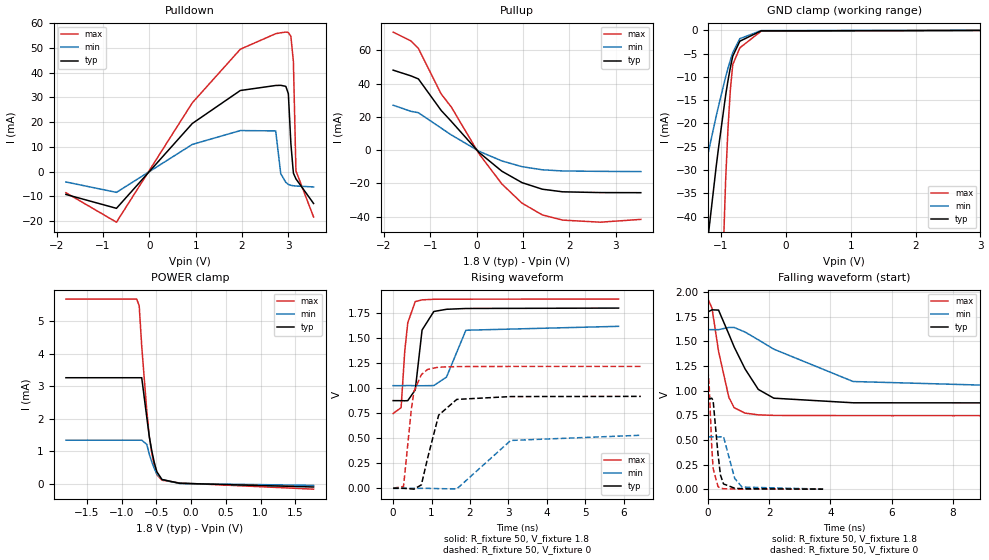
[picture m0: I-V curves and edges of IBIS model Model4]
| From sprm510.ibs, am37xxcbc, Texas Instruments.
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| Model based on original model for BQ18OMAPJTAGFBPBNOPM_SSBHV
|   Sub model AGFBPBNOPM_VJTAG_PU1_1P8
[model]   Model4
|[Input Load]   PU
|[Output Drive]
|Voltage   1.8V
|Mode   I/O
Model_type   I/O
Polarity   Non-Inverting
Enable   Active-Low
Vinl =  0.63
Vinh =  1.17
Cref =  15pF
Rref =  100.0000M
Vref =  0V
Vmeas =  0.9
C_comp   2.132351p   1.924211p   2.13513p
[Model Spec]
Vinl   0.63   0.567   0.6615
Vinh   1.17   1.053   1.2285
[Temperature Range]   25   125   -40
[Voltage Range]   1.8   1.62   1.89
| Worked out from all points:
|   slope of the pulldown table from 0 to 0.27 V, typ, clamps not added: 43.9 ohm
|   slope of the pullup table from 0 to 0.27 V, typ, clamps not added: 39.4 ohm
|   GND clamp passes 1 mA (typ) near -0.60 V on its own axis
|   POWER clamp passes 1 mA (typ) near -0.56 V on its own axis
|   rising waveform, R_fixture 50, V_fixture 1.8: 20-80 % time 173ps typ, 302ps min, 137ps max; typ from 0.877 V to 1.8 V
|   rising waveform, R_fixture 50, V_fixture 0: 20-80 % time 356ps typ, 726ps min, 202ps max; typ from 0.002 V to 0.919 V
|   falling waveform, R_fixture 50, V_fixture 1.8: 20-80 % time 894ps typ, 2.32ns min, 434ps max; typ from 1.8 V to 0.877 V
|   falling waveform, R_fixture 50, V_fixture 0: 20-80 % time 162ps typ, 255ps min, 107ps max; typ from 0.919 V to 0.002 V
[POWER_clamp]
-1.8V     3.257mA    1.34mA     5.672mA
-781.8mV  3.257mA    1.34mA     5.672mA
-745.5mV  3.257mA    1.34mA     5.469mA
-709.1mV  3.257mA    1.34mA     4.227mA
-636.4mV  2.042mA    1.213mA    2.249mA
-600mV    1.445mA    904.9uA    1.448mA
-563.6mV  1.004mA    669uA      930.8uA
-527.3mV  646uA      469.2uA    541.5uA
-490.9mV  370.3uA    305.7uA    280uA
-418.2mV  134uA      130.2uA    111.3uA
-163.6mV  16.99uA    9.907uA    26.3uA
1.764V    -96.73uA   -46.49uA   -163.5uA
[Pulldown]
-1.8V     -9.247mA   -4.208mA   -8.543mA
-709.1mV  -14.86mA   -8.413mA   -20.46mA
927.3mV   19.42mA    10.96mA    27.78mA
1.964V    32.76mA    16.57mA    49.44mA
2.727V    34.78mA    16.43mA    55.71mA
2.836V    34.85mA    -845.8uA   56.09mA
2.945V    34.44mA    -4.342mA   56.36mA
3V        31.5mA     -5.193mA   56.19mA
3.055V    11.25mA    -5.559mA   54.62mA
3.109V    -628.6uA   -5.735mA   44.43mA
3.164V    -2.953mA   -5.847mA   273.1uA
3.545V    -12.91mA   -6.213mA   -18.39mA
[Pullup]
-1.8V     48.03mA    26.96mA    70.92mA
-1.418V   44.61mA    23.28mA    65.63mA
-1.255V   42.76mA    22.44mA    61.09mA
-763.6mV  23.81mA    13.18mA    33.71mA
-545.5mV  17.24mA    9.103mA    25.87mA
54.55mV   -1.471mA   -757.8uA   -2.314mA
545.5mV   -12.73mA   -6.543mA   -20.39mA
981.8mV   -19.62mA   -10.01mA   -31.96mA
1.418V    -23.55mA   -11.89mA   -39.01mA
1.855V    -25.13mA   -12.59mA   -42.14mA
2.673V    -25.59mA   -12.83mA   -43.4mA
3.545V    -25.66mA   -12.97mA   -41.71mA
[GND_clamp]
-1.8V     -118.7mA   -65.68mA   -455.2mA
-1.509V   -82.26mA   -46.44mA   -309.2mA
-1.473V   -77.72mA   -44.04mA   -290.9mA
-1.073V   -29.19mA   -18.4mA    -94.45mA
-1.036V   -25.09mA   -16.2mA    -77.63mA
-927.3mV  -13.89mA   -9.97mA    -31.99mA
-890.9mV  -10.74mA   -8.111mA   -20.87mA
-854.5mV  -7.952mA   -6.381mA   -12.65mA
-818.2mV  -5.535mA   -4.78mA    -7.354mA
-709.1mV  -2.342mA   -1.793mA   -3.761mA
-381.8mV  -111.3uA   -60.58uA   -193uA
3.6V      0A         0A         0A
[Ramp]
dV/dt_f  0.5746399/0.9125157n  0.3697848/2.387573n   0.7100328/0.4338732n
dV/dt_r  0.5563546/0.3576548n  0.3227059/0.7351233n  0.7364765/0.2020738n
R_load = 50
[Rising Waveform]
R_fixture = 50
V_fixture = 1.8
V_fixture_min = 1.62
V_fixture_max = 1.89
0s        876.5mV    1.026V     747.7mV
207ps     876.2mV    1.026V     806.7mV
303ps     875.2mV    1.026V     1.372V
381ps     876.4mV    1.027V     1.654V
576ps     984.4mV    1.026V     1.865V
753ps     1.581V     1.025V     1.882V
1.059ns   1.766V     1.027V     1.888V
1.389ns   1.788V     1.112V     1.889V
1.893ns   1.796V     1.579V     1.889V
5.868ns   1.8V       1.618V     1.89V
[Rising Waveform]
R_fixture = 50
V_fixture = 0
V_fixture_min = 0
V_fixture_max = 0
0s        1.815mV    1.469mV    3.195mV
270ps     2.212mV    910.5uV    19.59mV
474ps     -4.257mV   1.476mV    791.6mV
543ps     -6.854mV   1.475mV    971.2mV
735ps     35.97mV    1.456mV    1.136V
897ps     302.6mV    1.234mV    1.188V
1.185ns   731.9mV    -1.57mV    1.211V
1.656ns   888.8mV    -4.47mV    1.216V
3.06ns    917.1mV    479.2mV    1.218V
6.447ns   918.9mV    531.1mV    1.218V
[Falling Waveform]
R_fixture = 50
V_fixture = 1.8
V_fixture_min = 1.62
V_fixture_max = 1.89
0s        1.8V       1.62V      1.93V
132ps     1.821V     1.62V      1.837V
345ps     1.818V     1.62V      1.401V
681ps     1.575V     1.642V     933.9mV
855ps     1.445V     1.642V     828.5mV
1.209ns   1.223V     1.596V     773.8mV
1.644ns   1.014V     1.517V     756mV
2.151ns   924.9mV    1.422V     750.5mV
4.743ns   878.3mV    1.094V     748mV
12.36ns   876.9mV    1.028V     748mV
[Falling Waveform]
R_fixture = 50
V_fixture = 0
V_fixture_min = 0
V_fixture_max = 0
0s        919.5mV    532.6mV    1.21V
39ps      918.8mV    532.6mV    1.056V
123ps     924.2mV    533.1mV    434.9mV
168ps     901.7mV    533.1mV    211.8mV
327ps     358.5mV    532.2mV    28.76mV
408ps     145.7mV    532.8mV    12.27mV
507ps     55.59mV    534.8mV    6.985mV
873ps     12.03mV    111.5mV    4.056mV
1.113ns   7.194mV    23.57mV    3.58mV
3.762ns   2.486mV    2.997mV    3.099mV
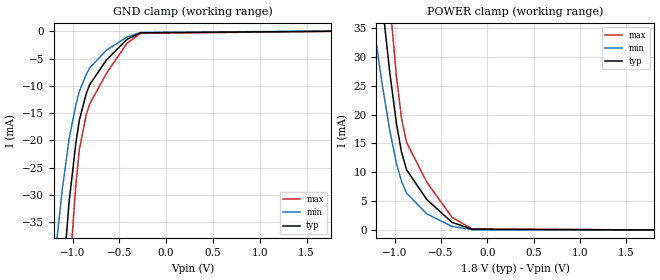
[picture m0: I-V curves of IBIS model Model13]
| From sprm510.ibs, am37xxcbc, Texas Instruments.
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| Model based on original model for CAMERARX_ADDON
|   Sub model CAMERARX_ADDON_PU_ON
[model]   Model13
|[Input Load]   PU
|[Output Drive]
|Voltage   1.8V
|Mode   INPUT
Model_type   Input
Polarity   Non-Inverting
Vinl =  0.63
Vinh =  1.17
C_comp   4.13955p   3.54298p   4.784869p
[Model Spec]
Vinl   0.63   0.567   0.6615
Vinh   1.17   1.053   1.2285
[Temperature Range]   25   125   -40
[Voltage Range]   1.8   1.62   1.92
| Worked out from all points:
|   GND clamp passes 1 mA (typ) near -0.38 V on its own axis
|   POWER clamp passes 1 mA (typ) near -0.35 V on its own axis
[POWER_clamp]
-1.8V     156.8mA    109.4mA    217.7mA
-1.255V   58.61mA    38.51mA    83.66mA
-1.145V   40.75mA    26.16mA    58.76mA
-1.127V   37.98mA    24.3mA     54.84mA
-1.055V   27.39mA    17.29mA    39.72mA
-981.8mV  18.38mA    11.52mA    26.53mA
-927.3mV  13.5mA     8.445mA    19.35mA
-872.7mV  10.44mA    6.378mA    15.17mA
-654.5mV  5.285mA    2.795mA    8.314mA
-381.8mV  1.322mA    633.7uA    2.193mA
-163.6mV  122.8uA    43.53uA    168.5uA
1.8V      2.655uA    1.447uA    5.48uA
[GND_clamp]
-1.8V     -252.1mA   -161mA     -379.9mA
-1.218V   -75mA      -46.17mA   -113.7mA
-1.109V   -46.69mA   -28.88mA   -69.61mA
-1.036V   -31.09mA   -19.64mA   -44.94mA
-963.6mV  -20.36mA   -13.4mA    -27.99mA
-927.3mV  -16.27mA   -11.01mA   -21.66mA
-854.5mV  -11.47mA   -7.931mA   -15.36mA
-818.2mV  -9.795mA   -6.755mA   -13.38mA
-636.4mV  -5.234mA   -3.435mA   -7.67mA
-418.2mV  -1.474mA   -1.064mA   -2.21mA
-272.7mV  -280.2uA   -224.3uA   -378.2uA
1.764V    -2.246uA   34.26uA    -17.44uA
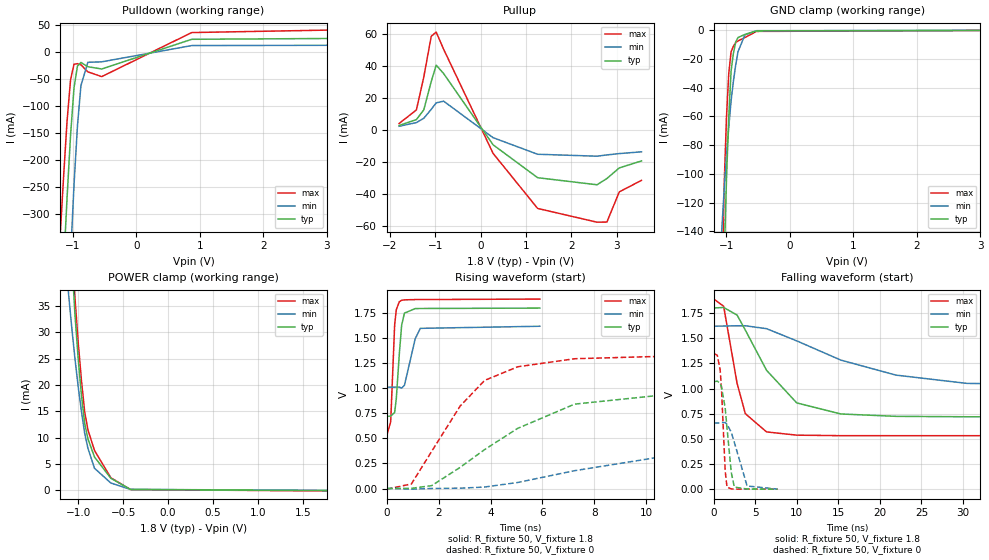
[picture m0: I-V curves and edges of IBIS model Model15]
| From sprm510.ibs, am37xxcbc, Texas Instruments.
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| Model based on original model for BQ18OMAPSMART1HYFBPBNOPM_SSBHH
|   Sub model NOPM_HS00L00_PU1_1P8
[model]   Model15
|[Input Load]   PU
|[Output Drive] SC00LB00
|Voltage   1.8V
|Mode   I/O
Model_type   I/O
Polarity   Non-Inverting
Enable   Active-Low
Vinl =  0.63
Vinh =  1.17
Cref =  15pF
Rref =  100.0000M
Vref =  0V
Vmeas =  0.9
C_comp   1.410688p   1.256095p   1.577871p
[Model Spec]
Vinl   0.63   0.567   0.6615
Vinh   1.17   1.053   1.2285
[Temperature Range]   25   125   -40
[Voltage Range]   1.8   1.62   1.89
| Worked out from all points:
|   slope of the pulldown table from 0 to 0.27 V, typ, clamps not added: 24.3 ohm
|   slope of the pullup table from 0 to 0.27 V, typ, clamps not added: 29.7 ohm
|   GND clamp passes 1 mA (typ) near -0.60 V on its own axis
|   POWER clamp passes 1 mA (typ) near -0.56 V on its own axis
|   rising waveform, R_fixture 50, V_fixture 1.8: 20-80 % time 176ps typ, 306ps min, 123ps max; typ from 0.72 V to 1.8 V
|   rising waveform, R_fixture 50, V_fixture 0: 20-80 % time 4.61ns typ, 10.6ns min, 2.28ns max; typ from 0.002 V to 1.07 V
|   falling waveform, R_fixture 50, V_fixture 1.8: 20-80 % time 4.91ns typ, 12.6ns min, 1.99ns max; typ from 1.8 V to 0.72 V
|   falling waveform, R_fixture 50, V_fixture 0: 20-80 % time 734ps typ, 1.23ns min, 446ps max; typ from 1.07 V to 0.002 V
[POWER_clamp]
-1.8V     362.5mA    191.4mA    412.8mA
-1.109V   56.76mA    37.74mA    60.51mA
-1.073V   44.67mA    31.25mA    47.93mA
-1.036V   33.52mA    25.07mA    36.72mA
-1V       25.06mA    19.75mA    28.2mA
-963.6mV  18.11mA    14.99mA    20.91mA
-927.3mV  12.67mA    10.8mA     14.87mA
-890.9mV  9.734mA    7.935mA    11.44mA
-818.2mV  6.293mA    4.153mA    7.536mA
-636.4mV  2.249mA    1.342mA    2.34mA
-418.2mV  128.7uA    129.3uA    104.4uA
1.764V    -96.73uA   -46.48uA   -163.5uA
[Pulldown]
-1.8V     -1.718A    -2.61A     -1.406A
-1.2V     -527.4mA   -844.5mA   -339.9mA
-1.145V   -396mA     -683.1mA   -229.1mA
-1.091V   -269mA     -526.7mA   -127.5mA
-1.036V   -153.6mA   -378.9mA   -51.17mA
-981.8mV  -66.33mA   -245.6mA   -22.67mA
-927.3mV  -26mA      -136.2mA   -21.54mA
-872.7mV  -19.34mA   -61.98mA   -23.69mA
-763.6mV  -27.2mA    -19.05mA   -36.72mA
-545.5mV  -31.39mA   -18.17mA   -45.46mA
872.7mV   23.46mA    11.88mA    35.92mA
3.545V    25.34mA    12.51mA    41.58mA
[Pullup]
-1.8V     2.903mA    2.423mA    4.112mA
-1.418V   6.595mA    4.711mA    12.64mA
-1.255V   12.69mA    7.42mA     33.24mA
-1.091V   30.4mA     13mA       58.69mA
-981.8mV  40.63mA    17.02mA    61.3mA
-818.2mV  35.38mA    18.12mA    50.59mA
272.7mV   -9.179mA   -4.728mA   -14.55mA
1.255V    -29.75mA   -15.09mA   -48.97mA
2.564V    -34.17mA   -16.31mA   -57.57mA
2.782V    -30.25mA   -15.5mA    -57.48mA
3.055V    -23.63mA   -14.68mA   -38.61mA
3.545V    -19.25mA   -13.56mA   -31.41mA
[GND_clamp]
-1.8V     -2.82A     -1.192A    -3.165A
-1.073V   -235.8mA   -138.4mA   -192.1mA
-1.036V   -159.6mA   -110.8mA   -107.6mA
-1V       -103.8mA   -87.86mA   -60.73mA
-963.6mV  -60.04mA   -67.29mA   -29.86mA
-927.3mV  -28.26mA   -49.09mA   -14.98mA
-890.9mV  -15.95mA   -35.49mA   -11.09mA
-854.5mV  -8.198mA   -24.09mA   -8.559mA
-818.2mV  -4.99mA    -14.87mA   -7.387mA
-709.1mV  -2.858mA   -3.093mA   -5.012mA
-527.3mV  -395.6uA   -260.4uA   -751.2uA
3.6V      0A         0A         0A
[Ramp]
dV/dt_f  0.6515024/4.918272n   0.3684169/12.66708n   0.8176591/1.98921n
dV/dt_r  0.6487164/4.619935n   0.3995157/10.69377n   0.8193791/2.289463n
R_load = 50
[Rising Waveform]
R_fixture = 50
V_fixture = 1.8
V_fixture_min = 1.62
V_fixture_max = 1.89
0s        720mV      1.011V     534.4mV
144ps     722.2mV    1.011V     666.2mV
297ps     758.3mV    1.011V     1.631V
360ps     894.2mV    1.012V     1.783V
477ps     1.342V     1.011V     1.863V
567ps     1.628V     1.001V     1.877V
675ps     1.749V     1.029V     1.881V
1.089ns   1.794V     1.492V     1.884V
1.287ns   1.795V     1.597V     1.884V
5.904ns   1.799V     1.618V     1.889V
[Rising Waveform]
R_fixture = 50
V_fixture = 0
V_fixture_min = 0
V_fixture_max = 0
0s        1.996mV    1.034mV    -5.726mV
945ps     2.248mV    -6.159mV   46.23mV
1.728ns   29mV       503.3uV    371.7mV
2.826ns   211.4mV    3.572mV    822.5mV
3.771ns   388.7mV    15.21mV    1.078V
5.049ns   600.2mV    60.39mV    1.214V
7.245ns   841.7mV    178.1mV    1.294V
14.15ns   1.026V     463.3mV    1.344V
23.34ns   1.062V     596.7mV    1.35V
67.5ns    1.069V     657.1mV    1.35V
[Falling Waveform]
R_fixture = 50
V_fixture = 1.8
V_fixture_min = 1.62
V_fixture_max = 1.89
0s        1.8V       1.62V      1.889V
1.188ns   1.806V     1.621V     1.818V
2.808ns   1.73V      1.624V     1.052V
3.798ns   1.581V     1.624V     751.3mV
6.354ns   1.182V     1.595V     570.2mV
9.99ns    858.2mV    1.474V     537.9mV
15.3ns    748.3mV    1.283V     532.9mV
21.94ns   724.8mV    1.134V     532.6mV
30.47ns   720.5mV    1.052V     532.6mV
62.9ns    720mV      1.012V     532.6mV
[Falling Waveform]
R_fixture = 50
V_fixture = 0
V_fixture_min = 0
V_fixture_max = 0
0s        1.069V     658.7mV    1.35V
432ps     1.074V     658.5mV    1.33V
765ps     1.052V     660.3mV    1.188V
927ps     1.019V     663.9mV    1.002V
1.377ns   805.3mV    662.4mV    180mV
1.593ns   611.4mV    647.3mV    22.62mV
2.106ns   168.8mV    566.8mV    4.547mV
2.475ns   22.28mV    466.6mV    3.177mV
4.014ns   3.278mV    33.24mV    2.159mV
7.677ns   1.791mV    2.593mV    1.84mV
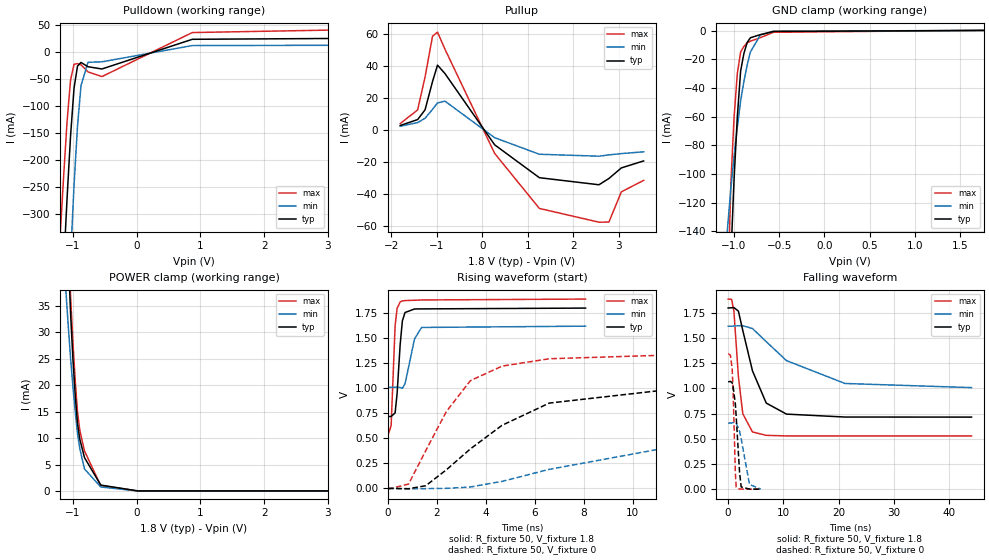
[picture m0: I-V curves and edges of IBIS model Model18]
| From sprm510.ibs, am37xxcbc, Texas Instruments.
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| Model based on original model for BQ18OMAPSMART1HYFBPBNOPM_SSBHH
|   Sub model NOPM_HS00L01_PD1_1P8
[model]   Model18
|[Input Load]   PD
|[Output Drive] SC00LB01
|Voltage   1.8V
|Mode   I/O
Model_type   I/O
Polarity   Non-Inverting
Enable   Active-Low
Vinl =  0.63
Vinh =  1.17
Cref =  15pF
Rref =  100.0000M
Vref =  0V
Vmeas =  0.9
C_comp   1.410688p   1.256095p   1.577871p
[Model Spec]
Vinl   0.63   0.567   0.6615
Vinh   1.17   1.053   1.2285
[Temperature Range]   25   125   -40
[Voltage Range]   1.8   1.62   1.89
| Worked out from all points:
|   slope of the pulldown table from 0 to 0.27 V, typ, clamps not added: 24.3 ohm
|   slope of the pullup table from 0 to 0.27 V, typ, clamps not added: 29.7 ohm
|   GND clamp passes 1 mA (typ) near -0.60 V on its own axis
|   POWER clamp passes 1 mA (typ) near -0.55 V on its own axis
|   rising waveform, R_fixture 50, V_fixture 1.8: 20-80 % time 177ps typ, 312ps min, 124ps max; typ from 0.715 V to 1.8 V
|   rising waveform, R_fixture 50, V_fixture 0: 20-80 % time 4.11ns typ, 9.41ns min, 2.06ns max; typ from 0.001 V to 1.06 V
|   falling waveform, R_fixture 50, V_fixture 1.8: 20-80 % time 3.36ns typ, 8.79ns min, 1.24ns max; typ from 1.8 V to 0.715 V
|   falling waveform, R_fixture 50, V_fixture 0: 20-80 % time 712ps typ, 1.2ns min, 410ps max; typ from 1.06 V to 0 V
[POWER_clamp]
-1.8V     362.5mA    191.4mA    412.8mA
-1.109V   56.75mA    37.73mA    60.5mA
-1.073V   44.66mA    31.25mA    47.93mA
-1.036V   33.51mA    25.07mA    36.73mA
-1V       25.06mA    19.75mA    28.2mA
-963.6mV  18.11mA    14.99mA    20.92mA
-927.3mV  12.68mA    10.81mA    14.88mA
-890.9mV  9.743mA    7.94mA     11.46mA
-818.2mV  6.308mA    4.161mA    7.567mA
-563.6mV  1.112mA    743.5uA    1.008mA
18.18mV   0A         0A         0A
3.6V      0A         0A         0A
[Pulldown]
-1.8V     -1.718A    -2.61A     -1.406A
-1.2V     -527.4mA   -844.5mA   -339.9mA
-1.145V   -396mA     -683.1mA   -229.1mA
-1.091V   -269mA     -526.7mA   -127.5mA
-1.036V   -153.6mA   -378.9mA   -51.17mA
-981.8mV  -66.33mA   -245.6mA   -22.67mA
-927.3mV  -26mA      -136.2mA   -21.54mA
-872.7mV  -19.34mA   -61.98mA   -23.69mA
-763.6mV  -27.2mA    -19.05mA   -36.72mA
-545.5mV  -31.39mA   -18.17mA   -45.46mA
872.7mV   23.46mA    11.88mA    35.92mA
3.545V    25.34mA    12.51mA    41.58mA
[Pullup]
-1.8V     2.903mA    2.423mA    4.112mA
-1.418V   6.595mA    4.711mA    12.64mA
-1.255V   12.69mA    7.42mA     33.24mA
-1.091V   30.4mA     13mA       58.69mA
-981.8mV  40.63mA    17.02mA    61.3mA
-818.2mV  35.38mA    18.12mA    50.59mA
272.7mV   -9.18mA    -4.728mA   -14.55mA
1.255V    -29.75mA   -15.09mA   -48.97mA
2.564V    -34.17mA   -16.31mA   -57.57mA
2.782V    -30.25mA   -15.5mA    -57.48mA
3.055V    -23.63mA   -14.68mA   -38.61mA
3.545V    -19.25mA   -13.56mA   -31.41mA
[GND_clamp]
-1.8V     -2.82A     -1.192A    -3.165A
-1.073V   -235.8mA   -138.4mA   -192.1mA
-1.036V   -159.6mA   -110.8mA   -107.6mA
-1V       -103.8mA   -87.86mA   -60.72mA
-963.6mV  -60.04mA   -67.29mA   -29.85mA
-927.3mV  -28.26mA   -49.1mA    -14.96mA
-890.9mV  -15.95mA   -35.5mA    -11.07mA
-854.5mV  -8.196mA   -24.09mA   -8.539mA
-818.2mV  -4.988mA   -14.87mA   -7.364mA
-709.1mV  -2.851mA   -3.095mA   -4.982mA
-563.6mV  -633.9uA   -437.8uA   -1.185mA
1.764V    107.4uA    58.81uA    171.2uA
[Ramp]
dV/dt_f  0.6526315/3.369885n   0.3693826/8.859099n   0.818574/1.242437n
dV/dt_r  0.6489843/4.119939n   0.3992363/9.491637n   0.8210471/2.063407n
R_load = 50
[Rising Waveform]
R_fixture = 50
V_fixture = 1.8
V_fixture_min = 1.62
V_fixture_max = 1.89
0s        715.4mV    1.007V     530.1mV
126ps     717.3mV    1.007V     627.3mV
288ps     752mV      1.007V     1.621V
369ps     944mV      1.009V     1.794V
495ps     1.436V     1.005V     1.859V
585ps     1.669V     997.8mV    1.869V
693ps     1.753V     1.041V     1.872V
1.08ns    1.788V     1.488V     1.875V
1.368ns   1.789V     1.604V     1.878V
8.073ns   1.797V     1.617V     1.887V
[Rising Waveform]
R_fixture = 50
V_fixture = 0
V_fixture_min = 0
V_fixture_max = 0
0s        604.6uV    68.6uV     -7.974mV
837ps     -3.335mV   -6.133mV   42.79mV
1.539ns   26.15mV    -2.748mV   375.6mV
2.385ns   185.5mV    376.8uV    767.3mV
3.366ns   393.8mV    13.56mV    1.074V
4.653ns   627.9mV    69.6mV     1.218V
6.588ns   850.1mV    189.4mV    1.292V
12.94ns   1.025V     474.1mV    1.34V
20.72ns   1.058V     594.1mV    1.346V
60.28ns   1.065V     654.3mV    1.346V
[Falling Waveform]
R_fixture = 50
V_fixture = 1.8
V_fixture_min = 1.62
V_fixture_max = 1.89
0s        1.798V     1.618V     1.887V
621ps     1.801V     1.618V     1.884V
1.035ns   1.803V     1.619V     1.77V
1.854ns   1.767V     1.622V     1.116V
2.646ns   1.575V     1.622V     749mV
4.392ns   1.175V     1.595V     568mV
6.885ns   854.4mV    1.464V     534.2mV
10.54ns   745mV      1.276V     528.6mV
21.12ns   716mV      1.049V     528.1mV
43.99ns   715.4mV    1.008V     528.1mV
[Falling Waveform]
R_fixture = 50
V_fixture = 0
V_fixture_min = 0
V_fixture_max = 0
0s        1.065V     655.9mV    1.346V
405ps     1.07V      655.7mV    1.331V
720ps     1.056V     656.9mV    1.195V
873ps     1.029V     659.8mV    1.015V
1.305ns   842.6mV    663.1mV    155.5mV
1.458ns   715.1mV    656.4mV    18.12mV
2.061ns   167.9mV    574.7mV    908.4uV
2.358ns   21.85mV    497.5mV    446.4uV
3.861ns   527.2uV    45.89mV    102.7uV
5.868ns   183.1uV    1.642mV    30.4uV
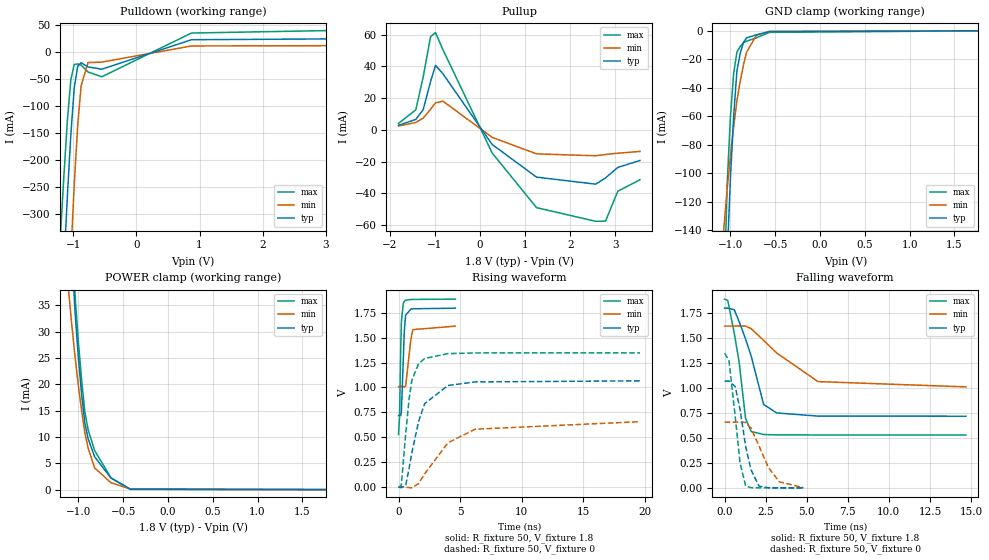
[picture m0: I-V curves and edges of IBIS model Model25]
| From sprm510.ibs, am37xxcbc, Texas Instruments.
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| Model based on original model for BQ18OMAPSMART1HYFBPBNOPM_SSBHH
|   Sub model PM_HS01L11_PUPD0_1P8
[model]   Model25
|[Input Load]   PI
|[Output Drive] SC01LB11
|Voltage   1.8V
|Mode   I/O
Model_type   I/O
Polarity   Non-Inverting
Enable   Active-Low
Vinl =  0.63
Vinh =  1.17
Cref =  15pF
Rref =  100.0000M
Vref =  0V
Vmeas =  0.9
C_comp   1.410688p   1.256095p   1.577871p
[Model Spec]
Vinl   0.63   0.567   0.6615
Vinh   1.17   1.053   1.2285
[Temperature Range]   25   125   -40
[Voltage Range]   1.8   1.62   1.89
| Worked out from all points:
|   slope of the pulldown table from 0 to 0.27 V, typ, clamps not added: 24.3 ohm
|   slope of the pullup table from 0 to 0.27 V, typ, clamps not added: 29.7 ohm
|   GND clamp passes 1 mA (typ) near -0.60 V on its own axis
|   POWER clamp passes 1 mA (typ) near -0.56 V on its own axis
|   rising waveform, R_fixture 50, V_fixture 1.8: 20-80 % time 174ps typ, 299ps min, 124ps max; typ from 0.718 V to 1.8 V
|   rising waveform, R_fixture 50, V_fixture 0: 20-80 % time 1.3ns typ, 2.86ns min, 687ps max; typ from 0 V to 1.07 V
|   falling waveform, R_fixture 50, V_fixture 1.8: 20-80 % time 1.1ns typ, 2.18ns min, 681ps max; typ from 1.8 V to 0.718 V
|   falling waveform, R_fixture 50, V_fixture 0: 20-80 % time 681ps typ, 1.11ns min, 499ps max; typ from 1.07 V to 0 V
[POWER_clamp]
-1.8V     362.5mA    191.4mA    412.8mA
-1.109V   56.69mA    37.71mA    60.38mA
-1.073V   44.6mA     31.22mA    47.8mA
-1.036V   33.44mA    25.04mA    36.59mA
-1V       24.98mA    19.72mA    28.06mA
-963.6mV  18.03mA    14.96mA    20.78mA
-927.3mV  12.59mA    10.77mA    14.74mA
-890.9mV  9.653mA    7.899mA    11.31mA
-818.2mV  6.214mA    4.114mA    7.414mA
-636.4mV  2.183mA    1.307mA    2.238mA
-418.2mV  83.85uA    105.2uA    35.14uA
1.764V    -1.228nA   -79.12nA   -1.453nA
[Pulldown]
-1.8V     -1.718A    -2.61A     -1.406A
-1.2V     -527.4mA   -844.5mA   -339.9mA
-1.145V   -396mA     -683.1mA   -229.1mA
-1.091V   -269mA     -526.7mA   -127.5mA
-1.036V   -153.6mA   -378.9mA   -51.17mA
-981.8mV  -66.34mA   -245.6mA   -22.67mA
-927.3mV  -26mA      -136.2mA   -21.54mA
-872.7mV  -19.34mA   -61.98mA   -23.69mA
-763.6mV  -27.2mA    -19.05mA   -36.72mA
-545.5mV  -31.39mA   -18.17mA   -45.46mA
872.7mV   23.46mA    11.88mA    35.92mA
3.545V    25.34mA    12.51mA    41.58mA
[Pullup]
-1.8V     2.903mA    2.423mA    4.112mA
-1.418V   6.595mA    4.711mA    12.64mA
-1.255V   12.69mA    7.42mA     33.23mA
-1.091V   30.4mA     13mA       58.69mA
-981.8mV  40.63mA    17.02mA    61.3mA
-818.2mV  35.38mA    18.12mA    50.59mA
272.7mV   -9.18mA    -4.728mA   -14.55mA
1.255V    -29.75mA   -15.09mA   -48.97mA
2.564V    -34.17mA   -16.31mA   -57.57mA
2.782V    -30.25mA   -15.5mA    -57.48mA
3.055V    -23.63mA   -14.68mA   -38.61mA
3.545V    -19.25mA   -13.56mA   -31.41mA
[GND_clamp]
-1.8V     -2.82A     -1.192A    -3.165A
-1.073V   -235.7mA   -138.4mA   -192.1mA
-1.036V   -159.5mA   -110.8mA   -107.5mA
-1V       -103.8mA   -87.85mA   -60.67mA
-963.6mV  -60mA      -67.28mA   -29.8mA
-927.3mV  -28.21mA   -49.08mA   -14.9mA
-890.9mV  -15.9mA    -35.48mA   -10.99mA
-854.5mV  -8.138mA   -24.07mA   -8.449mA
-818.2mV  -4.924mA   -14.85mA   -7.266mA
-709.1mV  -2.784mA   -3.064mA   -4.883mA
-563.6mV  -570.2uA   -404.5uA   -1.092mA
1.764V    -11.02pA   583.5nA    3.035nA
[Ramp]
dV/dt_f  0.6513344/1.098002n   0.3677355/2.193128n   0.8183624/0.6832765n
dV/dt_r  0.6509415/1.304449n   0.40075/2.881457n   0.8225269/0.6889139n
R_load = 50
[Rising Waveform]
R_fixture = 50
V_fixture = 1.8
V_fixture_min = 1.62
V_fixture_max = 1.89
0s        717.6mV    1.009V     526.6mV
81ps      719.3mV    1.009V     706.6mV
180ps     716.5mV    1.009V     1.412V
234ps     765.4mV    1.01V      1.664V
387ps     1.285V     1.01V      1.848V
468ps     1.57V      1.004V     1.867V
576ps     1.729V     1.014V     1.879V
1.008ns   1.79V      1.49V      1.886V
1.161ns   1.793V     1.583V     1.887V
4.617ns   1.799V     1.618V     1.89V
[Rising Waveform]
R_fixture = 50
V_fixture = 0
V_fixture_min = 0
V_fixture_max = 0
0s        181uV      76.19uV    -10.74mV
225ps     -9.775mV   -56.88uV   18.69mV
585ps     17.22mV    -3.882mV   536.5mV
855ps     185.7mV    -8.386mV   882.2mV
1.08ns    341mV      -10.18mV   1.073V
1.629ns   658.4mV    32.86mV    1.24V
2.124ns   837.2mV    129.8mV    1.292V
4.005ns   1.02V      442mV      1.341V
6.201ns   1.056V     579.8mV    1.348V
19.61ns   1.067V     655.8mV    1.349V
[Falling Waveform]
R_fixture = 50
V_fixture = 1.8
V_fixture_min = 1.62
V_fixture_max = 1.89
0s        1.8V       1.62V      1.89V
198ps     1.8V       1.62V      1.876V
594ps     1.783V     1.62V      1.545V
882ps     1.667V     1.621V     1.266V
1.278ns   1.49V      1.621V     695.5mV
1.62ns    1.32V      1.594V     564.1mV
2.376ns   835.5mV    1.477V     534.5mV
3.168ns   750.3mV    1.351V     530.5mV
5.688ns   718.8mV    1.064V     529.8mV
14.69ns   717.6mV    1.011V     529.8mV
[Falling Waveform]
R_fixture = 50
V_fixture = 0
V_fixture_min = 0
V_fixture_max = 0
0s        1.067V     657.3mV    1.349V
270ps     1.07V      657.4mV    1.274V
648ps     1.014V     657.7mV    714.4mV
945ps     783.4mV    661mV      246.6mV
1.287ns   411.9mV    654.3mV    16.83mV
1.611ns   179.5mV    598.2mV    1.783mV
2.097ns   17.35mV    418.7mV    219.2uV
2.664ns   1.506mV    205.7mV    23.15uV
3.33ns    333.1uV    60.45mV    2.904uV
4.806ns   48.53uV    1.651mV    443.5nV
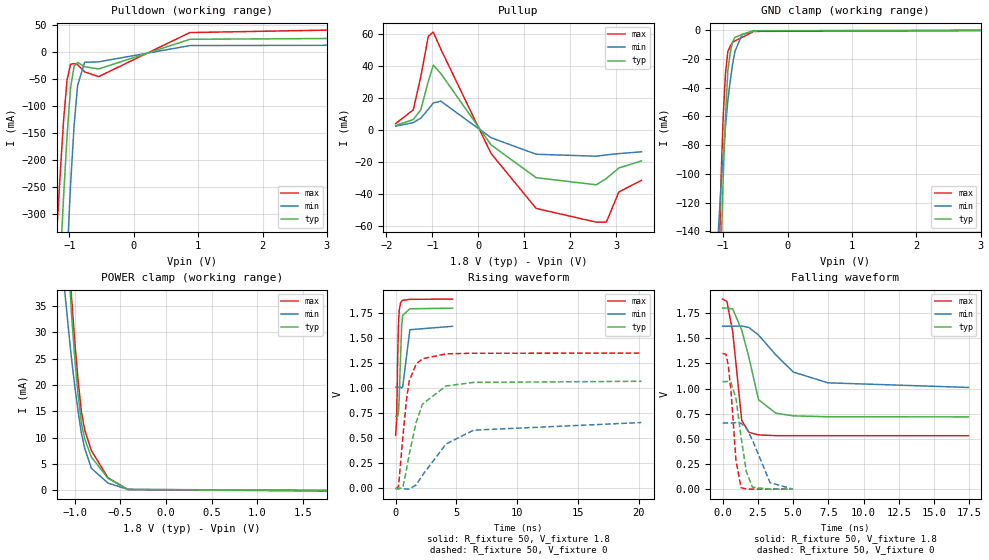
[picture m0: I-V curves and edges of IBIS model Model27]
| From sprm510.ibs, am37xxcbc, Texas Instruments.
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| Model based on original model for BQ18OMAPSMART1HYFBPBNOPM_SSBHH
|   Sub model NOPM_HS10L10_PU1_1P8
[model]   Model27
|[Input Load]   PU
|[Output Drive] SC10LB10
|Voltage   1.8V
|Mode   I/O
Model_type   I/O
Polarity   Non-Inverting
Enable   Active-Low
Vinl =  0.63
Vinh =  1.17
Cref =  15pF
Rref =  100.0000M
Vref =  0V
Vmeas =  0.9
C_comp   1.410688p   1.256095p   1.577871p
[Model Spec]
Vinl   0.63   0.567   0.6615
Vinh   1.17   1.053   1.2285
[Temperature Range]   25   125   -40
[Voltage Range]   1.8   1.62   1.89
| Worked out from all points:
|   slope of the pulldown table from 0 to 0.27 V, typ, clamps not added: 24.3 ohm
|   slope of the pullup table from 0 to 0.27 V, typ, clamps not added: 29.7 ohm
|   GND clamp passes 1 mA (typ) near -0.60 V on its own axis
|   POWER clamp passes 1 mA (typ) near -0.56 V on its own axis
|   rising waveform, R_fixture 50, V_fixture 1.8: 20-80 % time 176ps typ, 303ps min, 124ps max; typ from 0.72 V to 1.8 V
|   rising waveform, R_fixture 50, V_fixture 0: 20-80 % time 1.34ns typ, 2.95ns min, 707ps max; typ from 0.002 V to 1.07 V
|   falling waveform, R_fixture 50, V_fixture 1.8: 20-80 % time 1.05ns typ, 2.68ns min, 600ps max; typ from 1.8 V to 0.72 V
|   falling waveform, R_fixture 50, V_fixture 0: 20-80 % time 611ps typ, 1.04ns min, 434ps max; typ from 1.07 V to 0.001 V
[POWER_clamp]
-1.8V     362.5mA    191.4mA    412.8mA
-1.109V   56.76mA    37.74mA    60.51mA
-1.073V   44.67mA    31.25mA    47.93mA
-1.036V   33.52mA    25.07mA    36.72mA
-1V       25.06mA    19.75mA    28.2mA
-963.6mV  18.11mA    14.99mA    20.91mA
-927.3mV  12.67mA    10.8mA     14.87mA
-890.9mV  9.734mA    7.935mA    11.44mA
-818.2mV  6.293mA    4.153mA    7.536mA
-636.4mV  2.249mA    1.342mA    2.34mA
-418.2mV  128.7uA    129.3uA    104.4uA
1.764V    -96.73uA   -46.48uA   -163.5uA
[Pulldown]
-1.8V     -1.718A    -2.61A     -1.406A
-1.2V     -527.4mA   -844.5mA   -339.9mA
-1.145V   -396mA     -683.1mA   -229.1mA
-1.091V   -269mA     -526.7mA   -127.5mA
-1.036V   -153.6mA   -378.9mA   -51.17mA
-981.8mV  -66.33mA   -245.6mA   -22.67mA
-927.3mV  -26mA      -136.2mA   -21.54mA
-872.7mV  -19.34mA   -61.98mA   -23.69mA
-763.6mV  -27.2mA    -19.05mA   -36.72mA
-545.5mV  -31.39mA   -18.17mA   -45.46mA
872.7mV   23.46mA    11.88mA    35.92mA
3.545V    25.34mA    12.51mA    41.58mA
[Pullup]
-1.8V     2.903mA    2.423mA    4.112mA
-1.418V   6.595mA    4.711mA    12.64mA
-1.255V   12.69mA    7.42mA     33.24mA
-1.091V   30.4mA     13mA       58.69mA
-981.8mV  40.63mA    17.02mA    61.3mA
-818.2mV  35.38mA    18.12mA    50.59mA
272.7mV   -9.179mA   -4.728mA   -14.55mA
1.255V    -29.75mA   -15.09mA   -48.97mA
2.564V    -34.17mA   -16.31mA   -57.57mA
2.782V    -30.25mA   -15.5mA    -57.49mA
3.055V    -23.63mA   -14.68mA   -38.61mA
3.545V    -19.25mA   -13.56mA   -31.41mA
[GND_clamp]
-1.8V     -2.82A     -1.192A    -3.165A
-1.073V   -235.8mA   -138.4mA   -192.1mA
-1.036V   -159.6mA   -110.8mA   -107.6mA
-1V       -103.8mA   -87.86mA   -60.73mA
-963.6mV  -60.04mA   -67.29mA   -29.86mA
-927.3mV  -28.26mA   -49.09mA   -14.98mA
-890.9mV  -15.95mA   -35.49mA   -11.09mA
-854.5mV  -8.198mA   -24.09mA   -8.559mA
-818.2mV  -4.99mA    -14.87mA   -7.387mA
-709.1mV  -2.858mA   -3.093mA   -5.012mA
-527.3mV  -395.6uA   -260.4uA   -751.2uA
3.6V      0A         0A         0A
[Ramp]
dV/dt_f  0.6500597/1.055823n   0.3672318/2.702213n   0.8167084/0.6017297n
dV/dt_r  0.6498501/1.344021n   0.4003976/2.97874n   0.8204678/0.7078036n
R_load = 50
[Rising Waveform]
R_fixture = 50
V_fixture = 1.8
V_fixture_min = 1.62
V_fixture_max = 1.89
0s        720mV      1.011V     529.8mV
81ps      722mV      1.011V     703.1mV
180ps     718.4mV    1.011V     1.398V
225ps     754.8mV    1.011V     1.629V
288ps     892mV      1.012V     1.775V
396ps     1.309V     1.011V     1.851V
495ps     1.626V     1.002V     1.87V
576ps     1.727V     1.015V     1.878V
1.17ns    1.793V     1.584V     1.887V
4.68ns    1.799V     1.618V     1.89V
[Rising Waveform]
R_fixture = 50
V_fixture = 0
V_fixture_min = 0
V_fixture_max = 0
0s        1.548mV    1.043mV    -8.236mV
234ps     -7.992mV   914.9uV    20.48mV
603ps     19.13mV    -3.227mV   529.2mV
882ps     183.1mV    -7.074mV   878.3mV
1.116ns   339.3mV    -7.601mV   1.073V
1.683ns   658mV      33.99mV    1.241V
2.205ns   840.8mV    131.6mV    1.294V
4.14ns    1.022V     442.3mV    1.343V
6.408ns   1.058V     580.9mV    1.349V
20.23ns   1.069V     657.1mV    1.35V
[Falling Waveform]
R_fixture = 50
V_fixture = 1.8
V_fixture_min = 1.62
V_fixture_max = 1.89
0s        1.8V       1.62V      1.89V
306ps     1.801V     1.62V      1.867V
720ps     1.792V     1.62V      1.564V
1.359ns   1.581V     1.623V     683.9mV
1.872ns   1.308V     1.607V     566.2mV
2.547ns   890.3mV    1.533V     540.3mV
3.78ns    755.7mV    1.335V     533.2mV
5.013ns   729.9mV    1.165V     532.7mV
7.461ns   720.7mV    1.058V     532.6mV
17.42ns   720mV      1.012V     532.6mV
[Falling Waveform]
R_fixture = 50
V_fixture = 0
V_fixture_min = 0
V_fixture_max = 0
0s        1.069V     658.6mV    1.35V
243ps     1.07V      658.7mV    1.342V
396ps     1.072V     658.6mV    1.24V
594ps     1.06V      658.9mV    982mV
954ps     902.2mV    662.2mV    282.8mV
1.314ns   517mV      655.5mV    16.44mV
1.683ns   176.8mV    612.3mV    3.354mV
2.115ns   20.86mV    489.1mV    2.059mV
3.366ns   1.814mV    66.92mV    1.781mV
4.977ns   1.453mV    2.599mV    1.773mV
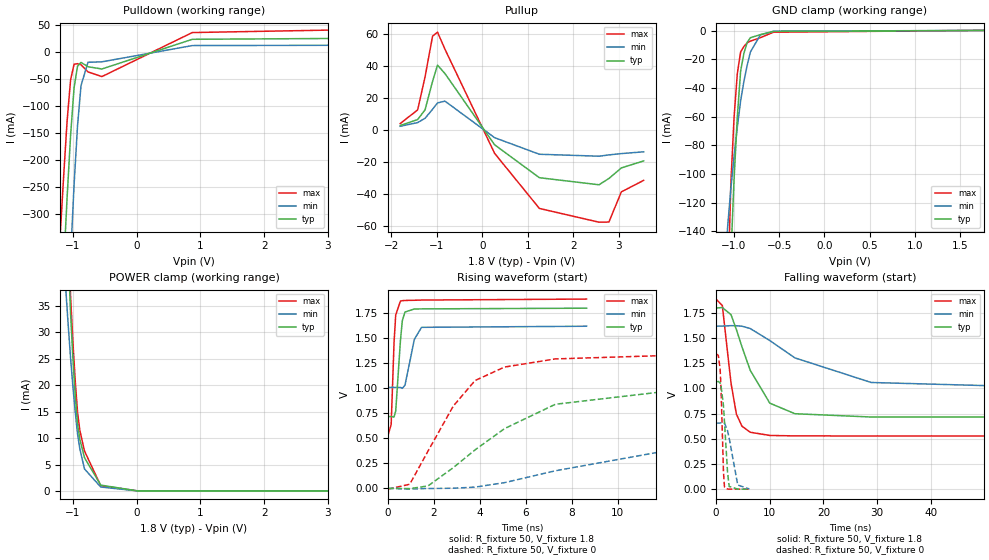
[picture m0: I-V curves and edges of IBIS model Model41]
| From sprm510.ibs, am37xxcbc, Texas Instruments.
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| Model based on original model for BQ18OMAPSMART1HYFBPB_SSBHH
|   Sub model FBPB_HS00L00_PD1_1P8
[model]   Model41
|[Input Load]   PD
|[Output Drive] SC00LB00
|Voltage   1.8V
|Mode   I/O
Model_type   I/O
Polarity   Non-Inverting
Enable   Active-Low
Vinl =  0.63
Vinh =  1.17
Cref =  15pF
Rref =  100.0000M
Vref =  0V
Vmeas =  0.9
C_comp   1.429432p   1.270657p   1.602015p
[Model Spec]
Vinl   0.63   0.567   0.6615
Vinh   1.17   1.053   1.2285
[Temperature Range]   25   125   -40
[Voltage Range]   1.8   1.62   1.89
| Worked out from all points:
|   slope of the pulldown table from 0 to 0.27 V, typ, clamps not added: 24.3 ohm
|   slope of the pullup table from 0 to 0.27 V, typ, clamps not added: 29.7 ohm
|   GND clamp passes 1 mA (typ) near -0.60 V on its own axis
|   POWER clamp passes 1 mA (typ) near -0.55 V on its own axis
|   rising waveform, R_fixture 50, V_fixture 1.8: 20-80 % time 178ps typ, 319ps min, 125ps max; typ from 0.716 V to 1.8 V
|   rising waveform, R_fixture 50, V_fixture 0: 20-80 % time 4.62ns typ, 10.6ns min, 2.3ns max; typ from 0 V to 1.06 V
|   falling waveform, R_fixture 50, V_fixture 1.8: 20-80 % time 4.89ns typ, 12.6ns min, 1.98ns max; typ from 1.8 V to 0.716 V
|   falling waveform, R_fixture 50, V_fixture 0: 20-80 % time 731ps typ, 1.23ns min, 444ps max; typ from 1.06 V to 0 V
[POWER_clamp]
-1.8V     362.5mA    191.4mA    412.8mA
-1.109V   56.74mA    37.73mA    60.49mA
-1.073V   44.66mA    31.25mA    47.92mA
-1.036V   33.51mA    25.07mA    36.71mA
-1V       25.05mA    19.75mA    28.19mA
-963.6mV  18.1mA     14.99mA    20.91mA
-927.3mV  12.67mA    10.8mA     14.87mA
-890.9mV  9.735mA    7.937mA    11.45mA
-818.2mV  6.3mA      4.158mA    7.553mA
-563.6mV  1.102mA    739.7uA    992.8uA
18.18mV   0A         0A         0A
3.6V      0A         0A         0A
[Pulldown]
-1.8V     -1.718A    -2.61A     -1.406A
-1.2V     -527.4mA   -844.5mA   -339.9mA
-1.145V   -396mA     -683.1mA   -229.1mA
-1.091V   -269mA     -526.7mA   -127.5mA
-1.036V   -153.6mA   -378.9mA   -51.17mA
-981.8mV  -66.33mA   -245.6mA   -22.67mA
-927.3mV  -26mA      -136.2mA   -21.54mA
-872.7mV  -19.34mA   -61.98mA   -23.69mA
-763.6mV  -27.2mA    -19.05mA   -36.72mA
-545.5mV  -31.39mA   -18.17mA   -45.46mA
872.7mV   23.46mA    11.88mA    35.92mA
3.545V    25.34mA    12.51mA    41.58mA
[Pullup]
-1.8V     2.903mA    2.423mA    4.112mA
-1.418V   6.595mA    4.711mA    12.64mA
-1.255V   12.69mA    7.42mA     33.24mA
-1.091V   30.4mA     13mA       58.69mA
-981.8mV  40.63mA    17.02mA    61.3mA
-818.2mV  35.38mA    18.12mA    50.59mA
272.7mV   -9.18mA    -4.728mA   -14.55mA
1.255V    -29.75mA   -15.09mA   -48.97mA
2.564V    -34.17mA   -16.31mA   -57.57mA
2.782V    -30.25mA   -15.5mA    -57.48mA
3.055V    -23.63mA   -14.68mA   -38.61mA
3.545V    -19.25mA   -13.56mA   -31.41mA
[GND_clamp]
-1.8V     -2.82A     -1.192A    -3.165A
-1.073V   -235.8mA   -138.4mA   -192.1mA
-1.036V   -159.6mA   -110.8mA   -107.6mA
-1V       -103.8mA   -87.86mA   -60.71mA
-963.6mV  -60.04mA   -67.29mA   -29.85mA
-927.3mV  -28.26mA   -49.1mA    -14.96mA
-890.9mV  -15.95mA   -35.5mA    -11.07mA
-854.5mV  -8.194mA   -24.09mA   -8.535mA
-818.2mV  -4.986mA   -14.87mA   -7.361mA
-709.1mV  -2.849mA   -3.094mA   -4.979mA
-563.6mV  -632.2uA   -437.1uA   -1.183mA
1.764V    97.78uA    55.01uA    156.3uA
[Ramp]
dV/dt_f  0.6528999/4.902843n   0.3694138/12.67613n   0.8189601/1.978507n
dV/dt_r  0.6487318/4.634534n   0.3990627/10.71348n   0.8206016/2.303636n
R_load = 50
[Rising Waveform]
R_fixture = 50
V_fixture = 1.8
V_fixture_min = 1.62
V_fixture_max = 1.89
0s        715.6mV    1.007V     530.1mV
135ps     716.4mV    1.007V     637.5mV
261ps     711.4mV    1.007V     1.455V
333ps     771.2mV    1.007V     1.73V
540ps     1.477V     1.007V     1.868V
621ps     1.673V     997.6mV    1.872V
738ps     1.759V     1.029V     1.874V
1.143ns   1.789V     1.485V     1.876V
1.458ns   1.79V      1.606V     1.878V
8.649ns   1.797V     1.617V     1.888V
[Rising Waveform]
R_fixture = 50
V_fixture = 0
V_fixture_min = 0
V_fixture_max = 0
0s        222.3uV    103.3uV    -8.318mV
945ps     -2.665mV   -6.876mV   40.85mV
1.737ns   23.64mV    -1.921mV   370.4mV
2.844ns   206.9mV    1.091mV    821.6mV
3.789ns   383.7mV    12.24mV    1.075V
5.076ns   596.1mV    56.92mV    1.21V
7.29ns    838.7mV    175.3mV    1.291V
14.22ns   1.023V     460.9mV    1.34V
23.42ns   1.058V     594.1mV    1.346V
67.49ns   1.065V     654.4mV    1.346V
[Falling Waveform]
R_fixture = 50
V_fixture = 1.8
V_fixture_min = 1.62
V_fixture_max = 1.89
0s        1.798V     1.618V     1.887V
1.179ns   1.803V     1.619V     1.823V
2.799ns   1.732V     1.623V     1.052V
3.798ns   1.584V     1.622V     745.3mV
4.824ns   1.414V     1.618V     625.7mV
6.363ns   1.181V     1.595V     565.1mV
10.01ns   853.8mV    1.475V     533.4mV
14.69ns   748.9mV    1.303V     528.7mV
28.88ns   716.3mV    1.059V     528.2mV
63.09ns   715.5mV    1.009V     528.2mV
[Falling Waveform]
R_fixture = 50
V_fixture = 0
V_fixture_min = 0
V_fixture_max = 0
0s        1.065V     656mV      1.346V
441ps     1.069V     656mV      1.327V
774ps     1.055V     656.3mV    1.189V
936ps     1.027V     658.7mV    1.006V
1.395ns   827.9mV    663.6mV    168.1mV
1.584ns   665.9mV    655.2mV    19.32mV
2.151ns   168.9mV    580.4mV    1.152mV
2.457ns   27.27mV    506.2mV    560.3uV
4.05ns    689.8uV    41.17mV    161.8uV
6.228ns   243.5uV    1.64mV     62.44uV
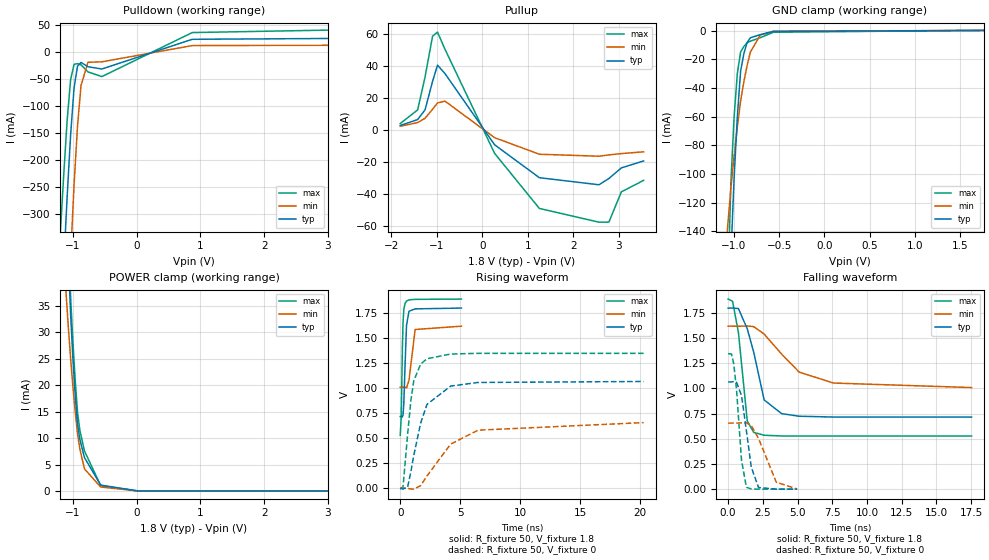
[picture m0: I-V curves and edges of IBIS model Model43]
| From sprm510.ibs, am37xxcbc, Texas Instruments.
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| Model based on original model for BQ18OMAPSMART1HYFBPB_SSBHH
|   Sub model FBPB_HS10L10_PD1_1P8
[model]   Model43
|[Input Load]   PD
|[Output Drive] SC10LB10
|Voltage   1.8V
|Mode   I/O
Model_type   I/O
Polarity   Non-Inverting
Enable   Active-Low
Vinl =  0.63
Vinh =  1.17
Cref =  15pF
Rref =  100.0000M
Vref =  0V
Vmeas =  0.9
C_comp   1.429432p   1.270657p   1.602015p
[Model Spec]
Vinl   0.63   0.567   0.6615
Vinh   1.17   1.053   1.2285
[Temperature Range]   25   125   -40
[Voltage Range]   1.8   1.62   1.89
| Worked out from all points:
|   slope of the pulldown table from 0 to 0.27 V, typ, clamps not added: 24.3 ohm
|   slope of the pullup table from 0 to 0.27 V, typ, clamps not added: 29.7 ohm
|   GND clamp passes 1 mA (typ) near -0.60 V on its own axis
|   POWER clamp passes 1 mA (typ) near -0.55 V on its own axis
|   rising waveform, R_fixture 50, V_fixture 1.8: 20-80 % time 178ps typ, 309ps min, 126ps max; typ from 0.715 V to 1.8 V
|   rising waveform, R_fixture 50, V_fixture 0: 20-80 % time 1.34ns typ, 2.95ns min, 710ps max; typ from 0 V to 1.06 V
|   falling waveform, R_fixture 50, V_fixture 1.8: 20-80 % time 1.05ns typ, 2.67ns min, 600ps max; typ from 1.8 V to 0.716 V
|   falling waveform, R_fixture 50, V_fixture 0: 20-80 % time 610ps typ, 1.04ns min, 434ps max; typ from 1.06 V to 0 V
[POWER_clamp]
-1.8V     362.5mA    191.4mA    412.8mA
-1.109V   56.74mA    37.73mA    60.49mA
-1.073V   44.66mA    31.25mA    47.92mA
-1.036V   33.51mA    25.07mA    36.71mA
-1V       25.05mA    19.75mA    28.19mA
-963.6mV  18.1mA     14.99mA    20.91mA
-927.3mV  12.67mA    10.8mA     14.87mA
-890.9mV  9.735mA    7.937mA    11.45mA
-818.2mV  6.3mA      4.158mA    7.553mA
-563.6mV  1.102mA    739.7uA    992.8uA
18.18mV   0A         0A         0A
3.6V      0A         0A         0A
[Pulldown]
-1.8V     -1.718A    -2.61A     -1.406A
-1.2V     -527.4mA   -844.5mA   -339.9mA
-1.145V   -396mA     -683.1mA   -229.1mA
-1.091V   -269mA     -526.7mA   -127.5mA
-1.036V   -153.6mA   -378.9mA   -51.17mA
-981.8mV  -66.33mA   -245.6mA   -22.67mA
-927.3mV  -26mA      -136.2mA   -21.54mA
-872.7mV  -19.34mA   -61.98mA   -23.69mA
-763.6mV  -27.2mA    -19.05mA   -36.72mA
-545.5mV  -31.39mA   -18.17mA   -45.46mA
872.7mV   23.46mA    11.88mA    35.92mA
3.545V    25.34mA    12.51mA    41.58mA
[Pullup]
-1.8V     2.903mA    2.423mA    4.112mA
-1.418V   6.595mA    4.711mA    12.64mA
-1.255V   12.69mA    7.42mA     33.24mA
-1.091V   30.4mA     13mA       58.69mA
-981.8mV  40.63mA    17.02mA    61.3mA
-818.2mV  35.38mA    18.12mA    50.59mA
272.7mV   -9.18mA    -4.728mA   -14.55mA
1.255V    -29.75mA   -15.09mA   -48.97mA
2.564V    -34.17mA   -16.31mA   -57.57mA
2.782V    -30.25mA   -15.5mA    -57.49mA
3.055V    -23.63mA   -14.68mA   -38.61mA
3.545V    -19.25mA   -13.56mA   -31.41mA
[GND_clamp]
-1.8V     -2.82A     -1.192A    -3.165A
-1.073V   -235.8mA   -138.4mA   -192.1mA
-1.036V   -159.6mA   -110.8mA   -107.6mA
-1V       -103.8mA   -87.86mA   -60.71mA
-963.6mV  -60.04mA   -67.29mA   -29.85mA
-927.3mV  -28.26mA   -49.1mA    -14.96mA
-890.9mV  -15.95mA   -35.5mA    -11.07mA
-854.5mV  -8.194mA   -24.09mA   -8.535mA
-818.2mV  -4.986mA   -14.87mA   -7.361mA
-709.1mV  -2.849mA   -3.094mA   -4.979mA
-563.6mV  -632.2uA   -437.1uA   -1.183mA
1.764V    97.78uA    55.01uA    156.3uA
[Ramp]
dV/dt_f  0.6516543/1.052908n   0.3684908/2.697969n   0.8181137/0.6017919n
dV/dt_r  0.6497788/1.347136n   0.3999467/2.981013n   0.8215389/0.7117452n
R_load = 50
[Rising Waveform]
R_fixture = 50
V_fixture = 1.8
V_fixture_min = 1.62
V_fixture_max = 1.89
0s        715.2mV    1.007V     526.9mV
81ps      716.8mV    1.007V     709.3mV
180ps     709.8mV    1.007V     1.404V
234ps     733.8mV    1.007V     1.655V
297ps     843.3mV    1.007V     1.781V
396ps     1.205V     1.009V     1.843V
522ps     1.624V     1V         1.868V
729ps     1.766V     1.077V     1.88V
1.242ns   1.79V      1.584V     1.885V
5.094ns   1.798V     1.617V     1.888V
[Rising Waveform]
R_fixture = 50
V_fixture = 0
V_fixture_min = 0
V_fixture_max = 0
0s        -197uV     102.1uV    -10.29mV
234ps     -8.542mV   -227.2uV   13.5mV
612ps     8.724mV    -2.778mV   532.7mV
891ps     167mV      -8.012mV   878.7mV
1.125ns   323.6mV    -10.52mV   1.071V
1.701ns   649.2mV    25.47mV    1.239V
2.232ns   836.4mV    121.8mV    1.292V
4.203ns   1.019V     439.6mV    1.339V
6.48ns    1.055V     578.4mV    1.346V
20.29ns   1.065V     654.4mV    1.346V
[Falling Waveform]
R_fixture = 50
V_fixture = 1.8
V_fixture_min = 1.62
V_fixture_max = 1.89
0s        1.798V     1.619V     1.888V
315ps     1.799V     1.619V     1.867V
738ps     1.794V     1.618V     1.558V
1.377ns   1.592V     1.621V     675.6mV
1.845ns   1.358V     1.614V     563.8mV
2.592ns   886.2mV    1.54V      535.3mV
3.852ns   749.9mV    1.341V     528.7mV
5.112ns   724.4mV    1.163V     528.2mV
7.578ns   716.2mV    1.054V     528.2mV
17.53ns   715.5mV    1.009V     528.2mV
[Falling Waveform]
R_fixture = 50
V_fixture = 0
V_fixture_min = 0
V_fixture_max = 0
0s        1.065V     656mV      1.346V
243ps     1.065V     656.2mV    1.342V
405ps     1.069V     656mV      1.242V
603ps     1.062V     656mV      986.9mV
963ps     929.1mV    658.4mV    286.4mV
1.314ns   579.6mV    657.9mV    18.68mV
1.665ns   218.6mV    632mV      1.694mV
2.187ns   16.38mV    503.9mV    208.7uV
3.465ns   351uV      68.92mV    5.84uV
4.968ns   58.74uV    1.649mV    709.4nV
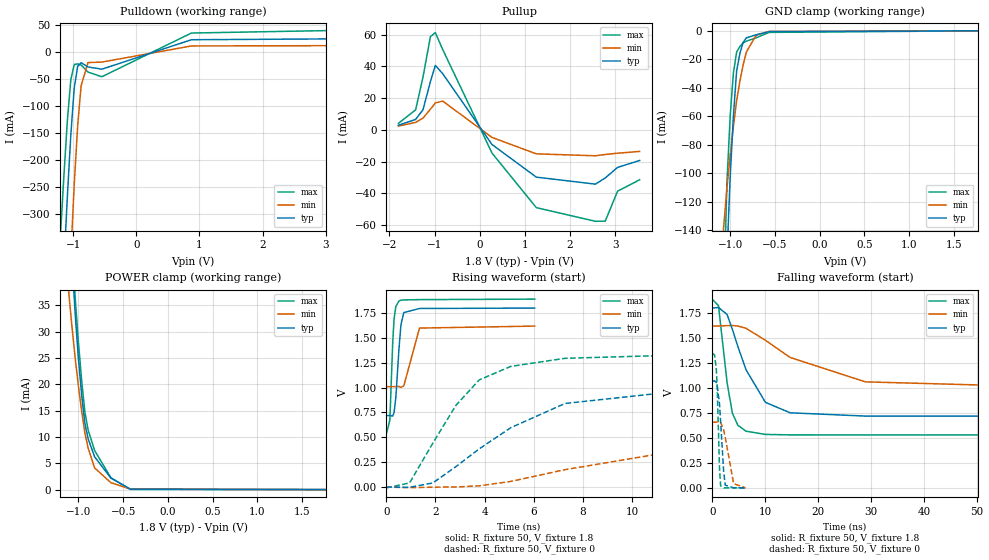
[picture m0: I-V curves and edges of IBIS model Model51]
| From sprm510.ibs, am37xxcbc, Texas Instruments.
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| Model based on original model for BQ18OMAPSMART1HYFBPB_SSBHH
|   Sub model PB_HS00L00_PUPD0_1P8
[model]   Model51
|[Input Load]   PI
|[Output Drive] SC00LB00
|Voltage   1.8V
|Mode   I/O
Model_type   I/O
Polarity   Non-Inverting
Enable   Active-Low
Vinl =  0.63
Vinh =  1.17
Cref =  15pF
Rref =  100.0000M
Vref =  0V
Vmeas =  0.9
C_comp   1.429432p   1.270657p   1.602015p
[Model Spec]
Vinl   0.63   0.567   0.6615
Vinh   1.17   1.053   1.2285
[Temperature Range]   25   125   -40
[Voltage Range]   1.8   1.62   1.89
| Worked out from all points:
|   slope of the pulldown table from 0 to 0.27 V, typ, clamps not added: 24.3 ohm
|   slope of the pullup table from 0 to 0.27 V, typ, clamps not added: 29.7 ohm
|   GND clamp passes 1 mA (typ) near -0.60 V on its own axis
|   POWER clamp passes 1 mA (typ) near -0.56 V on its own axis
|   rising waveform, R_fixture 50, V_fixture 1.8: 20-80 % time 177ps typ, 310ps min, 124ps max; typ from 0.718 V to 1.8 V
|   rising waveform, R_fixture 50, V_fixture 0: 20-80 % time 4.61ns typ, 10.6ns min, 2.29ns max; typ from 0 V to 1.07 V
|   falling waveform, R_fixture 50, V_fixture 1.8: 20-80 % time 4.9ns typ, 12.6ns min, 1.98ns max; typ from 1.8 V to 0.718 V
|   falling waveform, R_fixture 50, V_fixture 0: 20-80 % time 732ps typ, 1.23ns min, 445ps max; typ from 1.07 V to 0 V
[POWER_clamp]
-1.8V     362.5mA    191.4mA    412.8mA
-1.109V   56.69mA    37.71mA    60.38mA
-1.073V   44.6mA     31.22mA    47.8mA
-1.036V   33.44mA    25.04mA    36.59mA
-1V       24.98mA    19.72mA    28.06mA
-963.6mV  18.03mA    14.96mA    20.78mA
-927.3mV  12.59mA    10.77mA    14.74mA
-890.9mV  9.653mA    7.899mA    11.31mA
-818.2mV  6.214mA    4.114mA    7.414mA
-636.4mV  2.183mA    1.307mA    2.238mA
-418.2mV  83.85uA    105.2uA    35.14uA
1.764V    -1.228nA   -79.12nA   -1.453nA
[Pulldown]
-1.8V     -1.718A    -2.61A     -1.406A
-1.2V     -527.4mA   -844.5mA   -339.9mA
-1.145V   -396mA     -683.1mA   -229.1mA
-1.091V   -269mA     -526.7mA   -127.5mA
-1.036V   -153.6mA   -378.9mA   -51.17mA
-981.8mV  -66.34mA   -245.6mA   -22.67mA
-927.3mV  -26mA      -136.2mA   -21.54mA
-872.7mV  -19.34mA   -61.98mA   -23.69mA
-763.6mV  -27.2mA    -19.05mA   -36.72mA
-545.5mV  -31.39mA   -18.17mA   -45.46mA
872.7mV   23.46mA    11.88mA    35.92mA
3.545V    25.34mA    12.51mA    41.58mA
[Pullup]
-1.8V     2.903mA    2.423mA    4.112mA
-1.418V   6.595mA    4.711mA    12.64mA
-1.255V   12.69mA    7.42mA     33.23mA
-1.091V   30.4mA     13mA       58.69mA
-981.8mV  40.63mA    17.02mA    61.3mA
-818.2mV  35.38mA    18.12mA    50.59mA
272.7mV   -9.18mA    -4.728mA   -14.55mA
1.255V    -29.75mA   -15.09mA   -48.97mA
2.564V    -34.17mA   -16.31mA   -57.57mA
2.782V    -30.25mA   -15.5mA    -57.48mA
3.055V    -23.63mA   -14.68mA   -38.61mA
3.545V    -19.25mA   -13.56mA   -31.41mA
[GND_clamp]
-1.8V     -2.82A     -1.192A    -3.165A
-1.073V   -235.7mA   -138.4mA   -192.1mA
-1.036V   -159.5mA   -110.8mA   -107.5mA
-1V       -103.8mA   -87.85mA   -60.67mA
-963.6mV  -60mA      -67.28mA   -29.8mA
-927.3mV  -28.21mA   -49.08mA   -14.9mA
-890.9mV  -15.9mA    -35.48mA   -10.99mA
-854.5mV  -8.138mA   -24.07mA   -8.449mA
-818.2mV  -4.924mA   -14.85mA   -7.266mA
-709.1mV  -2.784mA   -3.064mA   -4.883mA
-563.6mV  -570.2uA   -404.5uA   -1.092mA
1.764V    -11.02pA   583.5nA    3.035nA
[Ramp]
dV/dt_f  0.6529183/4.912201n   0.3691729/12.67963n   0.8193364/1.981994n
dV/dt_r  0.6500586/4.62266n   0.3998976/10.70304n   0.8221078/2.29469n
R_load = 50
[Rising Waveform]
R_fixture = 50
V_fixture = 1.8
V_fixture_min = 1.62
V_fixture_max = 1.89
0s        717.7mV    1.009V     531.7mV
144ps     718.9mV    1.009V     672.7mV
261ps     713.5mV    1.009V     1.459V
315ps     748.5mV    1.009V     1.691V
387ps     900.5mV    1.01V      1.814V
513ps     1.383V     1.011V     1.87V
594ps     1.63V      1.002V     1.878V
711ps     1.754V     1.017V     1.881V
1.35ns    1.795V     1.598V     1.884V
6.039ns   1.799V     1.618V     1.889V
[Rising Waveform]
R_fixture = 50
V_fixture = 0
V_fixture_min = 0
V_fixture_max = 0
0s        222.2uV    103.3uV    -8.322mV
945ps     -2.705mV   -6.88mV    40.82mV
1.89ns    40.62mV    -1.494mV   440mV
2.835ns   205.9mV    1.038mV    822.2mV
3.78ns    383.6mV    12.08mV    1.077V
5.067ns   597.1mV    56.61mV    1.213V
7.272ns   840mV      174.7mV    1.294V
14.21ns   1.025V     461.9mV    1.343V
23.41ns   1.06V      595.3mV    1.348V
67.51ns   1.067V     655.8mV    1.349V
[Falling Waveform]
R_fixture = 50
V_fixture = 1.8
V_fixture_min = 1.62
V_fixture_max = 1.89
0s        1.8V       1.62V      1.889V
1.188ns   1.805V     1.62V      1.824V
2.808ns   1.736V     1.624V     1.054V
3.807ns   1.587V     1.625V     747.9mV
4.833ns   1.417V     1.62V      627.8mV
6.381ns   1.183V     1.597V     566.7mV
10.04ns   855.9mV    1.477V     534.9mV
14.72ns   751.4mV    1.305V     530.3mV
28.92ns   718.4mV    1.061V     529.8mV
63.17ns   717.6mV    1.011V     529.8mV
[Falling Waveform]
R_fixture = 50
V_fixture = 0
V_fixture_min = 0
V_fixture_max = 0
0s        1.068V     657.4mV    1.349V
441ps     1.071V     657.4mV    1.33V
774ps     1.058V     657.7mV    1.192V
936ps     1.029V     660.1mV    1.011V
1.395ns   831.4mV    665mV      172.9mV
1.593ns   661.3mV    656mV      19.67mV
2.16ns    165.5mV    580.2mV    1.166mV
2.466ns   27.15mV    505.3mV    560.7uV
4.05ns    703.8uV    41.6mV     162.4uV
6.264ns   241.6uV    1.636mV    61.43uV
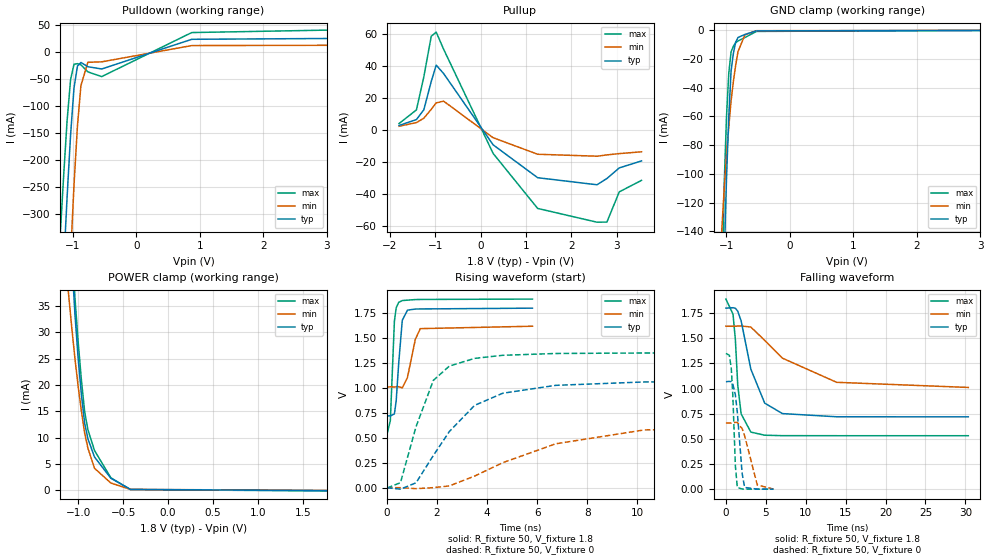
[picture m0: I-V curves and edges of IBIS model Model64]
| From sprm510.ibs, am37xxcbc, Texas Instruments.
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| Model based on original model for BQ18OMAPSMART1HYFBPB_SSBHH
|   Sub model FBPB_HS00L11_PU1_1P8
[model]   Model64
|[Input Load]   PU
|[Output Drive] SC00LB11
|Voltage   1.8V
|Mode   I/O
Model_type   I/O
Polarity   Non-Inverting
Enable   Active-Low
Vinl =  0.63
Vinh =  1.17
Cref =  15pF
Rref =  100.0000M
Vref =  0V
Vmeas =  0.9
C_comp   1.429432p   1.270657p   1.602015p
[Model Spec]
Vinl   0.63   0.567   0.6615
Vinh   1.17   1.053   1.2285
[Temperature Range]   25   125   -40
[Voltage Range]   1.8   1.62   1.89
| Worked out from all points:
|   slope of the pulldown table from 0 to 0.27 V, typ, clamps not added: 24.3 ohm
|   slope of the pullup table from 0 to 0.27 V, typ, clamps not added: 29.7 ohm
|   GND clamp passes 1 mA (typ) near -0.60 V on its own axis
|   POWER clamp passes 1 mA (typ) near -0.56 V on its own axis
|   rising waveform, R_fixture 50, V_fixture 1.8: 20-80 % time 176ps typ, 308ps min, 123ps max; typ from 0.72 V to 1.8 V
|   rising waveform, R_fixture 50, V_fixture 0: 20-80 % time 2.11ns typ, 4.76ns min, 1.07ns max; typ from 0.001 V to 1.07 V
|   falling waveform, R_fixture 50, V_fixture 1.8: 20-80 % time 2.1ns typ, 5.91ns min, 730ps max; typ from 1.8 V to 0.72 V
|   falling waveform, R_fixture 50, V_fixture 0: 20-80 % time 645ps typ, 1.17ns min, 385ps max; typ from 1.07 V to 0.002 V
[POWER_clamp]
-1.8V     362.5mA    191.4mA    412.8mA
-1.109V   56.76mA    37.74mA    60.51mA
-1.073V   44.67mA    31.25mA    47.93mA
-1.036V   33.52mA    25.07mA    36.72mA
-1V       25.06mA    19.75mA    28.2mA
-963.6mV  18.11mA    14.99mA    20.91mA
-927.3mV  12.67mA    10.8mA     14.87mA
-890.9mV  9.734mA    7.935mA    11.44mA
-818.2mV  6.293mA    4.153mA    7.536mA
-636.4mV  2.249mA    1.342mA    2.34mA
-418.2mV  128.7uA    129.3uA    104.4uA
1.764V    -96.73uA   -46.48uA   -163.5uA
[Pulldown]
-1.8V     -1.718A    -2.61A     -1.406A
-1.2V     -527.4mA   -844.5mA   -339.9mA
-1.145V   -396mA     -683.1mA   -229.1mA
-1.091V   -269mA     -526.7mA   -127.5mA
-1.036V   -153.6mA   -378.9mA   -51.17mA
-981.8mV  -66.33mA   -245.6mA   -22.67mA
-927.3mV  -26mA      -136.2mA   -21.54mA
-872.7mV  -19.34mA   -61.98mA   -23.69mA
-763.6mV  -27.2mA    -19.05mA   -36.72mA
-545.5mV  -31.39mA   -18.17mA   -45.46mA
872.7mV   23.46mA    11.88mA    35.92mA
3.545V    25.34mA    12.51mA    41.58mA
[Pullup]
-1.8V     2.903mA    2.423mA    4.112mA
-1.418V   6.595mA    4.711mA    12.64mA
-1.255V   12.69mA    7.42mA     33.24mA
-1.091V   30.4mA     13mA       58.69mA
-981.8mV  40.63mA    17.02mA    61.3mA
-818.2mV  35.38mA    18.12mA    50.59mA
272.7mV   -9.179mA   -4.728mA   -14.55mA
1.255V    -29.75mA   -15.09mA   -48.97mA
2.564V    -34.17mA   -16.31mA   -57.57mA
2.782V    -30.25mA   -15.5mA    -57.49mA
3.055V    -23.63mA   -14.68mA   -38.61mA
3.545V    -19.25mA   -13.56mA   -31.41mA
[GND_clamp]
-1.8V     -2.82A     -1.192A    -3.165A
-1.073V   -235.8mA   -138.4mA   -192.1mA
-1.036V   -159.6mA   -110.8mA   -107.6mA
-1V       -103.8mA   -87.86mA   -60.73mA
-963.6mV  -60.04mA   -67.29mA   -29.86mA
-927.3mV  -28.26mA   -49.09mA   -14.98mA
-890.9mV  -15.95mA   -35.49mA   -11.09mA
-854.5mV  -8.198mA   -24.09mA   -8.559mA
-818.2mV  -4.99mA    -14.87mA   -7.387mA
-709.1mV  -2.858mA   -3.093mA   -5.012mA
-527.3mV  -395.6uA   -260.4uA   -751.2uA
3.6V      0A         0A         0A
[Ramp]
dV/dt_f  0.6507154/2.09623n   0.3679131/5.952401n   0.816919/0.7311718n
dV/dt_r  0.6503742/2.113792n   0.4003852/4.808193n   0.8216227/1.076295n
R_load = 50
[Rising Waveform]
R_fixture = 50
V_fixture = 1.8
V_fixture_min = 1.62
V_fixture_max = 1.89
0s        720.1mV    1.01V      534.5mV
135ps     721.1mV    1.011V     673.1mV
297ps     739.2mV    1.01V      1.668V
369ps     872.2mV    1.011V     1.803V
468ps     1.243V     1.013V     1.857V
612ps     1.677V     1.001V     1.875V
819ps     1.779V     1.105V     1.879V
1.134ns   1.79V      1.487V     1.885V
1.332ns   1.791V     1.594V     1.886V
5.814ns   1.799V     1.618V     1.89V
[Rising Waveform]
R_fixture = 50
V_fixture = 0
V_fixture_min = 0
V_fixture_max = 0
0s        1.145mV    1.037mV    -2.752mV
540ps     -13.58mV   1.456mV    51.24mV
1.161ns   50.16mV    -8.565mV   611.2mV
1.854ns   323.9mV    1.56mV     1.076V
2.493ns   563.7mV    18.99mV    1.219V
3.501ns   825.2mV    117.5mV    1.296V
4.626ns   947mV      251.4mV    1.327V
6.741ns   1.026V     440.7mV    1.345V
10.29ns   1.06V      579.9mV    1.35V
31.24ns   1.069V     657.1mV    1.35V
[Falling Waveform]
R_fixture = 50
V_fixture = 1.8
V_fixture_min = 1.62
V_fixture_max = 1.89
0s        1.8V       1.62V      1.89V
891ps     1.804V     1.62V      1.74V
1.188ns   1.799V     1.62V      1.486V
1.485ns   1.769V     1.622V     1.033V
1.908ns   1.674V     1.623V     749.6mV
3.123ns   1.194V     1.612V     568.6mV
4.86ns    856.3mV    1.48V      537.5mV
7.083ns   752.3mV    1.303V     533mV
13.87ns   720.7mV    1.063V     532.6mV
30.37ns   720mV      1.012V     532.6mV
[Falling Waveform]
R_fixture = 50
V_fixture = 0
V_fixture_min = 0
V_fixture_max = 0
0s        1.069V     658.8mV    1.35V
432ps     1.072V     658.7mV    1.332V
675ps     1.069V     658.6mV    1.201V
864ps     1.045V     659.9mV    942mV
1.188ns   938.3mV    665.4mV    231.6mV
1.431ns   765.3mV    664mV      18.67mV
2.034ns   159.1mV    603.1mV    2.798mV
2.349ns   18.57mV    531.7mV    2.246mV
3.933ns   1.942mV    42.7mV     1.828mV
5.949ns   1.544mV    2.604mV    1.781mV
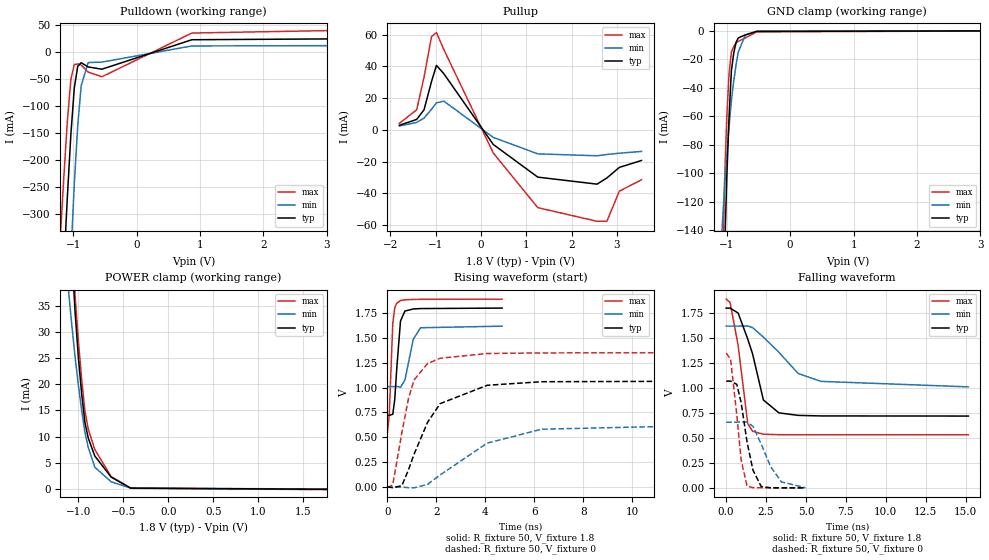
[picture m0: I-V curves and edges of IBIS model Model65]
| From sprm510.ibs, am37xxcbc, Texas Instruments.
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| Model based on original model for BQ18OMAPSMART1HYFBPB_SSBHH
|   Sub model FBPB_HS01L01_PU1_1P8
[model]   Model65
|[Input Load]   PU
|[Output Drive] SC01LB01
|Voltage   1.8V
|Mode   I/O
Model_type   I/O
Polarity   Non-Inverting
Enable   Active-Low
Vinl =  0.63
Vinh =  1.17
Cref =  15pF
Rref =  100.0000M
Vref =  0V
Vmeas =  0.9
C_comp   1.429432p   1.270657p   1.602015p
[Model Spec]
Vinl   0.63   0.567   0.6615
Vinh   1.17   1.053   1.2285
[Temperature Range]   25   125   -40
[Voltage Range]   1.8   1.62   1.89
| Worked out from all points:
|   slope of the pulldown table from 0 to 0.27 V, typ, clamps not added: 24.3 ohm
|   slope of the pullup table from 0 to 0.27 V, typ, clamps not added: 29.7 ohm
|   GND clamp passes 1 mA (typ) near -0.60 V on its own axis
|   POWER clamp passes 1 mA (typ) near -0.56 V on its own axis
|   rising waveform, R_fixture 50, V_fixture 1.8: 20-80 % time 175ps typ, 303ps min, 124ps max; typ from 0.72 V to 1.8 V
|   rising waveform, R_fixture 50, V_fixture 0: 20-80 % time 1.31ns typ, 2.87ns min, 690ps max; typ from 0.001 V to 1.07 V
|   falling waveform, R_fixture 50, V_fixture 1.8: 20-80 % time 1.09ns typ, 2.23ns min, 675ps max; typ from 1.8 V to 0.72 V
|   falling waveform, R_fixture 50, V_fixture 0: 20-80 % time 676ps typ, 1.11ns min, 494ps max; typ from 1.07 V to 0.001 V
[POWER_clamp]
-1.8V     362.5mA    191.4mA    412.8mA
-1.109V   56.76mA    37.74mA    60.51mA
-1.073V   44.67mA    31.25mA    47.93mA
-1.036V   33.52mA    25.07mA    36.72mA
-1V       25.06mA    19.75mA    28.2mA
-963.6mV  18.11mA    14.99mA    20.91mA
-927.3mV  12.67mA    10.8mA     14.87mA
-890.9mV  9.734mA    7.935mA    11.44mA
-818.2mV  6.293mA    4.153mA    7.536mA
-636.4mV  2.249mA    1.342mA    2.34mA
-418.2mV  128.7uA    129.3uA    104.4uA
1.764V    -96.73uA   -46.48uA   -163.5uA
[Pulldown]
-1.8V     -1.718A    -2.61A     -1.406A
-1.2V     -527.4mA   -844.5mA   -339.9mA
-1.145V   -396mA     -683.1mA   -229.1mA
-1.091V   -269mA     -526.7mA   -127.5mA
-1.036V   -153.6mA   -378.9mA   -51.17mA
-981.8mV  -66.33mA   -245.6mA   -22.67mA
-927.3mV  -26mA      -136.2mA   -21.54mA
-872.7mV  -19.34mA   -61.98mA   -23.69mA
-763.6mV  -27.2mA    -19.05mA   -36.72mA
-545.5mV  -31.39mA   -18.17mA   -45.46mA
872.7mV   23.46mA    11.88mA    35.92mA
3.545V    25.34mA    12.51mA    41.58mA
[Pullup]
-1.8V     2.903mA    2.423mA    4.112mA
-1.418V   6.595mA    4.711mA    12.64mA
-1.255V   12.69mA    7.42mA     33.24mA
-1.091V   30.4mA     13mA       58.69mA
-981.8mV  40.63mA    17.02mA    61.3mA
-818.2mV  35.38mA    18.12mA    50.59mA
272.7mV   -9.179mA   -4.728mA   -14.55mA
1.255V    -29.75mA   -15.09mA   -48.97mA
2.564V    -34.17mA   -16.31mA   -57.57mA
2.782V    -30.25mA   -15.5mA    -57.49mA
3.055V    -23.63mA   -14.68mA   -38.61mA
3.545V    -19.25mA   -13.56mA   -31.41mA
[GND_clamp]
-1.8V     -2.82A     -1.192A    -3.165A
-1.073V   -235.8mA   -138.4mA   -192.1mA
-1.036V   -159.6mA   -110.8mA   -107.6mA
-1V       -103.8mA   -87.86mA   -60.73mA
-963.6mV  -60.04mA   -67.29mA   -29.86mA
-927.3mV  -28.26mA   -49.09mA   -14.98mA
-890.9mV  -15.95mA   -35.49mA   -11.09mA
-854.5mV  -8.198mA   -24.09mA   -8.559mA
-818.2mV  -4.99mA    -14.87mA   -7.387mA
-709.1mV  -2.858mA   -3.093mA   -5.012mA
-527.3mV  -395.6uA   -260.4uA   -751.2uA
3.6V      0A         0A         0A
[Ramp]
dV/dt_f  0.6498362/1.093165n   0.3669184/2.244187n   0.8166101/0.67736n
dV/dt_r  0.6499045/1.308357n   0.4005015/2.89536n   0.8205538/0.6915828n
R_load = 50
[Rising Waveform]
R_fixture = 50
V_fixture = 1.8
V_fixture_min = 1.62
V_fixture_max = 1.89
0s        719.7mV    1.011V     531.3mV
81ps      721.2mV    1.011V     724.8mV
225ps     731.5mV    1.01V      1.645V
306ps     880.8mV    1.011V     1.803V
387ps     1.189V     1.012V     1.848V
540ps     1.669V     1.003V     1.876V
720ps     1.77V      1.075V     1.883V
1.062ns   1.791V     1.487V     1.887V
1.359ns   1.795V     1.602V     1.888V
4.689ns   1.8V       1.618V     1.89V
[Rising Waveform]
R_fixture = 50
V_fixture = 0
V_fixture_min = 0
V_fixture_max = 0
0s        1.204mV    1.067mV    -8.853mV
225ps     -6.984mV   747.6uV    21.42mV
594ps     12.53mV    -1.281mV   544.6mV
864ps     171.1mV    -6.88mV    887.3mV
1.089ns   326.6mV    -8.753mV   1.075V
1.647ns   651.8mV    26.11mV    1.243V
2.16ns    838.7mV    121.5mV    1.295V
4.077ns   1.023V     441.1mV    1.343V
6.3ns     1.059V     581.1mV    1.349V
19.77ns   1.069V     657.1mV    1.35V
[Falling Waveform]
R_fixture = 50
V_fixture = 1.8
V_fixture_min = 1.62
V_fixture_max = 1.89
0s        1.8V       1.62V      1.89V
243ps     1.8V       1.62V      1.857V
747ps     1.751V     1.62V      1.429V
1.35ns    1.491V     1.622V     645.5mV
1.656ns   1.341V     1.605V     566.9mV
2.331ns   881mV      1.51V      538.7mV
3.303ns   751.9mV    1.358V     533.2mV
4.509ns   726.8mV    1.146V     532.6mV
5.94ns    721.2mV    1.067V     532.6mV
15.17ns   720mV      1.012V     532.6mV
[Falling Waveform]
R_fixture = 50
V_fixture = 0
V_fixture_min = 0
V_fixture_max = 0
0s        1.069V     658.7mV    1.35V
279ps     1.07V      658.9mV    1.288V
666ps     1.037V     658.8mV    728.9mV
936ps     855.9mV    661.1mV    281.8mV
1.305ns   463.2mV    661mV      18.98mV
1.674ns   180.5mV    617.7mV    3.306mV
2.196ns   13.76mV    439.5mV    1.943mV
2.781ns   2.776mV    213.2mV    1.792mV
3.465ns   1.69mV     60.88mV    1.775mV
4.968ns   1.434mV    2.606mV    1.773mV
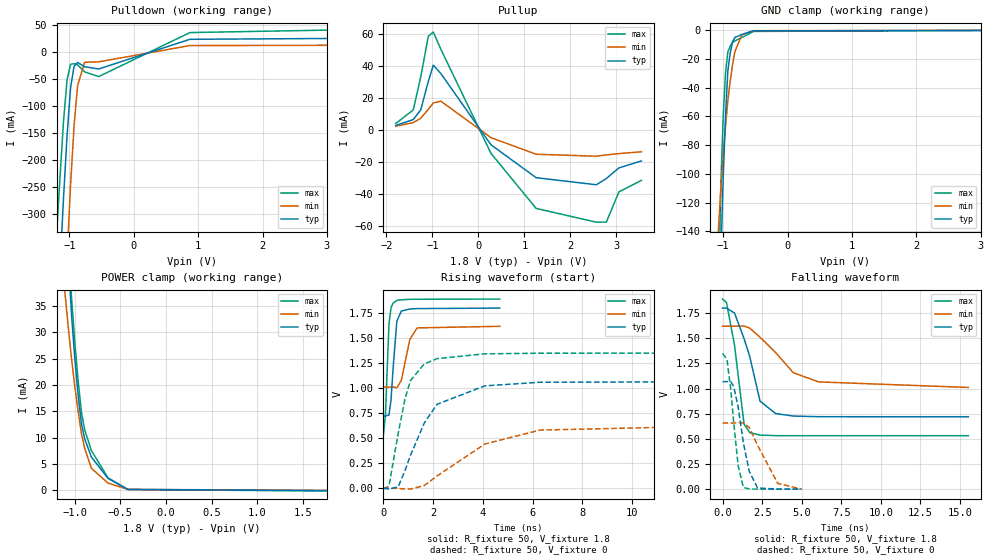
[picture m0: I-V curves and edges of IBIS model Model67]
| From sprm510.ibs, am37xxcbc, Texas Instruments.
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| Model based on original model for BQ18OMAPSMART1HYFBPB_SSBHH
|   Sub model FBPB_HS01L00_PU1_1P8
[model]   Model67
|[Input Load]   PU
|[Output Drive] SC01LB00
|Voltage   1.8V
|Mode   I/O
Model_type   I/O
Polarity   Non-Inverting
Enable   Active-Low
Vinl =  0.63
Vinh =  1.17
Cref =  15pF
Rref =  100.0000M
Vref =  0V
Vmeas =  0.9
C_comp   1.429432p   1.270657p   1.602015p
[Model Spec]
Vinl   0.63   0.567   0.6615
Vinh   1.17   1.053   1.2285
[Temperature Range]   25   125   -40
[Voltage Range]   1.8   1.62   1.89
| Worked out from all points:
|   slope of the pulldown table from 0 to 0.27 V, typ, clamps not added: 24.3 ohm
|   slope of the pullup table from 0 to 0.27 V, typ, clamps not added: 29.7 ohm
|   GND clamp passes 1 mA (typ) near -0.60 V on its own axis
|   POWER clamp passes 1 mA (typ) near -0.56 V on its own axis
|   rising waveform, R_fixture 50, V_fixture 1.8: 20-80 % time 176ps typ, 303ps min, 124ps max; typ from 0.72 V to 1.8 V
|   rising waveform, R_fixture 50, V_fixture 0: 20-80 % time 1.31ns typ, 2.87ns min, 691ps max; typ from 0.001 V to 1.07 V
|   falling waveform, R_fixture 50, V_fixture 1.8: 20-80 % time 1.09ns typ, 2.28ns min, 675ps max; typ from 1.8 V to 0.72 V
|   falling waveform, R_fixture 50, V_fixture 0: 20-80 % time 678ps typ, 1.11ns min, 496ps max; typ from 1.07 V to 0.001 V
[POWER_clamp]
-1.8V     362.5mA    191.4mA    412.8mA
-1.109V   56.76mA    37.74mA    60.51mA
-1.073V   44.67mA    31.25mA    47.93mA
-1.036V   33.52mA    25.07mA    36.72mA
-1V       25.06mA    19.75mA    28.2mA
-963.6mV  18.11mA    14.99mA    20.91mA
-927.3mV  12.67mA    10.8mA     14.87mA
-890.9mV  9.734mA    7.935mA    11.44mA
-818.2mV  6.293mA    4.153mA    7.536mA
-636.4mV  2.249mA    1.342mA    2.34mA
-418.2mV  128.7uA    129.3uA    104.4uA
1.764V    -96.73uA   -46.48uA   -163.5uA
[Pulldown]
-1.8V     -1.718A    -2.61A     -1.406A
-1.2V     -527.4mA   -844.5mA   -339.9mA
-1.145V   -396mA     -683.1mA   -229.1mA
-1.091V   -269mA     -526.7mA   -127.5mA
-1.036V   -153.6mA   -378.9mA   -51.17mA
-981.8mV  -66.33mA   -245.6mA   -22.67mA
-927.3mV  -26mA      -136.2mA   -21.54mA
-872.7mV  -19.34mA   -61.98mA   -23.69mA
-763.6mV  -27.2mA    -19.05mA   -36.72mA
-545.5mV  -31.39mA   -18.17mA   -45.46mA
872.7mV   23.46mA    11.88mA    35.92mA
3.545V    25.34mA    12.51mA    41.58mA
[Pullup]
-1.8V     2.903mA    2.423mA    4.112mA
-1.418V   6.595mA    4.711mA    12.64mA
-1.255V   12.69mA    7.42mA     33.24mA
-1.091V   30.4mA     13mA       58.69mA
-981.8mV  40.63mA    17.02mA    61.3mA
-818.2mV  35.38mA    18.12mA    50.59mA
272.7mV   -9.179mA   -4.728mA   -14.55mA
1.255V    -29.75mA   -15.09mA   -48.97mA
2.564V    -34.17mA   -16.31mA   -57.57mA
2.782V    -30.25mA   -15.5mA    -57.49mA
3.055V    -23.63mA   -14.68mA   -38.61mA
3.545V    -19.25mA   -13.56mA   -31.41mA
[GND_clamp]
-1.8V     -2.82A     -1.192A    -3.165A
-1.073V   -235.8mA   -138.4mA   -192.1mA
-1.036V   -159.6mA   -110.8mA   -107.6mA
-1V       -103.8mA   -87.86mA   -60.73mA
-963.6mV  -60.04mA   -67.29mA   -29.86mA
-927.3mV  -28.26mA   -49.09mA   -14.98mA
-890.9mV  -15.95mA   -35.49mA   -11.09mA
-854.5mV  -8.198mA   -24.09mA   -8.559mA
-818.2mV  -4.99mA    -14.87mA   -7.387mA
-709.1mV  -2.858mA   -3.093mA   -5.012mA
-527.3mV  -395.6uA   -260.4uA   -751.2uA
3.6V      0A         0A         0A
[Ramp]
dV/dt_f  0.6498678/1.093828n   0.3669481/2.296111n   0.8166345/0.6773665n
dV/dt_r  0.6497195/1.30997n   0.4004018/2.899255n   0.8202898/0.6922768n
R_load = 50
[Rising Waveform]
R_fixture = 50
V_fixture = 1.8
V_fixture_min = 1.62
V_fixture_max = 1.89
0s        719.7mV    1.011V     531.2mV
81ps      721.2mV    1.011V     726.3mV
225ps     732mV      1.01V      1.644V
306ps     883.4mV    1.011V     1.803V
387ps     1.19V      1.012V     1.848V
540ps     1.669V     1.003V     1.876V
720ps     1.77V      1.077V     1.883V
1.062ns   1.791V     1.487V     1.887V
1.359ns   1.795V     1.602V     1.888V
4.68ns    1.8V       1.618V     1.89V
[Rising Waveform]
R_fixture = 50
V_fixture = 0
V_fixture_min = 0
V_fixture_max = 0
0s        1.201mV    1.068mV    -8.866mV
225ps     -7.148mV   746.2uV    23.53mV
594ps     14.14mV    -1.459mV   547.1mV
864ps     174.1mV    -6.795mV   889mV
1.089ns   329mV      -8.591mV   1.076V
1.647ns   653.2mV    27.53mV    1.243V
2.16ns    839.3mV    123.5mV    1.295V
4.077ns   1.023V     441.9mV    1.343V
6.3ns     1.059V     581.2mV    1.349V
19.79ns   1.069V     657.1mV    1.35V
[Falling Waveform]
R_fixture = 50
V_fixture = 1.8
V_fixture_min = 1.62
V_fixture_max = 1.89
0s        1.8V       1.62V      1.89V
252ps     1.8V       1.62V      1.854V
756ps     1.751V     1.62V      1.431V
1.359ns   1.497V     1.622V     646.4mV
1.719ns   1.318V     1.601V     563.1mV
2.367ns   875.8mV    1.511V     538.6mV
3.357ns   752.1mV    1.358V     533.2mV
4.473ns   727.9mV    1.158V     532.6mV
6.075ns   721.2mV    1.067V     532.6mV
15.53ns   720mV      1.012V     532.6mV
[Falling Waveform]
R_fixture = 50
V_fixture = 0
V_fixture_min = 0
V_fixture_max = 0
0s        1.069V     658.7mV    1.35V
279ps     1.07V      658.9mV    1.291V
513ps     1.071V     658.7mV    999mV
711ps     1.017V     658.9mV    651.6mV
981ps     822mV      661.7mV    239.2mV
1.314ns   462.7mV    660.2mV    18.5mV
1.683ns   180.1mV    615mV      3.302mV
2.205ns   13.78mV    438.8mV    1.945mV
3.483ns   1.691mV    59.76mV    1.775mV
4.986ns   1.435mV    2.605mV    1.773mV
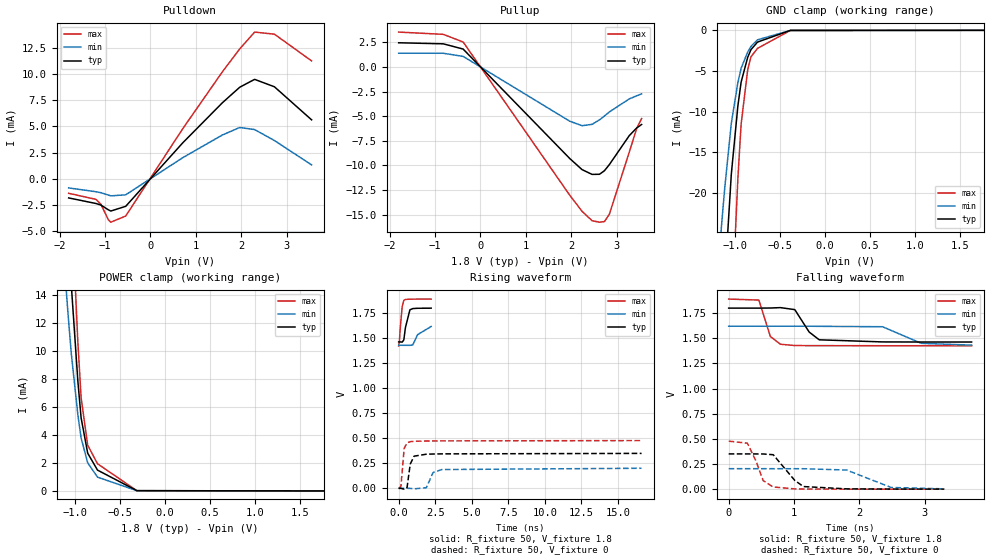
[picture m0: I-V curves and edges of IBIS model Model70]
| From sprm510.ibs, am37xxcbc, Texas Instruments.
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| Model based on original model for BQUSIM1833DVHYPBFZLP18NOPM_SSCHH
|   Sub model NOPM_SSCHH_PUPD0_1P8
[model]   Model70
|[Input Load]   PI
|[Output Drive]
|Voltage   1.8V
|Mode   I/O
Model_type   I/O
Polarity   Non-Inverting
Enable   Active-Low
Vinl =  0.54
Vinh =  1.26
Cref =  15pF
Rref =  100.0000M
Vref =  0V
Vmeas =  0.9
C_comp   1.861602p   1.830694p   1.903969p
[Model Spec]
Vinl   0.54   0.486   0.567
Vinh   1.26   1.134   1.323
[Temperature Range]   25   125   -40
[Voltage Range]   1.8   1.62   1.89
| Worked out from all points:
|   slope of the pulldown table from 0 to 0.27 V, typ, clamps not added: 203 ohm
|   slope of the pullup table from 0 to 0.27 V, typ, clamps not added: 200 ohm
|   GND clamp passes 1 mA (typ) near -0.69 V on its own axis
|   POWER clamp passes 1 mA (typ) near -0.65 V on its own axis
|   rising waveform, R_fixture 50, V_fixture 1.8: 20-80 % time 262ps typ, 623ps min, 160ps max; typ from 1.46 V to 1.8 V
|   rising waveform, R_fixture 50, V_fixture 0: 20-80 % time 209ps typ, 407ps min, 154ps max; typ from 0 V to 0.349 V
|   falling waveform, R_fixture 50, V_fixture 1.8: 20-80 % time 196ps typ, 345ps min, 120ps max; typ from 1.8 V to 1.46 V
|   falling waveform, R_fixture 50, V_fixture 0: 20-80 % time 257ps typ, 409ps min, 175ps max; typ from 0.351 V to 0.001 V
[POWER_clamp]
-1.8V     131.5mA    94.48mA    182.1mA
-1.182V   33.73mA    22.7mA     48.2mA
-1.145V   28.58mA    19.11mA    40.95mA
-1.109V   23.73mA    15.81mA    34.02mA
-1.073V   19.11mA    12.71mA    27.35mA
-1.036V   14.71mA    9.807mA    20.94mA
-963.6mV  7.867mA    5.453mA    10.65mA
-927.3mV  5.226mA    3.784mA    6.661mA
-854.5mV  2.701mA    2.013mA    3.272mA
-745.5mV  1.489mA    987uA      1.943mA
-309.1mV  18.4uA     16.66uA    18.71uA
1.764V    -10.88nA   -77.05nA   -94.43nA
[Pulldown]
-1.8V     -1.828mA   -873.3uA   -1.385mA
-1.2V     -2.358mA   -1.237mA   -1.965mA
-1.091V   -2.51mA    -1.332mA   -2.432mA
-927.3mV  -2.959mA   -1.552mA   -3.908mA
-872.7mV  -3.077mA   -1.631mA   -4.142mA
-545.5mV  -2.629mA   -1.532mA   -3.555mA
709.1mV   3.423mA    2.009mA    4.77mA
1.582V    7.249mA    4.174mA    10.2mA
1.964V    8.732mA    4.891mA    12.39mA
2.291V    9.481mA    4.693mA    13.99mA
2.727V    8.774mA    3.647mA    13.79mA
3.545V    5.619mA    1.322mA    11.24mA
[Pullup]
-1.8V     2.468mA    1.407mA    3.554mA
-818.2mV  2.361mA    1.402mA    3.325mA
-381.8mV  1.828mA    1.082mA    2.546mA
1.964V    -9.297mA   -5.505mA   -13.03mA
2.236V    -10.43mA   -5.962mA   -14.67mA
2.455V    -10.91mA   -5.824mA   -15.62mA
2.618V    -10.9mA    -5.37mA    -15.77mA
2.727V    -10.54mA   -4.977mA   -15.71mA
2.836V    -9.913mA   -4.562mA   -14.96mA
3.273V    -6.975mA   -3.239mA   -8.659mA
3.436V    -6.195mA   -2.926mA   -6.256mA
3.545V    -5.839mA   -2.725mA   -5.231mA
[GND_clamp]
-1.8V     -212.9mA   -139.2mA   -381.7mA
-1.218V   -55.61mA   -34.83mA   -107mA
-1.145V   -38.49mA   -24.06mA   -75.74mA
-1.109V   -30.9mA    -19.42mA   -61.46mA
-1.036V   -17.71mA   -11.44mA   -36mA
-963.6mV  -9.341mA   -6.449mA   -18.33mA
-927.3mV  -6.371mA   -4.665mA   -11.56mA
-854.5mV  -3.332mA   -2.673mA   -4.882mA
-818.2mV  -2.378mA   -1.984mA   -3.255mA
-745.5mV  -1.446mA   -1.168mA   -2.22mA
-381.8mV  -10.14uA   -13.69uA   -19.28uA
1.764V    463.6nA    561.2nA    793.4nA
[Ramp]
dV/dt_f  0.2059925/0.1866258n  0.1164408/0.3565705n  0.2829349/0.1207218n
dV/dt_r  0.2156987/0.2096117n  0.1252494/0.3886503n   0.293699/0.1555207n
R_load = 50
[Rising Waveform]
R_fixture = 50
V_fixture = 1.8
V_fixture_min = 1.62
V_fixture_max = 1.89
0s        1.462V     1.428V     1.422V
44ps      1.462V     1.428V     1.461V
110ps     1.462V     1.429V     1.602V
242ps     1.46V      1.428V     1.818V
352ps     1.482V     1.428V     1.876V
462ps     1.605V     1.428V     1.886V
770ps     1.783V     1.428V     1.889V
968ps     1.795V     1.432V     1.889V
1.298ns   1.798V     1.535V     1.89V
2.222ns   1.799V     1.616V     1.89V
[Rising Waveform]
R_fixture = 50
V_fixture = 0
V_fixture_min = 0
V_fixture_max = 0
0s        -16.16uV   -107.7uV   -3.942mV
154ps     645.3uV    58.02uV    19.14mV
374ps     -8.239mV   -17.9uV    398.3mV
572ps     7.426mV    282.2uV    453.7mV
792ps     242.1mV    -627.2uV   466.3mV
1.056ns   321.4mV    -4.963mV   470mV
1.892ns   340.8mV    5.976mV    472.7mV
2.354ns   342.7mV    157.5mV    473.3mV
2.948ns   344.2mV    187.7mV    473.9mV
16.63ns   348.9mV    200.5mV    476.8mV
[Falling Waveform]
R_fixture = 50
V_fixture = 1.8
V_fixture_min = 1.62
V_fixture_max = 1.89
0s        1.8V       1.62V      1.89V
462ps     1.8V       1.62V      1.88V
638ps     1.801V     1.62V      1.518V
792ps     1.805V     1.62V      1.441V
1.012ns   1.785V     1.62V      1.428V
1.232ns   1.562V     1.62V      1.427V
1.386ns   1.485V     1.619V     1.427V
2.354ns   1.464V     1.615V     1.426V
2.948ns   1.463V     1.45V      1.426V
3.718ns   1.463V     1.432V     1.426V
[Falling Waveform]
R_fixture = 50
V_fixture = 0
V_fixture_min = 0
V_fixture_max = 0
0s        350.8mV    203.7mV    477.5mV
286ps     350.6mV    203.8mV    457.4mV
418ps     350.5mV    203.7mV    279.9mV
528ps     350.1mV    203.7mV    85.17mV
682ps     342.7mV    203.7mV    21.81mV
1.012ns   86.92mV    203.5mV    2.825mV
1.144ns   26.26mV    203.6mV    1.536mV
1.804ns   3.268mV    190.6mV    499.8uV
2.486ns   1.468mV    17.1mV     362.4uV
3.3ns     913.8uV    3.393mV    280.4uV
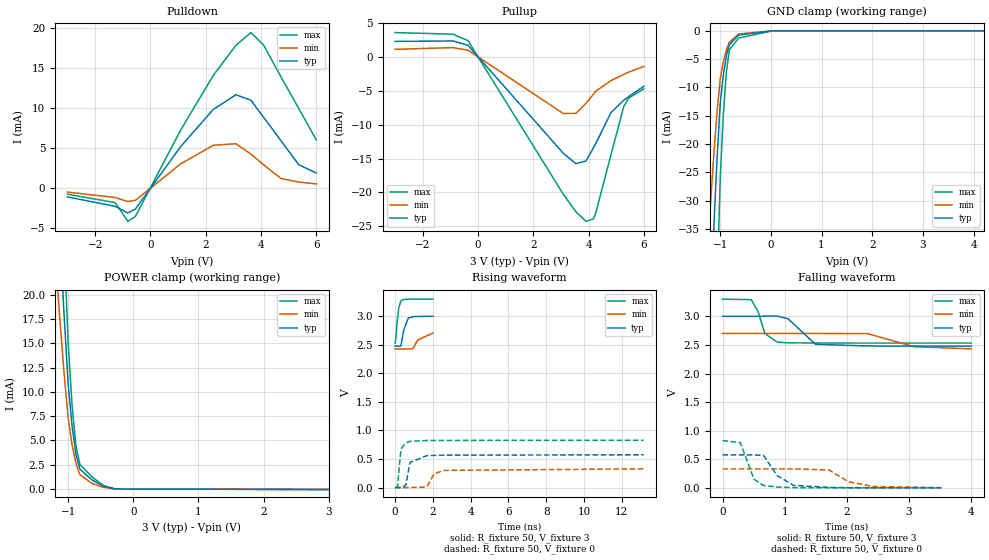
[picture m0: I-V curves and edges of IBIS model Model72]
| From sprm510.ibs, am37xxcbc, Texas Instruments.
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| Model based on original model for BQUSIM1833DVHYPBFZLP18NOPM_SSCHH
|   Sub model LP18NOPM_SSCHH_PU1_3
[model]   Model72
|[Input Load]   PU
|[Output Drive]
|Voltage   3V
|Mode   I/O
Model_type   I/O
Polarity   Non-Inverting
Enable   Active-Low
Vinl =  0.9
Vinh =  2.1
Cref =  15pF
Rref =  100.0000M
Vref =  0V
Vmeas =  1.5
C_comp   1.710183p   1.606508p   1.731375p
[Model Spec]
Vinl   0.9   0.81   0.99
Vinh   2.1   1.89   2.31
[Temperature Range]   25   125   -40
[Voltage Range]   3   2.7   3.3
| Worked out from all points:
|   slope of the pulldown table from 0 to 0.45 V, typ, clamps not added: 205 ohm
|   slope of the pullup table from 0 to 0.45 V, typ, clamps not added: 200 ohm
|   GND clamp passes 1 mA (typ) near -0.67 V on its own axis
|   POWER clamp passes 1 mA (typ) near -0.65 V on its own axis
|   rising waveform, R_fixture 50, V_fixture 3: 20-80 % time 226ps typ, 542ps min, 139ps max; typ from 2.48 V to 3 V
|   rising waveform, R_fixture 50, V_fixture 0: 20-80 % time 195ps typ, 351ps min, 138ps max; typ from 0.002 V to 0.575 V
|   falling waveform, R_fixture 50, V_fixture 3: 20-80 % time 237ps typ, 454ps min, 142ps max; typ from 3 V to 2.48 V
|   falling waveform, R_fixture 50, V_fixture 0: 20-80 % time 240ps typ, 350ps min, 165ps max; typ from 0.577 V to 0.003 V
[POWER_clamp]
-3V       333.5mA    280.6mA    454.2mA
-1.182V   33.66mA    22.65mA    48.11mA
-1.121V   25.41mA    16.98mA    36.38mA
-1.061V   17.81mA    11.87mA    25.4mA
-1V       10.86mA    7.342mA    15.18mA
-939.4mV  6.484mA    4.563mA    8.601mA
-878.8mV  3.543mA    2.608mA    4.384mA
-818.2mV  2.04mA     1.478mA    2.529mA
-636.4mV  956.9uA    588.7uA    1.272mA
-454.5mV  274.9uA    170.2uA    352.5uA
-272.7mV  9.09uA     8.599uA    10uA
3V        -42.37uA   -28.79uA   -57.22uA
[Pulldown]
-3V       -1.107mA   -507.6uA   -770.6uA
-1.273V   -2.288mA   -1.185mA   -1.831mA
-818.2mV  -3.117mA   -1.689mA   -4.154mA
-545.5mV  -2.629mA   -1.532mA   -3.555mA
1.091V    5.159mA    3.011mA    7.214mA
2.273V    9.809mA    5.337mA    14.05mA
3.091V    11.64mA    5.526mA    17.81mA
3.636V    10.95mA    4.227mA    19.4mA
4.091V    8.845mA    2.905mA    17.85mA
4.727V    5.879mA    1.177mA    13.84mA
5.364V    2.909mA    743.5uA    9.93mA
6V        1.868mA    517.6uA    6.001mA
[Pullup]
-3V       2.34mA     1.168mA    3.647mA
-909.1mV  2.41mA     1.426mA    3.408mA
-363.6mV  1.769mA    1.046mA    2.465mA
3.091V    -14.22mA   -8.331mA   -20.28mA
3.545V    -15.74mA   -8.296mA   -22.85mA
3.909V    -15.34mA   -6.8mA     -24.26mA
4.182V    -13.37mA   -5.445mA   -23.9mA
4.273V    -12.67mA   -4.985mA   -22.85mA
4.818V    -8.149mA   -3.439mA   -14.34mA
5.273V    -6.367mA   -2.536mA   -7.301mA
5.455V    -5.802mA   -2.193mA   -6.042mA
6V        -4.302mA   -1.361mA   -4.674mA
[GND_clamp]
-3V       -555.8mA   -408.9mA   -966.1mA
-1.242V   -61.73mA   -38.75mA   -117.9mA
-1.182V   -46.84mA   -29.26mA   -91.09mA
-1.121V   -33.71mA   -21.16mA   -66.63mA
-1.061V   -22.39mA   -14.26mA   -44.98mA
-1V       -12.88mA   -8.55mA    -26.13mA
-939.4mV  -7.889mA   -5.546mA   -14.88mA
-878.8mV  -4.411mA   -3.366mA   -7.29mA
-818.2mV  -2.441mA   -2.01mA    -3.352mA
-636.4mV  -764.3uA   -557.2uA   -1.282mA
30.3mV    0A         0A         0A
6V        0A         0A         0A
[Ramp]
dV/dt_f  0.3166681/0.2317744n  0.1655669/0.4648542n  0.4657413/0.1419311n
dV/dt_r  0.3510892/0.1927462n  0.2027826/0.351806n   0.5043594/0.1385243n
R_load = 50
[Rising Waveform]
R_fixture = 50
V_fixture = 3
V_fixture_min = 2.7
V_fixture_max = 3.3
0s        2.478V     2.427V     2.528V
44ps      2.478V     2.427V     2.609V
110ps     2.478V     2.427V     2.905V
198ps     2.479V     2.427V     3.146V
308ps     2.477V     2.427V     3.268V
462ps     2.76V      2.427V     3.294V
704ps     2.968V     2.427V     3.299V
946ps     2.993V     2.431V     3.3V
1.21ns    2.997V     2.588V     3.3V
2.002ns   2.999V     2.703V     3.3V
[Rising Waveform]
R_fixture = 50
V_fixture = 0
V_fixture_min = 0
V_fixture_max = 0
0s        1.678mV    886.9uV    -1.521mV
132ps     2.099mV    1.064mV    23.65mV
286ps     -531.9uV   982.1uV    581.1mV
352ps     -4.474mV   975.6uV    694.3mV
572ps     43.45mV    1.277mV    782.8mV
792ps     440.3mV    383.3uV    811.2mV
1.672ns   558.5mV    9.366mV    824.7mV
2.068ns   564mV      241.3mV    825.5mV
2.596ns   567.4mV    301.6mV    826.1mV
13.16ns   574.6mV    328.4mV    829mV
[Falling Waveform]
R_fixture = 50
V_fixture = 3
V_fixture_min = 2.7
V_fixture_max = 3.3
0s        3V         2.7V       3.3V
462ps     3V         2.7V       3.291V
572ps     2.999V     2.7V       3.083V
682ps     3.003V     2.7V       2.697V
880ps     3.005V     2.7V       2.55V
1.056ns   2.956V     2.7V       2.536V
1.496ns   2.511V     2.7V       2.533V
2.332ns   2.481V     2.698V     2.532V
3.08ns    2.479V     2.47V      2.532V
4.004ns   2.479V     2.43V      2.532V
[Falling Waveform]
R_fixture = 50
V_fixture = 0
V_fixture_min = 0
V_fixture_max = 0
0s        577.1mV    333.8mV    829.6mV
286ps     577mV      333.9mV    792.8mV
506ps     576.9mV    333.8mV    155mV
660ps     570.3mV    333.8mV    44.15mV
880ps     217.1mV    333.7mV    16.16mV
1.144ns   44.41mV    333.7mV    6.232mV
1.716ns   10.58mV    315.5mV    2.692mV
2.024ns   6.307mV    109.8mV    2.491mV
2.42ns    4.066mV    26.43mV    2.419mV
3.52ns    2.606mV    6.523mV    2.38mV
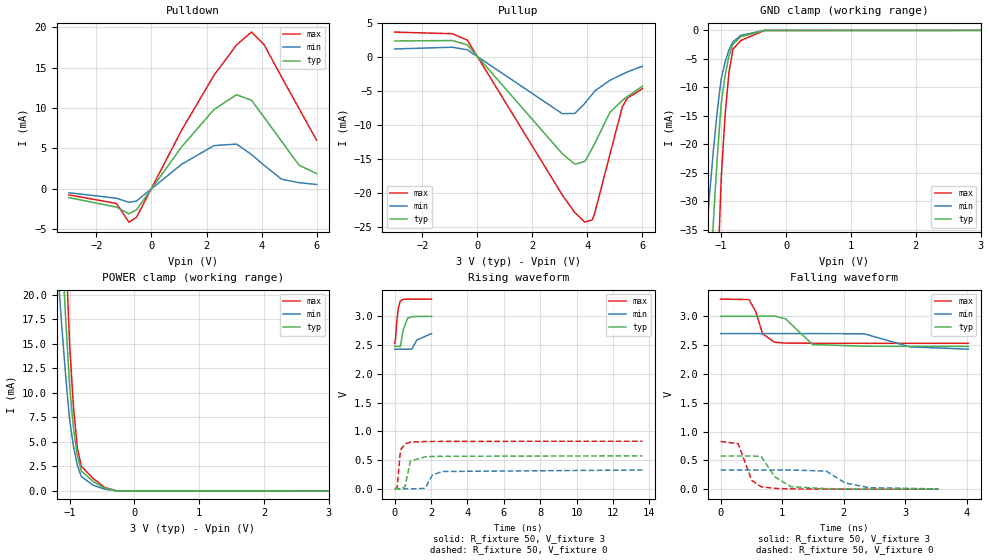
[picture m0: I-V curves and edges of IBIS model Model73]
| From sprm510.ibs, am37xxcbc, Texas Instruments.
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| Model based on original model for BQUSIM1833DVHYPBFZLP18NOPM_SSCHH
|   Sub model 18NOPM_SSCHH_PUPD0_3
[model]   Model73
|[Input Load]   PI
|[Output Drive]
|Voltage   3V
|Mode   I/O
Model_type   I/O
Polarity   Non-Inverting
Enable   Active-Low
Vinl =  0.9
Vinh =  2.1
Cref =  15pF
Rref =  100.0000M
Vref =  0V
Vmeas =  1.5
C_comp   1.710183p   1.606508p   1.731375p
[Model Spec]
Vinl   0.9   0.81   0.99
Vinh   2.1   1.89   2.31
[Temperature Range]   25   125   -40
[Voltage Range]   3   2.7   3.3
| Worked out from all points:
|   slope of the pulldown table from 0 to 0.45 V, typ, clamps not added: 205 ohm
|   slope of the pullup table from 0 to 0.45 V, typ, clamps not added: 200 ohm
|   GND clamp passes 1 mA (typ) near -0.68 V on its own axis
|   POWER clamp passes 1 mA (typ) near -0.65 V on its own axis
|   rising waveform, R_fixture 50, V_fixture 3: 20-80 % time 226ps typ, 527ps min, 139ps max; typ from 2.48 V to 3 V
|   rising waveform, R_fixture 50, V_fixture 0: 20-80 % time 195ps typ, 354ps min, 139ps max; typ from 0 V to 0.573 V
|   falling waveform, R_fixture 50, V_fixture 3: 20-80 % time 237ps typ, 454ps min, 142ps max; typ from 3 V to 2.48 V
|   falling waveform, R_fixture 50, V_fixture 0: 20-80 % time 240ps typ, 350ps min, 165ps max; typ from 0.576 V to 0.001 V
[POWER_clamp]
-3V       333.5mA    280.6mA    454.2mA
-1.182V   33.66mA    22.64mA    48.1mA
-1.121V   25.4mA     16.97mA    36.37mA
-1.061V   17.8mA     11.87mA    25.39mA
-1V       10.86mA    7.339mA    15.17mA
-939.4mV  6.479mA    4.56mA     8.594mA
-878.8mV  3.538mA    2.605mA    4.378mA
-818.2mV  2.035mA    1.475mA    2.523mA
-636.4mV  952.2uA    586uA      1.265mA
-454.5mV  270.6uA    167.7uA    346.4uA
-272.7mV  5.574uA    6.589uA    5.153uA
3V        -13.91nA   -3.424uA   -123.4nA
[Pulldown]
-3V       -1.107mA   -507.6uA   -770.6uA
-1.273V   -2.288mA   -1.185mA   -1.831mA
-818.2mV  -3.117mA   -1.689mA   -4.154mA
-545.5mV  -2.629mA   -1.532mA   -3.555mA
1.091V    5.159mA    3.011mA    7.214mA
2.273V    9.809mA    5.337mA    14.05mA
3.091V    11.64mA    5.526mA    17.81mA
3.636V    10.95mA    4.227mA    19.4mA
4.091V    8.845mA    2.905mA    17.85mA
4.727V    5.879mA    1.177mA    13.84mA
5.364V    2.909mA    743.5uA    9.93mA
6V        1.868mA    517.6uA    6.001mA
[Pullup]
-3V       2.34mA     1.168mA    3.647mA
-909.1mV  2.41mA     1.426mA    3.408mA
-363.6mV  1.769mA    1.046mA    2.465mA
3.091V    -14.22mA   -8.331mA   -20.28mA
3.545V    -15.74mA   -8.296mA   -22.85mA
3.909V    -15.34mA   -6.8mA     -24.26mA
4.182V    -13.37mA   -5.445mA   -23.9mA
4.273V    -12.67mA   -4.985mA   -22.85mA
4.818V    -8.149mA   -3.439mA   -14.34mA
5.273V    -6.367mA   -2.536mA   -7.301mA
5.455V    -5.802mA   -2.193mA   -6.042mA
6V        -4.302mA   -1.361mA   -4.674mA
[GND_clamp]
-3V       -555.8mA   -408.9mA   -966.1mA
-1.242V   -61.72mA   -38.75mA   -117.9mA
-1.182V   -46.84mA   -29.26mA   -91.08mA
-1.121V   -33.7mA    -21.16mA   -66.62mA
-1.061V   -22.38mA   -14.25mA   -44.97mA
-1V       -12.87mA   -8.546mA   -26.12mA
-939.4mV  -7.879mA   -5.541mA   -14.87mA
-878.8mV  -4.395mA   -3.36mA    -7.26mA
-818.2mV  -2.417mA   -2.002mA   -3.302mA
-697mV    -1.115mA   -862.6uA   -1.777mA
-333.3mV  -5.793uA   -9.728uA   -9.705uA
3V        923.7nA    12.16uA    1.546uA
[Ramp]
dV/dt_f  0.3168568/0.2319915n  0.1656323/0.4651454n  0.4660864/0.1421001n
dV/dt_r  0.3513228/0.1932295n  0.2028737/0.3525264n  0.5047793/0.1388511n
R_load = 50
[Rising Waveform]
R_fixture = 50
V_fixture = 3
V_fixture_min = 2.7
V_fixture_max = 3.3
0s        2.478V     2.427V     2.528V
44ps      2.478V     2.427V     2.609V
110ps     2.478V     2.427V     2.904V
198ps     2.478V     2.427V     3.146V
308ps     2.477V     2.427V     3.268V
462ps     2.759V     2.427V     3.293V
704ps     2.968V     2.427V     3.299V
946ps     2.993V     2.43V      3.299V
1.21ns    2.997V     2.587V     3.299V
2.024ns   2.999V     2.7V       3.3V
[Rising Waveform]
R_fixture = 50
V_fixture = 0
V_fixture_min = 0
V_fixture_max = 0
0s        -16.52uV   -107.9uV   -3.86mV
132ps     404.3uV    69.52uV    20.88mV
286ps     -2.226mV   -12.74uV   578.2mV
352ps     -6.189mV   -19.2uV    691.7mV
572ps     41.42mV    282.5uV    780.2mV
858ps     481.4mV    -1.069mV   812.6mV
1.672ns   556.7mV    8.246mV    822.3mV
2.068ns   562.2mV    240.2mV    823.1mV
2.618ns   565.7mV    301.3mV    823.9mV
13.62ns   573.1mV    327.5mV    827.3mV
[Falling Waveform]
R_fixture = 50
V_fixture = 3
V_fixture_min = 2.7
V_fixture_max = 3.3
0s        3V         2.7V       3.3V
462ps     3V         2.7V       3.291V
572ps     2.999V     2.7V       3.083V
682ps     3.003V     2.7V       2.697V
880ps     3.005V     2.7V       2.55V
1.056ns   2.956V     2.7V       2.536V
1.496ns   2.511V     2.7V       2.533V
2.332ns   2.481V     2.698V     2.532V
3.08ns    2.479V     2.47V      2.532V
4.026ns   2.479V     2.43V      2.532V
[Falling Waveform]
R_fixture = 50
V_fixture = 0
V_fixture_min = 0
V_fixture_max = 0
0s        575.7mV    332.9mV    827.9mV
286ps     575.6mV    333mV      790.9mV
506ps     575.5mV    332.9mV    153mV
660ps     568.9mV    332.9mV    42.44mV
880ps     215.5mV    332.8mV    14.47mV
1.144ns   42.99mV    332.8mV    4.537mV
1.716ns   9.244mV    314.6mV    943.5uV
2.024ns   4.97mV     108.8mV    692.6uV
2.42ns    2.735mV    25.51mV    558.1uV
3.542ns   1.255mV    5.519mV    390.8uV
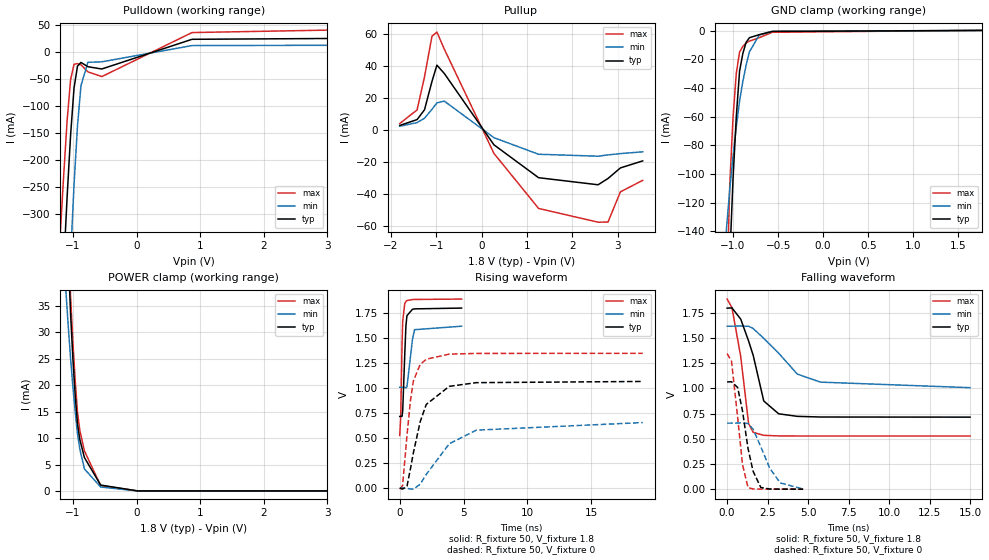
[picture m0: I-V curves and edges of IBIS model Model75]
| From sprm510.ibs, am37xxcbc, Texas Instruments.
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| Model based on original model for BQ18OMAPSMART1HYFBPBNOPM_SSBHV
|   Sub model NOPM_VS01L10_PD1_1P8
[model]   Model75
|[Input Load]   PD
|[Output Drive] SC01LB10
|Voltage   1.8V
|Mode   I/O
Model_type   I/O
Polarity   Non-Inverting
Enable   Active-Low
Vinl =  0.63
Vinh =  1.17
Cref =  15pF
Rref =  100.0000M
Vref =  0V
Vmeas =  0.9
C_comp   1.410688p   1.256095p   1.577871p
[Model Spec]
Vinl   0.63   0.567   0.6615
Vinh   1.17   1.053   1.2285
[Temperature Range]   25   125   -40
[Voltage Range]   1.8   1.62   1.89
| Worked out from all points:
|   slope of the pulldown table from 0 to 0.27 V, typ, clamps not added: 24.3 ohm
|   slope of the pullup table from 0 to 0.27 V, typ, clamps not added: 29.7 ohm
|   GND clamp passes 1 mA (typ) near -0.60 V on its own axis
|   POWER clamp passes 1 mA (typ) near -0.55 V on its own axis
|   rising waveform, R_fixture 50, V_fixture 1.8: 20-80 % time 176ps typ, 303ps min, 124ps max; typ from 0.715 V to 1.8 V
|   rising waveform, R_fixture 50, V_fixture 0: 20-80 % time 1.28ns typ, 2.77ns min, 686ps max; typ from 0 V to 1.06 V
|   falling waveform, R_fixture 50, V_fixture 1.8: 20-80 % time 1.08ns typ, 2.19ns min, 679ps max; typ from 1.8 V to 0.715 V
|   falling waveform, R_fixture 50, V_fixture 0: 20-80 % time 672ps typ, 1.09ns min, 499ps max; typ from 1.06 V to 0 V
[POWER_clamp]
-1.8V     362.5mA    191.4mA    412.8mA
-1.109V   56.75mA    37.73mA    60.5mA
-1.073V   44.66mA    31.25mA    47.93mA
-1.036V   33.51mA    25.07mA    36.73mA
-1V       25.06mA    19.75mA    28.2mA
-963.6mV  18.11mA    14.99mA    20.92mA
-927.3mV  12.68mA    10.81mA    14.88mA
-890.9mV  9.743mA    7.94mA     11.46mA
-818.2mV  6.308mA    4.161mA    7.567mA
-563.6mV  1.112mA    743.5uA    1.008mA
18.18mV   0A         0A         0A
3.6V      0A         0A         0A
[Pulldown]
-1.8V     -1.718A    -2.61A     -1.406A
-1.2V     -527.4mA   -844.5mA   -339.9mA
-1.145V   -396mA     -683.1mA   -229.1mA
-1.091V   -269mA     -526.7mA   -127.5mA
-1.036V   -153.6mA   -378.9mA   -51.17mA
-981.8mV  -66.33mA   -245.6mA   -22.67mA
-927.3mV  -26mA      -136.2mA   -21.54mA
-872.7mV  -19.34mA   -61.98mA   -23.69mA
-763.6mV  -27.2mA    -19.05mA   -36.72mA
-545.5mV  -31.39mA   -18.17mA   -45.46mA
872.7mV   23.46mA    11.88mA    35.92mA
3.545V    25.34mA    12.51mA    41.58mA
[Pullup]
-1.8V     2.903mA    2.423mA    4.112mA
-1.418V   6.595mA    4.711mA    12.64mA
-1.255V   12.69mA    7.42mA     33.24mA
-1.091V   30.4mA     13mA       58.69mA
-981.8mV  40.63mA    17.02mA    61.3mA
-818.2mV  35.38mA    18.12mA    50.59mA
272.7mV   -9.18mA    -4.728mA   -14.55mA
1.255V    -29.75mA   -15.09mA   -48.97mA
2.564V    -34.17mA   -16.31mA   -57.57mA
2.782V    -30.25mA   -15.5mA    -57.49mA
3.055V    -23.63mA   -14.68mA   -38.61mA
3.545V    -19.25mA   -13.56mA   -31.41mA
[GND_clamp]
-1.8V     -2.82A     -1.192A    -3.165A
-1.073V   -235.8mA   -138.4mA   -192.1mA
-1.036V   -159.6mA   -110.8mA   -107.6mA
-1V       -103.8mA   -87.86mA   -60.72mA
-963.6mV  -60.04mA   -67.3mA    -29.85mA
-927.3mV  -28.26mA   -49.1mA    -14.96mA
-890.9mV  -15.95mA   -35.5mA    -11.07mA
-854.5mV  -8.196mA   -24.09mA   -8.539mA
-818.2mV  -4.988mA   -14.87mA   -7.364mA
-709.1mV  -2.851mA   -3.095mA   -4.982mA
-563.6mV  -633.9uA   -437.8uA   -1.185mA
1.764V    107.4uA    58.81uA    171.2uA
[Ramp]
dV/dt_f  0.6515192/1.08175n   0.3683137/2.204112n   0.8179949/0.6809862n
dV/dt_r  0.6492091/1.28404n   0.3997208/2.790167n   0.820632/0.6869826n
R_load = 50
[Rising Waveform]
R_fixture = 50
V_fixture = 1.8
V_fixture_min = 1.62
V_fixture_max = 1.89
0s        715.1mV    1.007V     525.7mV
81ps      717.2mV    1.007V     718.6mV
180ps     716.3mV    1.007V     1.424V
234ps     771.5mV    1.007V     1.666V
396ps     1.337V     1.007V     1.844V
486ps     1.62V      999.5mV    1.864V
567ps     1.722V     1.011V     1.874V
999ps     1.786V     1.484V     1.883V
1.161ns   1.79V      1.582V     1.884V
4.851ns   1.798V     1.617V     1.888V
[Rising Waveform]
R_fixture = 50
V_fixture = 0
V_fixture_min = 0
V_fixture_max = 0
0s        162.9uV    101.8uV    -10.97mV
225ps     -10.1mV    -201.2uV   24.39mV
576ps     21.29mV    -4.057mV   533.5mV
846ps     196.4mV    -8.276mV   879.8mV
1.071ns   352.9mV    -9.853mV   1.07V
1.602ns   661.5mV    38mV       1.234V
2.079ns   835.2mV    136.4mV    1.287V
3.879ns   1.016V     442.1mV    1.338V
6.003ns   1.053V     578.7mV    1.345V
19.04ns   1.065V     654.3mV    1.346V
[Falling Waveform]
R_fixture = 50
V_fixture = 1.8
V_fixture_min = 1.62
V_fixture_max = 1.89
0s        1.798V     1.618V     1.888V
297ps     1.8V       1.619V     1.803V
837ps     1.689V     1.62V      1.32V
1.323ns   1.472V     1.618V     652mV
1.611ns   1.327V     1.595V     563.7mV
2.259ns   875.8mV    1.498V     534.6mV
3.177ns   748.7mV    1.351V     528.9mV
4.329ns   723.2mV    1.143V     528.2mV
5.76ns    716.6mV    1.063V     528.1mV
14.99ns   715.4mV    1.008V     528.1mV
[Falling Waveform]
R_fixture = 50
V_fixture = 0
V_fixture_min = 0
V_fixture_max = 0
0s        1.065V     655.7mV    1.347V
270ps     1.067V     656.1mV    1.271V
648ps     1.01V      656.3mV    714.8mV
945ps     780mV      659.7mV    247.2mV
1.287ns   405.9mV    651.5mV    16.51mV
1.602ns   177.6mV    596.1mV    1.806mV
2.079ns   16.66mV    420.6mV    230.6uV
2.628ns   1.526mV    208.7mV    26.66uV
3.276ns   340uV      61.68mV    3.564uV
4.689ns   51.58uV    1.635mV    532nV
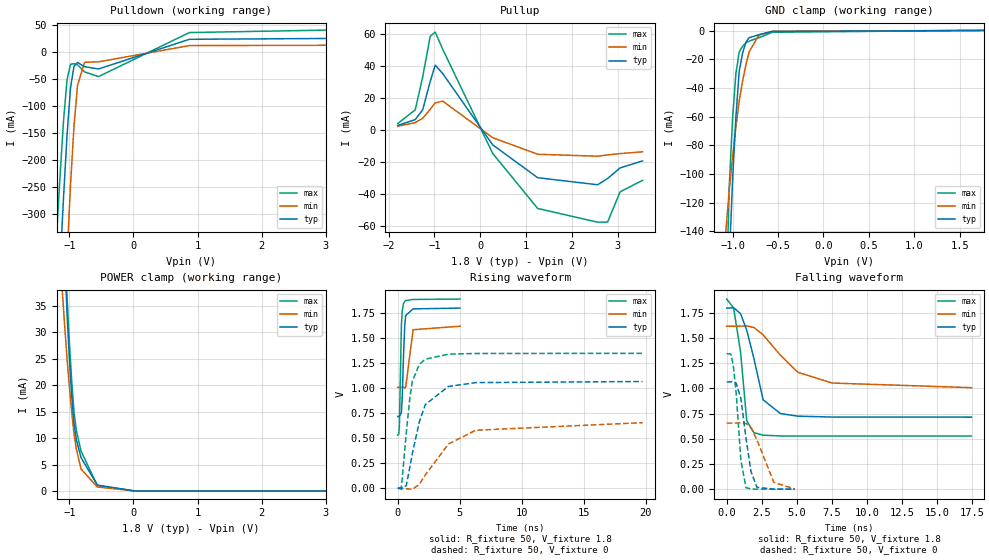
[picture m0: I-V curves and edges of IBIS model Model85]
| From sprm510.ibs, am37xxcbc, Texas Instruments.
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| Model based on original model for BQ18OMAPSMART1HYFBPBNOPM_SSBHV
|   Sub model NOPM_VS10L10_PD1_1P8
[model]   Model85
|[Input Load]   PD
|[Output Drive] SC10LB10
|Voltage   1.8V
|Mode   I/O
Model_type   I/O
Polarity   Non-Inverting
Enable   Active-Low
Vinl =  0.63
Vinh =  1.17
Cref =  15pF
Rref =  100.0000M
Vref =  0V
Vmeas =  0.9
C_comp   1.410688p   1.256095p   1.577871p
[Model Spec]
Vinl   0.63   0.567   0.6615
Vinh   1.17   1.053   1.2285
[Temperature Range]   25   125   -40
[Voltage Range]   1.8   1.62   1.89
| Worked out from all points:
|   slope of the pulldown table from 0 to 0.27 V, typ, clamps not added: 24.3 ohm
|   slope of the pullup table from 0 to 0.27 V, typ, clamps not added: 29.7 ohm
|   GND clamp passes 1 mA (typ) near -0.60 V on its own axis
|   POWER clamp passes 1 mA (typ) near -0.55 V on its own axis
|   rising waveform, R_fixture 50, V_fixture 1.8: 20-80 % time 177ps typ, 307ps min, 125ps max; typ from 0.715 V to 1.8 V
|   rising waveform, R_fixture 50, V_fixture 0: 20-80 % time 1.32ns typ, 2.86ns min, 704ps max; typ from 0 V to 1.06 V
|   falling waveform, R_fixture 50, V_fixture 1.8: 20-80 % time 1.04ns typ, 2.67ns min, 596ps max; typ from 1.8 V to 0.715 V
|   falling waveform, R_fixture 50, V_fixture 0: 20-80 % time 600ps typ, 1.02ns min, 432ps max; typ from 1.06 V to 0 V
[POWER_clamp]
-1.8V     362.5mA    191.4mA    412.8mA
-1.109V   56.75mA    37.73mA    60.5mA
-1.073V   44.66mA    31.25mA    47.93mA
-1.036V   33.51mA    25.07mA    36.73mA
-1V       25.06mA    19.75mA    28.2mA
-963.6mV  18.11mA    14.99mA    20.92mA
-927.3mV  12.68mA    10.81mA    14.88mA
-890.9mV  9.743mA    7.94mA     11.46mA
-818.2mV  6.308mA    4.161mA    7.567mA
-563.6mV  1.112mA    743.5uA    1.008mA
18.18mV   0A         0A         0A
3.6V      0A         0A         0A
[Pulldown]
-1.8V     -1.718A    -2.61A     -1.406A
-1.2V     -527.4mA   -844.5mA   -339.9mA
-1.145V   -396mA     -683.1mA   -229.1mA
-1.091V   -269mA     -526.7mA   -127.5mA
-1.036V   -153.6mA   -378.9mA   -51.17mA
-981.8mV  -66.33mA   -245.6mA   -22.67mA
-927.3mV  -26mA      -136.2mA   -21.54mA
-872.7mV  -19.34mA   -61.98mA   -23.69mA
-763.6mV  -27.2mA    -19.05mA   -36.72mA
-545.5mV  -31.39mA   -18.17mA   -45.46mA
872.7mV   23.46mA    11.88mA    35.92mA
3.545V    25.34mA    12.51mA    41.58mA
[Pullup]
-1.8V     2.903mA    2.423mA    4.112mA
-1.418V   6.595mA    4.711mA    12.64mA
-1.255V   12.69mA    7.42mA     33.24mA
-1.091V   30.4mA     13mA       58.69mA
-981.8mV  40.63mA    17.02mA    61.3mA
-818.2mV  35.38mA    18.12mA    50.59mA
272.7mV   -9.18mA    -4.728mA   -14.55mA
1.255V    -29.75mA   -15.09mA   -48.97mA
2.564V    -34.17mA   -16.31mA   -57.57mA
2.782V    -30.25mA   -15.5mA    -57.49mA
3.055V    -23.63mA   -14.68mA   -38.61mA
3.545V    -19.25mA   -13.56mA   -31.41mA
[GND_clamp]
-1.8V     -2.82A     -1.192A    -3.165A
-1.073V   -235.8mA   -138.4mA   -192.1mA
-1.036V   -159.6mA   -110.8mA   -107.6mA
-1V       -103.8mA   -87.86mA   -60.72mA
-963.6mV  -60.04mA   -67.29mA   -29.85mA
-927.3mV  -28.26mA   -49.1mA    -14.96mA
-890.9mV  -15.95mA   -35.5mA    -11.07mA
-854.5mV  -8.196mA   -24.09mA   -8.539mA
-818.2mV  -4.988mA   -14.87mA   -7.364mA
-709.1mV  -2.851mA   -3.095mA   -4.982mA
-563.6mV  -633.9uA   -437.8uA   -1.185mA
1.764V    107.4uA    58.81uA    171.2uA
[Ramp]
dV/dt_f  0.6516355/1.042495n   0.3685504/2.692088n   0.8180048/0.5981833n
dV/dt_r  0.6495824/1.324385n   0.3998471/2.884889n   0.8212965/0.7071013n
R_load = 50
[Rising Waveform]
R_fixture = 50
V_fixture = 1.8
V_fixture_min = 1.62
V_fixture_max = 1.89
0s        715.4mV    1.007V     530mV
90ps      715.5mV    1.007V     539.7mV
135ps     717.2mV    1.007V     633.3mV
297ps     755.9mV    1.007V     1.629V
360ps     900.3mV    1.008V     1.77V
468ps     1.321V     1.008V     1.843V
567ps     1.629V     998mV      1.864V
648ps     1.725V     1.013V     1.873V
1.242ns   1.79V      1.582V     1.884V
5.022ns   1.798V     1.617V     1.888V
[Rising Waveform]
R_fixture = 50
V_fixture = 0
V_fixture_min = 0
V_fixture_max = 0
0s        -263.4uV   100uV      -1.17mV
297ps     -9.542mV   -211.1uV   9.239mV
693ps     28.18mV    -4.914mV   554.6mV
990ps     217.6mV    -8.889mV   915.8mV
1.188ns   350.5mV    -9.412mV   1.071V
1.737ns   660.3mV    36.56mV    1.235V
2.232ns   835.4mV    134.3mV    1.288V
4.095ns   1.016V     441.2mV    1.338V
6.3ns     1.054V     578.8mV    1.345V
19.76ns   1.065V     654.3mV    1.346V
[Falling Waveform]
R_fixture = 50
V_fixture = 1.8
V_fixture_min = 1.62
V_fixture_max = 1.89
0s        1.798V     1.618V     1.888V
495ps     1.801V     1.618V     1.799V
990ps     1.744V     1.619V     1.362V
1.431ns   1.579V     1.621V     680mV
1.944ns   1.298V     1.606V     561.3mV
2.601ns   887.8mV    1.533V     536mV
3.834ns   751.2mV    1.331V     528.8mV
5.067ns   725.3mV    1.162V     528.2mV
7.524ns   716.1mV    1.054V     528.1mV
17.48ns   715.4mV    1.008V     528.1mV
[Falling Waveform]
R_fixture = 50
V_fixture = 0
V_fixture_min = 0
V_fixture_max = 0
0s        1.065V     655.9mV    1.346V
297ps     1.066V     656.1mV    1.342V
468ps     1.069V     655.9mV    1.234V
675ps     1.054V     656.1mV    956.7mV
1.017ns   899.5mV    659.4mV    284.3mV
1.377ns   508.9mV    652.8mV    14.65mV
1.737ns   173.6mV    610.5mV    1.535mV
2.16ns    18.54mV    489.4mV    273.4uV
3.366ns   403.6uV    68.18mV    8.034uV
4.86ns    65.76uV    1.629mV    849.5nV
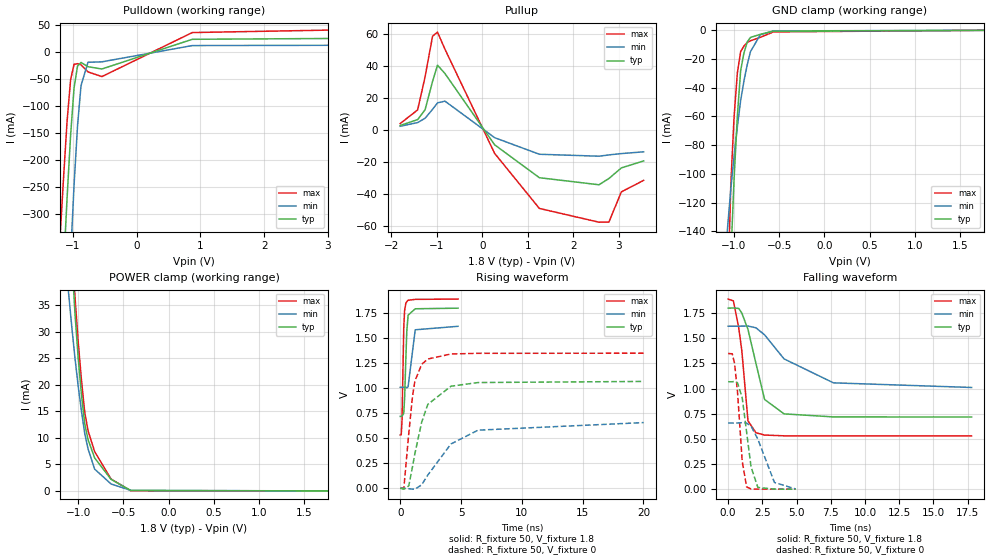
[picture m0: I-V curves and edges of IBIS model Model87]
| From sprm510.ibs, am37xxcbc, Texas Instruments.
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| Model based on original model for BQ18OMAPSMART1HYFBPBNOPM_SSBHV
|   Sub model PM_VS10L01_PUPD0_1P8
[model]   Model87
|[Input Load]   PI
|[Output Drive] SC10LB01
|Voltage   1.8V
|Mode   I/O
Model_type   I/O
Polarity   Non-Inverting
Enable   Active-Low
Vinl =  0.63
Vinh =  1.17
Cref =  15pF
Rref =  100.0000M
Vref =  0V
Vmeas =  0.9
C_comp   1.410688p   1.256095p   1.577871p
[Model Spec]
Vinl   0.63   0.567   0.6615
Vinh   1.17   1.053   1.2285
[Temperature Range]   25   125   -40
[Voltage Range]   1.8   1.62   1.89
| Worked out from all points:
|   slope of the pulldown table from 0 to 0.27 V, typ, clamps not added: 24.3 ohm
|   slope of the pullup table from 0 to 0.27 V, typ, clamps not added: 29.7 ohm
|   GND clamp passes 1 mA (typ) near -0.60 V on its own axis
|   POWER clamp passes 1 mA (typ) near -0.56 V on its own axis
|   rising waveform, R_fixture 50, V_fixture 1.8: 20-80 % time 176ps typ, 305ps min, 124ps max; typ from 0.718 V to 1.8 V
|   rising waveform, R_fixture 50, V_fixture 0: 20-80 % time 1.33ns typ, 2.9ns min, 710ps max; typ from 0 V to 1.07 V
|   falling waveform, R_fixture 50, V_fixture 1.8: 20-80 % time 1.06ns typ, 2.76ns min, 585ps max; typ from 1.8 V to 0.718 V
|   falling waveform, R_fixture 50, V_fixture 0: 20-80 % time 590ps typ, 999ps min, 421ps max; typ from 1.07 V to 0 V
[POWER_clamp]
-1.8V     362.5mA    191.4mA    412.8mA
-1.109V   56.69mA    37.71mA    60.38mA
-1.073V   44.6mA     31.22mA    47.8mA
-1.036V   33.44mA    25.04mA    36.59mA
-1V       24.98mA    19.72mA    28.06mA
-963.6mV  18.03mA    14.96mA    20.78mA
-927.3mV  12.59mA    10.77mA    14.74mA
-890.9mV  9.653mA    7.899mA    11.31mA
-818.2mV  6.214mA    4.114mA    7.414mA
-636.4mV  2.183mA    1.307mA    2.238mA
-418.2mV  83.85uA    105.2uA    35.14uA
1.764V    -1.228nA   -79.11nA   -1.453nA
[Pulldown]
-1.8V     -1.718A    -2.61A     -1.406A
-1.2V     -527.4mA   -844.5mA   -339.9mA
-1.145V   -396mA     -683.1mA   -229.1mA
-1.091V   -269mA     -526.7mA   -127.5mA
-1.036V   -153.6mA   -378.9mA   -51.17mA
-981.8mV  -66.34mA   -245.6mA   -22.67mA
-927.3mV  -26mA      -136.2mA   -21.54mA
-872.7mV  -19.34mA   -61.98mA   -23.69mA
-763.6mV  -27.2mA    -19.05mA   -36.72mA
-545.5mV  -31.39mA   -18.17mA   -45.46mA
872.7mV   23.46mA    11.88mA    35.92mA
3.545V    25.34mA    12.51mA    41.58mA
[Pullup]
-1.8V     2.903mA    2.423mA    4.112mA
-1.418V   6.595mA    4.711mA    12.64mA
-1.255V   12.69mA    7.42mA     33.23mA
-1.091V   30.4mA     13mA       58.69mA
-981.8mV  40.63mA    17.02mA    61.3mA
-818.2mV  35.38mA    18.12mA    50.59mA
272.7mV   -9.18mA    -4.728mA   -14.55mA
1.255V    -29.75mA   -15.09mA   -48.97mA
2.564V    -34.17mA   -16.31mA   -57.57mA
2.782V    -30.25mA   -15.5mA    -57.48mA
3.055V    -23.63mA   -14.68mA   -38.61mA
3.545V    -19.25mA   -13.56mA   -31.41mA
[GND_clamp]
-1.8V     -2.82A     -1.192A    -3.165A
-1.073V   -235.7mA   -138.4mA   -192.1mA
-1.036V   -159.5mA   -110.8mA   -107.5mA
-1V       -103.8mA   -87.85mA   -60.67mA
-963.6mV  -60mA      -67.28mA   -29.8mA
-927.3mV  -28.21mA   -49.08mA   -14.9mA
-890.9mV  -15.9mA    -35.48mA   -10.99mA
-854.5mV  -8.138mA   -24.07mA   -8.449mA
-818.2mV  -4.924mA   -14.85mA   -7.266mA
-709.1mV  -2.784mA   -3.064mA   -4.883mA
-563.6mV  -570.2uA   -404.5uA   -1.092mA
1.764V    -11.02pA   583.5nA    3.035nA
[Ramp]
dV/dt_f  0.6513926/1.06141n   0.36795/2.783185n   0.8182605/0.5867676n
dV/dt_r   0.651353/1.337206n   0.4008795/2.919914n   0.8234777/0.7131612n
R_load = 50
[Rising Waveform]
R_fixture = 50
V_fixture = 1.8
V_fixture_min = 1.62
V_fixture_max = 1.89
0s        717.6mV    1.009V     531.7mV
81ps      717.5mV    1.009V     533.6mV
144ps     719.7mV    1.009V     668.6mV
288ps     746.8mV    1.009V     1.599V
360ps     902.3mV    1.01V      1.776V
459ps     1.287V     1.011V     1.847V
540ps     1.57V      1.002V     1.865V
648ps     1.729V     1.015V     1.878V
1.233ns   1.793V     1.583V     1.887V
4.752ns   1.799V     1.618V     1.89V
[Rising Waveform]
R_fixture = 50
V_fixture = 0
V_fixture_min = 0
V_fixture_max = 0
0s        -262.7uV   100uV      -814.1uV
297ps     -9.27mV    -212.5uV   1.762mV
702ps     23.77mV    -4.766mV   547.1mV
1.008ns   214.4mV    -9.307mV   917.8mV
1.206ns   346.5mV    -9.38mV    1.072V
1.764ns   660.1mV    34.02mV    1.238V
2.268ns   837.5mV    131.6mV    1.291V
4.167ns   1.019V     442mV      1.341V
6.399ns   1.056V     580.1mV    1.348V
20.02ns   1.067V     655.8mV    1.349V
[Falling Waveform]
R_fixture = 50
V_fixture = 1.8
V_fixture_min = 1.62
V_fixture_max = 1.89
0s        1.8V       1.62V      1.89V
387ps     1.801V     1.62V      1.871V
774ps     1.797V     1.62V      1.603V
999ps     1.751V     1.621V     1.376V
1.449ns   1.588V     1.622V     679.3mV
2.034ns   1.249V     1.604V     560.5mV
2.664ns   891.8mV    1.534V     538mV
4.086ns   748.5mV    1.295V     530.3mV
7.695ns   718.4mV    1.057V     529.8mV
17.79ns   717.6mV    1.011V     529.8mV
[Falling Waveform]
R_fixture = 50
V_fixture = 0
V_fixture_min = 0
V_fixture_max = 0
0s        1.068V     657.3mV    1.349V
297ps     1.068V     657.5mV    1.346V
468ps     1.071V     657.3mV    1.25V
684ps     1.058V     657.6mV    967.6mV
1.026ns   909.4mV    661mV      278.6mV
1.35ns    566.2mV    657.1mV    21.92mV
1.674ns   220.3mV    627.6mV    2.055mV
2.169ns   17.2mV     497.5mV    274.6uV
3.384ns   407.6uV    66.38mV    9.089uV
4.941ns   67.12uV    1.634mV    845.6nV
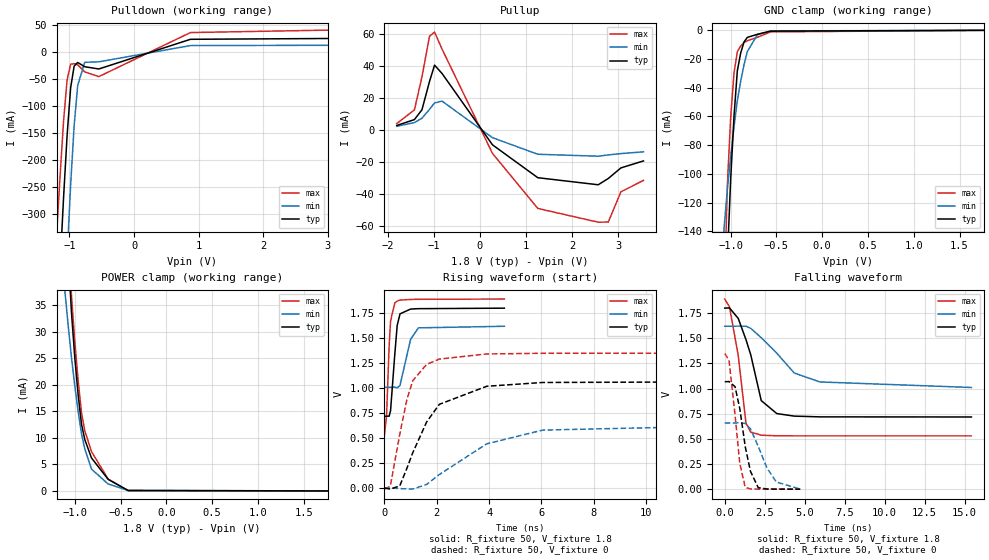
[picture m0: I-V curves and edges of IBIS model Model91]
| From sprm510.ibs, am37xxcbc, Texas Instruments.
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| Model based on original model for BQ18OMAPSMART1HYFBPBNOPM_SSBHV
|   Sub model PM_VS01L00_PUPD0_1P8
[model]   Model91
|[Input Load]   PI
|[Output Drive] SC01LB00
|Voltage   1.8V
|Mode   I/O
Model_type   I/O
Polarity   Non-Inverting
Enable   Active-Low
Vinl =  0.63
Vinh =  1.17
Cref =  15pF
Rref =  100.0000M
Vref =  0V
Vmeas =  0.9
C_comp   1.410688p   1.256095p   1.577871p
[Model Spec]
Vinl   0.63   0.567   0.6615
Vinh   1.17   1.053   1.2285
[Temperature Range]   25   125   -40
[Voltage Range]   1.8   1.62   1.89
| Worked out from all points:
|   slope of the pulldown table from 0 to 0.27 V, typ, clamps not added: 24.3 ohm
|   slope of the pullup table from 0 to 0.27 V, typ, clamps not added: 29.7 ohm
|   GND clamp passes 1 mA (typ) near -0.60 V on its own axis
|   POWER clamp passes 1 mA (typ) near -0.56 V on its own axis
|   rising waveform, R_fixture 50, V_fixture 1.8: 20-80 % time 176ps typ, 302ps min, 124ps max; typ from 0.717 V to 1.8 V
|   rising waveform, R_fixture 50, V_fixture 0: 20-80 % time 1.29ns typ, 2.78ns min, 688ps max; typ from 0 V to 1.07 V
|   falling waveform, R_fixture 50, V_fixture 1.8: 20-80 % time 1.07ns typ, 2.26ns min, 671ps max; typ from 1.8 V to 0.718 V
|   falling waveform, R_fixture 50, V_fixture 0: 20-80 % time 665ps typ, 1.08ns min, 493ps max; typ from 1.07 V to 0 V
[POWER_clamp]
-1.8V     362.5mA    191.4mA    412.8mA
-1.109V   56.69mA    37.71mA    60.38mA
-1.073V   44.6mA     31.22mA    47.8mA
-1.036V   33.44mA    25.04mA    36.59mA
-1V       24.98mA    19.72mA    28.06mA
-963.6mV  18.03mA    14.96mA    20.78mA
-927.3mV  12.59mA    10.77mA    14.74mA
-890.9mV  9.653mA    7.899mA    11.31mA
-818.2mV  6.214mA    4.114mA    7.414mA
-636.4mV  2.183mA    1.307mA    2.238mA
-418.2mV  83.85uA    105.2uA    35.14uA
1.764V    -1.228nA   -79.11nA   -1.453nA
[Pulldown]
-1.8V     -1.718A    -2.61A     -1.406A
-1.2V     -527.4mA   -844.5mA   -339.9mA
-1.145V   -396mA     -683.1mA   -229.1mA
-1.091V   -269mA     -526.7mA   -127.5mA
-1.036V   -153.6mA   -378.9mA   -51.17mA
-981.8mV  -66.34mA   -245.6mA   -22.67mA
-927.3mV  -26mA      -136.2mA   -21.54mA
-872.7mV  -19.34mA   -61.98mA   -23.69mA
-763.6mV  -27.2mA    -19.05mA   -36.72mA
-545.5mV  -31.39mA   -18.17mA   -45.46mA
872.7mV   23.46mA    11.88mA    35.92mA
3.545V    25.34mA    12.51mA    41.58mA
[Pullup]
-1.8V     2.903mA    2.423mA    4.112mA
-1.418V   6.595mA    4.711mA    12.64mA
-1.255V   12.69mA    7.42mA     33.23mA
-1.091V   30.4mA     13mA       58.69mA
-981.8mV  40.63mA    17.02mA    61.3mA
-818.2mV  35.38mA    18.12mA    50.59mA
272.7mV   -9.18mA    -4.728mA   -14.55mA
1.255V    -29.75mA   -15.09mA   -48.97mA
2.564V    -34.17mA   -16.31mA   -57.57mA
2.782V    -30.25mA   -15.5mA    -57.48mA
3.055V    -23.63mA   -14.68mA   -38.61mA
3.545V    -19.25mA   -13.56mA   -31.41mA
[GND_clamp]
-1.8V     -2.82A     -1.192A    -3.165A
-1.073V   -235.7mA   -138.4mA   -192.1mA
-1.036V   -159.5mA   -110.8mA   -107.5mA
-1V       -103.8mA   -87.85mA   -60.67mA
-963.6mV  -60mA      -67.28mA   -29.8mA
-927.3mV  -28.21mA   -49.08mA   -14.9mA
-890.9mV  -15.9mA    -35.48mA   -10.99mA
-854.5mV  -8.138mA   -24.07mA   -8.449mA
-818.2mV  -4.924mA   -14.85mA   -7.266mA
-709.1mV  -2.784mA   -3.064mA   -4.883mA
-563.6mV  -570.2uA   -404.5uA   -1.092mA
1.764V    -11.02pA   583.5nA    3.035nA
[Ramp]
dV/dt_f  0.6512929/1.075391n   0.3677269/2.275286n   0.818268/0.6732298n
dV/dt_r  0.6507664/1.290114n   0.4006417/2.807648n   0.8224704/0.6892732n
R_load = 50
[Rising Waveform]
R_fixture = 50
V_fixture = 1.8
V_fixture_min = 1.62
V_fixture_max = 1.89
0s        717.3mV    1.009V     527.7mV
81ps      719.5mV    1.009V     721.5mV
180ps     718.8mV    1.009V     1.426V
234ps     775.4mV    1.009V     1.671V
396ps     1.34V      1.01V      1.851V
486ps     1.624V     1.002V     1.87V
594ps     1.742V     1.027V     1.88V
999ps     1.79V      1.487V     1.886V
1.296ns   1.794V     1.602V     1.888V
4.581ns   1.799V     1.618V     1.89V
[Rising Waveform]
R_fixture = 50
V_fixture = 0
V_fixture_min = 0
V_fixture_max = 0
0s        160.1uV    102.2uV    -10.86mV
225ps     -9.984mV   -203.9uV   20mV
585ps     22.03mV    -4.264mV   537.6mV
855ps     196mV      -8.37mV    883mV
1.08ns    352mV      -9.832mV   1.073V
1.611ns   660.6mV    36.58mV    1.237V
2.097ns   837.5mV    135.8mV    1.29V
3.906ns   1.018V     442.3mV    1.341V
6.048ns   1.056V     579.9mV    1.348V
19.19ns   1.067V     655.8mV    1.349V
[Falling Waveform]
R_fixture = 50
V_fixture = 1.8
V_fixture_min = 1.62
V_fixture_max = 1.89
0s        1.8V       1.62V      1.89V
297ps     1.802V     1.62V      1.814V
846ps     1.698V     1.621V     1.33V
1.332ns   1.486V     1.62V      655mV
1.629ns   1.336V     1.599V     567.5mV
2.286ns   880.3mV    1.506V     536.8mV
3.258ns   751.5mV    1.352V     530.5mV
4.347ns   726.3mV    1.155V     529.9mV
5.949ns   718.8mV    1.066V     529.8mV
15.43ns   717.6mV    1.011V     529.8mV
[Falling Waveform]
R_fixture = 50
V_fixture = 0
V_fixture_min = 0
V_fixture_max = 0
0s        1.068V     657.2mV    1.349V
270ps     1.07V      657.5mV    1.282V
648ps     1.019V     657.8mV    736.7mV
945ps     799.2mV    661.2mV    253.4mV
1.287ns   420.9mV    653.6mV    17.45mV
1.611ns   178mV      600.3mV    1.827mV
2.097ns   15.02mV    425.3mV    225.4uV
2.646ns   1.544mV    209.5mV    27.43uV
3.231ns   395uV      70.77mV    4.739uV
4.725ns   53.18uV    1.643mV    566.8nV
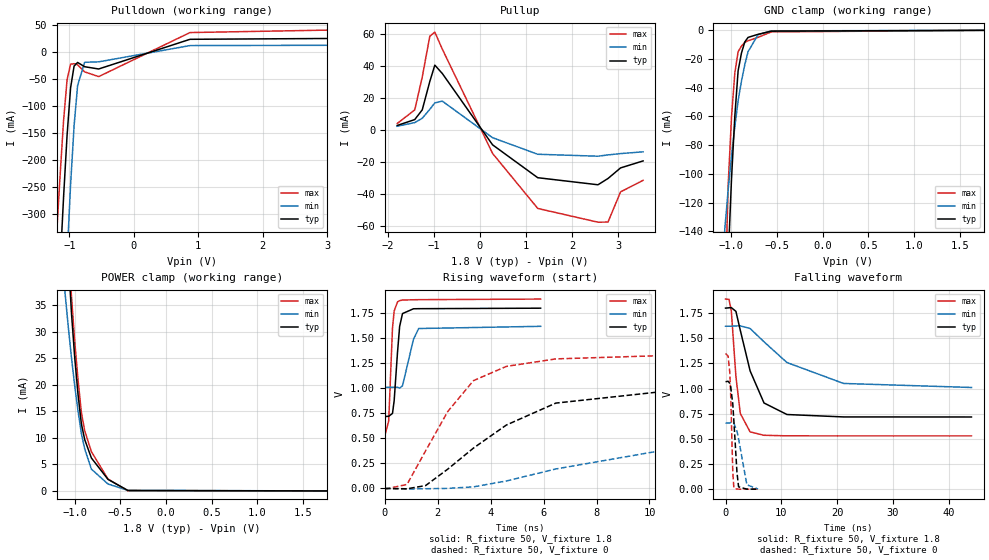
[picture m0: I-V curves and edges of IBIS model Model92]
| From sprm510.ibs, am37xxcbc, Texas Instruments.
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| Model based on original model for BQ18OMAPSMART1HYFBPBNOPM_SSBHV
|   Sub model PM_VS00L01_PUPD0_1P8
[model]   Model92
|[Input Load]   PI
|[Output Drive] SC00LB01
|Voltage   1.8V
|Mode   I/O
Model_type   I/O
Polarity   Non-Inverting
Enable   Active-Low
Vinl =  0.63
Vinh =  1.17
Cref =  15pF
Rref =  100.0000M
Vref =  0V
Vmeas =  0.9
C_comp   1.410688p   1.256095p   1.577871p
[Model Spec]
Vinl   0.63   0.567   0.6615
Vinh   1.17   1.053   1.2285
[Temperature Range]   25   125   -40
[Voltage Range]   1.8   1.62   1.89
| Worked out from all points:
|   slope of the pulldown table from 0 to 0.27 V, typ, clamps not added: 24.3 ohm
|   slope of the pullup table from 0 to 0.27 V, typ, clamps not added: 29.7 ohm
|   GND clamp passes 1 mA (typ) near -0.60 V on its own axis
|   POWER clamp passes 1 mA (typ) near -0.56 V on its own axis
|   rising waveform, R_fixture 50, V_fixture 1.8: 20-80 % time 176ps typ, 307ps min, 123ps max; typ from 0.718 V to 1.8 V
|   rising waveform, R_fixture 50, V_fixture 0: 20-80 % time 4.02ns typ, 9.13ns min, 2.04ns max; typ from 0 V to 1.07 V
|   falling waveform, R_fixture 50, V_fixture 1.8: 20-80 % time 3.37ns typ, 8.79ns min, 1.25ns max; typ from 1.8 V to 0.718 V
|   falling waveform, R_fixture 50, V_fixture 0: 20-80 % time 702ps typ, 1.17ns min, 409ps max; typ from 1.07 V to 0 V
[POWER_clamp]
-1.8V     362.5mA    191.4mA    412.8mA
-1.109V   56.69mA    37.71mA    60.38mA
-1.073V   44.6mA     31.22mA    47.8mA
-1.036V   33.44mA    25.04mA    36.59mA
-1V       24.98mA    19.72mA    28.06mA
-963.6mV  18.03mA    14.96mA    20.78mA
-927.3mV  12.59mA    10.77mA    14.74mA
-890.9mV  9.653mA    7.899mA    11.31mA
-818.2mV  6.214mA    4.114mA    7.414mA
-636.4mV  2.183mA    1.307mA    2.238mA
-418.2mV  83.85uA    105.2uA    35.14uA
1.764V    -1.228nA   -79.11nA   -1.453nA
[Pulldown]
-1.8V     -1.718A    -2.61A     -1.406A
-1.2V     -527.4mA   -844.5mA   -339.9mA
-1.145V   -396mA     -683.1mA   -229.1mA
-1.091V   -269mA     -526.7mA   -127.5mA
-1.036V   -153.6mA   -378.9mA   -51.17mA
-981.8mV  -66.34mA   -245.6mA   -22.67mA
-927.3mV  -26mA      -136.2mA   -21.54mA
-872.7mV  -19.34mA   -61.98mA   -23.69mA
-763.6mV  -27.2mA    -19.05mA   -36.72mA
-545.5mV  -31.39mA   -18.17mA   -45.46mA
872.7mV   23.46mA    11.88mA    35.92mA
3.545V    25.34mA    12.51mA    41.58mA
[Pullup]
-1.8V     2.903mA    2.423mA    4.112mA
-1.418V   6.595mA    4.711mA    12.64mA
-1.255V   12.69mA    7.42mA     33.23mA
-1.091V   30.4mA     13mA       58.69mA
-981.8mV  40.63mA    17.02mA    61.3mA
-818.2mV  35.38mA    18.12mA    50.59mA
272.7mV   -9.18mA    -4.728mA   -14.55mA
1.255V    -29.75mA   -15.09mA   -48.97mA
2.564V    -34.17mA   -16.31mA   -57.57mA
2.782V    -30.25mA   -15.5mA    -57.48mA
3.055V    -23.63mA   -14.68mA   -38.61mA
3.545V    -19.25mA   -13.56mA   -31.41mA
[GND_clamp]
-1.8V     -2.82A     -1.192A    -3.165A
-1.073V   -235.7mA   -138.4mA   -192.1mA
-1.036V   -159.5mA   -110.8mA   -107.5mA
-1V       -103.8mA   -87.85mA   -60.67mA
-963.6mV  -60mA      -67.28mA   -29.8mA
-927.3mV  -28.21mA   -49.08mA   -14.9mA
-890.9mV  -15.9mA    -35.48mA   -10.99mA
-854.5mV  -8.138mA   -24.07mA   -8.449mA
-818.2mV  -4.924mA   -14.85mA   -7.266mA
-709.1mV  -2.784mA   -3.064mA   -4.883mA
-563.6mV  -570.2uA   -404.5uA   -1.092mA
1.764V    -11.02pA   583.5nA    3.035nA
[Ramp]
dV/dt_f  0.6526039/3.377546n   0.3689988/8.864336n   0.8189478/1.249478n
dV/dt_r  0.6505049/4.035694n   0.4001877/9.212351n   0.8227572/2.043551n
R_load = 50
[Rising Waveform]
R_fixture = 50
V_fixture = 1.8
V_fixture_min = 1.62
V_fixture_max = 1.89
0s        717.6mV    1.009V     531.8mV
144ps     719.9mV    1.009V     670.5mV
288ps     749mV      1.009V     1.602V
351ps     876.1mV    1.01V      1.771V
477ps     1.357V     1.01V      1.862V
558ps     1.617V     1.001V     1.874V
666ps     1.745V     1.024V     1.88V
1.08ns    1.793V     1.488V     1.883V
1.278ns   1.794V     1.596V     1.884V
5.886ns   1.799V     1.618V     1.89V
[Rising Waveform]
R_fixture = 50
V_fixture = 0
V_fixture_min = 0
V_fixture_max = 0
0s        343uV      95.66uV    -7.15mV
837ps     -3.492mV   -6.031mV   40.16mV
1.539ns   28.75mV    -2.871mV   375.4mV
2.376ns   192.5mV    590.5uV    767.5mV
3.348ns   402.9mV    15.83mV    1.076V
4.59ns    632.7mV    74.44mV    1.218V
6.462ns   851.9mV    194.5mV    1.293V
12.58ns   1.026V     475.8mV    1.343V
20.14ns   1.06V      595.6mV    1.348V
58.74ns   1.067V     655.8mV    1.349V
[Falling Waveform]
R_fixture = 50
V_fixture = 1.8
V_fixture_min = 1.62
V_fixture_max = 1.89
0s        1.8V       1.62V      1.89V
621ps     1.803V     1.62V      1.887V
1.035ns   1.805V     1.62V      1.776V
1.863ns   1.768V     1.623V     1.119V
2.655ns   1.578V     1.624V     752.2mV
4.41ns    1.176V     1.597V     569.6mV
6.903ns   856.8mV    1.465V     535.9mV
11.02ns   742.2mV    1.259V     530.1mV
21.17ns   718.2mV    1.051V     529.8mV
44.11ns   717.6mV    1.011V     529.8mV
[Falling Waveform]
R_fixture = 50
V_fixture = 0
V_fixture_min = 0
V_fixture_max = 0
0s        1.068V     657.3mV    1.349V
459ps     1.073V     657.2mV    1.324V
774ps     1.051V     659.1mV    1.156V
927ps     1.019V     662.5mV    935.5mV
1.305ns   844.9mV    665mV      166.9mV
1.494ns   680.2mV    655.9mV    11.63mV
2.052ns   167mV      576.7mV    969uV
2.34ns    23.28mV    500.4mV    469.2uV
3.825ns   542.6uV    43.49mV    106.5uV
5.832ns   187.1uV    1.635mV    31.46uV
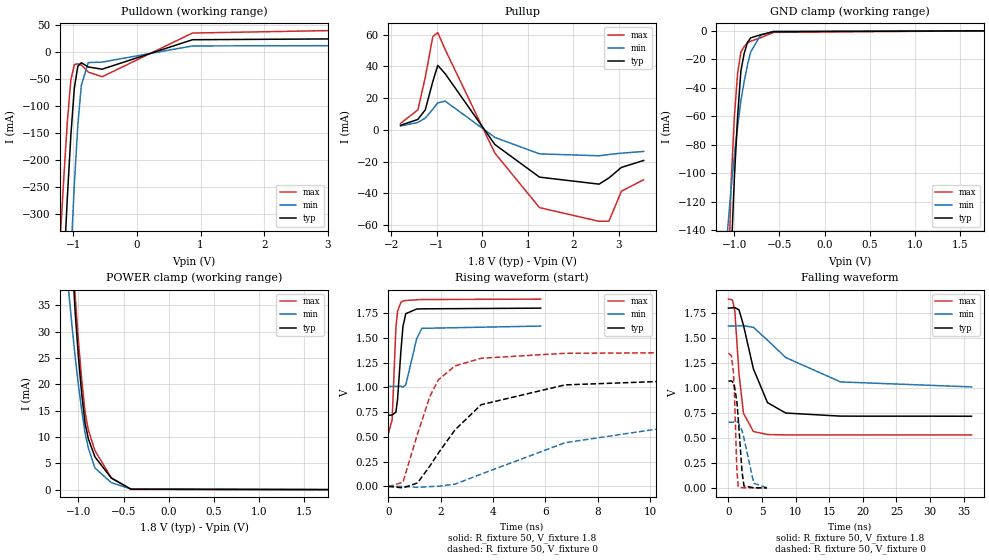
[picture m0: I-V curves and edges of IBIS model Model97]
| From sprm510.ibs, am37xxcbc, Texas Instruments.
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| Model based on original model for BQ18OMAPSMART1HYFBPBNOPM_SSBHV
|   Sub model PM_VS00L10_PUPD0_1P8
[model]   Model97
|[Input Load]   PI
|[Output Drive] SC00LB10
|Voltage   1.8V
|Mode   I/O
Model_type   I/O
Polarity   Non-Inverting
Enable   Active-Low
Vinl =  0.63
Vinh =  1.17
Cref =  15pF
Rref =  100.0000M
Vref =  0V
Vmeas =  0.9
C_comp   1.410688p   1.256095p   1.577871p
[Model Spec]
Vinl   0.63   0.567   0.6615
Vinh   1.17   1.053   1.2285
[Temperature Range]   25   125   -40
[Voltage Range]   1.8   1.62   1.89
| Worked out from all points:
|   slope of the pulldown table from 0 to 0.27 V, typ, clamps not added: 24.3 ohm
|   slope of the pullup table from 0 to 0.27 V, typ, clamps not added: 29.7 ohm
|   GND clamp passes 1 mA (typ) near -0.60 V on its own axis
|   POWER clamp passes 1 mA (typ) near -0.56 V on its own axis
|   rising waveform, R_fixture 50, V_fixture 1.8: 20-80 % time 176ps typ, 308ps min, 124ps max; typ from 0.718 V to 1.8 V
|   rising waveform, R_fixture 50, V_fixture 0: 20-80 % time 2.13ns typ, 4.77ns min, 1.09ns max; typ from 0 V to 1.07 V
|   falling waveform, R_fixture 50, V_fixture 1.8: 20-80 % time 2.71ns typ, 7.22ns min, 937ps max; typ from 1.8 V to 0.718 V
|   falling waveform, R_fixture 50, V_fixture 0: 20-80 % time 692ps typ, 1.19ns min, 394ps max; typ from 1.07 V to 0 V
[POWER_clamp]
-1.8V     362.5mA    191.4mA    412.8mA
-1.109V   56.69mA    37.71mA    60.38mA
-1.073V   44.6mA     31.22mA    47.8mA
-1.036V   33.44mA    25.04mA    36.59mA
-1V       24.98mA    19.72mA    28.06mA
-963.6mV  18.03mA    14.96mA    20.78mA
-927.3mV  12.59mA    10.77mA    14.74mA
-890.9mV  9.653mA    7.899mA    11.31mA
-818.2mV  6.214mA    4.114mA    7.414mA
-636.4mV  2.183mA    1.307mA    2.238mA
-418.2mV  83.85uA    105.2uA    35.14uA
1.764V    -1.228nA   -79.11nA   -1.453nA
[Pulldown]
-1.8V     -1.718A    -2.61A     -1.406A
-1.2V     -527.4mA   -844.5mA   -339.9mA
-1.145V   -396mA     -683.1mA   -229.1mA
-1.091V   -269mA     -526.7mA   -127.5mA
-1.036V   -153.6mA   -378.9mA   -51.17mA
-981.8mV  -66.34mA   -245.6mA   -22.67mA
-927.3mV  -26mA      -136.2mA   -21.54mA
-872.7mV  -19.34mA   -61.98mA   -23.69mA
-763.6mV  -27.2mA    -19.05mA   -36.72mA
-545.5mV  -31.39mA   -18.17mA   -45.46mA
872.7mV   23.46mA    11.88mA    35.92mA
3.545V    25.34mA    12.51mA    41.58mA
[Pullup]
-1.8V     2.903mA    2.423mA    4.112mA
-1.418V   6.595mA    4.711mA    12.64mA
-1.255V   12.69mA    7.42mA     33.23mA
-1.091V   30.4mA     13mA       58.69mA
-981.8mV  40.63mA    17.02mA    61.3mA
-818.2mV  35.38mA    18.12mA    50.59mA
272.7mV   -9.18mA    -4.728mA   -14.55mA
1.255V    -29.75mA   -15.09mA   -48.97mA
2.564V    -34.17mA   -16.31mA   -57.57mA
2.782V    -30.25mA   -15.5mA    -57.48mA
3.055V    -23.63mA   -14.68mA   -38.61mA
3.545V    -19.25mA   -13.56mA   -31.41mA
[GND_clamp]
-1.8V     -2.82A     -1.192A    -3.165A
-1.073V   -235.7mA   -138.4mA   -192.1mA
-1.036V   -159.5mA   -110.8mA   -107.5mA
-1V       -103.8mA   -87.85mA   -60.67mA
-963.6mV  -60mA      -67.28mA   -29.8mA
-927.3mV  -28.21mA   -49.08mA   -14.9mA
-890.9mV  -15.9mA    -35.48mA   -10.99mA
-854.5mV  -8.138mA   -24.07mA   -8.449mA
-818.2mV  -4.924mA   -14.85mA   -7.266mA
-709.1mV  -2.784mA   -3.064mA   -4.883mA
-563.6mV  -570.2uA   -404.5uA   -1.092mA
1.764V    -11.02pA   583.5nA    3.035nA
[Ramp]
dV/dt_f   0.652402/2.709702n   0.3688845/7.282994n   0.8188993/0.9337118n
dV/dt_r  0.6516893/2.1422n   0.4007569/4.815677n   0.8242985/1.098714n
R_load = 50
[Rising Waveform]
R_fixture = 50
V_fixture = 1.8
V_fixture_min = 1.62
V_fixture_max = 1.89
0s        717.6mV    1.009V     531.9mV
144ps     719.9mV    1.009V     670.1mV
288ps     749mV      1.009V     1.6V
351ps     876.2mV    1.01V      1.767V
477ps     1.357V     1.01V      1.857V
558ps     1.615V     1.001V     1.87V
666ps     1.743V     1.025V     1.876V
1.08ns    1.79V      1.488V     1.884V
1.278ns   1.792V     1.595V     1.886V
5.823ns   1.799V     1.618V     1.89V
[Rising Waveform]
R_fixture = 50
V_fixture = 0
V_fixture_min = 0
V_fixture_max = 0
0s        -329.9uV   112.9uV    -3.663mV
558ps     -15.42mV   -1.107mV   41.15mV
1.116ns   34.5mV     -10.53mV   531mV
1.593ns   207.6mV    -2.554mV   911mV
1.908ns   334.9mV    525.9uV    1.074V
2.547ns   569.5mV    22.38mV    1.216V
3.546ns   824.1mV    123.5mV    1.293V
6.75ns    1.024V     440.3mV    1.343V
10.28ns   1.058V     578.7mV    1.348V
31.18ns   1.068V     655.8mV    1.349V
[Falling Waveform]
R_fixture = 50
V_fixture = 1.8
V_fixture_min = 1.62
V_fixture_max = 1.89
0s        1.8V       1.62V      1.89V
603ps     1.803V     1.62V      1.882V
954ps     1.805V     1.62V      1.769V
1.566ns   1.783V     1.623V     1.146V
2.232ns   1.63V      1.624V     748mV
3.708ns   1.193V     1.608V     564.3mV
5.814ns   853.3mV    1.479V     534.2mV
8.523ns   749.3mV    1.305V     530.1mV
16.68ns   718.3mV    1.061V     529.8mV
36.18ns   717.6mV    1.011V     529.8mV
[Falling Waveform]
R_fixture = 50
V_fixture = 0
V_fixture_min = 0
V_fixture_max = 0
0s        1.068V     657.3mV    1.349V
441ps     1.072V     657.2mV    1.323V
738ps     1.052V     658.5mV    1.162V
891ps     1.02V      661.2mV    943.7mV
1.26ns    859.9mV    663.2mV    169.4mV
1.458ns   693.5mV    653.6mV    12.04mV
2.025ns   159.9mV    571.2mV    919.8uV
2.313ns   19.42mV    495.2mV    434.1uV
3.771ns   517.9uV    46.19mV    74.66uV
5.715ns   167.1uV    1.644mV    16.21uV
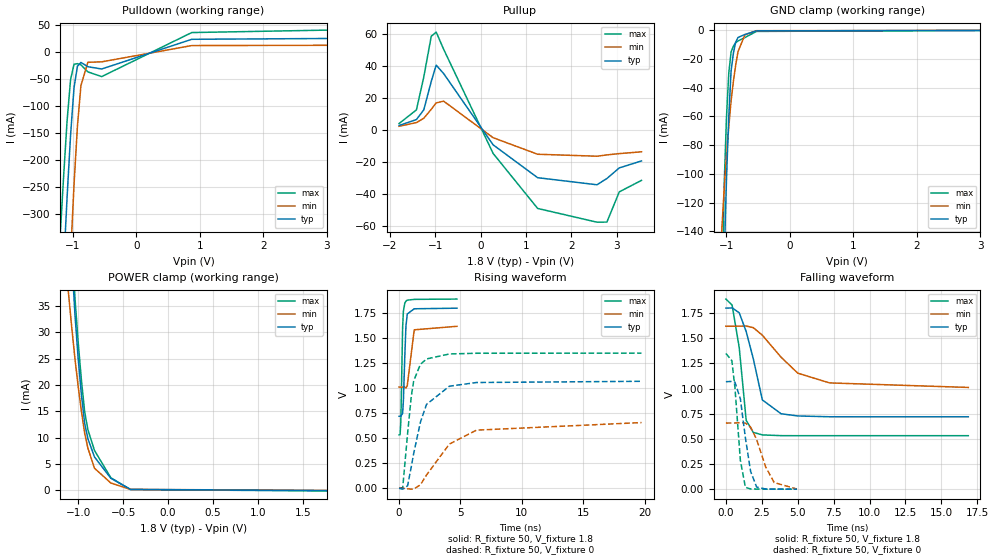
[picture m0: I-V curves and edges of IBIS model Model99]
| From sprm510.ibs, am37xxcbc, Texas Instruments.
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| Model based on original model for BQ18OMAPSMART1HYFBPBNOPM_SSBHV
|   Sub model NOPM_VS10L11_PU1_1P8
[model]   Model99
|[Input Load]   PU
|[Output Drive] SC10LB11
|Voltage   1.8V
|Mode   I/O
Model_type   I/O
Polarity   Non-Inverting
Enable   Active-Low
Vinl =  0.63
Vinh =  1.17
Cref =  15pF
Rref =  100.0000M
Vref =  0V
Vmeas =  0.9
C_comp   1.410688p   1.256095p   1.577871p
[Model Spec]
Vinl   0.63   0.567   0.6615
Vinh   1.17   1.053   1.2285
[Temperature Range]   25   125   -40
[Voltage Range]   1.8   1.62   1.89
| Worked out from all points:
|   slope of the pulldown table from 0 to 0.27 V, typ, clamps not added: 24.3 ohm
|   slope of the pullup table from 0 to 0.27 V, typ, clamps not added: 29.7 ohm
|   GND clamp passes 1 mA (typ) near -0.60 V on its own axis
|   POWER clamp passes 1 mA (typ) near -0.56 V on its own axis
|   rising waveform, R_fixture 50, V_fixture 1.8: 20-80 % time 175ps typ, 304ps min, 123ps max; typ from 0.72 V to 1.8 V
|   rising waveform, R_fixture 50, V_fixture 0: 20-80 % time 1.31ns typ, 2.85ns min, 699ps max; typ from 0.001 V to 1.07 V
|   falling waveform, R_fixture 50, V_fixture 1.8: 20-80 % time 1.03ns typ, 2.54ns min, 606ps max; typ from 1.8 V to 0.72 V
|   falling waveform, R_fixture 50, V_fixture 0: 20-80 % time 603ps typ, 1ns min, 438ps max; typ from 1.07 V to 0.001 V
[POWER_clamp]
-1.8V     362.5mA    191.4mA    412.8mA
-1.109V   56.76mA    37.74mA    60.51mA
-1.073V   44.67mA    31.25mA    47.93mA
-1.036V   33.52mA    25.07mA    36.72mA
-1V       25.06mA    19.75mA    28.2mA
-963.6mV  18.11mA    14.99mA    20.91mA
-927.3mV  12.67mA    10.8mA     14.87mA
-890.9mV  9.734mA    7.935mA    11.44mA
-818.2mV  6.293mA    4.153mA    7.536mA
-636.4mV  2.249mA    1.342mA    2.34mA
-418.2mV  128.7uA    129.3uA    104.4uA
1.764V    -96.73uA   -46.48uA   -163.5uA
[Pulldown]
-1.8V     -1.718A    -2.61A     -1.406A
-1.2V     -527.4mA   -844.5mA   -339.9mA
-1.145V   -396mA     -683.1mA   -229.1mA
-1.091V   -269mA     -526.7mA   -127.5mA
-1.036V   -153.6mA   -378.9mA   -51.17mA
-981.8mV  -66.33mA   -245.6mA   -22.67mA
-927.3mV  -26mA      -136.2mA   -21.54mA
-872.7mV  -19.34mA   -61.98mA   -23.69mA
-763.6mV  -27.2mA    -19.05mA   -36.72mA
-545.5mV  -31.39mA   -18.17mA   -45.46mA
872.7mV   23.46mA    11.88mA    35.92mA
3.545V    25.34mA    12.51mA    41.58mA
[Pullup]
-1.8V     2.903mA    2.423mA    4.112mA
-1.418V   6.595mA    4.711mA    12.64mA
-1.255V   12.69mA    7.42mA     33.24mA
-1.091V   30.4mA     13mA       58.69mA
-981.8mV  40.63mA    17.02mA    61.3mA
-818.2mV  35.38mA    18.12mA    50.59mA
272.7mV   -9.179mA   -4.728mA   -14.55mA
1.255V    -29.75mA   -15.09mA   -48.97mA
2.564V    -34.17mA   -16.31mA   -57.57mA
2.782V    -30.25mA   -15.5mA    -57.49mA
3.055V    -23.63mA   -14.68mA   -38.61mA
3.545V    -19.25mA   -13.56mA   -31.41mA
[GND_clamp]
-1.8V     -2.82A     -1.192A    -3.165A
-1.073V   -235.8mA   -138.4mA   -192.1mA
-1.036V   -159.6mA   -110.8mA   -107.6mA
-1V       -103.8mA   -87.86mA   -60.73mA
-963.6mV  -60.04mA   -67.29mA   -29.86mA
-927.3mV  -28.26mA   -49.09mA   -14.98mA
-890.9mV  -15.95mA   -35.49mA   -11.09mA
-854.5mV  -8.198mA   -24.09mA   -8.559mA
-818.2mV  -4.99mA    -14.87mA   -7.387mA
-709.1mV  -2.858mA   -3.093mA   -5.012mA
-527.3mV  -395.6uA   -260.4uA   -751.2uA
3.6V      0A         0A         0A
[Ramp]
dV/dt_f  0.6499578/1.032671n   0.3671363/2.561324n   0.8165912/0.608644n
dV/dt_r  0.6499828/1.316663n   0.4004765/2.874131n   0.8207613/0.7020089n
R_load = 50
[Rising Waveform]
R_fixture = 50
V_fixture = 1.8
V_fixture_min = 1.62
V_fixture_max = 1.89
0s        720mV      1.011V     534.4mV
81ps      719.8mV    1.011V     535.9mV
144ps     722mV      1.011V     672.2mV
288ps     748.5mV    1.011V     1.607V
351ps     876.4mV    1.011V     1.767V
468ps     1.328V     1.011V     1.851V
558ps     1.618V     1.002V     1.869V
666ps     1.741V     1.025V     1.879V
1.233ns   1.793V     1.583V     1.887V
4.707ns   1.799V     1.618V     1.89V
[Rising Waveform]
R_fixture = 50
V_fixture = 0
V_fixture_min = 0
V_fixture_max = 0
0s        1.173mV    1.058mV    1.994mV
297ps     -7.591mV   727.9uV    7.975mV
693ps     26.6mV     -3.449mV   548.7mV
990ps     213.7mV    -7.541mV   914.5mV
1.188ns   348mV      -7.732mV   1.073V
1.737ns   661.2mV    35.91mV    1.239V
2.232ns   838.4mV    133.2mV    1.292V
4.095ns   1.02V      442.9mV    1.342V
6.3ns     1.057V     581.4mV    1.349V
19.74ns   1.069V     657.1mV    1.35V
[Falling Waveform]
R_fixture = 50
V_fixture = 1.8
V_fixture_min = 1.62
V_fixture_max = 1.89
0s        1.8V       1.62V      1.89V
432ps     1.802V     1.62V      1.83V
927ps     1.754V     1.621V     1.411V
1.413ns   1.567V     1.622V     685mV
1.908ns   1.297V     1.606V     565.4mV
2.538ns   888.1mV    1.531V     540.5mV
3.843ns   750.5mV    1.312V     533.1mV
5.004ns   728.8mV    1.154V     532.6mV
7.218ns   720.7mV    1.057V     532.6mV
16.88ns   720mV      1.012V     532.6mV
[Falling Waveform]
R_fixture = 50
V_fixture = 0
V_fixture_min = 0
V_fixture_max = 0
0s        1.069V     658.7mV    1.35V
414ps     1.072V     658.7mV    1.278V
630ps     1.065V     658.8mV    1.01V
1.008ns   898.5mV    662mV      287.5mV
1.359ns   510.6mV    657.7mV    19.73mV
1.719ns   178.7mV    618.6mV    3.476mV
2.142ns   21.74mV    494.1mV    2.076mV
2.772ns   2.937mV    221.4mV    1.809mV
3.366ns   1.81mV     66.96mV    1.78mV
4.95ns    1.451mV    2.603mV    1.773mV
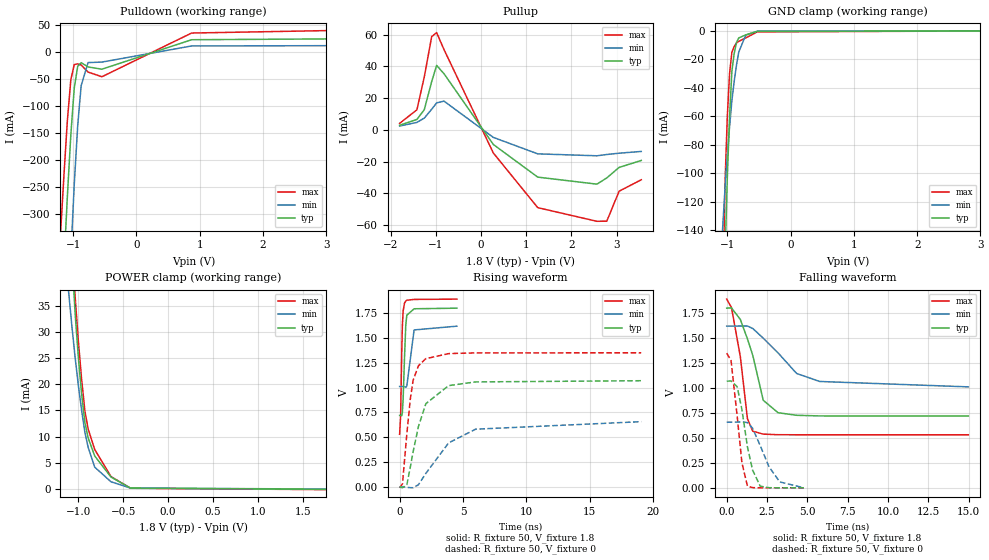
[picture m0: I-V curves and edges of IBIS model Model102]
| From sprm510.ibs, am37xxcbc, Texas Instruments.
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| Model based on original model for BQ18OMAPSMART1HYFBPBNOPM_SSBHV
|   Sub model NOPM_VS01L10_PU1_1P8
[model]   Model102
|[Input Load]   PU
|[Output Drive] SC01LB10
|Voltage   1.8V
|Mode   I/O
Model_type   I/O
Polarity   Non-Inverting
Enable   Active-Low
Vinl =  0.63
Vinh =  1.17
Cref =  15pF
Rref =  100.0000M
Vref =  0V
Vmeas =  0.9
C_comp   1.410688p   1.256095p   1.577871p
[Model Spec]
Vinl   0.63   0.567   0.6615
Vinh   1.17   1.053   1.2285
[Temperature Range]   25   125   -40
[Voltage Range]   1.8   1.62   1.89
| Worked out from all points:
|   slope of the pulldown table from 0 to 0.27 V, typ, clamps not added: 24.3 ohm
|   slope of the pullup table from 0 to 0.27 V, typ, clamps not added: 29.7 ohm
|   GND clamp passes 1 mA (typ) near -0.60 V on its own axis
|   POWER clamp passes 1 mA (typ) near -0.56 V on its own axis
|   rising waveform, R_fixture 50, V_fixture 1.8: 20-80 % time 174ps typ, 300ps min, 123ps max; typ from 0.72 V to 1.8 V
|   rising waveform, R_fixture 50, V_fixture 0: 20-80 % time 1.28ns typ, 2.76ns min, 683ps max; typ from 0.002 V to 1.07 V
|   falling waveform, R_fixture 50, V_fixture 1.8: 20-80 % time 1.08ns typ, 2.19ns min, 680ps max; typ from 1.8 V to 0.72 V
|   falling waveform, R_fixture 50, V_fixture 0: 20-80 % time 675ps typ, 1.09ns min, 501ps max; typ from 1.07 V to 0.001 V
[POWER_clamp]
-1.8V     362.5mA    191.4mA    412.8mA
-1.109V   56.76mA    37.74mA    60.51mA
-1.073V   44.67mA    31.25mA    47.93mA
-1.036V   33.52mA    25.07mA    36.72mA
-1V       25.06mA    19.75mA    28.2mA
-963.6mV  18.11mA    14.99mA    20.91mA
-927.3mV  12.67mA    10.8mA     14.87mA
-890.9mV  9.734mA    7.935mA    11.44mA
-818.2mV  6.293mA    4.153mA    7.536mA
-636.4mV  2.249mA    1.342mA    2.34mA
-418.2mV  128.7uA    129.3uA    104.4uA
1.764V    -96.73uA   -46.48uA   -163.5uA
[Pulldown]
-1.8V     -1.718A    -2.61A     -1.406A
-1.2V     -527.4mA   -844.5mA   -339.9mA
-1.145V   -396mA     -683.1mA   -229.1mA
-1.091V   -269mA     -526.7mA   -127.5mA
-1.036V   -153.6mA   -378.9mA   -51.17mA
-981.8mV  -66.33mA   -245.6mA   -22.67mA
-927.3mV  -26mA      -136.2mA   -21.54mA
-872.7mV  -19.34mA   -61.98mA   -23.69mA
-763.6mV  -27.2mA    -19.05mA   -36.72mA
-545.5mV  -31.39mA   -18.17mA   -45.46mA
872.7mV   23.46mA    11.88mA    35.92mA
3.545V    25.34mA    12.51mA    41.58mA
[Pullup]
-1.8V     2.903mA    2.423mA    4.112mA
-1.418V   6.595mA    4.711mA    12.64mA
-1.255V   12.69mA    7.42mA     33.24mA
-1.091V   30.4mA     13mA       58.69mA
-981.8mV  40.63mA    17.02mA    61.3mA
-818.2mV  35.38mA    18.12mA    50.59mA
272.7mV   -9.179mA   -4.728mA   -14.55mA
1.255V    -29.75mA   -15.09mA   -48.97mA
2.564V    -34.17mA   -16.31mA   -57.57mA
2.782V    -30.25mA   -15.5mA    -57.49mA
3.055V    -23.63mA   -14.68mA   -38.61mA
3.545V    -19.25mA   -13.56mA   -31.41mA
[GND_clamp]
-1.8V     -2.82A     -1.192A    -3.165A
-1.073V   -235.8mA   -138.4mA   -192.1mA
-1.036V   -159.6mA   -110.8mA   -107.6mA
-1V       -103.8mA   -87.86mA   -60.73mA
-963.6mV  -60.04mA   -67.29mA   -29.86mA
-927.3mV  -28.26mA   -49.09mA   -14.98mA
-890.9mV  -15.95mA   -35.49mA   -11.09mA
-854.5mV  -8.198mA   -24.09mA   -8.559mA
-818.2mV  -4.99mA    -14.87mA   -7.387mA
-709.1mV  -2.858mA   -3.093mA   -5.012mA
-527.3mV  -395.6uA   -260.4uA   -751.2uA
3.6V      0A         0A         0A
[Ramp]
dV/dt_f  0.6499137/1.084515n   0.3669915/2.208976n   0.8166389/0.6826828n
dV/dt_r  0.6494815/1.279051n   0.4002587/2.784744n   0.819982/0.6831329n
R_load = 50
[Rising Waveform]
R_fixture = 50
V_fixture = 1.8
V_fixture_min = 1.62
V_fixture_max = 1.89
0s        719.7mV    1.011V     530.2mV
81ps      721.8mV    1.011V     725.6mV
171ps     717.6mV    1.01V      1.374V
216ps     750.3mV    1.011V     1.616V
279ps     886.4mV    1.011V     1.772V
387ps     1.308V     1.011V     1.85V
486ps     1.627V     1.003V     1.871V
567ps     1.728V     1.015V     1.879V
1.143ns   1.793V     1.58V      1.887V
4.518ns   1.799V     1.618V     1.89V
[Rising Waveform]
R_fixture = 50
V_fixture = 0
V_fixture_min = 0
V_fixture_max = 0
0s        1.551mV    1.067mV    -9.042mV
225ps     -8.561mV   764.2uV    31.07mV
576ps     25.61mV    -3.07mV    541.5mV
837ps     194.4mV    -6.978mV   878.5mV
1.062ns   351.9mV    -7.996mV   1.072V
1.485ns   608.1mV    22.58mV    1.219V
2.07ns    838.2mV    136.8mV    1.291V
3.87ns    1.02V      444.1mV    1.342V
5.994ns   1.057V     581.3mV    1.349V
19.06ns   1.069V     657.1mV    1.35V
[Falling Waveform]
R_fixture = 50
V_fixture = 1.8
V_fixture_min = 1.62
V_fixture_max = 1.89
0s        1.8V       1.62V      1.89V
297ps     1.802V     1.62V      1.806V
846ps     1.687V     1.621V     1.315V
1.287ns   1.492V     1.621V     692.5mV
1.62ns    1.326V     1.596V     568.2mV
2.268ns   877.7mV    1.499V     539.1mV
3.186ns   753.4mV    1.352V     533.3mV
4.338ns   727.6mV    1.146V     532.6mV
5.769ns   721.2mV    1.066V     532.6mV
14.99ns   720mV      1.012V     532.6mV
[Falling Waveform]
R_fixture = 50
V_fixture = 0
V_fixture_min = 0
V_fixture_max = 0
0s        1.069V     658.5mV    1.35V
270ps     1.071V     658.8mV    1.275V
648ps     1.014V     659.1mV    721.7mV
945ps     785mV      662.4mV    251.8mV
1.287ns   411.2mV    654.3mV    19.02mV
1.602ns   181.1mV    599.1mV    3.689mV
2.079ns   18.61mV    424mV      2.021mV
2.628ns   3.007mV    211.3mV    1.802mV
3.294ns   1.74mV     60.52mV    1.776mV
4.779ns   1.44mV     2.595mV    1.773mV
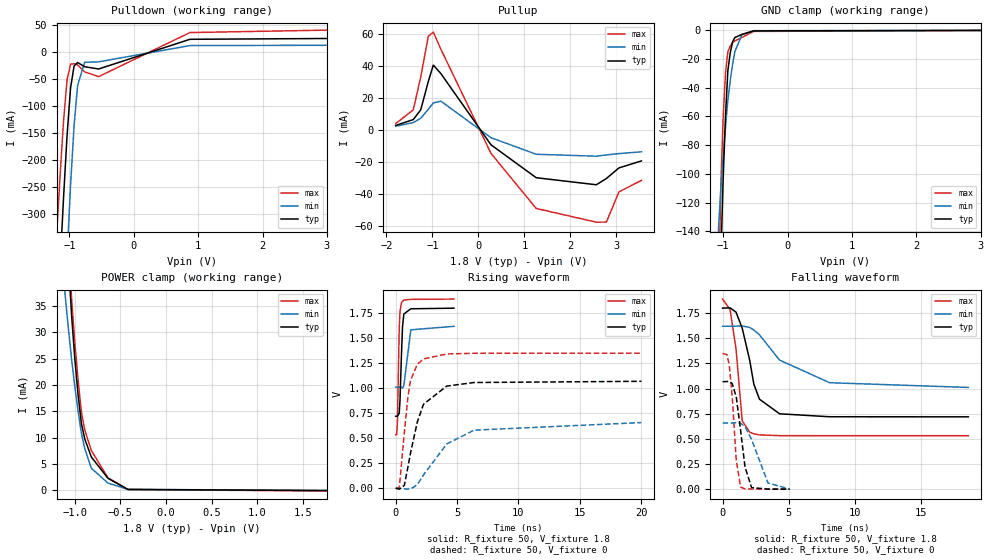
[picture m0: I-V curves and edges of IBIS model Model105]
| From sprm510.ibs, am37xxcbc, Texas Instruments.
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| Model based on original model for BQ18OMAPSMART1HYFBPBNOPM_SSBHV
|   Sub model NOPM_VS10L00_PU1_1P8
[model]   Model105
|[Input Load]   PU
|[Output Drive] SC10LB00
|Voltage   1.8V
|Mode   I/O
Model_type   I/O
Polarity   Non-Inverting
Enable   Active-Low
Vinl =  0.63
Vinh =  1.17
Cref =  15pF
Rref =  100.0000M
Vref =  0V
Vmeas =  0.9
C_comp   1.410688p   1.256095p   1.577871p
[Model Spec]
Vinl   0.63   0.567   0.6615
Vinh   1.17   1.053   1.2285
[Temperature Range]   25   125   -40
[Voltage Range]   1.8   1.62   1.89
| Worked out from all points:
|   slope of the pulldown table from 0 to 0.27 V, typ, clamps not added: 24.3 ohm
|   slope of the pullup table from 0 to 0.27 V, typ, clamps not added: 29.7 ohm
|   GND clamp passes 1 mA (typ) near -0.60 V on its own axis
|   POWER clamp passes 1 mA (typ) near -0.56 V on its own axis
|   rising waveform, R_fixture 50, V_fixture 1.8: 20-80 % time 177ps typ, 307ps min, 124ps max; typ from 0.72 V to 1.8 V
|   rising waveform, R_fixture 50, V_fixture 0: 20-80 % time 1.33ns typ, 2.9ns min, 710ps max; typ from 0.001 V to 1.07 V
|   falling waveform, R_fixture 50, V_fixture 1.8: 20-80 % time 1.11ns typ, 2.95ns min, 573ps max; typ from 1.8 V to 0.72 V
|   falling waveform, R_fixture 50, V_fixture 0: 20-80 % time 591ps typ, 1.02ns min, 414ps max; typ from 1.07 V to 0.001 V
[POWER_clamp]
-1.8V     362.5mA    191.4mA    412.8mA
-1.109V   56.76mA    37.74mA    60.51mA
-1.073V   44.67mA    31.25mA    47.93mA
-1.036V   33.52mA    25.07mA    36.72mA
-1V       25.06mA    19.75mA    28.2mA
-963.6mV  18.11mA    14.99mA    20.91mA
-927.3mV  12.67mA    10.8mA     14.87mA
-890.9mV  9.734mA    7.935mA    11.44mA
-818.2mV  6.293mA    4.153mA    7.536mA
-636.4mV  2.249mA    1.342mA    2.34mA
-418.2mV  128.7uA    129.3uA    104.4uA
1.764V    -96.73uA   -46.48uA   -163.5uA
[Pulldown]
-1.8V     -1.718A    -2.61A     -1.406A
-1.2V     -527.4mA   -844.5mA   -339.9mA
-1.145V   -396mA     -683.1mA   -229.1mA
-1.091V   -269mA     -526.7mA   -127.5mA
-1.036V   -153.6mA   -378.9mA   -51.17mA
-981.8mV  -66.33mA   -245.6mA   -22.67mA
-927.3mV  -26mA      -136.2mA   -21.54mA
-872.7mV  -19.34mA   -61.98mA   -23.69mA
-763.6mV  -27.2mA    -19.05mA   -36.72mA
-545.5mV  -31.39mA   -18.17mA   -45.46mA
872.7mV   23.46mA    11.88mA    35.92mA
3.545V    25.34mA    12.51mA    41.58mA
[Pullup]
-1.8V     2.903mA    2.423mA    4.112mA
-1.418V   6.595mA    4.711mA    12.64mA
-1.255V   12.69mA    7.42mA     33.24mA
-1.091V   30.4mA     13mA       58.69mA
-981.8mV  40.63mA    17.02mA    61.3mA
-818.2mV  35.38mA    18.12mA    50.59mA
272.7mV   -9.179mA   -4.728mA   -14.55mA
1.255V    -29.75mA   -15.09mA   -48.97mA
2.564V    -34.17mA   -16.31mA   -57.57mA
2.782V    -30.25mA   -15.5mA    -57.49mA
3.055V    -23.63mA   -14.68mA   -38.61mA
3.545V    -19.25mA   -13.56mA   -31.41mA
[GND_clamp]
-1.8V     -2.82A     -1.192A    -3.165A
-1.073V   -235.8mA   -138.4mA   -192.1mA
-1.036V   -159.6mA   -110.8mA   -107.6mA
-1V       -103.8mA   -87.86mA   -60.73mA
-963.6mV  -60.04mA   -67.29mA   -29.86mA
-927.3mV  -28.26mA   -49.09mA   -14.98mA
-890.9mV  -15.95mA   -35.49mA   -11.09mA
-854.5mV  -8.198mA   -24.09mA   -8.559mA
-818.2mV  -4.99mA    -14.87mA   -7.387mA
-709.1mV  -2.858mA   -3.093mA   -5.012mA
-527.3mV  -395.6uA   -260.4uA   -751.2uA
3.6V      0A         0A         0A
[Ramp]
dV/dt_f  0.6500764/1.107737n   0.3673119/2.973591n   0.8166489/0.5755958n
dV/dt_r  0.6499421/1.337711n   0.4004304/2.923171n   0.8207582/0.7127259n
R_load = 50
[Rising Waveform]
R_fixture = 50
V_fixture = 1.8
V_fixture_min = 1.62
V_fixture_max = 1.89
0s        720mV      1.011V     534.6mV
81ps      719.8mV    1.011V     536.7mV
144ps     722.1mV    1.011V     673.9mV
288ps     750.3mV    1.011V     1.603V
351ps     879.8mV    1.012V     1.766V
468ps     1.327V     1.011V     1.851V
558ps     1.616V     1.002V     1.868V
666ps     1.741V     1.027V     1.879V
1.233ns   1.793V     1.583V     1.887V
4.743ns   1.799V     1.618V     1.89V
[Rising Waveform]
R_fixture = 50
V_fixture = 0
V_fixture_min = 0
V_fixture_max = 0
0s        1.124mV    1.066mV    763uV
297ps     -7.793mV   751.1uV    10.13mV
702ps     29.94mV    -3.957mV   554.4mV
1.008ns   220.5mV    -7.675mV   923.3mV
1.206ns   351.9mV    -7.025mV   1.076V
1.764ns   664.1mV    37.54mV    1.24V
2.268ns   840.3mV    134.9mV    1.292V
4.158ns   1.021V     443.2mV    1.342V
6.39ns    1.057V     581.2mV    1.349V
20.03ns   1.069V     657.1mV    1.35V
[Falling Waveform]
R_fixture = 50
V_fixture = 1.8
V_fixture_min = 1.62
V_fixture_max = 1.89
0s        1.8V       1.62V      1.89V
567ps     1.803V     1.62V      1.786V
1.017ns   1.76V      1.621V     1.397V
1.485ns   1.602V     1.623V     680.4mV
2.052ns   1.282V     1.608V     567.8mV
2.367ns   1.044V     1.583V     550.8mV
2.79ns    895.3mV    1.535V     540.6mV
4.311ns   750.3mV    1.284V     533mV
8.1ns     720.7mV    1.059V     532.6mV
18.59ns   720mV      1.012V     532.6mV
[Falling Waveform]
R_fixture = 50
V_fixture = 0
V_fixture_min = 0
V_fixture_max = 0
0s        1.069V     658.7mV    1.35V
342ps     1.071V     658.8mV    1.338V
513ps     1.072V     658.7mV    1.224V
729ps     1.05V      659.2mV    926.9mV
1.035ns   918.7mV    662.5mV    288.6mV
1.368ns   581.5mV    656.4mV    21.28mV
1.701ns   219.9mV    622.4mV    3.82mV
2.196ns   17mV       494.9mV    2.078mV
3.438ns   1.833mV    62.08mV    1.785mV
5.076ns   1.463mV    2.591mV    1.773mV
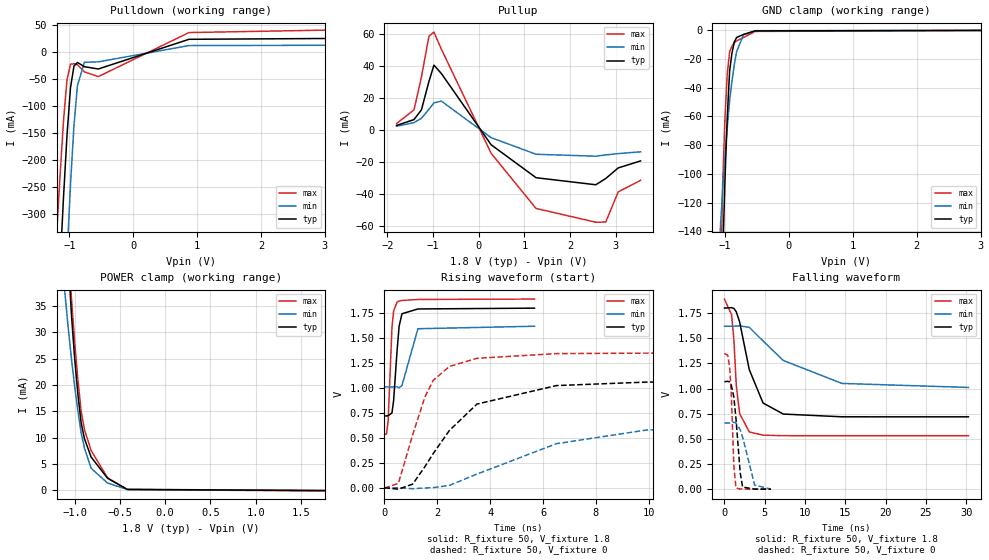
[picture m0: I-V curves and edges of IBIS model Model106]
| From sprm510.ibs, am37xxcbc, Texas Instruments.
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| Model based on original model for BQ18OMAPSMART1HYFBPBNOPM_SSBHV
|   Sub model NOPM_VS00L11_PU1_1P8
[model]   Model106
|[Input Load]   PU
|[Output Drive] SC00LB11
|Voltage   1.8V
|Mode   I/O
Model_type   I/O
Polarity   Non-Inverting
Enable   Active-Low
Vinl =  0.63
Vinh =  1.17
Cref =  15pF
Rref =  100.0000M
Vref =  0V
Vmeas =  0.9
C_comp   1.410688p   1.256095p   1.577871p
[Model Spec]
Vinl   0.63   0.567   0.6615
Vinh   1.17   1.053   1.2285
[Temperature Range]   25   125   -40
[Voltage Range]   1.8   1.62   1.89
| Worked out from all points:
|   slope of the pulldown table from 0 to 0.27 V, typ, clamps not added: 24.3 ohm
|   slope of the pullup table from 0 to 0.27 V, typ, clamps not added: 29.7 ohm
|   GND clamp passes 1 mA (typ) near -0.60 V on its own axis
|   POWER clamp passes 1 mA (typ) near -0.56 V on its own axis
|   rising waveform, R_fixture 50, V_fixture 1.8: 20-80 % time 175ps typ, 306ps min, 122ps max; typ from 0.72 V to 1.8 V
|   rising waveform, R_fixture 50, V_fixture 0: 20-80 % time 2.07ns typ, 4.62ns min, 1.07ns max; typ from 0.001 V to 1.07 V
|   falling waveform, R_fixture 50, V_fixture 1.8: 20-80 % time 2.11ns typ, 5.91ns min, 730ps max; typ from 1.8 V to 0.72 V
|   falling waveform, R_fixture 50, V_fixture 0: 20-80 % time 638ps typ, 1.14ns min, 382ps max; typ from 1.07 V to 0.002 V
[POWER_clamp]
-1.8V     362.5mA    191.4mA    412.8mA
-1.109V   56.76mA    37.74mA    60.51mA
-1.073V   44.67mA    31.25mA    47.93mA
-1.036V   33.52mA    25.07mA    36.72mA
-1V       25.06mA    19.75mA    28.2mA
-963.6mV  18.11mA    14.99mA    20.91mA
-927.3mV  12.67mA    10.8mA     14.87mA
-890.9mV  9.734mA    7.935mA    11.44mA
-818.2mV  6.293mA    4.153mA    7.536mA
-636.4mV  2.249mA    1.342mA    2.34mA
-418.2mV  128.7uA    129.3uA    104.4uA
1.764V    -96.73uA   -46.48uA   -163.5uA
[Pulldown]
-1.8V     -1.718A    -2.61A     -1.406A
-1.2V     -527.4mA   -844.5mA   -339.9mA
-1.145V   -396mA     -683.1mA   -229.1mA
-1.091V   -269mA     -526.7mA   -127.5mA
-1.036V   -153.6mA   -378.9mA   -51.17mA
-981.8mV  -66.33mA   -245.6mA   -22.67mA
-927.3mV  -26mA      -136.2mA   -21.54mA
-872.7mV  -19.34mA   -61.98mA   -23.69mA
-763.6mV  -27.2mA    -19.05mA   -36.72mA
-545.5mV  -31.39mA   -18.17mA   -45.46mA
872.7mV   23.46mA    11.88mA    35.92mA
3.545V    25.34mA    12.51mA    41.58mA
[Pullup]
-1.8V     2.903mA    2.423mA    4.112mA
-1.418V   6.595mA    4.711mA    12.64mA
-1.255V   12.69mA    7.42mA     33.24mA
-1.091V   30.4mA     13mA       58.69mA
-981.8mV  40.63mA    17.02mA    61.3mA
-818.2mV  35.38mA    18.12mA    50.59mA
272.7mV   -9.179mA   -4.728mA   -14.55mA
1.255V    -29.75mA   -15.09mA   -48.97mA
2.564V    -34.17mA   -16.31mA   -57.57mA
2.782V    -30.25mA   -15.5mA    -57.49mA
3.055V    -23.63mA   -14.68mA   -38.61mA
3.545V    -19.25mA   -13.56mA   -31.41mA
[GND_clamp]
-1.8V     -2.82A     -1.192A    -3.165A
-1.073V   -235.8mA   -138.4mA   -192.1mA
-1.036V   -159.6mA   -110.8mA   -107.6mA
-1V       -103.8mA   -87.86mA   -60.73mA
-963.6mV  -60.04mA   -67.29mA   -29.86mA
-927.3mV  -28.26mA   -49.09mA   -14.98mA
-890.9mV  -15.95mA   -35.49mA   -11.09mA
-854.5mV  -8.198mA   -24.09mA   -8.559mA
-818.2mV  -4.99mA    -14.87mA   -7.387mA
-709.1mV  -2.858mA   -3.093mA   -5.012mA
-527.3mV  -395.6uA   -260.4uA   -751.2uA
3.6V      0A         0A         0A
[Ramp]
dV/dt_f  0.6507628/2.102632n   0.367976/5.955891n   0.8169046/0.7310831n
dV/dt_r  0.6505096/2.079124n   0.4004835/4.663376n   0.8217319/1.07002n
R_load = 50
[Rising Waveform]
R_fixture = 50
V_fixture = 1.8
V_fixture_min = 1.62
V_fixture_max = 1.89
0s        720mV      1.011V     534.6mV
81ps      719.8mV    1.011V     539.2mV
144ps     722.2mV    1.011V     672.6mV
288ps     750.3mV    1.01V      1.606V
351ps     877mV      1.012V     1.771V
477ps     1.36V      1.011V     1.858V
558ps     1.618V     1.002V     1.871V
666ps     1.743V     1.025V     1.876V
1.269ns   1.791V     1.593V     1.886V
5.679ns   1.799V     1.618V     1.89V
[Rising Waveform]
R_fixture = 50
V_fixture = 0
V_fixture_min = 0
V_fixture_max = 0
0s        1.06mV     1.078mV    -1.763mV
531ps     -13.04mV   603.1uV    44.68mV
1.071ns   37.33mV    -8.493mV   532.1mV
1.539ns   214.6mV    -806.1uV   913.6mV
1.845ns   342.6mV    2.532mV    1.075V
2.457ns   573.7mV    24.64mV    1.215V
3.501ns   838.8mV    137.7mV    1.297V
6.507ns   1.024V     442.2mV    1.344V
9.927ns   1.059V     579.8mV    1.349V
30.34ns   1.069V     657.1mV    1.35V
[Falling Waveform]
R_fixture = 50
V_fixture = 1.8
V_fixture_min = 1.62
V_fixture_max = 1.89
0s        1.8V       1.62V      1.89V
891ps     1.805V     1.62V      1.735V
1.179ns   1.797V     1.621V     1.484V
1.476ns   1.763V     1.622V     1.031V
1.89ns    1.663V     1.624V     753.1mV
3.087ns   1.189V     1.609V     569.8mV
4.797ns   857.4mV    1.474V     537.8mV
7.308ns   747.7mV    1.28V      532.9mV
14.58ns   720.4mV    1.052V     532.6mV
30.28ns   720mV      1.012V     532.6mV
[Falling Waveform]
R_fixture = 50
V_fixture = 0
V_fixture_min = 0
V_fixture_max = 0
0s        1.069V     658.7mV    1.35V
432ps     1.073V     658.6mV    1.33V
666ps     1.065V     659mV      1.201V
855ps     1.036V     661.4mV    940.4mV
1.179ns   913.2mV    666.2mV    228mV
1.44ns    699.1mV    658.5mV    13.79mV
1.962ns   164mV      591.9mV    2.988mV
2.259ns   22.19mV    518.2mV    2.325mV
3.762ns   2mV        42.13mV    1.839mV
5.769ns   1.557mV    2.599mV    1.782mV
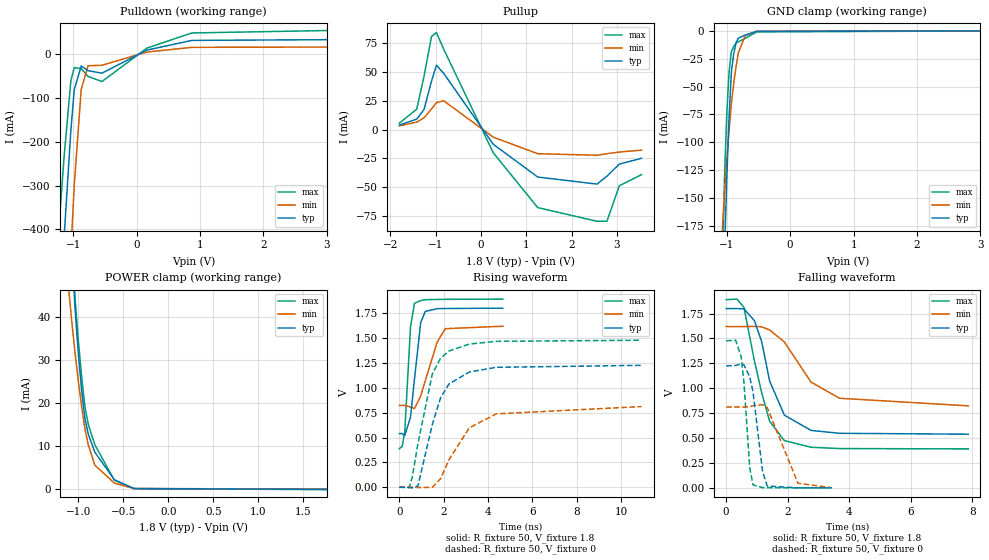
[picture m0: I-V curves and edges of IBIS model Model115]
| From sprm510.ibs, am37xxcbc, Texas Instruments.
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| Model based on original model for BQ18OMAPSMART2HYFBPB_SSBHH
|   Sub model T2HYFBPB_H_0_PU1_1P8
[model]   Model115
|[Input Load]   PU
|[Output Drive] LB0
|Voltage   1.8V
|Mode   I/O
Model_type   I/O
Polarity   Non-Inverting
Enable   Active-Low
Vinl =  0.63
Vinh =  1.17
Cref =  15pF
Rref =  100.0000M
Vref =  0V
Vmeas =  0.9
C_comp   1.528652p   1.368776p   1.69933p
[Model Spec]
Vinl   0.63   0.567   0.6615
Vinh   1.17   1.053   1.2285
[Temperature Range]   25   125   -40
[Voltage Range]   1.8   1.62   1.89
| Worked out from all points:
|   slope of the pulldown table from 0 to 0.27 V, typ, clamps not added: 17.8 ohm
|   slope of the pullup table from 0 to 0.27 V, typ, clamps not added: 21.5 ohm
|   GND clamp passes 1 mA (typ) near -0.57 V on its own axis
|   POWER clamp passes 1 mA (typ) near -0.53 V on its own axis
|   rising waveform, R_fixture 50, V_fixture 1.8: 20-80 % time 341ps typ, 657ps min, 210ps max; typ from 0.54 V to 1.8 V
|   rising waveform, R_fixture 50, V_fixture 0: 20-80 % time 942ps typ, 1.43ns min, 828ps max; typ from 0.001 V to 1.23 V
|   falling waveform, R_fixture 50, V_fixture 1.8: 20-80 % time 683ps typ, 1.19ns min, 665ps max; typ from 1.8 V to 0.54 V
|   falling waveform, R_fixture 50, V_fixture 0: 20-80 % time 282ps typ, 491ps min, 197ps max; typ from 1.23 V to 0.001 V
[POWER_clamp]
-1.8V     449.2mA    229.3mA    499.9mA
-1.109V   70.1mA     46.68mA    71.89mA
-1.073V   55.22mA    38.88mA    57.09mA
-1.036V   41.55mA    31.43mA    44.07mA
-1V       31.28mA    24.96mA    34.35mA
-963.6mV  22.88mA    19.13mA    26.04mA
-927.3mV  16.35mA    13.96mA    19.14mA
-890.9mV  12.8mA     10.36mA    15.1mA
-818.2mV  8.584mA    5.567mA    10.34mA
-600mV    2.149mA    1.354mA    2.023mA
-381.8mV  86.82uA    96.98uA    78.48uA
1.764V    -96.73uA   -46.5uA    -163.5uA
[Pulldown]
-1.8V     -1.866A    -2.926A    -1.473A
-1.255V   -690.3mA   -1.165A    -458.8mA
-1.2V     -556.9mA   -981.3mA   -347.5mA
-1.145V   -424mA     -799.3mA   -238.7mA
-1.036V   -174.1mA   -452.5mA   -60.3mA
-981.8mV  -80.13mA   -298.3mA   -30.04mA
-872.7mV  -26.27mA   -79.78mA   -32.44mA
-763.6mV  -37.27mA   -25.87mA   -50.47mA
-545.5mV  -42.85mA   -24.82mA   -62.02mA
163.6mV   9.905mA    5.464mA    14.49mA
872.7mV   32.06mA    16.22mA    49.12mA
3.545V    34.18mA    16.99mA    56.07mA
[Pullup]
-1.8V     4.02mA     3.353mA    5.71mA
-1.418V   9.153mA    6.524mA    17.71mA
-1.255V   17.65mA    10.28mA    46.46mA
-1.091V   42.13mA    17.99mA    80.98mA
-981.8mV  56.04mA    23.5mA     84.34mA
-818.2mV  48.72mA    25.01mA    69.63mA
272.7mV   -12.68mA   -6.535mA   -20.08mA
1.255V    -41.13mA   -20.87mA   -67.69mA
2.564V    -47.26mA   -22.22mA   -79.57mA
2.782V    -40.42mA   -20.82mA   -79.47mA
3.055V    -29.85mA   -19.43mA   -48.72mA
3.545V    -24.9mA    -17.8mA    -39.06mA
[GND_clamp]
-1.8V     -3.26A     -1.496A    -3.636A
-1.073V   -295.4mA   -181.3mA   -234.2mA
-1.036V   -202.2mA   -145.8mA   -132.6mA
-1V       -132.7mA   -116.1mA   -74.88mA
-963.6mV  -77.6mA    -89.37mA   -36.9mA
-927.3mV  -36.98mA   -65.53mA   -18.61mA
-890.9mV  -20.91mA   -47.52mA   -14.11mA
-854.5mV  -10.79mA   -32.36mA   -11.2mA
-818.2mV  -6.611mA   -20.04mA   -9.885mA
-709.1mV  -3.838mA   -4.175mA   -6.748mA
-527.3mV  -502uA     -336.2uA   -960.8uA
3.6V      0A         0A         0A
[Ramp]
dV/dt_f  0.7577028/0.6823599n  0.4789503/1.19867n   0.904232/0.6675415n
dV/dt_r  0.7385387/0.9427597n  0.4900183/1.439156n   0.8917326/0.8304024n
R_load = 50
[Rising Waveform]
R_fixture = 50
V_fixture = 1.8
V_fixture_min = 1.62
V_fixture_max = 1.89
0s        539.5mV    822.3mV    389.2mV
126ps     539.6mV    822.6mV    410.2mV
243ps     519.7mV    822.3mV    559.6mV
504ps     705.2mV    806.6mV    1.614V
684ps     1.091V     789.5mV    1.848V
963ps     1.655V     918.6mV    1.876V
1.17ns    1.767V     1.071V     1.884V
1.701ns   1.794V     1.455V     1.887V
2.07ns    1.796V     1.593V     1.888V
4.671ns   1.799V     1.618V     1.89V
[Rising Waveform]
R_fixture = 50
V_fixture = 0
V_fixture_min = 0
V_fixture_max = 0
0s        758.8uV    867.8uV    167.9uV
450ps     -4.673mV   2.149mV    445.7uV
585ps     -5.72mV    739.6uV    105.9mV
837ps     13.69mV    -2.4mV     438.5mV
1.485ns   629.2mV    -1.005mV   1.137V
1.863ns   901.8mV    86.69mV    1.297V
2.241ns   1.038V     278.2mV    1.369V
3.159ns   1.158V     597.6mV    1.439V
4.374ns   1.205V     737.4mV    1.466V
10.93ns   1.225V     810.9mV    1.477V
[Falling Waveform]
R_fixture = 50
V_fixture = 1.8
V_fixture_min = 1.62
V_fixture_max = 1.89
0s        1.8V       1.62V      1.89V
351ps     1.8V       1.62V      1.895V
576ps     1.798V     1.62V      1.813V
918ps     1.678V     1.621V     1.275V
1.152ns   1.469V     1.617V     956.8mV
1.413ns   1.072V     1.586V     668.5mV
1.89ns    731mV      1.465V     475.3mV
2.754ns   577.8mV    1.063V     408.7mV
3.681ns   548.6mV    900.4mV    395.6mV
7.866ns   539.7mV    824.1mV    392.2mV
[Falling Waveform]
R_fixture = 50
V_fixture = 0
V_fixture_min = 0
V_fixture_max = 0
0s        1.225V     812.6mV    1.477V
306ps     1.229V     812.9mV    1.483V
486ps     1.245V     812.7mV    1.319V
576ps     1.236V     812.4mV    1.064V
765ps     1.115V     816.1mV    202.1mV
873ps     961.8mV    825.2mV    31.2mV
1.179ns   172.4mV    835.9mV    3.71mV
1.332ns   19.93mV    807.9mV    2.827mV
2.331ns   1.63mV     47.81mV    1.645mV
3.429ns   1.233mV    2.458mV    1.435mV
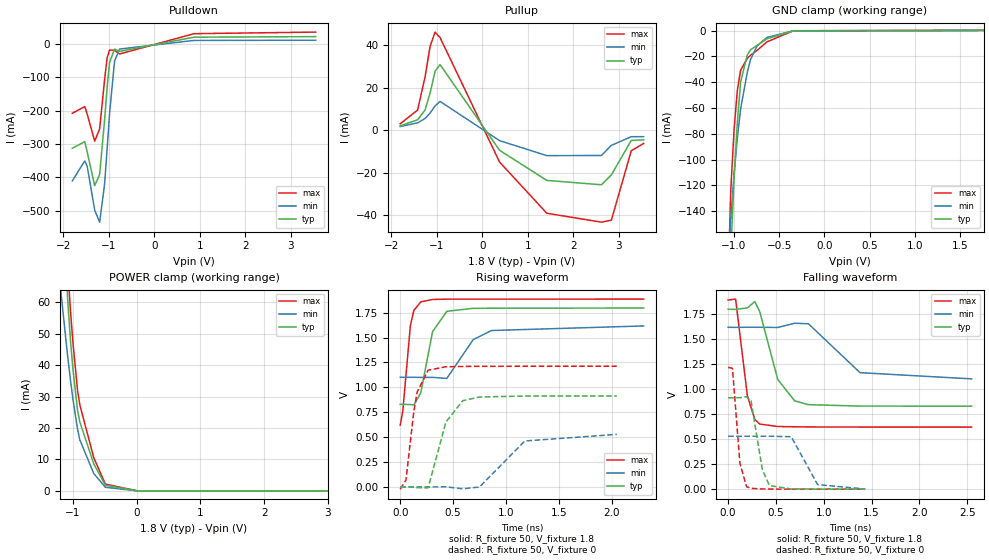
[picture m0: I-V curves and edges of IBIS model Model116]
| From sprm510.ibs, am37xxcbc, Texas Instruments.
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| Model based on original model for BQOMAPGFR50CHYFBPBNOPM_SSBHV
|   Sub model HYFBPBNOPM_V_PD1_1P8
[model]   Model116
|[Input Load]   PD
|[Output Drive]
|Voltage   1.8V
|Mode   I/O
Model_type   I/O
Polarity   Non-Inverting
Enable   Active-Low
Vinl =  0.63
Vinh =  1.17
Cref =  15pF
Rref =  100.0000M
Vref =  0V
Vmeas =  0.9
C_comp   1.661533p   1.48038p   1.850162p
[Model Spec]
Vinl   0.63   0.567   0.6615
Vinh   1.17   1.053   1.2285
[Temperature Range]   25   125   -40
[Voltage Range]   1.8   1.62   1.89
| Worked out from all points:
|   slope of the pulldown table from 0 to 0.27 V, typ, clamps not added: 28.9 ohm
|   slope of the pullup table from 0 to 0.27 V, typ, clamps not added: 39.5 ohm
|   GND clamp passes 1 mA (typ) near -0.46 V on its own axis
|   POWER clamp passes 1 mA (typ) near -0.44 V on its own axis
|   rising waveform, R_fixture 50, V_fixture 1.8: 20-80 % time 112ps typ, 183ps min, 65ps max; typ from 0.829 V to 1.8 V
|   rising waveform, R_fixture 50, V_fixture 0: 20-80 % time 146ps typ, 264ps min, 89.4ps max; typ from -0.001 V to 0.913 V
|   falling waveform, R_fixture 50, V_fixture 1.8: 20-80 % time 182ps typ, 323ps min, 101ps max; typ from 1.8 V to 0.83 V
|   falling waveform, R_fixture 50, V_fixture 0: 20-80 % time 94.3ps typ, 153ps min, 58.2ps max; typ from 0.914 V to 0 V
[POWER_clamp]
-1.8V     350.2mA    199.8mA    415mA
-1.182V   95.17mA    62.15mA    110.3mA
-1.109V   69.62mA    47.9mA     81.05mA
-1.073V   58.12mA    41.25mA    68.34mA
-1.036V   47.39mA    34.88mA    56.74mA
-1V       38.89mA    29.28mA    47.38mA
-927.3mV  25.69mA    19.62mA    32.01mA
-890.9mV  21.87mA    16.22mA    27.32mA
-672.7mV  8.644mA    5.528mA    10.58mA
-490.9mV  1.798mA    1.156mA    2.171mA
18.18mV   0A         0A         0A
3.6V      0A         0A         0A
[Pulldown]
-1.8V     -313.1mA   -410.8mA   -208.2mA
-1.527V   -293.3mA   -350.9mA   -188.2mA
-1.473V   -324.4mA   -367.2mA   -211mA
-1.309V   -425.1mA   -498.2mA   -291.7mA
-1.2V     -391.6mA   -534.5mA   -255.3mA
-1.091V   -227.7mA   -419.3mA   -107mA
-1.036V   -131.1mA   -316mA     -42.16mA
-981.8mV  -55.68mA   -208.4mA   -18.81mA
-872.7mV  -16.14mA   -52.01mA   -19.81mA
-763.6mV  -22.7mA    -15.88mA   -30.69mA
872.7mV   19.66mA    9.937mA    30.15mA
3.545V    21.28mA    10.46mA    34.9mA
[Pullup]
-1.8V     2.19mA     1.826mA    3.106mA
-1.418V   4.982mA    3.55mA     9.585mA
-1.255V   9.598mA    5.591mA    25.18mA
-1.145V   17.5mA     8.127mA    39.43mA
-1.036V   27.75mA    11.5mA     46.22mA
-927.3mV  30.99mA    13.66mA    43.72mA
381.8mV   -9.361mA   -4.816mA   -14.9mA
1.418V    -23.5mA    -11.86mA   -38.93mA
2.618V    -25.57mA   -11.79mA   -43.15mA
2.836V    -20.91mA   -7.019mA   -42.19mA
3.273V    -4.719mA   -2.957mA   -9.576mA
3.545V    -4.444mA   -2.948mA   -6.098mA
[GND_clamp]
-1.8V     -5.203A    -4.842A    -5.388A
-1.073V   -253.8mA   -199.1mA   -208.9mA
-1.036V   -171.9mA   -145.3mA   -123.3mA
-1V       -115.3mA   -111.4mA   -77.08mA
-963.6mV  -71.3mA    -83.17mA   -46.23mA
-927.3mV  -39.92mA   -60.69mA   -30.77mA
-854.5mV  -19.07mA   -32.7mA    -21.66mA
-818.2mV  -14.99mA   -22.63mA   -19.14mA
-745.5mV  -11.44mA   -11.99mA   -15.41mA
-636.4mV  -6.465mA   -5.363mA   -8.804mA
-345.5mV  -143.3uA   -225.8uA   -190.9uA
1.764V    107.4uA    59.01uA    171.2uA
[Ramp]
dV/dt_f  0.6280799/0.1879011n  0.3487892/0.3396302n   0.79769/0.1032107n
dV/dt_r  0.5715734/0.1490916n  0.3346714/0.2730796n  0.7471678/89.42038p
R_load = 50
[Rising Waveform]
R_fixture = 50
V_fixture = 1.8
V_fixture_min = 1.62
V_fixture_max = 1.89
0s        829.1mV    1.101V     620.4mV
24ps      828.9mV    1.101V     761.2mV
96ps      827.3mV    1.101V     1.62V
129ps     822mV      1.101V     1.773V
195ps     945.9mV    1.1V       1.859V
306ps     1.56V      1.1V       1.883V
441ps     1.764V     1.09V      1.886V
690ps     1.794V     1.479V     1.886V
864ps     1.795V     1.571V     1.886V
2.304ns   1.797V     1.617V     1.887V
[Rising Waveform]
R_fixture = 50
V_fixture = 0
V_fixture_min = 0
V_fixture_max = 0
0s        -528.8uV   8.297uV    -23.2mV
54ps      -582.5uV   109.8uV    67.21mV
126ps     -158.6uV   -38.71uV   736.1mV
159ps     -8.392mV   -215.4uV   949.6mV
264ps     -10.09mV   -749.6uV   1.172V
432ps     649.9mV    285.3uV    1.207V
591ps     865.6mV    -19.59mV   1.21V
750ps     903mV      -1.791mV   1.211V
1.179ns   912.4mV    461.1mV    1.212V
2.049ns   913.1mV    527.2mV    1.212V
[Falling Waveform]
R_fixture = 50
V_fixture = 1.8
V_fixture_min = 1.62
V_fixture_max = 1.89
0s        1.799V     1.619V     1.891V
78ps      1.798V     1.618V     1.901V
201ps     1.812V     1.619V     934.3mV
279ps     1.876V     1.619V     697.1mV
330ps     1.777V     1.619V     651.2mV
519ps     1.097V     1.617V     626.5mV
696ps     883mV      1.659V     623.9mV
840ps     844.9mV    1.654V     622.3mV
1.38ns    830.8mV    1.165V     621.1mV
2.547ns   830.1mV    1.103V     621mV
[Falling Waveform]
R_fixture = 50
V_fixture = 0
V_fixture_min = 0
V_fixture_max = 0
0s        914.2mV    529.5mV    1.218V
45ps      914mV      529mV      1.209V
123ps     914.4mV    529.1mV    258.7mV
192ps     925.3mV    529.3mV    24.79mV
240ps     881.5mV    529.2mV    8.227mV
357ps     196.2mV    529mV      2.187mV
432ps     35.97mV    529.5mV    1.065mV
660ps     1.855mV    524.4mV    119.7uV
936ps     634uV      45.58mV    35.35uV
1.434ns   325uV      1.641mV    10.81uV
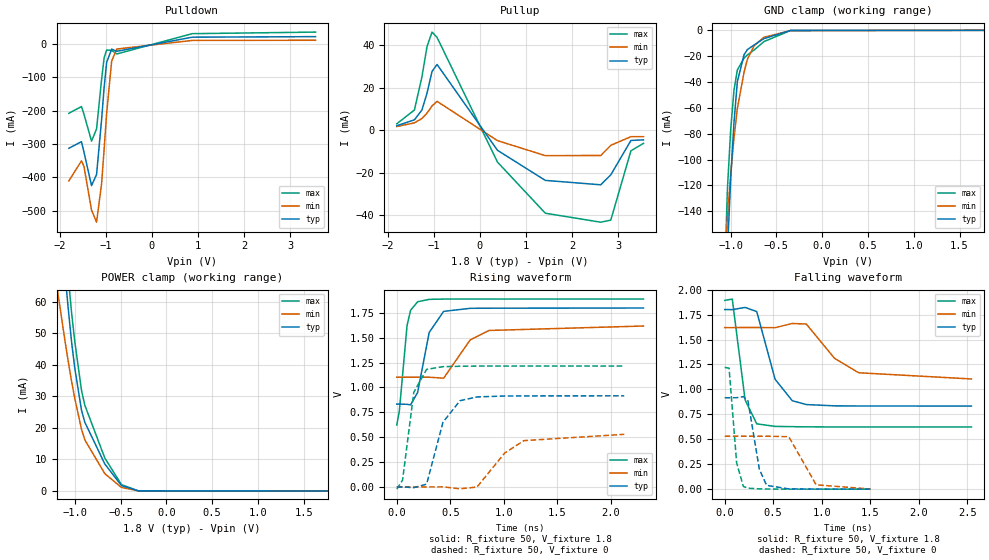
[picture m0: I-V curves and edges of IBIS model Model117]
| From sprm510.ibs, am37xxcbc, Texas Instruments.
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| Model based on original model for BQOMAPGFR50CHYFBPBNOPM_SSBHV
|   Sub model FBPBNOPM_V_PUPD0_1P8
[model]   Model117
|[Input Load]   PI
|[Output Drive]
|Voltage   1.8V
|Mode   I/O
Model_type   I/O
Polarity   Non-Inverting
Enable   Active-Low
Vinl =  0.63
Vinh =  1.17
Cref =  15pF
Rref =  100.0000M
Vref =  0V
Vmeas =  0.9
C_comp   1.661533p   1.48038p   1.850162p
[Model Spec]
Vinl   0.63   0.567   0.6615
Vinh   1.17   1.053   1.2285
[Temperature Range]   25   125   -40
[Voltage Range]   1.8   1.62   1.89
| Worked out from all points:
|   slope of the pulldown table from 0 to 0.27 V, typ, clamps not added: 28.9 ohm
|   slope of the pullup table from 0 to 0.27 V, typ, clamps not added: 39.5 ohm
|   GND clamp passes 1 mA (typ) near -0.46 V on its own axis
|   POWER clamp passes 1 mA (typ) near -0.45 V on its own axis
|   rising waveform, R_fixture 50, V_fixture 1.8: 20-80 % time 112ps typ, 182ps min, 65ps max; typ from 0.832 V to 1.8 V
|   rising waveform, R_fixture 50, V_fixture 0: 20-80 % time 147ps typ, 266ps min, 89.8ps max; typ from -0.001 V to 0.916 V
|   falling waveform, R_fixture 50, V_fixture 1.8: 20-80 % time 182ps typ, 323ps min, 101ps max; typ from 1.8 V to 0.833 V
|   falling waveform, R_fixture 50, V_fixture 0: 20-80 % time 95.3ps typ, 153ps min, 58.6ps max; typ from 0.917 V to 0 V
[POWER_clamp]
-1.8V     350.2mA    199.8mA    415mA
-1.182V   95.12mA    62.14mA    110.2mA
-1.109V   69.56mA    47.88mA    80.94mA
-1.073V   58.06mA    41.23mA    68.23mA
-1.036V   47.33mA    34.85mA    56.63mA
-1V       38.82mA    29.26mA    47.26mA
-927.3mV  25.61mA    19.59mA    31.89mA
-890.9mV  21.79mA    16.19mA    27.19mA
-672.7mV  8.552mA    5.48mA     10.43mA
-490.9mV  1.693mA    1.1mA      2.002mA
-309.1mV  35.51uA    37.34uA    34.61uA
1.764V    -22.63nA   -1.379uA   -121.2nA
[Pulldown]
-1.8V     -313.1mA   -410.8mA   -208.2mA
-1.527V   -293.3mA   -350.9mA   -188.2mA
-1.473V   -324.4mA   -367.2mA   -211mA
-1.309V   -425.1mA   -498.2mA   -291.7mA
-1.2V     -391.6mA   -534.5mA   -255.3mA
-1.091V   -227.7mA   -419.3mA   -107mA
-1.036V   -131.1mA   -316mA     -42.17mA
-981.8mV  -55.69mA   -208.4mA   -18.81mA
-872.7mV  -16.14mA   -52.01mA   -19.81mA
-763.6mV  -22.7mA    -15.88mA   -30.69mA
872.7mV   19.66mA    9.937mA    30.15mA
3.545V    21.28mA    10.46mA    34.9mA
[Pullup]
-1.8V     2.19mA     1.826mA    3.106mA
-1.418V   4.982mA    3.55mA     9.585mA
-1.255V   9.598mA    5.591mA    25.18mA
-1.145V   17.5mA     8.127mA    39.43mA
-1.036V   27.75mA    11.5mA     46.22mA
-927.3mV  30.99mA    13.66mA    43.72mA
381.8mV   -9.36mA    -4.816mA   -14.9mA
1.418V    -23.5mA    -11.86mA   -38.93mA
2.618V    -25.57mA   -11.79mA   -43.15mA
2.836V    -20.91mA   -7.019mA   -42.19mA
3.273V    -4.719mA   -2.957mA   -9.576mA
3.545V    -4.444mA   -2.948mA   -6.098mA
[GND_clamp]
-1.8V     -5.203A    -4.842A    -5.388A
-1.073V   -253.8mA   -199.1mA   -208.8mA
-1.036V   -171.9mA   -145.3mA   -123.3mA
-1V       -115.3mA   -111.4mA   -77.04mA
-963.6mV  -71.26mA   -83.16mA   -46.18mA
-927.3mV  -39.88mA   -60.67mA   -30.71mA
-854.5mV  -19.02mA   -32.68mA   -21.58mA
-818.2mV  -14.94mA   -22.61mA   -19.06mA
-745.5mV  -11.38mA   -11.97mA   -15.33mA
-636.4mV  -6.406mA   -5.334mA   -8.719mA
-345.5mV  -96.99uA   -200.2uA   -122.3uA
1.764V    3.451nA    791.9nA    10.3nA
[Ramp]
dV/dt_f  0.6280062/0.1882186n  0.3484872/0.3397288n  0.7980988/0.1035922n
dV/dt_r  0.5731739/0.1498466n  0.3354919/0.2742353n  0.7491463/89.82892p
R_load = 50
[Rising Waveform]
R_fixture = 50
V_fixture = 1.8
V_fixture_min = 1.62
V_fixture_max = 1.89
0s        832mV      1.103V     622.8mV
24ps      831.9mV    1.103V     764.3mV
96ps      830.3mV    1.103V     1.623V
129ps     824.9mV    1.103V     1.776V
195ps     949.3mV    1.103V     1.862V
303ps     1.553V     1.103V     1.886V
438ps     1.765V     1.093V     1.889V
687ps     1.796V     1.479V     1.889V
861ps     1.797V     1.573V     1.889V
2.307ns   1.799V     1.618V     1.889V
[Rising Waveform]
R_fixture = 50
V_fixture = 0
V_fixture_min = 0
V_fixture_max = 0
0s        -529.4uV   7.902uV    -23.2mV
54ps      -583.1uV   109.4uV    67.19mV
159ps     -8.393mV   -215.8uV   950mV
279ps     27.19mV    -739.5uV   1.182V
432ps     650.1mV    284.8uV    1.209V
591ps     866.6mV    -19.59mV   1.213V
750ps     904.6mV    -1.803mV   1.215V
1.008ns   913.8mV    339.1mV    1.215V
1.188ns   914.8mV    464.9mV    1.215V
2.127ns   915.8mV    528.6mV    1.215V
[Falling Waveform]
R_fixture = 50
V_fixture = 1.8
V_fixture_min = 1.62
V_fixture_max = 1.89
0s        1.801V     1.62V      1.893V
78ps      1.8V       1.62V      1.906V
210ps     1.822V     1.621V     895.4mV
330ps     1.781V     1.621V     655mV
519ps     1.102V     1.619V     629.4mV
696ps     886.8mV    1.661V     626.7mV
840ps     848.4mV    1.656V     624.9mV
1.131ns   835.4mV    1.312V     623.5mV
1.38ns    834mV      1.167V     623.4mV
2.541ns   833.1mV    1.105V     623.4mV
[Falling Waveform]
R_fixture = 50
V_fixture = 0
V_fixture_min = 0
V_fixture_max = 0
0s        916.9mV    530.9mV    1.221V
45ps      916.7mV    530.4mV    1.213V
123ps     917mV      530.5mV    263.3mV
192ps     928mV      530.6mV    26.91mV
240ps     884.7mV    530.6mV    9.769mV
357ps     199.6mV    530.3mV    3.017mV
432ps     37.84mV    530.9mV    1.627mV
660ps     2.527mV    525.9mV    288.7uV
942ps     886.7uV    43.45mV    74.23uV
1.5ns     371.7uV    1.643mV    13.27uV
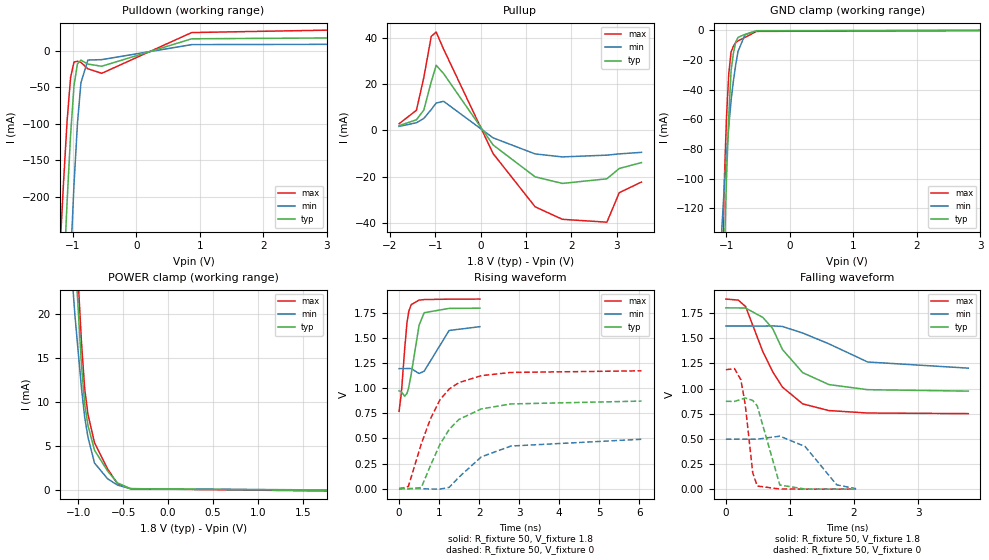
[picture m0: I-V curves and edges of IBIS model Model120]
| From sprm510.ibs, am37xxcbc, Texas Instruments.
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| Model based on original model for BQ1850OMAPSMART2HYFBPB_SSBHV
|   Sub model T2HYFBPB_H50_0_PU1_1P8
[model]   Model120
|[Input Load]   PU
|[Output Drive] LB0
|Voltage   1.8V
|Mode   I/O
Model_type   I/O
Polarity   Non-Inverting
Enable   Active-Low
Vinl =  0.63
Vinh =  1.17
Cref =  15pF
Rref =  100.0000M
Vref =  0V
Vmeas =  0.9
C_comp   1.381241p   1.221452p   1.55612p
[Model Spec]
Vinl   0.63   0.567   0.6615
Vinh   1.17   1.053   1.2285
[Temperature Range]   25   125   -40
[Voltage Range]   1.8   1.62   1.89
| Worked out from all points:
|   slope of the pulldown table from 0 to 0.27 V, typ, clamps not added: 35.5 ohm
|   slope of the pullup table from 0 to 0.27 V, typ, clamps not added: 42.9 ohm
|   GND clamp passes 1 mA (typ) near -0.60 V on its own axis
|   POWER clamp passes 1 mA (typ) near -0.59 V on its own axis
|   rising waveform, R_fixture 50, V_fixture 1.8: 20-80 % time 201ps typ, 346ps min, 135ps max; typ from 0.975 V to 1.8 V
|   rising waveform, R_fixture 50, V_fixture 0: 20-80 % time 789ps typ, 1.03ns min, 728ps max; typ from 0.004 V to 0.872 V
|   falling waveform, R_fixture 50, V_fixture 1.8: 20-80 % time 556ps typ, 805ps min, 522ps max; typ from 1.8 V to 0.974 V
|   falling waveform, R_fixture 50, V_fixture 0: 20-80 % time 185ps typ, 352ps min, 124ps max; typ from 0.873 V to 0.002 V
[POWER_clamp]
-1.8V     290.9mA    160.5mA    340.9mA
-1.109V   45.83mA    30.44mA    51.29mA
-1.073V   36.05mA    25.03mA    40.56mA
-1.036V   26.99mA    19.89mA    30.86mA
-963.6mV  14.28mA    11.63mA    16.86mA
-927.3mV  9.746mA    8.243mA    11.5mA
-890.9mV  7.306mA    5.98mA     8.567mA
-818.2mV  4.49mA     3.024mA    5.342mA
-672.7mV  2.114mA    1.23mA     2.346mA
-563.6mV  762.3uA    511.4uA    680.1uA
-418.2mV  103.6uA    97.29uA    94.35uA
1.764V    -96.73uA   -46.45uA   -163.5uA
[Pulldown]
-1.8V     -1.423A    -2.058A    -1.157A
-1.2V     -415.4mA   -653.2mA   -267mA
-1.145V   -309.6mA   -525.9mA   -177.9mA
-1.091V   -207.6mA   -402.8mA   -96.72mA
-1.036V   -115.8mA   -286.9mA   -37.04mA
-981.8mV  -48.02mA   -183.2mA   -15.64mA
-927.3mV  -18.04mA   -99.43mA   -14.72mA
-872.7mV  -13.22mA   -44mA      -16.16mA
-763.6mV  -18.5mA    -13.02mA   -24.96mA
-545.5mV  -21.5mA    -12.44mA   -31.16mA
872.7mV   16.04mA    8.112mA    24.59mA
3.545V    17.47mA    8.568mA    28.69mA
[Pullup]
-1.8V     2.003mA    1.674mA    2.831mA
-1.418V   4.544mA    3.255mA    8.658mA
-1.255V   8.732mA    5.125mA    22.8mA
-1.091V   20.98mA    8.984mA    40.62mA
-981.8mV  28.13mA    11.78mA    42.49mA
-818.2mV  24.52mA    12.54mA    35.08mA
272.7mV   -6.354mA   -3.271mA   -10.08mA
1.2V      -20.15mA   -10.23mA   -33.12mA
1.8V      -22.99mA   -11.52mA   -38.52mA
2.782V    -21mA      -10.76mA   -39.77mA
3.055V    -16.52mA   -10.21mA   -26.99mA
3.545V    -13.98mA   -9.552mA   -22.39mA
[GND_clamp]
-1.8V     -2.709A    -1.157A    -3.075A
-1.073V   -228.8mA   -133.6mA   -187.2mA
-1.036V   -154.6mA   -106.9mA   -104.7mA
-1V       -100.5mA   -84.7mA    -59.14mA
-963.6mV  -58.02mA   -64.83mA   -29.09mA
-927.3mV  -27.26mA   -47.26mA   -14.57mA
-890.9mV  -15.37mA   -34.15mA   -10.73mA
-854.5mV  -7.879mA   -23.16mA   -8.224mA
-818.2mV  -4.778mA   -14.29mA   -7.06mA
-709.1mV  -2.726mA   -2.962mA   -4.785mA
-527.3mV  -381uA     -250uA     -722.9uA
3.6V      0A         0A         0A
[Ramp]
dV/dt_f  0.4960784/0.5567611n   0.2549/0.8283689n  0.6844666/0.5228174n
dV/dt_r  0.5291423/0.7918358n  0.3007062/1.054056n   0.7117347/0.7297554n
R_load = 50
[Rising Waveform]
R_fixture = 50
V_fixture = 1.8
V_fixture_min = 1.62
V_fixture_max = 1.89
0s        974.7mV    1.196V     770.5mV
57.6ps    963.4mV    1.196V     954.8mV
140ps     921.1mV    1.196V     1.394V
197.6ps   948.3mV    1.197V     1.655V
243.2ps   1.012V     1.197V     1.768V
303.2ps   1.142V     1.196V     1.833V
500ps     1.629V     1.147V     1.879V
628ps     1.753V     1.171V     1.884V
1.25ns    1.796V     1.576V     1.888V
2.02ns    1.798V     1.614V     1.889V
[Rising Waveform]
R_fixture = 50
V_fixture = 0
V_fixture_min = 0
V_fixture_max = 0
0s        3.571mV    1.258mV    -5.321mV
232ps     -3.85mV    991.5uV    22.24mV
554.4ps   10.85mV    -254.1uV   445.3mV
788ps     232.8mV    -3.878mV   700.7mV
1.02ns    440.6mV    -4.882mV   884.6mV
1.253ns   590.4mV    13.03mV    992.9mV
1.493ns   689.1mV    113.3mV    1.056V
2.056ns   794.5mV    316.8mV    1.126V
2.797ns   843.9mV    424.5mV    1.158V
6.058ns   872.4mV    491.9mV    1.174V
[Falling Waveform]
R_fixture = 50
V_fixture = 1.8
V_fixture_min = 1.62
V_fixture_max = 1.89
0s        1.8V       1.62V      1.887V
192ps     1.799V     1.62V      1.877V
307.2ps   1.798V     1.62V      1.813V
576.8ps   1.705V     1.619V     1.366V
730.4ps   1.595V     1.621V     1.167V
884ps     1.386V     1.615V     1.013V
1.2ns     1.157V     1.55V      847.7mV
1.609ns   1.039V     1.443V     781.4mV
2.214ns   988.5mV    1.263V     757.1mV
3.786ns   974.2mV    1.202V     751.2mV
[Falling Waveform]
R_fixture = 50
V_fixture = 0
V_fixture_min = 0
V_fixture_max = 0
0s        873.4mV    497.6mV    1.186V
133.6ps   872.1mV    497.7mV    1.198V
234.4ps   892mV      497.8mV    1.086V
300.8ps   906.5mV    497.8mV    846.4mV
419.2ps   881.7mV    497.6mV    164.6mV
489.6ps   827.6mV    497.4mV    33.19mV
842.4ps   42.9mV     527.7mV    3.773mV
1.237ns   3.37mV     425mV      2.797mV
1.731ns   2.225mV    44.97mV    2.468mV
2.033ns   2.055mV    6.866mV    2.414mV
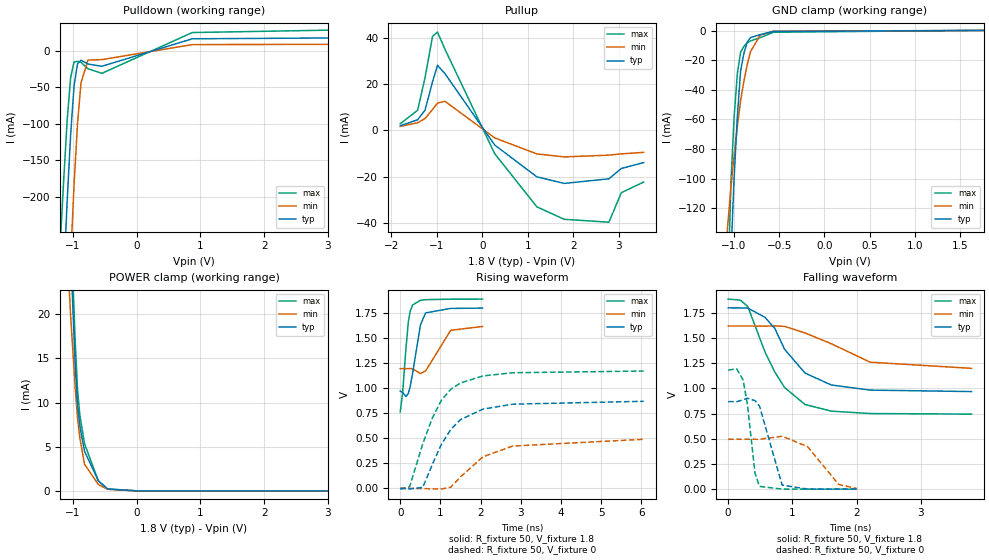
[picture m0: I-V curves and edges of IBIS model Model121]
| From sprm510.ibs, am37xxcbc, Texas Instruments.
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| Model based on original model for BQ1850OMAPSMART2HYFBPB_SSBHV
|   Sub model T2HYFBPB_H50_0_PD1_1P8
[model]   Model121
|[Input Load]   PD
|[Output Drive] LB0
|Voltage   1.8V
|Mode   I/O
Model_type   I/O
Polarity   Non-Inverting
Enable   Active-Low
Vinl =  0.63
Vinh =  1.17
Cref =  15pF
Rref =  100.0000M
Vref =  0V
Vmeas =  0.9
C_comp   1.381241p   1.221452p   1.55612p
[Model Spec]
Vinl   0.63   0.567   0.6615
Vinh   1.17   1.053   1.2285
[Temperature Range]   25   125   -40
[Voltage Range]   1.8   1.62   1.89
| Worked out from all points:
|   slope of the pulldown table from 0 to 0.27 V, typ, clamps not added: 35.5 ohm
|   slope of the pullup table from 0 to 0.27 V, typ, clamps not added: 42.9 ohm
|   GND clamp passes 1 mA (typ) near -0.60 V on its own axis
|   POWER clamp passes 1 mA (typ) near -0.59 V on its own axis
|   rising waveform, R_fixture 50, V_fixture 1.8: 20-80 % time 202ps typ, 347ps min, 137ps max; typ from 0.968 V to 1.8 V
|   rising waveform, R_fixture 50, V_fixture 0: 20-80 % time 792ps typ, 1.03ns min, 732ps max; typ from 0.002 V to 0.868 V
|   falling waveform, R_fixture 50, V_fixture 1.8: 20-80 % time 553ps typ, 803ps min, 519ps max; typ from 1.8 V to 0.968 V
|   falling waveform, R_fixture 50, V_fixture 0: 20-80 % time 184ps typ, 351ps min, 124ps max; typ from 0.869 V to 0 V
[POWER_clamp]
-1.8V     290.9mA    160.5mA    340.9mA
-1.109V   45.82mA    30.44mA    51.27mA
-1.073V   36.03mA    25.02mA    40.54mA
-1.036V   26.98mA    19.88mA    30.85mA
-963.6mV  14.28mA    11.63mA    16.86mA
-927.3mV  9.744mA    8.243mA    11.5mA
-890.9mV  7.306mA    5.982mA    8.573mA
-818.2mV  4.497mA    3.03mA     5.358mA
-600mV    1.141mA    717.7uA    1.118mA
-454.5mV  222.1uA    181.4uA    220.5uA
18.18mV   0A         0A         0A
3.6V      0A         0A         0A
[Pulldown]
-1.8V     -1.423A    -2.058A    -1.157A
-1.2V     -415.4mA   -653.2mA   -267mA
-1.145V   -309.6mA   -525.9mA   -177.9mA
-1.091V   -207.6mA   -402.8mA   -96.73mA
-1.036V   -115.8mA   -286.9mA   -37.04mA
-981.8mV  -48.02mA   -183.2mA   -15.64mA
-927.3mV  -18.04mA   -99.43mA   -14.72mA
-872.7mV  -13.22mA   -44mA      -16.16mA
-763.6mV  -18.5mA    -13.02mA   -24.96mA
-545.5mV  -21.5mA    -12.44mA   -31.16mA
872.7mV   16.04mA    8.112mA    24.59mA
3.545V    17.47mA    8.568mA    28.69mA
[Pullup]
-1.8V     2.003mA    1.674mA    2.831mA
-1.418V   4.544mA    3.255mA    8.658mA
-1.255V   8.732mA    5.125mA    22.8mA
-1.091V   20.98mA    8.984mA    40.62mA
-981.8mV  28.13mA    11.78mA    42.49mA
-818.2mV  24.52mA    12.54mA    35.08mA
272.7mV   -6.354mA   -3.271mA   -10.08mA
1.2V      -20.15mA   -10.23mA   -33.12mA
1.8V      -22.99mA   -11.52mA   -38.52mA
2.782V    -21mA      -10.76mA   -39.77mA
3.055V    -16.52mA   -10.21mA   -26.99mA
3.545V    -13.98mA   -9.552mA   -22.39mA
[GND_clamp]
-1.8V     -2.709A    -1.157A    -3.075A
-1.073V   -228.8mA   -133.6mA   -187.2mA
-1.036V   -154.6mA   -106.9mA   -104.7mA
-1V       -100.5mA   -84.7mA    -59.13mA
-963.6mV  -58.02mA   -64.83mA   -29.07mA
-927.3mV  -27.25mA   -47.26mA   -14.55mA
-890.9mV  -15.37mA   -34.15mA   -10.71mA
-854.5mV  -7.875mA   -23.16mA   -8.201mA
-818.2mV  -4.773mA   -14.29mA   -7.034mA
-709.1mV  -2.717mA   -2.962mA   -4.752mA
-563.6mV  -605.1uA   -417.8uA   -1.132mA
1.764V    97.78uA    54.84uA    156.4uA
[Ramp]
dV/dt_f  0.4985478/0.5540869n  0.2560572/0.8262903n   0.68714/0.5190768n
dV/dt_r  0.5282573/0.7949182n  0.2998479/1.053955n   0.7118473/0.7344482n
R_load = 50
[Rising Waveform]
R_fixture = 50
V_fixture = 1.8
V_fixture_min = 1.62
V_fixture_max = 1.89
0s        968.4mV    1.193V     763.3mV
58.4ps    956.8mV    1.193V     949.1mV
141.6ps   915.2mV    1.193V     1.392V
200ps     944.7mV    1.193V     1.652V
245.6ps   1.01V      1.194V     1.762V
305.6ps   1.141V     1.192V     1.826V
502.4ps   1.627V     1.144V     1.874V
630.4ps   1.748V     1.169V     1.88V
1.255ns   1.793V     1.575V     1.885V
2.048ns   1.796V     1.613V     1.886V
[Rising Waveform]
R_fixture = 50
V_fixture = 0
V_fixture_min = 0
V_fixture_max = 0
0s        1.785mV    77.37uV    -7.923mV
233.6ps   -5.796mV   -185.7uV   16.54mV
560ps     9.484mV    -1.519mV   443.5mV
793.6ps   233.9mV    -5.219mV   696.5mV
1.026ns   440.2mV    -6.403mV   879.6mV
1.259ns   587.9mV    12.56mV    987.4mV
1.498ns   684.9mV    113.4mV    1.05V
2.058ns   789.6mV    314.8mV    1.12V
2.798ns   838.9mV    421.8mV    1.152V
6.057ns   867.6mV    489mV      1.169V
[Falling Waveform]
R_fixture = 50
V_fixture = 1.8
V_fixture_min = 1.62
V_fixture_max = 1.89
0s        1.798V     1.618V     1.885V
191.2ps   1.797V     1.618V     1.874V
305.6ps   1.796V     1.618V     1.811V
573.6ps   1.704V     1.617V     1.361V
726.4ps   1.595V     1.619V     1.162V
879.2ps   1.387V     1.614V     1.008V
1.198ns   1.151V     1.549V     839.4mV
1.607ns   1.033V     1.442V     773.7mV
2.214ns   982.2mV    1.259V     749.9mV
3.793ns   967.9mV    1.198V     744.2mV
[Falling Waveform]
R_fixture = 50
V_fixture = 0
V_fixture_min = 0
V_fixture_max = 0
0s        868.5mV    494.7mV    1.181V
133.6ps   867.2mV    494.7mV    1.193V
233.6ps   887.1mV    494.8mV    1.082V
300ps     901.8mV    494.8mV    841.7mV
417.6ps   878mV      494.7mV    160.6mV
488ps     824.4mV    494.4mV    27.52mV
840.8ps   40.3mV     524.7mV    809.4uV
1.235ns   1.125mV    423mV      314.1uV
1.724ns   339.7uV    46.05mV    88.11uV
2.008ns   223.4uV    5.689mV    48.56uV
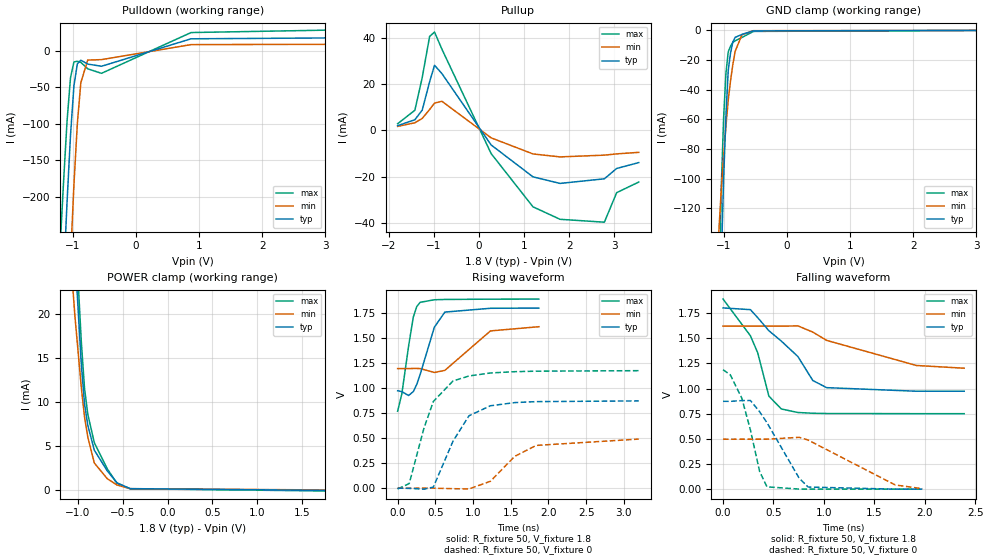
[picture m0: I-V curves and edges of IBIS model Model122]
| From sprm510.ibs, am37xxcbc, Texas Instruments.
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| Model based on original model for BQ1850OMAPSMART2HYFBPB_SSBHV
|   Sub model T2HYFBPB_H50_1_PU1_1P8
[model]   Model122
|[Input Load]   PU
|[Output Drive] LB1
|Voltage   1.8V
|Mode   I/O
Model_type   I/O
Polarity   Non-Inverting
Enable   Active-Low
Vinl =  0.63
Vinh =  1.17
Cref =  15pF
Rref =  100.0000M
Vref =  0V
Vmeas =  0.9
C_comp   1.381241p   1.221452p   1.55612p
[Model Spec]
Vinl   0.63   0.567   0.6615
Vinh   1.17   1.053   1.2285
[Temperature Range]   25   125   -40
[Voltage Range]   1.8   1.62   1.89
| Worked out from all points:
|   slope of the pulldown table from 0 to 0.27 V, typ, clamps not added: 35.5 ohm
|   slope of the pullup table from 0 to 0.27 V, typ, clamps not added: 42.9 ohm
|   GND clamp passes 1 mA (typ) near -0.60 V on its own axis
|   POWER clamp passes 1 mA (typ) near -0.59 V on its own axis
|   rising waveform, R_fixture 50, V_fixture 1.8: 20-80 % time 202ps typ, 354ps min, 129ps max; typ from 0.974 V to 1.8 V
|   rising waveform, R_fixture 50, V_fixture 0: 20-80 % time 330ps typ, 446ps min, 307ps max; typ from 0.002 V to 0.873 V
|   falling waveform, R_fixture 50, V_fixture 1.8: 20-80 % time 449ps typ, 830ps min, 249ps max; typ from 1.8 V to 0.974 V
|   falling waveform, R_fixture 50, V_fixture 0: 20-80 % time 305ps typ, 582ps min, 178ps max; typ from 0.873 V to 0.002 V
[POWER_clamp]
-1.8V     290.9mA    160.5mA    340.9mA
-1.109V   45.83mA    30.44mA    51.29mA
-1.073V   36.05mA    25.03mA    40.56mA
-1.036V   26.99mA    19.89mA    30.86mA
-963.6mV  14.28mA    11.63mA    16.86mA
-927.3mV  9.746mA    8.243mA    11.5mA
-890.9mV  7.306mA    5.98mA     8.567mA
-818.2mV  4.49mA     3.024mA    5.342mA
-672.7mV  2.114mA    1.23mA     2.346mA
-563.6mV  762.3uA    511.4uA    680.1uA
-418.2mV  103.6uA    97.29uA    94.35uA
1.764V    -96.73uA   -46.45uA   -163.5uA
[Pulldown]
-1.8V     -1.423A    -2.058A    -1.157A
-1.2V     -415.4mA   -653.2mA   -267mA
-1.145V   -309.6mA   -525.9mA   -177.9mA
-1.091V   -207.6mA   -402.8mA   -96.72mA
-1.036V   -115.8mA   -286.9mA   -37.04mA
-981.8mV  -48.02mA   -183.2mA   -15.64mA
-927.3mV  -18.04mA   -99.43mA   -14.72mA
-872.7mV  -13.22mA   -44mA      -16.16mA
-763.6mV  -18.5mA    -13.02mA   -24.96mA
-545.5mV  -21.5mA    -12.44mA   -31.16mA
872.7mV   16.04mA    8.112mA    24.59mA
3.545V    17.47mA    8.568mA    28.69mA
[Pullup]
-1.8V     2.003mA    1.674mA    2.831mA
-1.418V   4.544mA    3.255mA    8.658mA
-1.255V   8.732mA    5.125mA    22.8mA
-1.091V   20.98mA    8.984mA    40.62mA
-981.8mV  28.13mA    11.78mA    42.49mA
-818.2mV  24.52mA    12.54mA    35.08mA
272.7mV   -6.354mA   -3.271mA   -10.08mA
1.2V      -20.15mA   -10.23mA   -33.12mA
1.8V      -22.99mA   -11.52mA   -38.52mA
2.782V    -21mA      -10.76mA   -39.77mA
3.055V    -16.52mA   -10.21mA   -26.99mA
3.545V    -13.98mA   -9.552mA   -22.39mA
[GND_clamp]
-1.8V     -2.709A    -1.157A    -3.075A
-1.073V   -228.8mA   -133.6mA   -187.2mA
-1.036V   -154.6mA   -106.9mA   -104.7mA
-1V       -100.5mA   -84.7mA    -59.14mA
-963.6mV  -58.02mA   -64.83mA   -29.09mA
-927.3mV  -27.26mA   -47.26mA   -14.57mA
-890.9mV  -15.37mA   -34.15mA   -10.73mA
-854.5mV  -7.879mA   -23.16mA   -8.224mA
-818.2mV  -4.778mA   -14.29mA   -7.06mA
-709.1mV  -2.726mA   -2.962mA   -4.785mA
-527.3mV  -381uA     -250uA     -722.9uA
3.6V      0A         0A         0A
[Ramp]
dV/dt_f  0.4975348/0.4496031n  0.2563536/0.8425879n  0.6839345/0.2498961n
dV/dt_r  0.5289837/0.3319422n  0.3018866/0.4606824n   0.710828/0.3069686n
R_load = 50
[Rising Waveform]
R_fixture = 50
V_fixture = 1.8
V_fixture_min = 1.62
V_fixture_max = 1.89
0s        974.5mV    1.196V     770.1mV
56ps      965.8mV    1.196V     943.9mV
144.8ps   927.3mV    1.196V     1.418V
208ps     965.9mV    1.197V     1.71V
253.6ps   1.038V     1.197V     1.815V
300ps     1.141V     1.196V     1.858V
487.2ps   1.609V     1.157V     1.883V
626.4ps   1.76V      1.178V     1.886V
1.231ns   1.798V     1.572V     1.889V
1.873ns   1.8V       1.614V     1.89V
[Rising Waveform]
R_fixture = 50
V_fixture = 0
V_fixture_min = 0
V_fixture_max = 0
0s        2.176mV    1.253mV    -6.342mV
153.6ps   -342.7uV   1.057mV    47.72mV
349.6ps   -8.096mV   2.424mV    602.2mV
473.6ps   12.64mV    1.892mV    867.4mV
734.4ps   471.1mV    -3.423mV   1.072V
946.4ps   724.6mV    -5.587mV   1.122V
1.23ns    824.6mV    70.28mV    1.152V
1.553ns   856.3mV    319.9mV    1.165V
1.838ns   866mV      428.7mV    1.17V
3.198ns   873.1mV    491.9mV    1.175V
[Falling Waveform]
R_fixture = 50
V_fixture = 1.8
V_fixture_min = 1.62
V_fixture_max = 1.89
0s        1.8V       1.62V      1.888V
271.2ps   1.783V     1.62V      1.524V
343.2ps   1.704V     1.62V      1.356V
454.4ps   1.574V     1.62V      924.7mV
577.6ps   1.471V     1.619V     797.4mV
741.6ps   1.318V     1.622V     762.8mV
889.6ps   1.08V      1.56V      755mV
1.027ns   1.009V     1.478V     752.5mV
1.916ns   973.7mV    1.229V     751mV
2.39ns    973.5mV    1.202V     751mV
[Falling Waveform]
R_fixture = 50
V_fixture = 0
V_fixture_min = 0
V_fixture_max = 0
0s        873.4mV    497.7mV    1.187V
72ps      873.1mV    497.5mV    1.136V
186.4ps   881mV      497.8mV    903.6mV
272ps     881.4mV    497.8mV    586.2mV
362.4ps   769.7mV    497.7mV    178.4mV
435.2ps   661.5mV    497.6mV    25.04mV
754.4ps   110.8mV    516.2mV    2.783mV
843.2ps   23mV       489.2mV    2.589mV
1.706ns   1.99mV     43.8mV     2.357mV
1.974ns   1.931mV    6.874mV    2.356mV
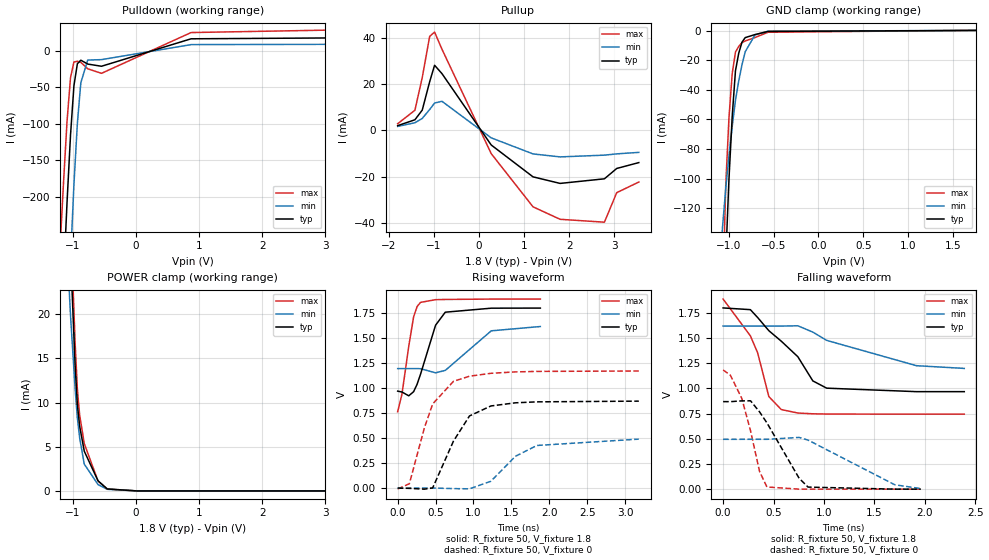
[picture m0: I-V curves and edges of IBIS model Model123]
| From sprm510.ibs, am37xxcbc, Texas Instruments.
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| Model based on original model for BQ1850OMAPSMART2HYFBPB_SSBHV
|   Sub model T2HYFBPB_H50_1_PD1_1P8
[model]   Model123
|[Input Load]   PD
|[Output Drive] LB1
|Voltage   1.8V
|Mode   I/O
Model_type   I/O
Polarity   Non-Inverting
Enable   Active-Low
Vinl =  0.63
Vinh =  1.17
Cref =  15pF
Rref =  100.0000M
Vref =  0V
Vmeas =  0.9
C_comp   1.381241p   1.221452p   1.55612p
[Model Spec]
Vinl   0.63   0.567   0.6615
Vinh   1.17   1.053   1.2285
[Temperature Range]   25   125   -40
[Voltage Range]   1.8   1.62   1.89
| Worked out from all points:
|   slope of the pulldown table from 0 to 0.27 V, typ, clamps not added: 35.5 ohm
|   slope of the pullup table from 0 to 0.27 V, typ, clamps not added: 42.9 ohm
|   GND clamp passes 1 mA (typ) near -0.60 V on its own axis
|   POWER clamp passes 1 mA (typ) near -0.59 V on its own axis
|   rising waveform, R_fixture 50, V_fixture 1.8: 20-80 % time 203ps typ, 355ps min, 130ps max; typ from 0.968 V to 1.8 V
|   rising waveform, R_fixture 50, V_fixture 0: 20-80 % time 330ps typ, 445ps min, 308ps max; typ from 0 V to 0.868 V
|   falling waveform, R_fixture 50, V_fixture 1.8: 20-80 % time 448ps typ, 830ps min, 248ps max; typ from 1.8 V to 0.967 V
|   falling waveform, R_fixture 50, V_fixture 0: 20-80 % time 304ps typ, 581ps min, 177ps max; typ from 0.869 V to 0 V
[POWER_clamp]
-1.8V     290.9mA    160.5mA    340.9mA
-1.109V   45.82mA    30.44mA    51.27mA
-1.073V   36.03mA    25.02mA    40.54mA
-1.036V   26.98mA    19.88mA    30.85mA
-963.6mV  14.28mA    11.63mA    16.86mA
-927.3mV  9.744mA    8.243mA    11.5mA
-890.9mV  7.306mA    5.982mA    8.573mA
-818.2mV  4.497mA    3.03mA     5.358mA
-600mV    1.141mA    717.7uA    1.118mA
-454.5mV  222.1uA    181.4uA    220.5uA
18.18mV   0A         0A         0A
3.6V      0A         0A         0A
[Pulldown]
-1.8V     -1.423A    -2.058A    -1.157A
-1.2V     -415.4mA   -653.2mA   -267mA
-1.145V   -309.6mA   -525.9mA   -177.9mA
-1.091V   -207.6mA   -402.8mA   -96.73mA
-1.036V   -115.8mA   -286.9mA   -37.04mA
-981.8mV  -48.02mA   -183.2mA   -15.64mA
-927.3mV  -18.04mA   -99.43mA   -14.72mA
-872.7mV  -13.22mA   -44mA      -16.16mA
-763.6mV  -18.5mA    -13.02mA   -24.96mA
-545.5mV  -21.5mA    -12.44mA   -31.16mA
872.7mV   16.04mA    8.112mA    24.59mA
3.545V    17.47mA    8.568mA    28.69mA
[Pullup]
-1.8V     2.003mA    1.674mA    2.831mA
-1.418V   4.544mA    3.255mA    8.658mA
-1.255V   8.732mA    5.125mA    22.8mA
-1.091V   20.98mA    8.984mA    40.62mA
-981.8mV  28.13mA    11.78mA    42.49mA
-818.2mV  24.52mA    12.54mA    35.08mA
272.7mV   -6.354mA   -3.271mA   -10.08mA
1.2V      -20.15mA   -10.23mA   -33.12mA
1.8V      -22.99mA   -11.52mA   -38.52mA
2.782V    -21mA      -10.76mA   -39.77mA
3.055V    -16.52mA   -10.21mA   -26.99mA
3.545V    -13.98mA   -9.552mA   -22.39mA
[GND_clamp]
-1.8V     -2.709A    -1.157A    -3.075A
-1.073V   -228.8mA   -133.6mA   -187.2mA
-1.036V   -154.6mA   -106.9mA   -104.7mA
-1V       -100.5mA   -84.7mA    -59.13mA
-963.6mV  -58.02mA   -64.83mA   -29.07mA
-927.3mV  -27.25mA   -47.26mA   -14.55mA
-890.9mV  -15.37mA   -34.15mA   -10.71mA
-854.5mV  -7.875mA   -23.16mA   -8.201mA
-818.2mV  -4.773mA   -14.29mA   -7.034mA
-709.1mV  -2.717mA   -2.962mA   -4.752mA
-563.6mV  -605.1uA   -417.8uA   -1.132mA
1.764V    97.78uA    54.84uA    156.4uA
[Ramp]
dV/dt_f  0.5000209/0.4489912n  0.2575108/0.8423634n  0.6865656/0.2491475n
dV/dt_r  0.5275146/0.3318347n  0.3009437/0.4595866n  0.7092752/0.3081548n
R_load = 50
[Rising Waveform]
R_fixture = 50
V_fixture = 1.8
V_fixture_min = 1.62
V_fixture_max = 1.89
0s        968.2mV    1.193V     762.8mV
56.8ps    959.3mV    1.193V     938.1mV
146.4ps   921.5mV    1.193V     1.416V
210.4ps   962.5mV    1.193V     1.709V
256ps     1.036V     1.193V     1.812V
301.6ps   1.137V     1.192V     1.854V
500ps     1.626V     1.151V     1.881V
628ps     1.756V     1.175V     1.883V
1.234ns   1.796V     1.57V      1.887V
1.882ns   1.797V     1.613V     1.887V
[Rising Waveform]
R_fixture = 50
V_fixture = 0
V_fixture_min = 0
V_fixture_max = 0
0s        385.3uV    72.09uV    -8.82mV
154.4ps   -2.154mV   -125.5uV   44.38mV
351.2ps   -10.29mV   1.269mV    598.4mV
461.6ps   1.943mV    920.4uV    839.9mV
736ps     469.1mV    -4.684mV   1.066V
947.2ps   720.3mV    -6.978mV   1.117V
1.23ns    820.1mV    68.89mV    1.146V
1.553ns   851.5mV    317.6mV    1.16V
1.837ns   861.2mV    425.9mV    1.165V
3.181ns   868.2mV    489mV      1.169V
[Falling Waveform]
R_fixture = 50
V_fixture = 1.8
V_fixture_min = 1.62
V_fixture_max = 1.89
0s        1.798V     1.618V     1.886V
270.4ps   1.781V     1.618V     1.521V
342.4ps   1.703V     1.618V     1.353V
453.6ps   1.572V     1.618V     918.4mV
576.8ps   1.468V     1.618V     789.8mV
740.8ps   1.314V     1.621V     755.4mV
889.6ps   1.074V     1.558V     747.7mV
1.027ns   1.002V     1.476V     745.3mV
1.917ns   967.4mV    1.225V     744mV
2.391ns   967.3mV    1.198V     744mV
[Falling Waveform]
R_fixture = 50
V_fixture = 0
V_fixture_min = 0
V_fixture_max = 0
0s        868.5mV    494.7mV    1.182V
71.2ps    868.2mV    494.6mV    1.132V
185.6ps   875.9mV    494.8mV    899.8mV
272ps     876.7mV    494.8mV    578.6mV
361.6ps   766.2mV    494.8mV    175.2mV
434.4ps   657.8mV    494.6mV    21.7mV
753.6ps   108.3mV    513.3mV    164.1uV
842.4ps   20.52mV    486.8mV    72.64uV
1.702ns   143.8uV    43.72mV    939.7nV
1.959ns   111.5uV    5.688mV    757.2nV
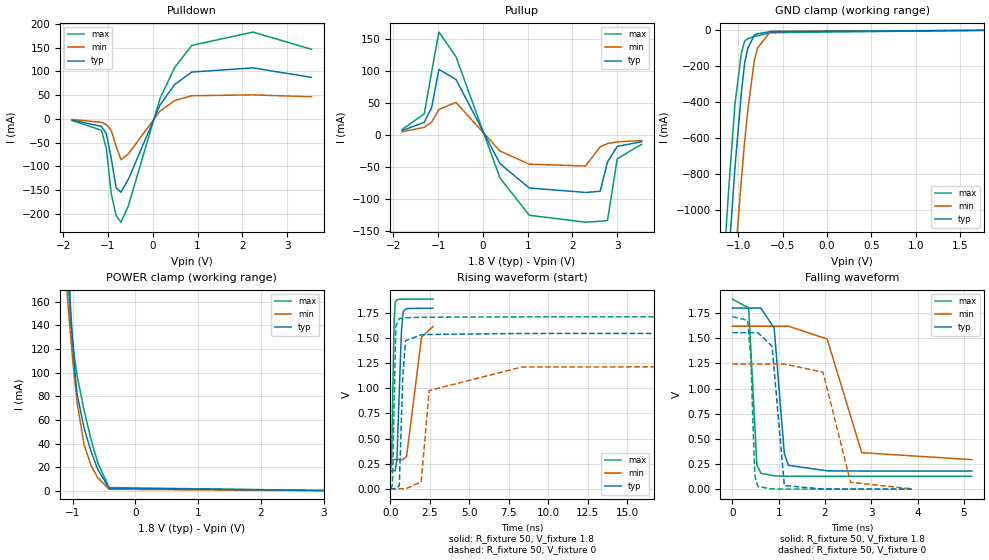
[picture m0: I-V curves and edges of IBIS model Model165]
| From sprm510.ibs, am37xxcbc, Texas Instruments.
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| Model based on original model for BQMMC1833DVHYPBFZLP18_SSCHH
|   Sub model H_SPEEDCTRL1_PD1_1P8
[model]   Model165
|[Input Load]   PD
|[Output Drive] SC1
|Voltage   1.8V
|Mode   I/O
Model_type   I/O
Polarity   Non-Inverting
Enable   Active-Low
Vinl =  0.54
Vinh =  1.26
Cref =  15pF
Rref =  100.0000M
Vref =  0V
Vmeas =  0.9
C_comp   6.565579p   6.22498p   6.65822p
[Model Spec]
Vinl   0.54   0.486   0.567
Vinh   1.26   1.134   1.323
[Temperature Range]   25   125   -40
[Voltage Range]   1.8   1.62   1.89
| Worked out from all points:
|   slope of the pulldown table from 0 to 0.27 V, typ, clamps not added: 5.93 ohm
|   slope of the pullup table from 0 to 0.27 V, typ, clamps not added: 8.03 ohm
|   GND clamp passes 1 mA (typ) near -0.52 V on its own axis
|   POWER clamp passes 1 mA (typ) near -0.38 V on its own axis
|   rising waveform, R_fixture 50, V_fixture 1.8: 20-80 % time 216ps typ, 611ps min, 115ps max; typ from 0.179 V to 1.8 V
|   rising waveform, R_fixture 50, V_fixture 0: 20-80 % time 186ps typ, 759ps min, 112ps max; typ from 0 V to 1.55 V
|   falling waveform, R_fixture 50, V_fixture 1.8: 20-80 % time 156ps typ, 407ps min, 93.8ps max; typ from 1.8 V to 0.18 V
|   falling waveform, R_fixture 50, V_fixture 0: 20-80 % time 123ps typ, 302ps min, 72.7ps max; typ from 1.56 V to 0.001 V
[POWER_clamp]
-1.8V     1.506A     743.4mA    1.547A
-1.109V   249.7mA    180.9mA    217.2mA
-1.073V   201.1mA    156.2mA    177.1mA
-1.036V   156.8mA    132.4mA    144.9mA
-1V       125.1mA    111.2mA    126mA
-963.6mV  99.89mA    91.72mA    110mA
-927.3mV  81.17mA    73.97mA    96.98mA
-818.2mV  53.15mA    39.05mA    68.03mA
-709.1mV  33.72mA    21.71mA    43.8mA
-600mV    18.2mA     11.1mA     23.73mA
-418.2mV  2.266mA    1.393mA    2.799mA
3.6V      0A         0A         0A
[Pulldown]
-1.8V     -2.955mA   -1.439mA   -3.582mA
-1.145V   -16.06mA   -7.517mA   -24.16mA
-1.036V   -31.52mA   -12.4mA    -62.37mA
-927.3mV  -82.88mA   -24.53mA   -156.9mA
-818.2mV  -145.2mA   -57.9mA    -203.7mA
-709.1mV  -154.6mA   -86.29mA   -217.8mA
-545.5mV  -127.7mA   -74.07mA   -183.7mA
163.6mV   29.41mA    16.22mA    43.13mA
490.9mV   72.28mA    38.36mA    108.1mA
872.7mV   98.4mA     48.52mA    154.5mA
2.236V    107.1mA    50.23mA    182.5mA
3.545V    87.14mA    46.38mA    146.2mA
[Pullup]
-1.8V     6.901mA    5.057mA    8.816mA
-1.309V   19.93mA    12.08mA    33.18mA
-1.145V   42.64mA    20.25mA    98.48mA
-981.8mV  102.9mA    40.1mA     161.5mA
-600mV    87.24mA    51.07mA    122.7mA
381.8mV   -45.05mA   -25.09mA   -67.44mA
1.036V    -83.14mA   -45.78mA   -125.9mA
2.291V    -90.12mA   -48.67mA   -136.8mA
2.618V    -88.34mA   -18.52mA   -135.3mA
2.782V    -42.42mA   -13.42mA   -134.2mA
3V        -17.89mA   -10.8mA    -37.28mA
3.545V    -10.46mA   -8.646mA   -14.45mA
[GND_clamp]
-1.8V     -7.151A    -7.205A    -6.863A
-1.182V   -1.844A    -2.309A    -1.461A
-1.145V   -1.557A    -2.041A    -1.171A
-1.109V   -1.281A    -1.782A    -899.6mA
-1.036V   -759.7mA   -1.281A    -408.5mA
-963.6mV  -344.6mA   -827mA     -125.9mA
-927.3mV  -181.3mA   -617.3mA   -59.93mA
-890.9mV  -99.98mA   -442.2mA   -45.98mA
-818.2mV  -25.09mA   -166.6mA   -34.17mA
-781.8mV  -19.68mA   -98.02mA   -31.09mA
-636.4mV  -6.261mA   -6.836mA   -13.18mA
1.764V    22.34uA    15.06uA    31.23uA
[Ramp]
dV/dt_f  0.9728432/0.1465857n  0.7979002/0.398144n   1.057723/86.45392p
dV/dt_r  0.9472778/0.1778083n  0.7579716/0.4079959n   1.043629/0.1125647n
R_load = 50
[Rising Waveform]
R_fixture = 50
V_fixture = 1.8
V_fixture_min = 1.62
V_fixture_max = 1.89
0s        179.1mV    290.5mV    126.7mV
88ps      179.1mV    290.5mV    331mV
242ps     178.5mV    290.5mV    1.669V
308ps     178.6mV    290.5mV    1.852V
418ps     283.9mV    290.5mV    1.884V
704ps     1.563V     290.5mV    1.889V
814ps     1.765V     288.9mV    1.889V
1.034ns   1.795V     322.7mV    1.89V
1.98ns    1.799V     1.51V      1.89V
2.706ns   1.799V     1.616V     1.89V
[Rising Waveform]
R_fixture = 50
V_fixture = 0
V_fixture_min = 0
V_fixture_max = 0
0s        -74.86nV   1.028uV    -3.556mV
132ps     -22.33uV   1.307uV    31.63mV
352ps     -4.769mV   544.9nV    1.621V
572ps     34.38mV    -18.77uV   1.697V
792ps     1.118V     183.5uV    1.702V
968ps     1.474V     -2.569mV   1.704V
1.958ns   1.534V     69.32mV    1.708V
2.464ns   1.537V     978mV      1.709V
8.338ns   1.547V     1.213V     1.713V
143.5ns   1.555V     1.241V     1.716V
[Falling Waveform]
R_fixture = 50
V_fixture = 1.8
V_fixture_min = 1.62
V_fixture_max = 1.89
0s        1.8V       1.62V      1.89V
352ps     1.8V       1.62V      1.802V
528ps     1.8V       1.62V      244.3mV
616ps     1.8V       1.62V      158.7mV
902ps     1.603V     1.62V      132.1mV
1.122ns   353mV      1.62V      129.4mV
1.21ns    237.5mV    1.62V      129mV
2.046ns   182.3mV    1.493V     128.1mV
2.794ns   180.3mV    363.1mV    128mV
5.17ns    179.5mV    293.9mV    127.8mV
[Falling Waveform]
R_fixture = 50
V_fixture = 0
V_fixture_min = 0
V_fixture_max = 0
0s        1.556V     1.244V     1.716V
330ps     1.556V     1.244V     1.678V
396ps     1.556V     1.244V     1.323V
484ps     1.556V     1.244V     136mV
550ps     1.556V     1.244V     26.33mV
858ps     1.421V     1.244V     2.467mV
1.122ns   35.99mV    1.244V     953.2uV
1.958ns   1.837mV    1.163V     327.3uV
2.552ns   1.02mV     68.58mV    207uV
3.872ns   544.9uV    3.311mV    112uV
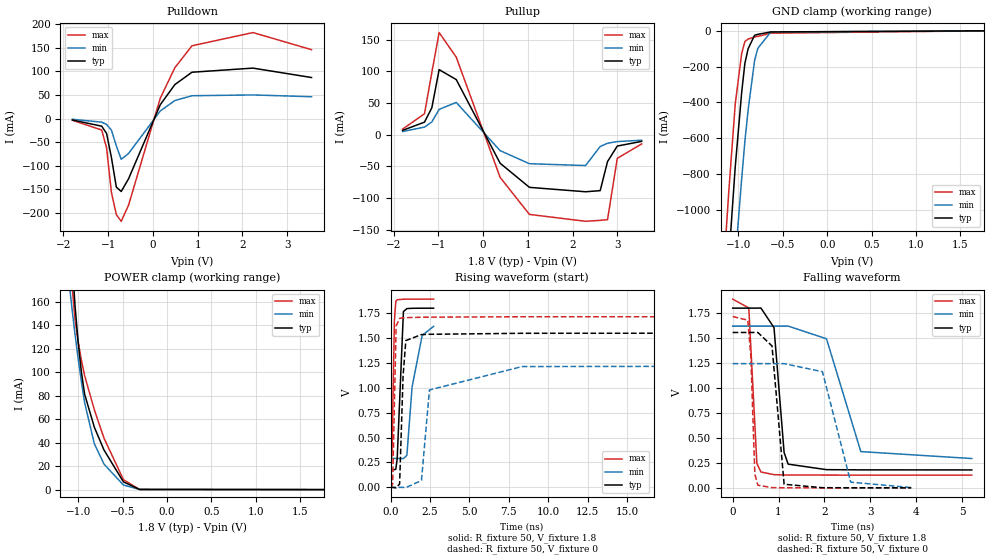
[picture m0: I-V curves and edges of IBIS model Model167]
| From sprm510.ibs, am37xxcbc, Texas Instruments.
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| Model based on original model for BQMMC1833DVHYPBFZLP18_SSCHH
|   Sub model SPEEDCTRL1_PUPD0_1P8
[model]   Model167
|[Input Load]   PI
|[Output Drive] SC1
|Voltage   1.8V
|Mode   I/O
Model_type   I/O
Polarity   Non-Inverting
Enable   Active-Low
Vinl =  0.54
Vinh =  1.26
Cref =  15pF
Rref =  100.0000M
Vref =  0V
Vmeas =  0.9
C_comp   6.565579p   6.22498p   6.65822p
[Model Spec]
Vinl   0.54   0.486   0.567
Vinh   1.26   1.134   1.323
[Temperature Range]   25   125   -40
[Voltage Range]   1.8   1.62   1.89
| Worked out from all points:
|   slope of the pulldown table from 0 to 0.27 V, typ, clamps not added: 5.93 ohm
|   slope of the pullup table from 0 to 0.27 V, typ, clamps not added: 8.03 ohm
|   GND clamp passes 1 mA (typ) near -0.52 V on its own axis
|   POWER clamp passes 1 mA (typ) near -0.38 V on its own axis
|   rising waveform, R_fixture 50, V_fixture 1.8: 20-80 % time 216ps typ, 611ps min, 115ps max; typ from 0.179 V to 1.8 V
|   rising waveform, R_fixture 50, V_fixture 0: 20-80 % time 186ps typ, 762ps min, 112ps max; typ from 0 V to 1.56 V
|   falling waveform, R_fixture 50, V_fixture 1.8: 20-80 % time 156ps typ, 407ps min, 93.8ps max; typ from 1.8 V to 0.18 V
|   falling waveform, R_fixture 50, V_fixture 0: 20-80 % time 123ps typ, 302ps min, 72.7ps max; typ from 1.56 V to 0.001 V
[POWER_clamp]
-1.8V     1.506A     743.4mA    1.547A
-1.109V   249.7mA    180.9mA    217.2mA
-1.073V   201.1mA    156.2mA    177.1mA
-1.036V   156.8mA    132.4mA    144.8mA
-1V       125.1mA    111.2mA    125.9mA
-963.6mV  99.87mA    91.7mA     110mA
-927.3mV  81.15mA    73.95mA    96.95mA
-818.2mV  53.12mA    39.04mA    68mA
-709.1mV  33.7mA     21.7mA     43.76mA
-490.9mV  6.624mA    3.934mA    8.515mA
-309.1mV  135.7uA    124.1uA    133.8uA
1.764V    -66.87nA   -313.7nA   -600.6nA
[Pulldown]
-1.8V     -2.955mA   -1.439mA   -3.582mA
-1.145V   -16.06mA   -7.517mA   -24.16mA
-1.036V   -31.52mA   -12.4mA    -62.37mA
-927.3mV  -82.88mA   -24.53mA   -156.9mA
-818.2mV  -145.2mA   -57.9mA    -203.7mA
-709.1mV  -154.6mA   -86.29mA   -217.8mA
-545.5mV  -127.7mA   -74.07mA   -183.7mA
163.6mV   29.41mA    16.22mA    43.13mA
490.9mV   72.28mA    38.36mA    108.1mA
872.7mV   98.4mA     48.52mA    154.5mA
2.236V    107.1mA    50.23mA    182.5mA
3.545V    87.14mA    46.38mA    146.2mA
[Pullup]
-1.8V     6.901mA    5.057mA    8.816mA
-1.309V   19.93mA    12.08mA    33.18mA
-1.145V   42.64mA    20.25mA    98.48mA
-981.8mV  102.9mA    40.1mA     161.5mA
-600mV    87.24mA    51.07mA    122.7mA
381.8mV   -45.05mA   -25.09mA   -67.44mA
1.036V    -83.14mA   -45.78mA   -125.9mA
2.291V    -90.12mA   -48.67mA   -136.8mA
2.618V    -88.34mA   -18.52mA   -135.3mA
2.782V    -42.42mA   -13.42mA   -134.2mA
3V        -17.89mA   -10.8mA    -37.28mA
3.545V    -10.46mA   -8.646mA   -14.45mA
[GND_clamp]
-1.8V     -7.151A    -7.205A    -6.863A
-1.182V   -1.844A    -2.309A    -1.461A
-1.145V   -1.557A    -2.041A    -1.171A
-1.109V   -1.281A    -1.782A    -899.6mA
-1.036V   -759.7mA   -1.281A    -408.5mA
-963.6mV  -344.6mA   -827mA     -125.9mA
-927.3mV  -181.3mA   -617.3mA   -59.93mA
-890.9mV  -99.98mA   -442.2mA   -45.98mA
-818.2mV  -25.09mA   -166.6mA   -34.17mA
-781.8mV  -19.68mA   -98.02mA   -31.08mA
-636.4mV  -6.256mA   -6.834mA   -13.17mA
1.764V    494.4nA    2.074uA    1.041uA
[Ramp]
dV/dt_f  0.9729177/0.146624n   0.7979581/0.3982232n   1.057801/86.47236p
dV/dt_r  0.9473627/0.1778296n  0.7580433/0.4080918n   1.043717/0.1125773n
R_load = 50
[Rising Waveform]
R_fixture = 50
V_fixture = 1.8
V_fixture_min = 1.62
V_fixture_max = 1.89
0s        179.1mV    290.6mV    126.7mV
88ps      179.1mV    290.6mV    331.1mV
242ps     178.5mV    290.6mV    1.669V
330ps     181.5mV    290.6mV    1.866V
418ps     283.9mV    290.6mV    1.884V
814ps     1.765V     288.9mV    1.889V
1.034ns   1.795V     322.7mV    1.89V
1.364ns   1.798V     1.008V     1.89V
2.002ns   1.799V     1.525V     1.89V
2.728ns   1.799V     1.617V     1.89V
[Rising Waveform]
R_fixture = 50
V_fixture = 0
V_fixture_min = 0
V_fixture_max = 0
0s        -73.01nV   1.037uV    -3.556mV
132ps     -22.33uV   1.315uV    31.63mV
352ps     -4.769mV   553.6nV    1.621V
572ps     34.38mV    -18.76uV   1.697V
792ps     1.118V     183.5uV    1.702V
968ps     1.474V     -2.569mV   1.704V
1.958ns   1.534V     69.37mV    1.708V
2.464ns   1.537V     978mV      1.709V
8.338ns   1.547V     1.213V     1.713V
143.6ns   1.556V     1.241V     1.716V
[Falling Waveform]
R_fixture = 50
V_fixture = 1.8
V_fixture_min = 1.62
V_fixture_max = 1.89
0s        1.8V       1.62V      1.89V
352ps     1.8V       1.62V      1.802V
528ps     1.8V       1.62V      244.5mV
616ps     1.801V     1.62V      158.8mV
902ps     1.604V     1.62V      132.2mV
1.122ns   353.5mV    1.62V      129.5mV
1.21ns    237.7mV    1.62V      129.1mV
2.046ns   182.4mV    1.493V     128.2mV
2.794ns   180.4mV    363.3mV    128.1mV
5.214ns   179.7mV    293.9mV    127.9mV
[Falling Waveform]
R_fixture = 50
V_fixture = 0
V_fixture_min = 0
V_fixture_max = 0
0s        1.556V     1.244V     1.716V
330ps     1.556V     1.244V     1.679V
396ps     1.556V     1.244V     1.323V
484ps     1.556V     1.244V     136.2mV
550ps     1.556V     1.244V     26.44mV
858ps     1.421V     1.244V     2.555mV
1.122ns   36.09mV    1.244V     1.039mV
1.958ns   1.921mV    1.163V     405.3uV
2.574ns   1.085mV    57.21mV    271.8uV
3.894ns   619.2uV    3.3mV      159.6uV
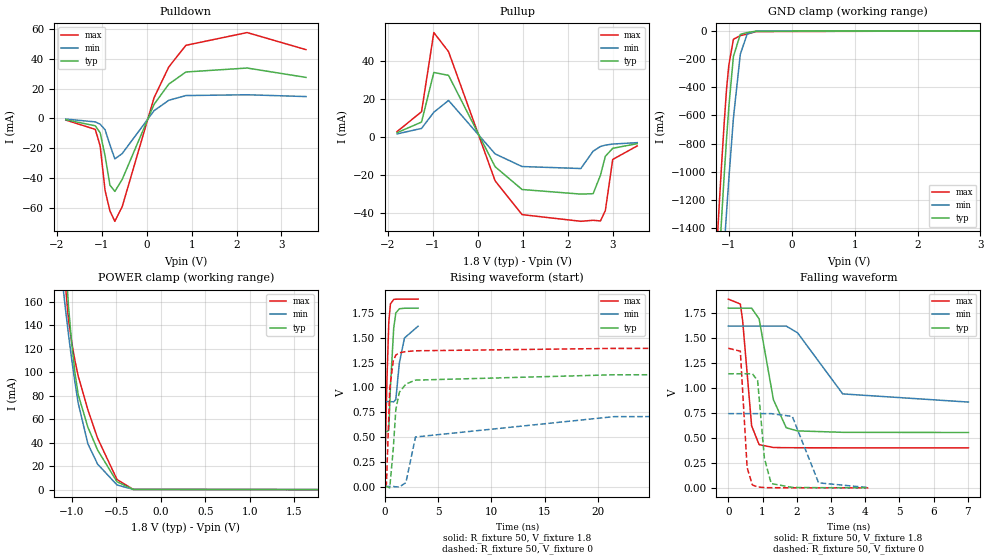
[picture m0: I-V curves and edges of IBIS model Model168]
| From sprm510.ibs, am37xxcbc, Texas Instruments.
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| Model based on original model for BQMMC1833DVHYPBFZLP18_SSCHH
|   Sub model H_SPEEDCTRL0_PU1_1P8
[model]   Model168
|[Input Load]   PU
|[Output Drive] SC0
|Voltage   1.8V
|Mode   I/O
Model_type   I/O
Polarity   Non-Inverting
Enable   Active-Low
Vinl =  0.54
Vinh =  1.26
Cref =  15pF
Rref =  100.0000M
Vref =  0V
Vmeas =  0.9
C_comp   6.565579p   6.22498p   6.65822p
[Model Spec]
Vinl   0.54   0.486   0.567
Vinh   1.26   1.134   1.323
[Temperature Range]   25   125   -40
[Voltage Range]   1.8   1.62   1.89
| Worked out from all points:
|   slope of the pulldown table from 0 to 0.27 V, typ, clamps not added: 18.6 ohm
|   slope of the pullup table from 0 to 0.27 V, typ, clamps not added: 23.2 ohm
|   GND clamp passes 1 mA (typ) near -0.52 V on its own axis
|   POWER clamp passes 1 mA (typ) near -0.38 V on its own axis
|   rising waveform, R_fixture 50, V_fixture 1.8: 20-80 % time 354ps typ, 627ps min, 233ps max; typ from 0.554 V to 1.8 V
|   rising waveform, R_fixture 50, V_fixture 0: 20-80 % time 540ps typ, 1.65ns min, 339ps max; typ from 0 V to 1.14 V
|   falling waveform, R_fixture 50, V_fixture 1.8: 20-80 % time 395ps typ, 841ps min, 218ps max; typ from 1.8 V to 0.555 V
|   falling waveform, R_fixture 50, V_fixture 0: 20-80 % time 170ps typ, 404ps min, 115ps max; typ from 1.14 V to 0.001 V
[POWER_clamp]
-1.8V     1.506A     743.4mA    1.547A
-1.109V   249.7mA    180.9mA    217.2mA
-1.073V   201.1mA    156.2mA    177.1mA
-1.036V   156.8mA    132.4mA    144.8mA
-1V       125.1mA    111.2mA    125.9mA
-963.6mV  99.87mA    91.71mA    110mA
-927.3mV  81.15mA    73.96mA    96.95mA
-818.2mV  53.13mA    39.04mA    68mA
-709.1mV  33.7mA     21.7mA     43.77mA
-490.9mV  6.629mA    3.937mA    8.521mA
-309.1mV  139.6uA    126.3uA    139.1uA
1.764V    -25.18uA   -15.38uA   -34.57uA
[Pulldown]
-1.8V     -930.6uA   -453.8uA   -1.127mA
-1.145V   -4.983mA   -2.358mA   -7.387mA
-1.036V   -9.64mA    -3.874mA   -18.47mA
-927.3mV  -25.02mA   -7.595mA   -48.3mA
-818.2mV  -44.84mA   -17.79mA   -62.17mA
-709.1mV  -49.04mA   -27.19mA   -69.1mA
-545.5mV  -40.99mA   -23.62mA   -59.29mA
163.6mV   9.392mA    5.153mA    13.85mA
490.9mV   22.98mA    12.15mA    34.51mA
872.7mV   31.15mA    15.33mA    49.06mA
2.236V    33.81mA    15.86mA    57.62mA
3.545V    27.52mA    14.65mA    46.15mA
[Pullup]
-1.8V     2.285mA    1.654mA    2.864mA
-1.255V   7.884mA    4.537mA    13.31mA
-981.8mV  33.89mA    13.01mA    54.84mA
-654.5mV  32.4mA     19.23mA    44.84mA
381.8mV   -15.55mA   -8.814mA   -22.93mA
981.8mV   -27.52mA   -15.47mA   -40.71mA
2.291V    -29.94mA   -16.51mA   -44.21mA
2.564V    -29.72mA   -7.406mA   -43.68mA
2.727V    -20.03mA   -4.942mA   -44.02mA
2.836V    -10.1mA    -4.243mA   -38.57mA
3V        -5.903mA   -3.661mA   -11.75mA
3.545V    -3.469mA   -2.933mA   -4.654mA
[GND_clamp]
-1.8V     -7.151A    -7.205A    -6.863A
-1.182V   -1.844A    -2.309A    -1.461A
-1.145V   -1.557A    -2.041A    -1.171A
-1.109V   -1.281A    -1.782A    -899.6mA
-1.073V   -1.016A    -1.529A    -645.4mA
-1.036V   -759.7mA   -1.281A    -408.5mA
-1V       -537.5mA   -1.048A    -242.1mA
-927.3mV  -181.3mA   -617.3mA   -59.94mA
-818.2mV  -25.1mA    -166.6mA   -34.2mA
-709.1mV  -12.05mA   -22.52mA   -22.82mA
-563.6mV  -2.326mA   -2.107mA   -5.538mA
3.6V      0A         0A         0A
[Ramp]
dV/dt_f  0.7479651/0.3939105n   0.458522/0.8460537n  0.8937916/0.2144808n
dV/dt_r  0.6941165/0.5336756n  0.4509517/1.602916n   0.8485379/0.3387523n
R_load = 50
[Rising Waveform]
R_fixture = 50
V_fixture = 1.8
V_fixture_min = 1.62
V_fixture_max = 1.89
0s        553.8mV    856.1mV    399.5mV
44ps      553.8mV    856.1mV    432.9mV
176ps     553.8mV    856.1mV    1.066V
352ps     567.8mV    856.1mV    1.66V
506ps     1.007V     856.1mV    1.842V
814ps     1.599V     854.1mV    1.887V
1.012ns   1.75V      877.2mV    1.889V
1.342ns   1.793V     1.245V     1.89V
1.826ns   1.798V     1.498V     1.89V
3.102ns   1.799V     1.617V     1.89V
[Rising Waveform]
R_fixture = 50
V_fixture = 0
V_fixture_min = 0
V_fixture_max = 0
0s        307uV      252.9uV    -2.691mV
132ps     292.1uV    253.2uV    26.76mV
440ps     -13.56mV   253.8uV    986mV
770ps     378.5mV    461.8uV    1.266V
1.012ns   774.7mV    -3.043mV   1.326V
1.342ns   950mV      -4.594mV   1.349V
1.958ns   1.034V     38.83mV    1.361V
2.86ns    1.073V     499.7mV    1.369V
21.52ns   1.127V     704.8mV    1.393V
217ns     1.143V     740.7mV    1.398V
[Falling Waveform]
R_fixture = 50
V_fixture = 1.8
V_fixture_min = 1.62
V_fixture_max = 1.89
0s        1.8V       1.62V      1.89V
352ps     1.8V       1.62V      1.841V
418ps     1.8V       1.62V      1.68V
682ps     1.8V       1.62V      621.8mV
902ps     1.691V     1.62V      433mV
1.32ns    882.2mV    1.62V      404.7mV
1.694ns   602mV      1.62V      402.6mV
2.024ns   570.8mV    1.553V     402.1mV
3.344ns   556.6mV    941.2mV    401.3mV
7.018ns   554.7mV    859.4mV    401mV
[Falling Waveform]
R_fixture = 50
V_fixture = 0
V_fixture_min = 0
V_fixture_max = 0
0s        1.143V     743.9mV    1.398V
352ps     1.143V     743.9mV    1.369V
550ps     1.143V     743.9mV    203.6mV
704ps     1.143V     743.9mV    29.77mV
858ps     1.073V     743.9mV    9.218mV
1.056ns   295.4mV    743.9mV    3.485mV
1.254ns   43.83mV    743.8mV    2.139mV
1.87ns    4.942mV    716.1mV    1.17mV
2.64ns    2.392mV    50.53mV    795.5uV
4.092ns   1.369mV    3.564mV    573.4uV
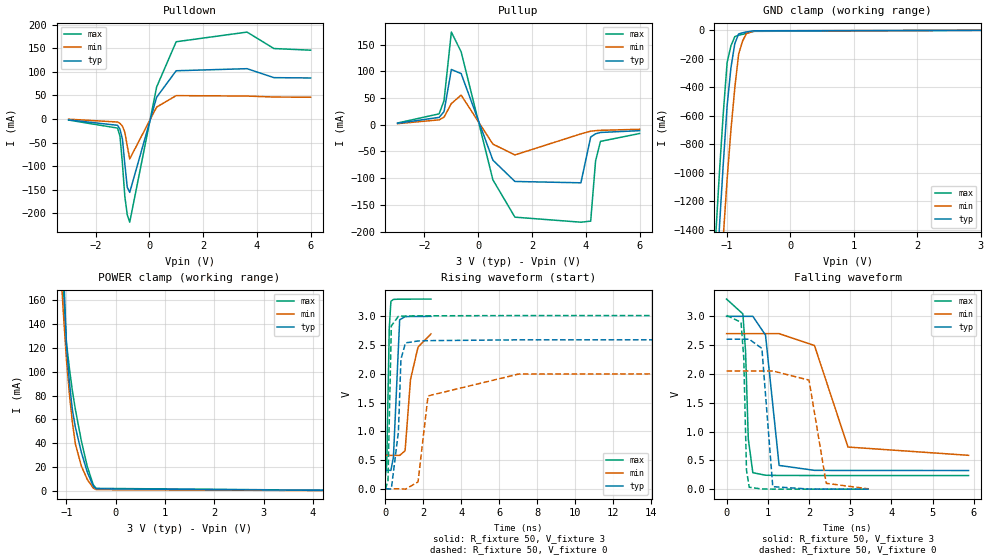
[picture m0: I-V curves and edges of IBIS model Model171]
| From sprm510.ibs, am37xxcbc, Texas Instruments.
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| Model based on original model for BQMMC1833DVHYPBFZLP18_SSCHH
|   Sub model CHH_SPEEDCTRL1_PD1_3
[model]   Model171
|[Input Load]   PD
|[Output Drive] SC1
|Voltage   3V
|Mode   I/O
Model_type   I/O
Polarity   Non-Inverting
Enable   Active-Low
Vinl =  0.9
Vinh =  2.1
Cref =  15pF
Rref =  100.0000M
Vref =  0V
Vmeas =  1.5
C_comp   5.193555p   4.924275p   5.205586p
[Model Spec]
Vinl   0.9   0.81   0.99
Vinh   2.1   1.89   2.31
[Temperature Range]   25   125   -40
[Voltage Range]   3   2.7   3.3
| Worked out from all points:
|   slope of the pulldown table from 0 to 0.45 V, typ, clamps not added: 6.62 ohm
|   slope of the pullup table from 0 to 0.45 V, typ, clamps not added: 7.89 ohm
|   GND clamp passes 1 mA (typ) near -0.51 V on its own axis
|   POWER clamp passes 1 mA (typ) near -0.36 V on its own axis
|   rising waveform, R_fixture 50, V_fixture 3: 20-80 % time 167ps typ, 443ps min, 89.1ps max; typ from 0.323 V to 3 V
|   rising waveform, R_fixture 50, V_fixture 0: 20-80 % time 166ps typ, 643ps min, 92.3ps max; typ from 0 V to 2.6 V
|   falling waveform, R_fixture 50, V_fixture 3: 20-80 % time 175ps typ, 441ps min, 91.9ps max; typ from 3 V to 0.324 V
|   falling waveform, R_fixture 50, V_fixture 0: 20-80 % time 109ps typ, 201ps min, 65.1ps max; typ from 2.6 V to 0.001 V
[POWER_clamp]
-3V       3.885A     1.82A      4.094A
-1.121V   269.1mA    190mA      236.5mA
-1.061V   190mA      149.2mA    170.5mA
-1V       123.2mA    111mA      124.9mA
-939.4mV  91.3mA     81.53mA    102.9mA
-878.8mV  68.12mA    57.7mA     84.07mA
-818.2mV  53.62mA    39.48mA    68.5mA
-697mV    32.46mA    21mA       42.06mA
-575.8mV  15.74mA    9.608mA    20.45mA
-454.5mV  4.037mA    2.416mA    5.101mA
-393.9mV  1.738mA    1.086mA    2.148mA
6V        0A         0A         0A
[Pulldown]
-3V       -1.92mA    -565.6uA   -2.388mA
-1.182V   -13.53mA   -6.536mA   -19.39mA
-1.091V   -21.71mA   -9.487mA   -36.41mA
-1V       -42.45mA   -15.19mA   -93.87mA
-909.1mV  -96.11mA   -28.12mA   -164.8mA
-818.2mV  -145.2mA   -57.9mA    -203.7mA
-727.3mV  -155.7mA   -84.71mA   -219mA
272.7mV   45.94mA    25.09mA    67.67mA
1V        102.2mA    49.45mA    163.7mA
3.636V    106.6mA    48.54mA    184.2mA
4.636V    87.57mA    46.45mA    149.3mA
6V        86.91mA    46.02mA    145.8mA
[Pullup]
-3V       2.72mA     2.097mA    3.297mA
-1.455V   13.81mA    9.186mA    20.44mA
-1.273V   24.46mA    14.19mA    44.98mA
-1V       103.4mA    39.67mA    173.4mA
-636.4mV  95.77mA    55.52mA    136.5mA
545.5mV   -66.26mA   -36.24mA   -103.1mA
1.364V    -106.1mA   -56.45mA   -172.9mA
3.818V    -108.6mA   -17.05mA   -182.3mA
4.182V    -22.95mA   -12.03mA   -180.3mA
4.364V    -16.96mA   -11.06mA   -67.52mA
4.545V    -14.39mA   -10.41mA   -31.08mA
6V        -11.06mA   -8.487mA   -16.38mA
[GND_clamp]
-3V       -17.89A    -17.26A    -17.77A
-1.182V   -1.843A    -2.308A    -1.459A
-1.121V   -1.377A    -1.871A    -995.4mA
-1.061V   -939mA     -1.45A     -584.5mA
-1V       -529.9mA   -1.045A    -225.8mA
-939.4mV  -261.2mA   -697mA     -108mA
-878.8mV  -92.98mA   -404.2mA   -44.13mA
-818.2mV  -25.12mA   -166.6mA   -34.22mA
-757.6mV  -17.49mA   -76.74mA   -28.22mA
-697mV    -11.17mA   -23.3mA    -21.17mA
-575.8mV  -3.102mA   -3.059mA   -6.967mA
3V        36.99uA    104.7uA    51.93uA
[Ramp]
dV/dt_f   1.60625/0.1614287n   1.270767/0.4340802n   1.838265/90.68557p
dV/dt_r   1.574455/0.160192n   1.242759/0.3914889n   1.82338/91.62628p
R_load = 50
[Rising Waveform]
R_fixture = 50
V_fixture = 3
V_fixture_min = 2.7
V_fixture_max = 3.3
0s        323.3mV    582.3mV    238.1mV
66ps      323.3mV    582.3mV    422.1mV
198ps     323.4mV    582.3mV    2.779V
286ps     321.6mV    582.3mV    3.26V
418ps     549.2mV    582.3mV    3.294V
748ps     2.939V     580.7mV    3.299V
1.034ns   2.994V     663.6mV    3.299V
1.32ns    2.997V     1.903V     3.299V
1.716ns   2.998V     2.465V     3.3V
2.398ns   2.999V     2.694V     3.3V
[Rising Waveform]
R_fixture = 50
V_fixture = 0
V_fixture_min = 0
V_fixture_max = 0
0s        -47.09nV   1.185uV    -3.564mV
132ps     -22.39uV   1.407uV    145.5mV
308ps     -2.259mV   938nV      2.834V
682ps     993.9mV    189.3uV    3V
814ps     2.254V     44.31uV    3.003V
1.056ns   2.538V     -5.391mV   3.005V
1.716ns   2.571V     120.2mV    3.008V
2.244ns   2.577V     1.616V     3.009V
7.018ns   2.591V     1.996V     3.013V
117ns     2.602V     2.047V     3.016V
[Falling Waveform]
R_fixture = 50
V_fixture = 3
V_fixture_min = 2.7
V_fixture_max = 3.3
0s        3V         2.7V       3.3V
396ps     3V         2.7V       3.043V
462ps     3V         2.7V       2.386V
528ps     3V         2.7V       873.1mV
638ps     3V         2.7V       286.1mV
946ps     2.675V     2.7V       242.1mV
1.276ns   412.3mV    2.7V       238.2mV
2.134ns   326.8mV    2.494V     237.1mV
2.948ns   324.8mV    731.3mV    236.9mV
5.874ns   323.9mV    587.8mV    236.8mV
[Falling Waveform]
R_fixture = 50
V_fixture = 0
V_fixture_min = 0
V_fixture_max = 0
0s        2.603V     2.052V     3.016V
352ps     2.603V     2.052V     2.897V
418ps     2.603V     2.052V     2.278V
484ps     2.603V     2.052V     333.7mV
550ps     2.603V     2.052V     33.38mV
858ps     2.443V     2.052V     3.129mV
1.122ns   43.25mV    2.052V     1.215mV
2.002ns   2.25mV     1.893V     349uV
2.42ns    1.46mV     101.3mV    246.7uV
3.454ns   821.1uV    5.616mV    138.9uV
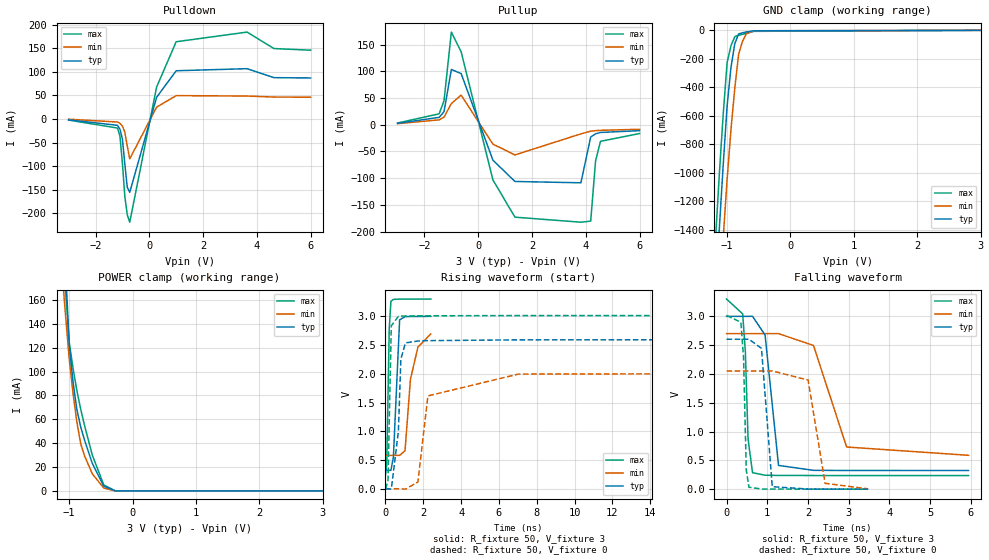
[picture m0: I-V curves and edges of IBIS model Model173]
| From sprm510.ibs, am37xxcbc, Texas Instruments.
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| Model based on original model for BQMMC1833DVHYPBFZLP18_SSCHH
|   Sub model H_SPEEDCTRL1_PUPD0_3
[model]   Model173
|[Input Load]   PI
|[Output Drive] SC1
|Voltage   3V
|Mode   I/O
Model_type   I/O
Polarity   Non-Inverting
Enable   Active-Low
Vinl =  0.9
Vinh =  2.1
Cref =  15pF
Rref =  100.0000M
Vref =  0V
Vmeas =  1.5
C_comp   5.193555p   4.924275p   5.205586p
[Model Spec]
Vinl   0.9   0.81   0.99
Vinh   2.1   1.89   2.31
[Temperature Range]   25   125   -40
[Voltage Range]   3   2.7   3.3
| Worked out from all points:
|   slope of the pulldown table from 0 to 0.45 V, typ, clamps not added: 6.62 ohm
|   slope of the pullup table from 0 to 0.45 V, typ, clamps not added: 7.89 ohm
|   GND clamp passes 1 mA (typ) near -0.51 V on its own axis
|   POWER clamp passes 1 mA (typ) near -0.36 V on its own axis
|   rising waveform, R_fixture 50, V_fixture 3: 20-80 % time 167ps typ, 443ps min, 89.1ps max; typ from 0.323 V to 3 V
|   rising waveform, R_fixture 50, V_fixture 0: 20-80 % time 166ps typ, 647ps min, 92.3ps max; typ from 0 V to 2.6 V
|   falling waveform, R_fixture 50, V_fixture 3: 20-80 % time 175ps typ, 441ps min, 91.9ps max; typ from 3 V to 0.324 V
|   falling waveform, R_fixture 50, V_fixture 0: 20-80 % time 109ps typ, 201ps min, 65.1ps max; typ from 2.6 V to 0.001 V
[POWER_clamp]
-3V       3.885A     1.82A      4.094A
-1.121V   269.1mA    190mA      236.4mA
-1.061V   190mA      149.1mA    170.5mA
-1V       123.1mA    110.9mA    124.8mA
-939.4mV  91.26mA    81.51mA    102.8mA
-878.8mV  68.08mA    57.68mA    84.02mA
-818.2mV  53.58mA    39.46mA    68.44mA
-757.6mV  42.55mA    29.33mA    54.75mA
-636.4mV  23.22mA    14.41mA    30.19mA
-454.5mV  3.998mA    2.395mA    5.042mA
-272.7mV  32.75uA    41.91uA    26.15uA
3V        -85.83nA   -8.891uA   -798.5nA
[Pulldown]
-3V       -1.92mA    -565.6uA   -2.388mA
-1.182V   -13.53mA   -6.536mA   -19.39mA
-1.091V   -21.71mA   -9.487mA   -36.41mA
-1V       -42.45mA   -15.19mA   -93.87mA
-909.1mV  -96.11mA   -28.12mA   -164.8mA
-818.2mV  -145.2mA   -57.9mA    -203.7mA
-727.3mV  -155.7mA   -84.71mA   -219mA
272.7mV   45.94mA    25.09mA    67.67mA
1V        102.2mA    49.45mA    163.7mA
3.636V    106.6mA    48.54mA    184.2mA
4.636V    87.57mA    46.45mA    149.3mA
6V        86.91mA    46.02mA    145.8mA
[Pullup]
-3V       2.72mA     2.097mA    3.297mA
-1.455V   13.81mA    9.186mA    20.44mA
-1.273V   24.46mA    14.19mA    44.98mA
-1V       103.4mA    39.67mA    173.4mA
-636.4mV  95.77mA    55.52mA    136.5mA
545.5mV   -66.26mA   -36.24mA   -103.1mA
1.364V    -106.1mA   -56.45mA   -172.9mA
3.818V    -108.6mA   -17.05mA   -182.3mA
4.182V    -22.95mA   -12.03mA   -180.3mA
4.364V    -16.96mA   -11.06mA   -67.52mA
4.545V    -14.39mA   -10.41mA   -31.08mA
6V        -11.06mA   -8.487mA   -16.38mA
[GND_clamp]
-3V       -17.89A    -17.26A    -17.77A
-1.182V   -1.843A    -2.308A    -1.459A
-1.121V   -1.377A    -1.871A    -995.4mA
-1.061V   -939mA     -1.45A     -584.5mA
-1V       -529.9mA   -1.045A    -225.8mA
-939.4mV  -261.2mA   -697mA     -108mA
-878.8mV  -92.98mA   -404.2mA   -44.13mA
-818.2mV  -25.12mA   -166.6mA   -34.22mA
-757.6mV  -17.48mA   -76.74mA   -28.22mA
-697mV    -11.16mA   -23.3mA    -21.17mA
-575.8mV  -3.096mA   -3.057mA   -6.959mA
3V        955.9nA    83.7uA     1.79uA
[Ramp]
dV/dt_f   1.606358/0.1615141n   1.270831/0.4344238n   1.838384/90.74425p
dV/dt_r   1.574601/0.1602187n   1.242904/0.3916034n   1.823524/91.63427p
R_load = 50
[Rising Waveform]
R_fixture = 50
V_fixture = 3
V_fixture_min = 2.7
V_fixture_max = 3.3
0s        323.4mV    582.4mV    238.1mV
66ps      323.4mV    582.4mV    422.1mV
198ps     323.4mV    582.4mV    2.779V
286ps     321.6mV    582.4mV    3.26V
418ps     549.3mV    582.4mV    3.294V
748ps     2.939V     580.8mV    3.299V
1.034ns   2.994V     663.7mV    3.299V
1.32ns    2.997V     1.904V     3.3V
1.716ns   2.998V     2.465V     3.3V
2.398ns   2.999V     2.694V     3.3V
[Rising Waveform]
R_fixture = 50
V_fixture = 0
V_fixture_min = 0
V_fixture_max = 0
0s        -45.17nV   1.194uV    -3.564mV
132ps     -22.38uV   1.417uV    145.5mV
308ps     -2.259mV   947.5nV    2.834V
682ps     993.9mV    189.3uV    3V
814ps     2.254V     44.33uV    3.003V
1.056ns   2.538V     -5.391mV   3.005V
1.716ns   2.571V     120.2mV    3.008V
2.244ns   2.577V     1.616V     3.009V
7.04ns    2.591V     1.996V     3.013V
117.2ns   2.603V     2.047V     3.016V
[Falling Waveform]
R_fixture = 50
V_fixture = 3
V_fixture_min = 2.7
V_fixture_max = 3.3
0s        3V         2.7V       3.3V
396ps     3V         2.7V       3.043V
462ps     3V         2.7V       2.387V
528ps     3V         2.7V       874.5mV
638ps     3.001V     2.7V       286.4mV
946ps     2.675V     2.7V       242.3mV
1.276ns   412.6mV    2.7V       238.4mV
2.134ns   327mV      2.495V     237.3mV
2.948ns   325.1mV    731.9mV    237.1mV
5.94ns    324mV      587.9mV    236.9mV
[Falling Waveform]
R_fixture = 50
V_fixture = 0
V_fixture_min = 0
V_fixture_max = 0
0s        2.603V     2.052V     3.016V
352ps     2.603V     2.052V     2.898V
418ps     2.603V     2.052V     2.278V
484ps     2.603V     2.052V     334.5mV
550ps     2.603V     2.052V     33.57mV
858ps     2.444V     2.052V     3.277mV
1.122ns   43.43mV    2.052V     1.36mV
2.002ns   2.386mV    1.894V     476.6uV
2.42ns    1.593mV    101.5mV    359.4uV
3.476ns   941uV      5.529mV    217.6uV
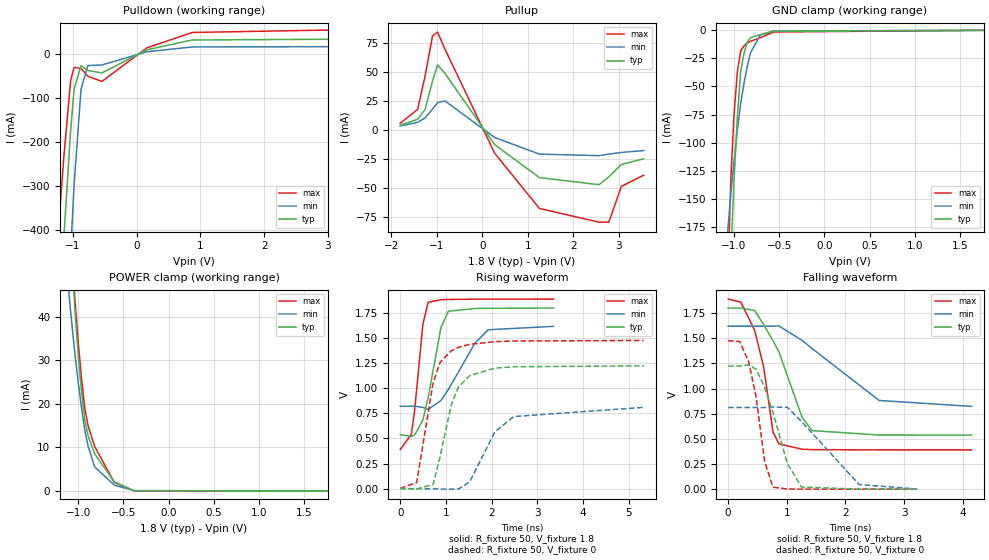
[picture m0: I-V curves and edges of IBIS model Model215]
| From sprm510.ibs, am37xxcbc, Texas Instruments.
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| Model based on original model for BQ18OMAPSMART2HYFBPB_SSBHV
|   Sub model HYFBPB_V_1_PUPD0_1P8
[model]   Model215
|[Input Load]   PI
|[Output Drive] LB1
|Voltage   1.8V
|Mode   I/O
Model_type   I/O
Polarity   Non-Inverting
Enable   Active-Low
Vinl =  0.63
Vinh =  1.17
Cref =  15pF
Rref =  100.0000M
Vref =  0V
Vmeas =  0.9
C_comp   1.528652p   1.368776p   1.69933p
[Model Spec]
Vinl   0.63   0.567   0.6615
Vinh   1.17   1.053   1.2285
[Temperature Range]   25   125   -40
[Voltage Range]   1.8   1.62   1.89
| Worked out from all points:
|   slope of the pulldown table from 0 to 0.27 V, typ, clamps not added: 17.8 ohm
|   slope of the pullup table from 0 to 0.27 V, typ, clamps not added: 21.5 ohm
|   GND clamp passes 1 mA (typ) near -0.58 V on its own axis
|   POWER clamp passes 1 mA (typ) near -0.54 V on its own axis
|   rising waveform, R_fixture 50, V_fixture 1.8: 20-80 % time 306ps typ, 605ps min, 190ps max; typ from 0.538 V to 1.8 V
|   rising waveform, R_fixture 50, V_fixture 0: 20-80 % time 391ps typ, 586ps min, 349ps max; typ from 0 V to 1.22 V
|   falling waveform, R_fixture 50, V_fixture 1.8: 20-80 % time 522ps typ, 1.06ns min, 282ps max; typ from 1.8 V to 0.538 V
|   falling waveform, R_fixture 50, V_fixture 0: 20-80 % time 373ps typ, 698ps min, 226ps max; typ from 1.22 V to 0 V
[POWER_clamp]
-1.8V     449.2mA    229.3mA    499.9mA
-1.109V   70.03mA    46.65mA    71.76mA
-1.073V   55.15mA    38.86mA    56.96mA
-1.036V   41.47mA    31.41mA    43.93mA
-1V       31.2mA     24.93mA    34.21mA
-963.6mV  22.8mA     19.1mA     25.91mA
-927.3mV  16.27mA    13.92mA    19.01mA
-890.9mV  12.72mA    10.32mA    14.97mA
-818.2mV  8.506mA    5.529mA    10.22mA
-600mV    2.086mA    1.321mA    1.925mA
-381.8mV  46uA       75.05uA    15.45uA
1.764V    -1.701nA   -102nA     -1.875nA
[Pulldown]
-1.8V     -1.866A    -2.926A    -1.473A
-1.255V   -690.3mA   -1.165A    -458.8mA
-1.2V     -556.9mA   -981.3mA   -347.5mA
-1.145V   -424mA     -799.3mA   -238.7mA
-1.036V   -174.1mA   -452.5mA   -60.31mA
-981.8mV  -80.13mA   -298.3mA   -30.04mA
-872.7mV  -26.27mA   -79.78mA   -32.44mA
-763.6mV  -37.26mA   -25.87mA   -50.47mA
-545.5mV  -42.85mA   -24.82mA   -62.02mA
163.6mV   9.905mA    5.464mA    14.49mA
872.7mV   32.06mA    16.22mA    49.12mA
3.545V    34.18mA    16.99mA    56.07mA
[Pullup]
-1.8V     4.02mA     3.353mA    5.71mA
-1.418V   9.153mA    6.524mA    17.71mA
-1.255V   17.65mA    10.28mA    46.45mA
-1.091V   42.12mA    17.99mA    80.97mA
-981.8mV  56.04mA    23.5mA     84.34mA
-818.2mV  48.72mA    25.01mA    69.63mA
272.7mV   -12.68mA   -6.535mA   -20.08mA
1.255V    -41.13mA   -20.87mA   -67.69mA
2.564V    -47.26mA   -22.22mA   -79.57mA
2.782V    -40.42mA   -20.82mA   -79.47mA
3.055V    -29.85mA   -19.43mA   -48.72mA
3.545V    -24.9mA    -17.8mA    -39.06mA
[GND_clamp]
-1.8V     -3.26A     -1.496A    -3.636A
-1.073V   -295.4mA   -181.3mA   -234.2mA
-1.036V   -202.1mA   -145.8mA   -132.5mA
-1V       -132.6mA   -116.1mA   -74.83mA
-963.6mV  -77.56mA   -89.36mA   -36.83mA
-927.3mV  -36.94mA   -65.52mA   -18.53mA
-890.9mV  -20.86mA   -47.5mA    -14.02mA
-854.5mV  -10.73mA   -32.34mA   -11.09mA
-818.2mV  -6.545mA   -20.02mA   -9.764mA
-709.1mV  -3.764mA   -4.146mA   -6.62mA
-563.6mV  -769uA     -544.8uA   -1.476mA
1.764V    -87.87pA   812.3nA    3.194nA
[Ramp]
dV/dt_f  0.7588073/0.5229073n  0.4813244/1.068517n   0.9003369/0.2820954n
dV/dt_r  0.7393362/0.3912228n  0.4905436/0.588626n   0.8915806/0.3502013n
R_load = 50
[Rising Waveform]
R_fixture = 50
V_fixture = 1.8
V_fixture_min = 1.62
V_fixture_max = 1.89
0s        537.8mV    821mV      389.4mV
243ps     520.1mV    821.2mV    540.6mV
315ps     534.3mV    821.7mV    778.2mV
495ps     682.8mV    809.6mV    1.638V
612ps     908.9mV    788.9mV    1.858V
891ps     1.605V     878.9mV    1.884V
1.053ns   1.769V     988.1mV    1.886V
1.638ns   1.796V     1.452V     1.889V
1.926ns   1.798V     1.584V     1.889V
3.357ns   1.8V       1.618V     1.89V
[Rising Waveform]
R_fixture = 50
V_fixture = 0
V_fixture_min = 0
V_fixture_max = 0
0s        17.35uV    -10.13uV   1.881mV
360ps     -4.989mV   -121.7uV   60.31mV
720ps     42.17mV    -1.813mV   1.056V
873ps     317.6mV    -4.323mV   1.26V
1.116ns   835.5mV    -5.891mV   1.374V
1.278ns   1.016V     -3.25mV    1.409V
1.521ns   1.127V     67.23mV    1.439V
2.07ns    1.201V     564.7mV    1.465V
2.484ns   1.215V     718.3mV    1.472V
5.328ns   1.224V     809.9mV    1.477V
[Falling Waveform]
R_fixture = 50
V_fixture = 1.8
V_fixture_min = 1.62
V_fixture_max = 1.89
0s        1.8V       1.62V      1.89V
216ps     1.8V       1.62V      1.86V
450ps     1.777V     1.62V      1.581V
603ps     1.638V     1.62V      1.222V
765ps     1.474V     1.621V     567.9mV
864ps     1.368V     1.623V     450.4mV
1.26ns    712.8mV    1.479V     397.3mV
1.431ns   582mV      1.398V     393.3mV
2.574ns   538.2mV    882mV      390.2mV
4.149ns   537.8mV    822.8mV    390.2mV
[Falling Waveform]
R_fixture = 50
V_fixture = 0
V_fixture_min = 0
V_fixture_max = 0
0s        1.224V     811.6mV    1.476V
198ps     1.224V     811.4mV    1.468V
351ps     1.236V     811.6mV    1.265V
477ps     1.192V     811.6mV    915.2mV
621ps     1.013V     811.1mV    277.4mV
765ps     762.6mV    817.2mV    19.59mV
1.008ns   256.9mV    813.9mV    1.748mV
1.251ns   21.17mV    672.3mV    225uV
2.232ns   125.3uV    46.21mV    1.5uV
3.222ns   37.71uV    1.661mV    324.8nV
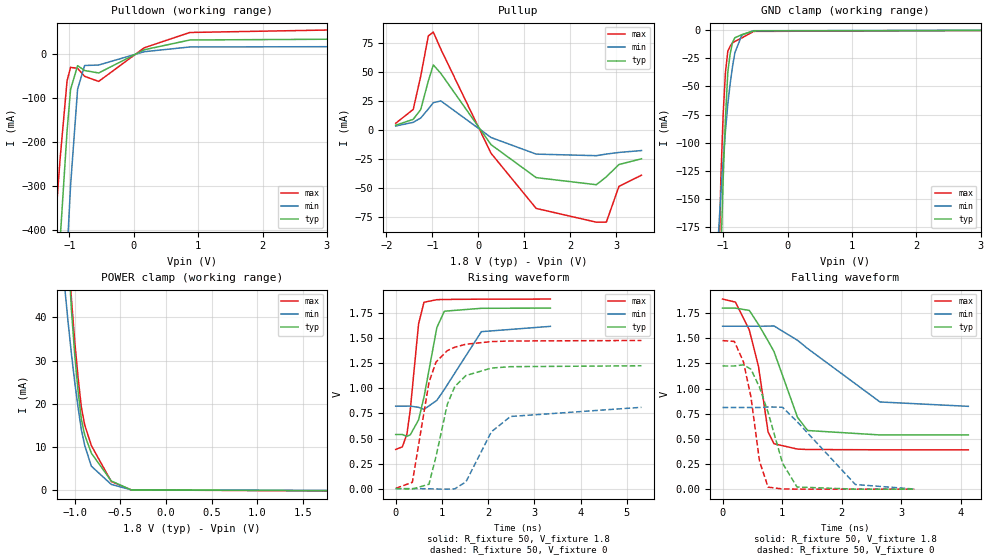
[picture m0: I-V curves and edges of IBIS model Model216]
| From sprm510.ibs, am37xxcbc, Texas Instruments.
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| Model based on original model for BQ18OMAPSMART2HYFBPB_SSBHV
|   Sub model T2HYFBPB_V_1_PU1_1P8
[model]   Model216
|[Input Load]   PU
|[Output Drive] LB1
|Voltage   1.8V
|Mode   I/O
Model_type   I/O
Polarity   Non-Inverting
Enable   Active-Low
Vinl =  0.63
Vinh =  1.17
Cref =  15pF
Rref =  100.0000M
Vref =  0V
Vmeas =  0.9
C_comp   1.528652p   1.368776p   1.69933p
[Model Spec]
Vinl   0.63   0.567   0.6615
Vinh   1.17   1.053   1.2285
[Temperature Range]   25   125   -40
[Voltage Range]   1.8   1.62   1.89
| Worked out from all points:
|   slope of the pulldown table from 0 to 0.27 V, typ, clamps not added: 17.8 ohm
|   slope of the pullup table from 0 to 0.27 V, typ, clamps not added: 21.5 ohm
|   GND clamp passes 1 mA (typ) near -0.57 V on its own axis
|   POWER clamp passes 1 mA (typ) near -0.53 V on its own axis
|   rising waveform, R_fixture 50, V_fixture 1.8: 20-80 % time 307ps typ, 606ps min, 190ps max; typ from 0.54 V to 1.8 V
|   rising waveform, R_fixture 50, V_fixture 0: 20-80 % time 390ps typ, 585ps min, 349ps max; typ from 0.001 V to 1.23 V
|   falling waveform, R_fixture 50, V_fixture 1.8: 20-80 % time 522ps typ, 1.06ns min, 282ps max; typ from 1.8 V to 0.54 V
|   falling waveform, R_fixture 50, V_fixture 0: 20-80 % time 374ps typ, 698ps min, 226ps max; typ from 1.23 V to 0.001 V
[POWER_clamp]
-1.8V     449.2mA    229.3mA    499.9mA
-1.109V   70.1mA     46.68mA    71.89mA
-1.073V   55.22mA    38.88mA    57.09mA
-1.036V   41.55mA    31.43mA    44.07mA
-1V       31.28mA    24.96mA    34.35mA
-963.6mV  22.88mA    19.13mA    26.04mA
-927.3mV  16.35mA    13.96mA    19.14mA
-890.9mV  12.8mA     10.36mA    15.1mA
-818.2mV  8.584mA    5.567mA    10.34mA
-600mV    2.149mA    1.354mA    2.023mA
-381.8mV  86.82uA    96.98uA    78.48uA
1.764V    -96.73uA   -46.5uA    -163.5uA
[Pulldown]
-1.8V     -1.866A    -2.926A    -1.473A
-1.255V   -690.3mA   -1.165A    -458.8mA
-1.2V     -556.9mA   -981.3mA   -347.5mA
-1.145V   -424mA     -799.3mA   -238.7mA
-1.036V   -174.1mA   -452.5mA   -60.3mA
-981.8mV  -80.13mA   -298.3mA   -30.04mA
-872.7mV  -26.27mA   -79.78mA   -32.44mA
-763.6mV  -37.27mA   -25.87mA   -50.47mA
-545.5mV  -42.85mA   -24.82mA   -62.02mA
163.6mV   9.905mA    5.464mA    14.49mA
872.7mV   32.06mA    16.22mA    49.12mA
3.545V    34.18mA    16.99mA    56.07mA
[Pullup]
-1.8V     4.02mA     3.353mA    5.71mA
-1.418V   9.153mA    6.524mA    17.71mA
-1.255V   17.65mA    10.28mA    46.46mA
-1.091V   42.13mA    17.99mA    80.98mA
-981.8mV  56.04mA    23.5mA     84.34mA
-818.2mV  48.72mA    25.01mA    69.63mA
272.7mV   -12.68mA   -6.535mA   -20.08mA
1.255V    -41.13mA   -20.87mA   -67.69mA
2.564V    -47.26mA   -22.22mA   -79.57mA
2.782V    -40.42mA   -20.82mA   -79.47mA
3.055V    -29.85mA   -19.43mA   -48.72mA
3.545V    -24.9mA    -17.8mA    -39.06mA
[GND_clamp]
-1.8V     -3.26A     -1.496A    -3.636A
-1.073V   -295.4mA   -181.3mA   -234.2mA
-1.036V   -202.2mA   -145.8mA   -132.6mA
-1V       -132.7mA   -116.1mA   -74.88mA
-963.6mV  -77.6mA    -89.37mA   -36.9mA
-927.3mV  -36.98mA   -65.53mA   -18.61mA
-890.9mV  -20.91mA   -47.52mA   -14.11mA
-854.5mV  -10.79mA   -32.36mA   -11.2mA
-818.2mV  -6.611mA   -20.04mA   -9.885mA
-709.1mV  -3.838mA   -4.175mA   -6.748mA
-527.3mV  -502uA     -336.2uA   -960.8uA
3.6V      0A         0A         0A
[Ramp]
dV/dt_f  0.7577292/0.5230197n  0.4805246/1.068797n   0.8991189/0.2821838n
dV/dt_r  0.7391289/0.3905048n  0.4906207/0.5877701n   0.891058/0.3494142n
R_load = 50
[Rising Waveform]
R_fixture = 50
V_fixture = 1.8
V_fixture_min = 1.62
V_fixture_max = 1.89
0s        539.6mV    822.3mV    391.4mV
144ps     539.7mV    822.5mV    416.7mV
243ps     521.8mV    822.5mV    543.9mV
315ps     536.1mV    823mV      782.8mV
495ps     685.4mV    810.9mV    1.642V
612ps     912.1mV    790.2mV    1.858V
891ps     1.606V     880.3mV    1.884V
1.053ns   1.769V     989.6mV    1.886V
1.854ns   1.798V     1.565V     1.889V
3.348ns   1.8V       1.618V     1.89V
[Rising Waveform]
R_fixture = 50
V_fixture = 0
V_fixture_min = 0
V_fixture_max = 0
0s        1.115mV    783.9uV    3.235mV
360ps     -3.847mV   672.6uV    63.2mV
720ps     44.1mV     -1.021mV   1.06V
873ps     321mV      -3.499mV   1.262V
1.116ns   838.7mV    -4.985mV   1.376V
1.278ns   1.018V     -2.259mV   1.41V
1.521ns   1.128V     68.46mV    1.44V
2.07ns    1.202V     566.5mV    1.466V
2.484ns   1.216V     719.6mV    1.472V
5.319ns   1.225V     810.9mV    1.477V
[Falling Waveform]
R_fixture = 50
V_fixture = 1.8
V_fixture_min = 1.62
V_fixture_max = 1.89
0s        1.8V       1.62V      1.89V
216ps     1.8V       1.62V      1.86V
450ps     1.777V     1.62V      1.581V
603ps     1.638V     1.62V      1.223V
765ps     1.474V     1.621V     570mV
864ps     1.369V     1.623V     452.6mV
1.26ns    714.3mV    1.48V      399.3mV
1.431ns   583.7mV    1.398V     395.3mV
2.646ns   539.9mV    867.6mV    392.2mV
4.131ns   539.6mV    824.1mV    392.2mV
[Falling Waveform]
R_fixture = 50
V_fixture = 0
V_fixture_min = 0
V_fixture_max = 0
0s        1.225V     812.6mV    1.477V
198ps     1.225V     812.4mV    1.469V
351ps     1.237V     812.6mV    1.266V
477ps     1.193V     812.6mV    916.8mV
621ps     1.014V     812.1mV    279.4mV
765ps     764mV      818.2mV    21.16mV
1.008ns   258.5mV    814.8mV    3.152mV
1.251ns   22.5mV     673.4mV    1.608mV
2.232ns   1.222mV    47.1mV     1.374mV
3.222ns   1.134mV    2.462mV    1.373mV
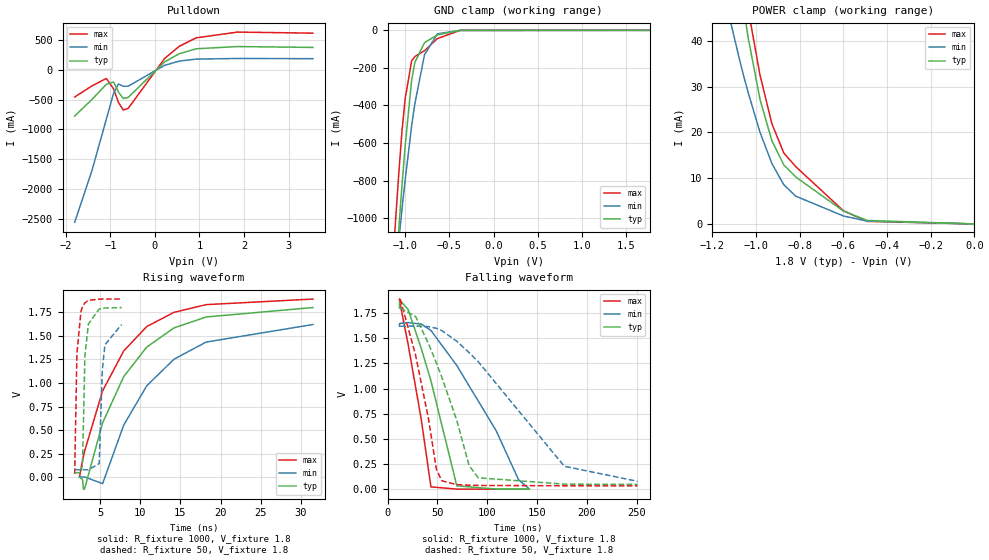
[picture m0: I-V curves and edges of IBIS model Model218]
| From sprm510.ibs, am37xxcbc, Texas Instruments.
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| Model based on original model for BQOMAPI2CHYFBPBRES_SSBHH
|   Sub model BQOMAPI2CHYRES_SLV_POFF_00_1P8
[model]   Model218
|[Input Load]   PI
|[Output Drive] LB00
|Voltage   1.8V
|Mode   I/O_OPEN_DRAIN
Model_type   I/O_open_drain
Polarity   Non-Inverting
Enable   Active-Low
Vinl =  0.567
Vinh =  1.323
Cref =  400.0000PF
Rref =  1000.0000
Vref =  1.8V
Vmeas =  0.9
C_comp   3.85558p   3.723112p   3.857218p
[Model Spec]
Vinl   0.567   0.567   0.567
Vinh   1.323   1.323   1.323
[Temperature Range]   25   125   -40
[Voltage Range]   1.8   1.62   1.89
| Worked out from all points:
|   slope of the pulldown table from 0 to 0.27 V, typ, clamps not added: 1.71 ohm
|   GND clamp passes 1 mA (typ) near -0.44 V on its own axis
|   POWER clamp passes 1 mA (typ) near -0.51 V on its own axis
|   rising waveform, R_fixture 1000, V_fixture 1.8: 20-80 % time 7.1ns typ, 8.09ns min, 6.29ns max; typ from 0.002 V to 1.8 V
|   rising waveform, R_fixture 50, V_fixture 1.8: 20-80 % time 373ps typ, 410ps min, 341ps max; typ from 0.049 V to 1.8 V
|   falling waveform, R_fixture 1000, V_fixture 1.8: 20-80 % time 29.3ns typ, 56.6ns min, 19.1ns max; typ from 1.8 V to 0.002 V
|   falling waveform, R_fixture 50, V_fixture 1.8: 20-80 % time 36.2ns typ, 77.2ns min, 22ns max; typ from 1.8 V to 0.049 V
[POWER_clamp]
-1.8V     401.1mA    209.4mA    454.2mA
-1.145V   79.39mA    49.82mA    86.39mA
-1.073V   52.49mA    35.39mA    58.76mA
-1.055V   46.58mA    32.04mA    52.82mA
-1.036V   40.67mA    28.68mA    46.87mA
-981.8mV  27.2mA     20.01mA    32.52mA
-927.3mV  18.17mA    13.19mA    21.87mA
-872.7mV  12.87mA    8.554mA    15.48mA
-818.2mV  10.26mA    6.071mA    12.52mA
-600mV    2.834mA    1.747mA    2.888mA
-490.9mV  760.8uA    616.2uA    563.4uA
0V        4.894nA    26.6nA     13.41nA
[Pulldown]
-1.8V     -777mA     -2.558A    -458.4mA
-1.418V   -503.6mA   -1.705A    -274.2mA
-1.091V   -246mA     -833.2mA   -147.3mA
-927.3mV  -205.8mA   -396mA     -321.1mA
-818.2mV  -374mA     -240.2mA   -549.2mA
-709.1mV  -482.4mA   -277.9mA   -676.8mA
-600mV    -465mA     -277.2mA   -649mA
218.2mV   131.5mA    73.81mA    188.3mA
545.5mV   267.7mA    144.1mA    391.9mA
927.3mV   351.1mA    177.8mA    534.6mA
1.855V    388.5mA    188.1mA    631mA
3.545V    373.8mA    185.1mA    613.1mA
[GND_clamp]
-1.8V     -6.905A    -5.48A     -6.849A
-1.145V   -1.563A    -1.472A    -1.273A
-1.109V   -1.305A    -1.292A    -1.009A
-1.073V   -1.058A    -1.118A    -761.8mA
-1.036V   -819.4mA   -948.6mA   -530.3mA
-1V       -610.5mA   -793.2mA   -361.6mA
-927.3mV  -263.9mA   -507.2mA   -161.9mA
-890.9mV  -170.2mA   -389mA     -139.4mA
-781.8mV  -65.52mA   -129.8mA   -108.5mA
-636.4mV  -24.47mA   -18.9mA    -43.94mA
-381.8mV  -239.7uA   -254uA     -441.8uA
1.764V    2.8nA      2.224uA    11.77nA
[Ramp]
dV/dt_f  1.1008198/31.082246n 0.97960895/59.948839n  1.1665917/20.288782n
dV/dt_r 0.13496919/0.10722539n 0.11658429/0.21263229n 0.14009829/64.862911p
R_load = 528.0
[Rising Waveform]
R_fixture = 1000
V_fixture = 1.8
V_fixture_min = 1.62
V_fixture_max = 1.89
2.43ns    2.428mV    3.93mV     1.741mV
2.805ns   -22.08mV   3.929mV    178.2mV
2.93ns    -125.6mV   3.929mV    227.2mV
3.056ns   -124.2mV   3.929mV    274.6mV
5.309ns   577.4mV    -66.91mV   916.5mV
7.94ns    1.068V     553.7mV    1.34V
10.8ns    1.38V      969.5mV    1.598V
14.2ns    1.584V     1.252V     1.749V
18.21ns   1.7V       1.434V     1.831V
31.51ns   1.8V       1.62V      1.89V
[Rising Waveform]
R_fixture = 50
V_fixture = 1.8
V_fixture_min = 1.62
V_fixture_max = 1.89
1.83ns    48.93mV    79.48mV    35.04mV
2.107ns   48.93mV    79.48mV    1.311V
2.614ns   48.01mV    79.48mV    1.76V
2.807ns   139mV      79.48mV    1.809V
3.103ns   1.288V     79.48mV    1.85V
3.538ns   1.626V     79.48mV    1.876V
4.885ns   1.784V     146mV      1.889V
5.267ns   1.792V     1.129V     1.89V
5.596ns   1.795V     1.404V     1.89V
7.677ns   1.8V       1.62V      1.89V
[Falling Waveform]
R_fixture = 1000
V_fixture = 1.8
V_fixture_min = 1.62
V_fixture_max = 1.89
11.84ns   1.8V       1.62V      1.89V
11.94ns   1.868V     1.647V     1.866V
13.09ns   1.868V     1.649V     1.812V
20.42ns   1.789V     1.656V     1.446V
33.72ns   1.4V       1.642V     694.5mV
43.43ns   1.078V     1.578V     24.62mV
69.42ns   34.55mV    1.23V      2.223mV
108.9ns   3.212mV    583.6mV    1.824mV
131.4ns   2.796mV    96.19mV    1.777mV
142.2ns   2.428mV    3.93mV     1.741mV
[Falling Waveform]
R_fixture = 50
V_fixture = 1.8
V_fixture_min = 1.62
V_fixture_max = 1.89
12.59ns   1.8V       1.62V      1.89V
28.01ns   1.717V     1.622V     1.333V
41ns      1.447V     1.616V     700.4mV
48.86ns   1.255V     1.6V       201.5mV
54.3ns    1.115V     1.577V     84.94mV
69.39ns   686.4mV    1.471V     47.08mV
81.76ns   236.5mV    1.358V     41.09mV
90.91ns   114.4mV    1.268V     38.99mV
177.4ns   51.59mV    229.4mV    35.2mV
251.1ns   48.93mV    79.48mV    35.04mV
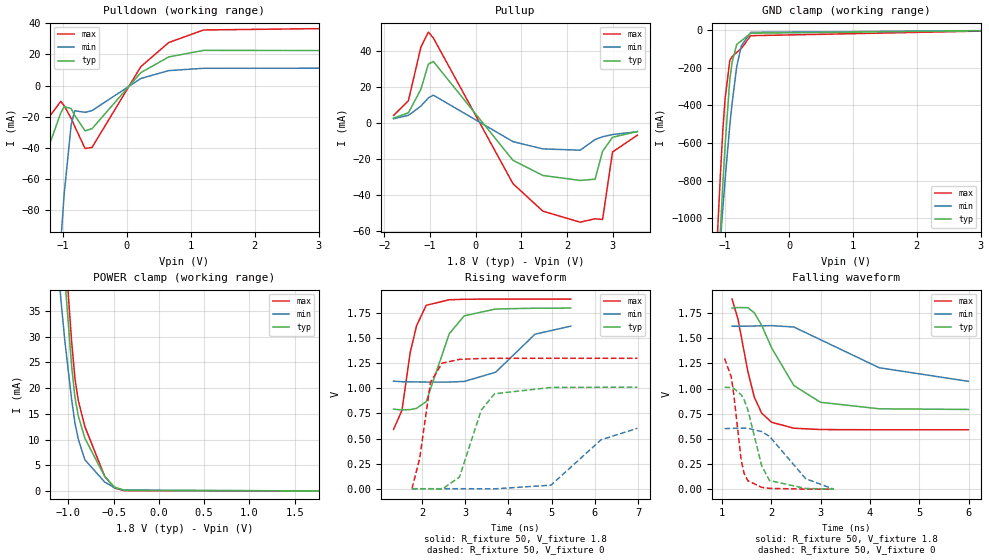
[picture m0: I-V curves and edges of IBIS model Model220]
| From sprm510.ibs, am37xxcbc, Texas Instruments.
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| Model based on original model for BQOMAPI2CHYFBPBRES_SSBHH
|   Sub model BQOMAPI2CHYRES_NORM_00_1P8
[model]   Model220
|[Input Load]   PU
|[Output Drive] LB00
|Voltage   1.8V
|Mode   I/O
Model_type   I/O
Polarity   Non-Inverting
Enable   Active-Low
Vinl =  0.567
Vinh =  1.323
Cref =  15.0000PF
Rref =  150.0000
Vref =  0V
Vmeas =  0.9
C_comp   3.85558p   3.723112p   3.857218p
[Model Spec]
Vinl   0.567   0.567   0.567
Vinh   1.323   1.323   1.323
[Temperature Range]   25   125   -40
[Voltage Range]   1.8   1.62   1.89
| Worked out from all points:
|   slope of the pulldown table from 0 to 0.27 V, typ, clamps not added: 27.3 ohm
|   slope of the pullup table from 0 to 0.27 V, typ, clamps not added: 33.5 ohm
|   GND clamp passes 1 mA (typ) near -0.44 V on its own axis
|   POWER clamp passes 1 mA (typ) near -0.51 V on its own axis
|   rising waveform, R_fixture 50, V_fixture 1.8: 20-80 % time 444ps typ, 739ps min, 311ps max; typ from 0.792 V to 1.8 V
|   rising waveform, R_fixture 50, V_fixture 0: 20-80 % time 438ps typ, 819ps min, 258ps max; typ from 0 V to 1.01 V
|   falling waveform, R_fixture 50, V_fixture 1.8: 20-80 % time 694ps typ, 1.48ns min, 354ps max; typ from 1.8 V to 0.792 V
|   falling waveform, R_fixture 50, V_fixture 0: 20-80 % time 313ps typ, 597ps min, 187ps max; typ from 1.01 V to 0 V
[POWER_clamp]
-1.8V     401.1mA    209.4mA    454.2mA
-1.145V   79.39mA    49.82mA    86.39mA
-1.073V   52.49mA    35.39mA    58.76mA
-1.036V   40.67mA    28.68mA    46.87mA
-963.6mV  24.19mA    17.73mA    28.97mA
-927.3mV  18.17mA    13.19mA    21.87mA
-890.9mV  14.63mA    10.1mA     17.61mA
-818.2mV  10.26mA    6.071mA    12.52mA
-600mV    2.834mA    1.747mA    2.888mA
-490.9mV  760.8uA    616.2uA    563.4uA
-381.8mV  112.8uA    147.2uA    57.34uA
1.764V    -11.66nA   -1.927uA   -18.08nA
[Pulldown]
-1.8V     -103.1mA   -485.1mA   -53.66mA
-1.636V   -86.71mA   -425.1mA   -43.29mA
-1.036V   -17.55mA   -100.6mA   -10.12mA
-981.8mV  -13.55mA   -69.37mA   -13.05mA
-872.7mV  -14.77mA   -25.04mA   -21.09mA
-818.2mV  -19.14mA   -16.16mA   -26.14mA
-654.5mV  -29.1mA    -17.19mA   -40.44mA
-545.5mV  -27.65mA   -16.06mA   -39.66mA
218.2mV   8.291mA    4.55mA     12.15mA
654.5mV   18.38mA    9.592mA    27.6mA
1.2V      22.57mA    11.08mA    35.66mA
3.545V    22.43mA    11.1mA     36.8mA
[Pullup]
-1.8V     2.712mA    2.321mA    4.148mA
-1.473V   5.636mA    4.228mA    12.4mA
-1.2V     18.73mA    9.362mA    42.15mA
-1.036V   32.69mA    13.94mA    50.53mA
-927.3mV  34.21mA    15.45mA    47.3mA
818.2mV   -20.78mA   -10.39mA   -33.77mA
1.473V    -29.21mA   -14.43mA   -49.06mA
2.291V    -31.98mA   -15.15mA   -55.2mA
2.618V    -31.28mA   -9.229mA   -53.28mA
2.782V    -15.77mA   -7.688mA   -53.7mA
3V        -7.977mA   -6.448mA   -16.18mA
3.545V    -4.777mA   -4.853mA   -6.788mA
[GND_clamp]
-1.8V     -6.905A    -5.48A     -6.849A
-1.145V   -1.563A    -1.472A    -1.273A
-1.109V   -1.305A    -1.292A    -1.009A
-1.073V   -1.058A    -1.118A    -761.8mA
-1.036V   -819.4mA   -948.6mA   -530.3mA
-1V       -610.5mA   -793.2mA   -361.6mA
-927.3mV  -263.9mA   -507.2mA   -161.9mA
-890.9mV  -170.2mA   -389mA     -139.4mA
-818.2mV  -74.8mA    -191.7mA   -117.8mA
-745.5mV  -55.76mA   -81.74mA   -95.49mA
-600mV    -15.41mA   -10.81mA   -28.59mA
3.6V      0A         0A         0A
[Ramp]
dV/dt_f 0.73375184/0.65073623n  0.4493485/1.5494404n 0.88399083/0.32850704n
dV/dt_r 0.71039797/0.44061952n 0.45590441/0.84254529n 0.86759393/0.25553748n
R_load = 70.0000
[Rising Waveform]
R_fixture = 50
V_fixture = 1.8
V_fixture_min = 1.62
V_fixture_max = 1.89
1.335ns   792.4mV    1.072V     590.3mV
1.531ns   785mV      1.066V     781.1mV
1.721ns   788.5mV    1.065V     1.356V
1.87ns    801.2mV    1.064V     1.625V
2.093ns   868.2mV    1.063V     1.828V
2.627ns   1.544V     1.063V     1.883V
2.974ns   1.723V     1.069V     1.888V
3.703ns   1.791V     1.161V     1.89V
4.615ns   1.799V     1.54V      1.89V
5.443ns   1.8V       1.62V      1.89V
[Rising Waveform]
R_fixture = 50
V_fixture = 0
V_fixture_min = 0
V_fixture_max = 0
1.762ns   198.6nV    3.394uV    310.6nV
1.939ns   -1.038mV   18.89uV    295.4mV
2.193ns   -2.442mV   12.09uV    1.062V
2.461ns   -4.653mV   -7.906uV   1.251V
2.864ns   116.2mV    -132.9uV   1.289V
3.369ns   783.4mV    -715.1uV   1.298V
3.676ns   946mV      -1.351mV   1.299V
4.985ns   1.009V     34.96mV    1.3V
6.146ns   1.011V     487.7mV    1.3V
6.988ns   1.012V     601.9mV    1.3V
[Falling Waveform]
R_fixture = 50
V_fixture = 1.8
V_fixture_min = 1.62
V_fixture_max = 1.89
1.204ns   1.8V       1.62V      1.89V
1.323ns   1.806V     1.62V      1.693V
1.525ns   1.804V     1.621V     1.169V
1.654ns   1.754V     1.622V     916.7mV
1.805ns   1.629V     1.624V     755.8mV
2.007ns   1.404V     1.626V     664.9mV
2.458ns   1.03V      1.612V     606mV
2.997ns   863.8mV    1.486V     592.7mV
4.19ns    799mV      1.207V     590.4mV
5.997ns   792.4mV    1.072V     590.3mV
[Falling Waveform]
R_fixture = 50
V_fixture = 0
V_fixture_min = 0
V_fixture_max = 0
1.052ns   1.012V     601.9mV    1.3V
1.187ns   1.01V      604.3mV    1.118V
1.238ns   1.002V     605.1mV    946mV
1.39ns    937.9mV    606.6mV    286.3mV
1.448ns   888.9mV    606.6mV    157.2mV
1.525ns   789.3mV    605.2mV    83.53mV
1.804ns   233.8mV    572.3mV    17.91mV
1.963ns   85.48mV    525.3mV    8.127mV
2.698ns   7.1mV      103.8mV    175.9uV
3.267ns   198.6nV    3.394uV    310.6nV
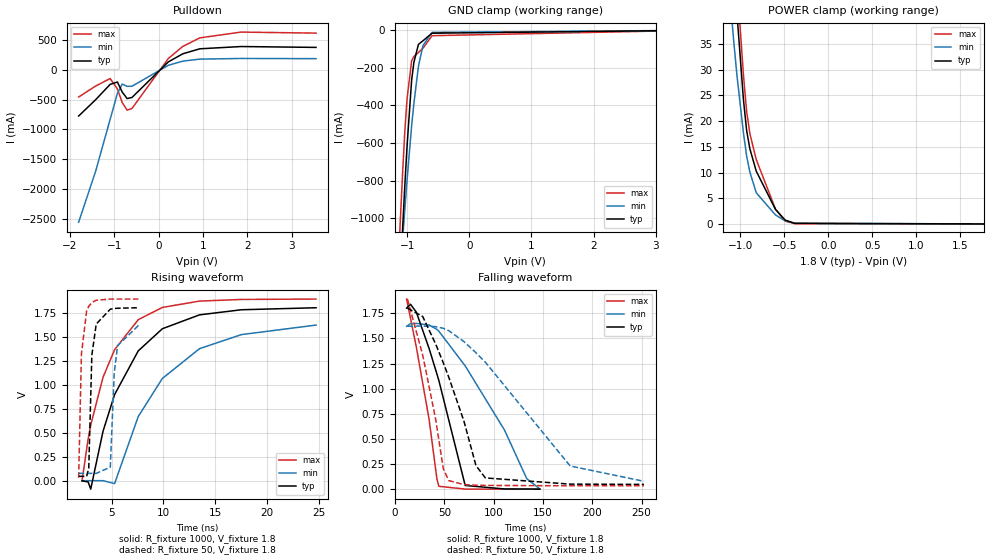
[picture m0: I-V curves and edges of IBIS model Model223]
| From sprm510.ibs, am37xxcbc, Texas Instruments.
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| Model based on original model for BQOMAPI2CHYFBPBRES_SSBHH
|   Sub model BQOMAPI2CHYRES_SLV_PON_00_1P8
[model]   Model223
|[Input Load]   PU
|[Output Drive] LB00
|Voltage   1.8V
|Mode   I/O_OPEN_DRAIN
Model_type   I/O_open_drain
Polarity   Non-Inverting
Enable   Active-Low
Vinl =  0.567
Vinh =  1.323
Cref =  400.0000PF
Rref =  1000.0000
Vref =  1.8V
Vmeas =  0.9
C_comp   3.85558p   3.723112p   3.857218p
[Model Spec]
Vinl   0.567   0.567   0.567
Vinh   1.323   1.323   1.323
[Temperature Range]   25   125   -40
[Voltage Range]   1.8   1.62   1.89
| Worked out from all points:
|   slope of the pulldown table from 0 to 0.27 V, typ, clamps not added: 1.71 ohm
|   GND clamp passes 1 mA (typ) near -0.44 V on its own axis
|   POWER clamp passes 1 mA (typ) near -0.51 V on its own axis
|   rising waveform, R_fixture 1000, V_fixture 1.8: 20-80 % time 4.46ns typ, 5.95ns min, 3.48ns max; typ from 0.004 V to 1.8 V
|   rising waveform, R_fixture 50, V_fixture 1.8: 20-80 % time 357ps typ, 399ps min, 324ps max; typ from 0.05 V to 1.8 V
|   falling waveform, R_fixture 1000, V_fixture 1.8: 20-80 % time 29.9ns typ, 57.7ns min, 19.5ns max; typ from 1.8 V to 0.004 V
|   falling waveform, R_fixture 50, V_fixture 1.8: 20-80 % time 36.4ns typ, 77.5ns min, 22.1ns max; typ from 1.8 V to 0.05 V
[POWER_clamp]
-1.8V     401.1mA    209.4mA    454.2mA
-1.145V   79.39mA    49.82mA    86.39mA
-1.073V   52.49mA    35.39mA    58.76mA
-1.036V   40.67mA    28.68mA    46.87mA
-963.6mV  24.19mA    17.73mA    28.97mA
-927.3mV  18.17mA    13.19mA    21.87mA
-890.9mV  14.63mA    10.1mA     17.61mA
-818.2mV  10.26mA    6.071mA    12.52mA
-600mV    2.834mA    1.747mA    2.888mA
-490.9mV  760.8uA    616.2uA    563.4uA
-381.8mV  112.8uA    147.2uA    57.34uA
1.764V    -11.66nA   -1.927uA   -18.08nA
[Pulldown]
-1.8V     -777.1mA   -2.558A    -458.5mA
-1.418V   -503.8mA   -1.705A    -274.4mA
-1.091V   -246.4mA   -833.4mA   -147.9mA
-927.3mV  -206.9mA   -396.4mA   -323.2mA
-818.2mV  -375.8mA   -240.8mA   -551.8mA
-709.1mV  -483.8mA   -278.7mA   -678.8mA
-600mV    -466.3mA   -277.9mA   -650.8mA
218.2mV   130.6mA    73.31mA    187mA
545.5mV   267mA      143.7mA    390.8mA
927.3mV   350.5mA    177.6mA    533.7mA
1.855V    388.5mA    188.2mA    630.9mA
3.545V    374.1mA    185.3mA    613.5mA
[GND_clamp]
-1.8V     -6.905A    -5.48A     -6.849A
-1.145V   -1.563A    -1.472A    -1.273A
-1.109V   -1.305A    -1.292A    -1.009A
-1.073V   -1.058A    -1.118A    -761.8mA
-1.036V   -819.4mA   -948.6mA   -530.3mA
-1V       -610.5mA   -793.2mA   -361.6mA
-927.3mV  -263.9mA   -507.2mA   -161.9mA
-890.9mV  -170.2mA   -389mA     -139.4mA
-818.2mV  -74.8mA    -191.7mA   -117.8mA
-745.5mV  -55.76mA   -81.74mA   -95.49mA
-600mV    -15.41mA   -10.81mA   -28.59mA
3.6V      0A         0A         0A
[Ramp]
dV/dt_f  1.0946124/31.311582n 0.97686247/60.525043n  1.1564606/20.344833n
dV/dt_r 0.35693675/3.5440231n 0.23888268/4.700921n  0.44353891/2.8148321n
R_load = 528.0
[Rising Waveform]
R_fixture = 1000
V_fixture = 1.8
V_fixture_min = 1.62
V_fixture_max = 1.89
2.154ns   3.896mV    5.366mV    3.171mV
2.747ns   -7.876mV   5.366mV    441.6mV
2.991ns   -82.73mV   5.365mV    582.2mV
4.178ns   517.8mV    5.483mV    1.078V
5.294ns   898.8mV    -25.16mV   1.365V
7.574ns   1.352V     670.9mV    1.676V
9.899ns   1.582V     1.066V     1.803V
13.48ns   1.726V     1.375V     1.869V
17.51ns   1.779V     1.521V     1.886V
24.72ns   1.8V       1.62V      1.89V
[Rising Waveform]
R_fixture = 50
V_fixture = 1.8
V_fixture_min = 1.62
V_fixture_max = 1.89
1.828ns   50.41mV    80.94mV    36.49mV
2.097ns   50.41mV    80.94mV    1.321V
2.594ns   49mV       80.94mV    1.764V
2.803ns   134.8mV    80.94mV    1.815V
3.101ns   1.308V     80.94mV    1.854V
3.525ns   1.631V     80.94mV    1.878V
4.88ns    1.785V     145.8mV    1.89V
5.257ns   1.792V     1.123V     1.89V
5.581ns   1.795V     1.406V     1.89V
7.633ns   1.8V       1.62V      1.89V
[Falling Waveform]
R_fixture = 1000
V_fixture = 1.8
V_fixture_min = 1.62
V_fixture_max = 1.89
11.72ns   1.8V       1.62V      1.89V
15.78ns   1.838V     1.646V     1.697V
21.67ns   1.759V     1.648V     1.411V
34.55ns   1.4V       1.633V     697.8mV
42.47ns   1.147V     1.589V     105.9mV
44.45ns   1.082V     1.571V     31.86mV
71.15ns   40.05mV    1.227V     3.967mV
111.1ns   5.072mV    588.3mV    3.309mV
133.6ns   4.45mV     106.6mV    3.232mV
146.8ns   3.896mV    5.366mV    3.171mV
[Falling Waveform]
R_fixture = 50
V_fixture = 1.8
V_fixture_min = 1.62
V_fixture_max = 1.89
12.63ns   1.8V       1.62V      1.89V
28.06ns   1.717V     1.622V     1.335V
41.19ns   1.445V     1.616V     698.7mV
48.93ns   1.258V     1.6V       208.4mV
54.41ns   1.117V     1.577V     88.21mV
69.87ns   679mV      1.468V     48.72mV
82.08ns   237mV      1.357V     42.71mV
91.6ns    114.7mV    1.263V     40.49mV
177.6ns   53.16mV    233.2mV    36.66mV
252.4ns   50.41mV    80.94mV    36.49mV
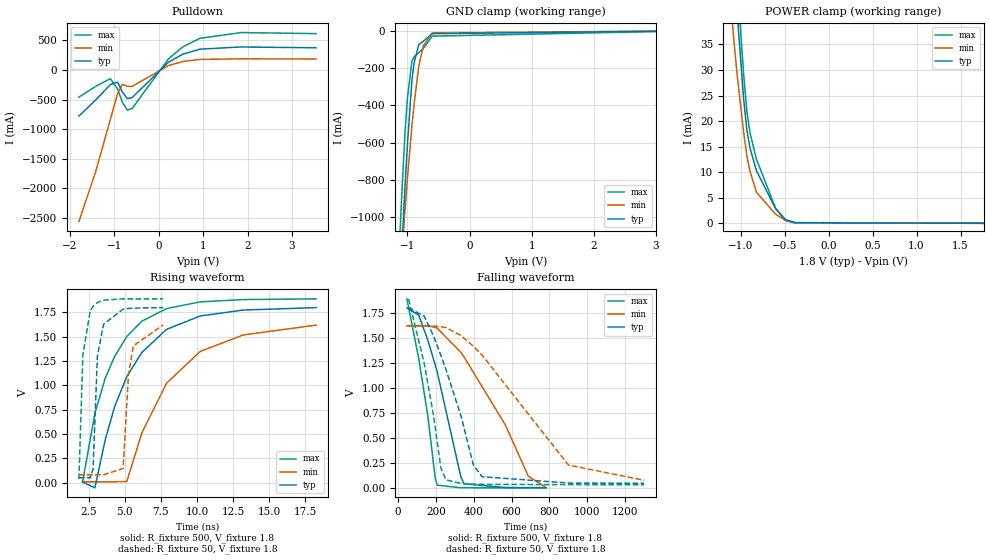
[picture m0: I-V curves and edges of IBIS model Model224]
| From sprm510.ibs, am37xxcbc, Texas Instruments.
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| Model based on original model for BQOMAPI2CHYFBPBRES_SSBHH
|   Sub model BQOMAPI2CHYRES_STD_PON_00_1P8
[model]   Model224
|[Input Load]   PU
|[Output Drive] LB00
|Voltage   1.8V
|Mode   I/O_OPEN_DRAIN
Model_type   I/O_open_drain
Polarity   Non-Inverting
Enable   Active-Low
Vinl =  0.567
Vinh =  1.323
Cref =  400.0000PF
Rref =  500.0000
Vref =  1.8V
Vmeas =  0.9
C_comp   3.85558p   3.723112p   3.857218p
[Model Spec]
Vinl   0.567   0.567   0.567
Vinh   1.323   1.323   1.323
[Temperature Range]   25   125   -40
[Voltage Range]   1.8   1.62   1.89
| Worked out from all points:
|   slope of the pulldown table from 0 to 0.27 V, typ, clamps not added: 1.71 ohm
|   GND clamp passes 1 mA (typ) near -0.44 V on its own axis
|   POWER clamp passes 1 mA (typ) near -0.51 V on its own axis
|   rising waveform, R_fixture 500, V_fixture 1.8: 20-80 % time 3.25ns typ, 3.91ns min, 2.72ns max; typ from 0.005 V to 1.8 V
|   rising waveform, R_fixture 50, V_fixture 1.8: 20-80 % time 365ps typ, 405ps min, 333ps max; typ from 0.049 V to 1.8 V
|   falling waveform, R_fixture 500, V_fixture 1.8: 20-80 % time 144ns typ, 288ns min, 91.2ns max; typ from 1.8 V to 0.005 V
|   falling waveform, R_fixture 50, V_fixture 1.8: 20-80 % time 173ns typ, 379ns min, 102ns max; typ from 1.8 V to 0.049 V
[POWER_clamp]
-1.8V     401.1mA    209.4mA    454.2mA
-1.145V   79.39mA    49.82mA    86.39mA
-1.073V   52.49mA    35.39mA    58.76mA
-1.036V   40.67mA    28.68mA    46.87mA
-963.6mV  24.19mA    17.73mA    28.97mA
-927.3mV  18.17mA    13.19mA    21.87mA
-890.9mV  14.63mA    10.1mA     17.61mA
-818.2mV  10.26mA    6.071mA    12.52mA
-600mV    2.834mA    1.747mA    2.888mA
-490.9mV  760.8uA    616.2uA    563.4uA
-381.8mV  112.8uA    147.2uA    57.34uA
1.764V    -11.66nA   -1.927uA   -18.08nA
[Pulldown]
-1.8V     -777mA     -2.558A    -458.4mA
-1.418V   -503.6mA   -1.704A    -274.2mA
-1.091V   -246.1mA   -833.2mA   -147.5mA
-927.3mV  -206.1mA   -396.1mA   -321.7mA
-818.2mV  -374.6mA   -240.3mA   -550mA
-709.1mV  -482.9mA   -278.1mA   -677.4mA
-600mV    -465.4mA   -277.4mA   -649.6mA
218.2mV   131.1mA    73.64mA    187.8mA
545.5mV   267.4mA    143.9mA    391.4mA
927.3mV   350.9mA    177.7mA    534.1mA
1.855V    388.5mA    188.1mA    630.8mA
3.545V    373.8mA    185.1mA    613mA
[GND_clamp]
-1.8V     -6.905A    -5.48A     -6.849A
-1.145V   -1.563A    -1.472A    -1.273A
-1.109V   -1.305A    -1.292A    -1.009A
-1.073V   -1.058A    -1.118A    -761.8mA
-1.036V   -819.4mA   -948.6mA   -530.3mA
-1V       -610.5mA   -793.2mA   -361.6mA
-927.3mV  -263.9mA   -507.2mA   -161.9mA
-890.9mV  -170.2mA   -389mA     -139.4mA
-818.2mV  -74.8mA    -191.7mA   -117.8mA
-745.5mV  -55.76mA   -81.74mA   -95.49mA
-600mV    -15.41mA   -10.81mA   -28.59mA
3.6V      0A         0A         0A
[Ramp]
dV/dt_f  1.0811743/0.14452588u 0.96934629/0.28751531u  1.1383501/91.763717n
dV/dt_r  0.2335222/4.1710707n   0.163537/5.2223301n 0.29156226/3.4132007n
R_load = 528.00
[Rising Waveform]
R_fixture = 500
V_fixture = 1.8
V_fixture_min = 1.62
V_fixture_max = 1.89
2.081ns   5.399mV    8.349mV    4.056mV
2.932ns   -54.22mV   8.348mV    711.7mV
3.656ns   444.7mV    8.348mV    1.076V
4.304ns   784.4mV    8.138mV    1.299V
5.143ns   1.09V      11.24mV    1.503V
6.178ns   1.338V     507.9mV    1.66V
7.892ns   1.576V     1.022V     1.79V
10.22ns   1.714V     1.349V     1.859V
13.21ns   1.775V     1.519V     1.883V
18.24ns   1.8V       1.62V      1.89V
[Rising Waveform]
R_fixture = 50
V_fixture = 1.8
V_fixture_min = 1.62
V_fixture_max = 1.89
1.829ns   49.48mV    79.98mV    35.63mV
2.102ns   49.48mV    79.98mV    1.315V
2.607ns   48.38mV    79.98mV    1.763V
2.806ns   135.8mV    79.98mV    1.812V
3.104ns   1.297V     79.98mV    1.852V
3.535ns   1.629V     79.98mV    1.877V
4.885ns   1.784V     145.2mV    1.89V
5.263ns   1.792V     1.12V      1.89V
5.598ns   1.795V     1.407V     1.89V
7.65ns    1.8V       1.62V      1.89V
[Falling Waveform]
R_fixture = 500
V_fixture = 1.8
V_fixture_min = 1.62
V_fixture_max = 1.89
46.66ns   1.8V       1.62V      1.89V
109.3ns   1.728V     1.623V     1.297V
157ns     1.481V     1.62V      727.7mV
196.4ns   1.231V     1.606V     102.9mV
207.4ns   1.158V     1.597V     30.87mV
331.5ns   116.6mV    1.357V     5.098mV
348.1ns   44.46mV    1.312V     4.919mV
567.2ns   6.834mV    631.2mV    4.187mV
688.2ns   6.077mV    119.7mV    4.11mV
781.2ns   5.399mV    8.349mV    4.056mV
[Falling Waveform]
R_fixture = 50
V_fixture = 1.8
V_fixture_min = 1.62
V_fixture_max = 1.89
55.66ns   1.8V       1.62V      1.89V
138.6ns   1.718V     1.62V      1.245V
187.3ns   1.52V      1.619V     729.4mV
226.4ns   1.327V     1.613V     200.8mV
253.4ns   1.185V     1.603V     84.48mV
334.2ns   711.8mV    1.522V     46.67mV
397.7ns   234.3mV    1.417V     41.13mV
443.4ns   115.2mV    1.33V      39.24mV
900.4ns   52.07mV    231.2mV    35.75mV
1.299us   49.48mV    79.98mV    35.63mV
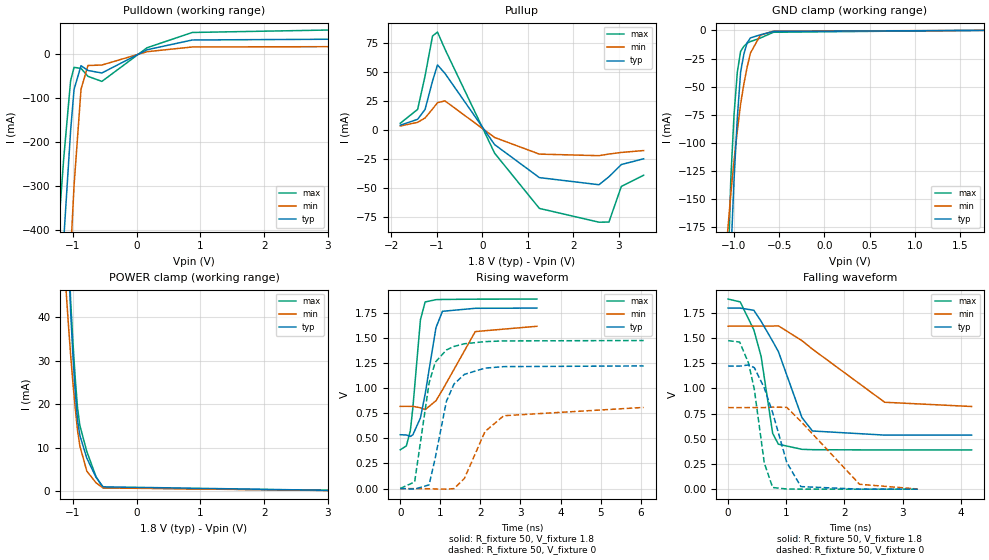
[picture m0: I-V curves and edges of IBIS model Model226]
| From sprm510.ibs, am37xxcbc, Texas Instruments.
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| Model based on original model for BQ18OMAPSMART2FBPB_SSBHH
|   Sub model ART2FBPB_H_1_PD1_1P8
[model]   Model226
|[Input Load]   PD
|[Output Drive] LB1
|Voltage   1.8V
|Mode   I/O
Model_type   I/O
Polarity   Non-Inverting
Enable   Active-Low
Vinl =  0.63
Vinh =  1.17
Cref =  15pF
Rref =  100.0000M
Vref =  0V
Vmeas =  0.9
C_comp   1.612314p   1.445601p   1.775954p
[Model Spec]
Vinl   0.63   0.567   0.6615
Vinh   1.17   1.053   1.2285
[Temperature Range]   25   125   -40
[Voltage Range]   1.8   1.62   1.89
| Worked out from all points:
|   slope of the pulldown table from 0 to 0.27 V, typ, clamps not added: 17.8 ohm
|   slope of the pullup table from 0 to 0.27 V, typ, clamps not added: 21.5 ohm
|   GND clamp passes 1 mA (typ) near -0.58 V on its own axis
|   POWER clamp passes 1 mA (typ) near -0.53 V on its own axis
|   rising waveform, R_fixture 50, V_fixture 1.8: 20-80 % time 312ps typ, 616ps min, 193ps max; typ from 0.537 V to 1.8 V
|   rising waveform, R_fixture 50, V_fixture 0: 20-80 % time 403ps typ, 602ps min, 354ps max; typ from 0 V to 1.22 V
|   falling waveform, R_fixture 50, V_fixture 1.8: 20-80 % time 534ps typ, 1.09ns min, 284ps max; typ from 1.8 V to 0.537 V
|   falling waveform, R_fixture 50, V_fixture 0: 20-80 % time 383ps typ, 721ps min, 227ps max; typ from 1.22 V to 0 V
[POWER_clamp]
-1.8V     449.2mA    229.3mA    499.9mA
-1.109V   70.08mA    46.67mA    71.87mA
-1.073V   55.21mA    38.88mA    57.08mA
-1.036V   41.54mA    31.43mA    44.06mA
-1V       31.27mA    24.96mA    34.34mA
-963.6mV  22.88mA    19.13mA    26.04mA
-927.3mV  16.35mA    13.96mA    19.14mA
-890.9mV  12.8mA     10.36mA    15.1mA
-781.8mV  7.558mA    4.572mA    9.086mA
-636.4mV  3.123mA    1.858mA    3.262mA
-527.3mV  948.5uA    698.4uA    767.3uA
3.6V      0A         0A         0A
[Pulldown]
-1.8V     -1.866A    -2.926A    -1.473A
-1.255V   -690.3mA   -1.165A    -458.8mA
-1.2V     -556.9mA   -981.3mA   -347.5mA
-1.145V   -424mA     -799.3mA   -238.7mA
-1.036V   -174.1mA   -452.5mA   -60.3mA
-981.8mV  -80.13mA   -298.3mA   -30.04mA
-872.7mV  -26.27mA   -79.78mA   -32.44mA
-763.6mV  -37.27mA   -25.87mA   -50.47mA
-545.5mV  -42.85mA   -24.82mA   -62.02mA
163.6mV   9.905mA    5.464mA    14.49mA
872.7mV   32.06mA    16.22mA    49.12mA
3.545V    34.18mA    16.99mA    56.07mA
[Pullup]
-1.8V     4.02mA     3.353mA    5.71mA
-1.418V   9.153mA    6.524mA    17.71mA
-1.255V   17.65mA    10.28mA    46.46mA
-1.091V   42.13mA    17.99mA    80.98mA
-981.8mV  56.04mA    23.5mA     84.34mA
-818.2mV  48.72mA    25.01mA    69.63mA
272.7mV   -12.68mA   -6.535mA   -20.08mA
1.255V    -41.13mA   -20.87mA   -67.69mA
2.564V    -47.26mA   -22.22mA   -79.57mA
2.782V    -40.42mA   -20.82mA   -79.47mA
3.055V    -29.85mA   -19.43mA   -48.72mA
3.545V    -24.9mA    -17.8mA    -39.06mA
[GND_clamp]
-1.8V     -3.26A     -1.496A    -3.636A
-1.073V   -295.4mA   -181.3mA   -234.2mA
-1.036V   -202.2mA   -145.8mA   -132.5mA
-1V       -132.7mA   -116.1mA   -74.87mA
-963.6mV  -77.6mA    -89.37mA   -36.88mA
-927.3mV  -36.98mA   -65.53mA   -18.59mA
-890.9mV  -20.91mA   -47.52mA   -14.09mA
-854.5mV  -10.79mA   -32.36mA   -11.18mA
-818.2mV  -6.606mA   -20.04mA   -9.859mA
-709.1mV  -3.829mA   -4.176mA   -6.715mA
-563.6mV  -831uA     -577.4uA   -1.567mA
1.764V    97.78uA    55.24uA    156.3uA
[Ramp]
dV/dt_f  0.7587043/0.5351002n  0.4817126/1.098298n   0.9000697/0.2838147n
dV/dt_r  0.7382692/0.4028805n  0.4896911/0.6046284n  0.8904517/0.3545121n
R_load = 50
[Rising Waveform]
R_fixture = 50
V_fixture = 1.8
V_fixture_min = 1.62
V_fixture_max = 1.89
0s        536.5mV    819.2mV    386.5mV
153ps     534.2mV    819.5mV    425.5mV
252ps     519.2mV    819.2mV    576.7mV
315ps     536.1mV    819.5mV    805.3mV
504ps     704mV      804.7mV    1.682V
621ps     940.7mV    786.3mV    1.859V
891ps     1.602V     874.7mV    1.882V
1.053ns   1.766V     982.4mV    1.884V
1.872ns   1.796V     1.564V     1.887V
3.411ns   1.798V     1.617V     1.888V
[Rising Waveform]
R_fixture = 50
V_fixture = 0
V_fixture_min = 0
V_fixture_max = 0
0s        -159.6uV   -895.5nV   1.246mV
360ps     -4.929mV   -313.6uV   66.55mV
720ps     36.87mV    -1.698mV   1.052V
873ps     303.3mV    -4.044mV   1.258V
1.152ns   869.5mV    -5.797mV   1.381V
1.341ns   1.041V     -388.2uV   1.416V
1.602ns   1.138V     101.4mV    1.443V
2.115ns   1.2V       567.8mV    1.464V
2.583ns   1.215V     725.8mV    1.471V
6.075ns   1.222V     808.5mV    1.475V
[Falling Waveform]
R_fixture = 50
V_fixture = 1.8
V_fixture_min = 1.62
V_fixture_max = 1.89
0s        1.799V     1.619V     1.888V
207ps     1.798V     1.619V     1.86V
441ps     1.777V     1.619V     1.583V
567ps     1.667V     1.619V     1.318V
765ps     1.469V     1.62V      554.4mV
864ps     1.366V     1.622V     446.4mV
1.269ns   710.8mV    1.475V     395.7mV
1.449ns   577.8mV    1.391V     392mV
2.691ns   536.9mV    863.1mV    389.3mV
4.185ns   536.6mV    821mV      389.3mV
[Falling Waveform]
R_fixture = 50
V_fixture = 0
V_fixture_min = 0
V_fixture_max = 0
0s        1.223V     810.3mV    1.475V
198ps     1.222V     810mV      1.461V
351ps     1.234V     810.6mV    1.251V
450ps     1.207V     810.5mV    990.9mV
621ps     1.006V     809.9mV    260.7mV
765ps     760.8mV    815.3mV    16.47mV
1.008ns   265.1mV    812.2mV    1.502mV
1.251ns   25.35mV    672.4mV    172.8uV
2.259ns   103uV      48.65mV    1.444uV
3.258ns   33.56uV    1.648mV    432.1nV
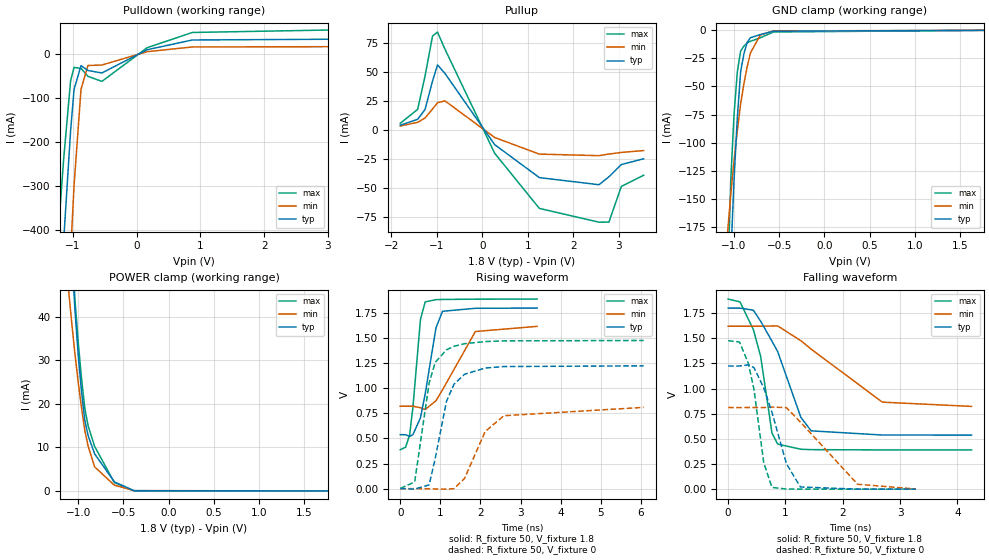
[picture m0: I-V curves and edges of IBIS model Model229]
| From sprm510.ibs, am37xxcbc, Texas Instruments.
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| Model based on original model for BQ18OMAPSMART2FBPB_SSBHH
|   Sub model T2FBPB_H_1_PUPD0_1P8
[model]   Model229
|[Input Load]   PI
|[Output Drive] LB1
|Voltage   1.8V
|Mode   I/O
Model_type   I/O
Polarity   Non-Inverting
Enable   Active-Low
Vinl =  0.63
Vinh =  1.17
Cref =  15pF
Rref =  100.0000M
Vref =  0V
Vmeas =  0.9
C_comp   1.612314p   1.445601p   1.775954p
[Model Spec]
Vinl   0.63   0.567   0.6615
Vinh   1.17   1.053   1.2285
[Temperature Range]   25   125   -40
[Voltage Range]   1.8   1.62   1.89
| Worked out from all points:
|   slope of the pulldown table from 0 to 0.27 V, typ, clamps not added: 17.8 ohm
|   slope of the pullup table from 0 to 0.27 V, typ, clamps not added: 21.5 ohm
|   GND clamp passes 1 mA (typ) near -0.58 V on its own axis
|   POWER clamp passes 1 mA (typ) near -0.54 V on its own axis
|   rising waveform, R_fixture 50, V_fixture 1.8: 20-80 % time 312ps typ, 615ps min, 193ps max; typ from 0.538 V to 1.8 V
|   rising waveform, R_fixture 50, V_fixture 0: 20-80 % time 403ps typ, 603ps min, 353ps max; typ from 0 V to 1.22 V
|   falling waveform, R_fixture 50, V_fixture 1.8: 20-80 % time 535ps typ, 1.09ns min, 284ps max; typ from 1.8 V to 0.538 V
|   falling waveform, R_fixture 50, V_fixture 0: 20-80 % time 383ps typ, 722ps min, 227ps max; typ from 1.22 V to 0 V
[POWER_clamp]
-1.8V     449.2mA    229.3mA    499.9mA
-1.109V   70.03mA    46.65mA    71.76mA
-1.073V   55.15mA    38.86mA    56.96mA
-1.036V   41.47mA    31.41mA    43.93mA
-1V       31.2mA     24.93mA    34.21mA
-963.6mV  22.8mA     19.1mA     25.91mA
-927.3mV  16.27mA    13.92mA    19.01mA
-890.9mV  12.72mA    10.32mA    14.97mA
-818.2mV  8.506mA    5.529mA    10.22mA
-600mV    2.086mA    1.321mA    1.925mA
-381.8mV  46uA       75.05uA    15.45uA
1.764V    -1.718nA   -102nA     -1.848nA
[Pulldown]
-1.8V     -1.866A    -2.926A    -1.473A
-1.255V   -690.3mA   -1.165A    -458.8mA
-1.2V     -556.9mA   -981.3mA   -347.5mA
-1.145V   -424mA     -799.3mA   -238.7mA
-1.036V   -174.1mA   -452.5mA   -60.31mA
-981.8mV  -80.13mA   -298.3mA   -30.04mA
-872.7mV  -26.27mA   -79.78mA   -32.44mA
-763.6mV  -37.26mA   -25.87mA   -50.47mA
-545.5mV  -42.85mA   -24.82mA   -62.02mA
163.6mV   9.905mA    5.464mA    14.49mA
872.7mV   32.06mA    16.22mA    49.12mA
3.545V    34.18mA    16.99mA    56.07mA
[Pullup]
-1.8V     4.02mA     3.353mA    5.71mA
-1.418V   9.153mA    6.524mA    17.71mA
-1.255V   17.65mA    10.28mA    46.45mA
-1.091V   42.12mA    17.99mA    80.97mA
-981.8mV  56.04mA    23.5mA     84.34mA
-818.2mV  48.72mA    25.01mA    69.63mA
272.7mV   -12.68mA   -6.535mA   -20.08mA
1.255V    -41.13mA   -20.87mA   -67.69mA
2.564V    -47.26mA   -22.22mA   -79.57mA
2.782V    -40.42mA   -20.82mA   -79.47mA
3.055V    -29.85mA   -19.43mA   -48.72mA
3.545V    -24.9mA    -17.8mA    -39.06mA
[GND_clamp]
-1.8V     -3.26A     -1.496A    -3.636A
-1.073V   -295.4mA   -181.3mA   -234.2mA
-1.036V   -202.1mA   -145.8mA   -132.5mA
-1V       -132.6mA   -116.1mA   -74.83mA
-963.6mV  -77.56mA   -89.36mA   -36.83mA
-927.3mV  -36.94mA   -65.52mA   -18.53mA
-890.9mV  -20.86mA   -47.5mA    -14.02mA
-854.5mV  -10.73mA   -32.34mA   -11.09mA
-818.2mV  -6.545mA   -20.02mA   -9.764mA
-709.1mV  -3.764mA   -4.146mA   -6.62mA
-563.6mV  -769uA     -544.8uA   -1.476mA
1.764V    -70.4pA    812.3nA    3.348nA
[Ramp]
dV/dt_f  0.7588165/0.5358226n  0.4813441/1.099174n   0.9004992/0.2841963n
dV/dt_r  0.7393208/0.402969n   0.4904897/0.605419n   0.8915728/0.3537921n
R_load = 50
[Rising Waveform]
R_fixture = 50
V_fixture = 1.8
V_fixture_min = 1.62
V_fixture_max = 1.89
0s        537.7mV    821mV      387.3mV
135ps     537.4mV    821.3mV    412.9mV
234ps     520mV      821mV      535.5mV
315ps     537.3mV    821.2mV    807.6mV
504ps     705.9mV    806.4mV    1.686V
621ps     943.2mV    787.9mV    1.862V
891ps     1.605V     876.6mV    1.884V
1.053ns   1.768V     984.5mV    1.886V
1.872ns   1.798V     1.566V     1.889V
3.411ns   1.8V       1.618V     1.89V
[Rising Waveform]
R_fixture = 50
V_fixture = 0
V_fixture_min = 0
V_fixture_max = 0
0s        -159.6uV   -913.8nV   1.247mV
360ps     -4.93mV    -313.6uV   66.55mV
720ps     36.86mV    -1.697mV   1.054V
873ps     303.4mV    -4.044mV   1.26V
1.152ns   870.7mV    -5.801mV   1.384V
1.341ns   1.042V     -393.8uV   1.419V
1.602ns   1.14V      101.4mV    1.445V
2.115ns   1.202V     568.3mV    1.466V
2.583ns   1.217V     726.7mV    1.473V
6.066ns   1.224V     809.8mV    1.477V
[Falling Waveform]
R_fixture = 50
V_fixture = 1.8
V_fixture_min = 1.62
V_fixture_max = 1.89
0s        1.8V       1.62V      1.89V
207ps     1.8V       1.62V      1.862V
441ps     1.779V     1.62V      1.585V
567ps     1.669V     1.62V      1.321V
765ps     1.471V     1.622V     557.4mV
864ps     1.368V     1.623V     448.4mV
1.269ns   713.8mV    1.476V     396.7mV
1.449ns   579.8mV    1.392V     392.9mV
2.691ns   538.1mV    865.1mV    390.2mV
4.248ns   537.8mV    822.8mV    390.2mV
[Falling Waveform]
R_fixture = 50
V_fixture = 0
V_fixture_min = 0
V_fixture_max = 0
0s        1.224V     811.6mV    1.476V
198ps     1.224V     811.4mV    1.463V
351ps     1.236V     811.9mV    1.253V
450ps     1.209V     811.8mV    994mV
621ps     1.008V     811.2mV    263mV
765ps     762.9mV    816.6mV    17.53mV
1.017ns   253.1mV    810.5mV    1.556mV
1.26ns    22.09mV    667.8mV    209.2uV
2.259ns   126.7uV    49.02mV    1.479uV
3.276ns   36.66uV    1.67mV     429.8nV
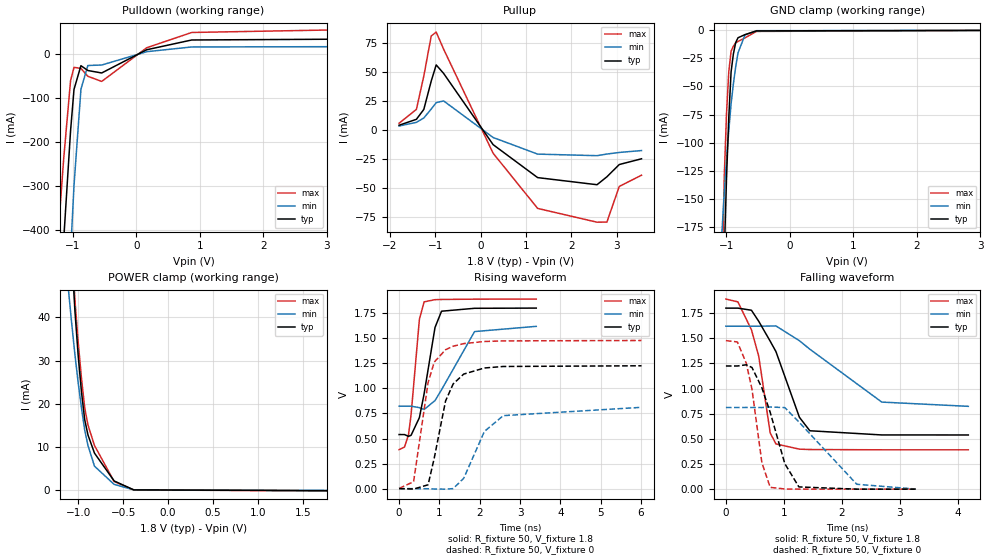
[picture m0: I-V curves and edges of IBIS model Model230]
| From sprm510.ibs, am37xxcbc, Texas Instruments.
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| Model based on original model for BQ18OMAPSMART2FBPB_SSBHH
|   Sub model ART2FBPB_H_1_PU1_1P8
[model]   Model230
|[Input Load]   PU
|[Output Drive] LB1
|Voltage   1.8V
|Mode   I/O
Model_type   I/O
Polarity   Non-Inverting
Enable   Active-Low
Vinl =  0.63
Vinh =  1.17
Cref =  15pF
Rref =  100.0000M
Vref =  0V
Vmeas =  0.9
C_comp   1.612314p   1.445601p   1.775954p
[Model Spec]
Vinl   0.63   0.567   0.6615
Vinh   1.17   1.053   1.2285
[Temperature Range]   25   125   -40
[Voltage Range]   1.8   1.62   1.89
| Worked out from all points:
|   slope of the pulldown table from 0 to 0.27 V, typ, clamps not added: 17.8 ohm
|   slope of the pullup table from 0 to 0.27 V, typ, clamps not added: 21.5 ohm
|   GND clamp passes 1 mA (typ) near -0.57 V on its own axis
|   POWER clamp passes 1 mA (typ) near -0.53 V on its own axis
|   rising waveform, R_fixture 50, V_fixture 1.8: 20-80 % time 312ps typ, 615ps min, 193ps max; typ from 0.54 V to 1.8 V
|   rising waveform, R_fixture 50, V_fixture 0: 20-80 % time 402ps typ, 602ps min, 353ps max; typ from 0.001 V to 1.23 V
|   falling waveform, R_fixture 50, V_fixture 1.8: 20-80 % time 535ps typ, 1.09ns min, 284ps max; typ from 1.8 V to 0.54 V
|   falling waveform, R_fixture 50, V_fixture 0: 20-80 % time 383ps typ, 722ps min, 227ps max; typ from 1.23 V to 0.001 V
[POWER_clamp]
-1.8V     449.2mA    229.3mA    499.9mA
-1.109V   70.1mA     46.68mA    71.89mA
-1.073V   55.22mA    38.88mA    57.09mA
-1.036V   41.55mA    31.43mA    44.07mA
-1V       31.28mA    24.96mA    34.35mA
-963.6mV  22.88mA    19.13mA    26.04mA
-927.3mV  16.35mA    13.96mA    19.14mA
-890.9mV  12.8mA     10.36mA    15.1mA
-818.2mV  8.584mA    5.567mA    10.34mA
-600mV    2.149mA    1.354mA    2.023mA
-381.8mV  86.82uA    96.98uA    78.48uA
1.764V    -96.73uA   -46.5uA    -163.5uA
[Pulldown]
-1.8V     -1.866A    -2.926A    -1.473A
-1.255V   -690.3mA   -1.165A    -458.8mA
-1.2V     -556.9mA   -981.3mA   -347.5mA
-1.145V   -424mA     -799.3mA   -238.7mA
-1.036V   -174.1mA   -452.5mA   -60.3mA
-981.8mV  -80.13mA   -298.3mA   -30.04mA
-872.7mV  -26.27mA   -79.78mA   -32.44mA
-763.6mV  -37.27mA   -25.87mA   -50.47mA
-545.5mV  -42.85mA   -24.82mA   -62.02mA
163.6mV   9.905mA    5.464mA    14.49mA
872.7mV   32.06mA    16.22mA    49.12mA
3.545V    34.18mA    16.99mA    56.07mA
[Pullup]
-1.8V     4.02mA     3.353mA    5.71mA
-1.418V   9.153mA    6.524mA    17.71mA
-1.255V   17.65mA    10.28mA    46.46mA
-1.091V   42.13mA    17.99mA    80.98mA
-981.8mV  56.04mA    23.5mA     84.34mA
-818.2mV  48.72mA    25.01mA    69.63mA
272.7mV   -12.68mA   -6.535mA   -20.08mA
1.255V    -41.13mA   -20.87mA   -67.69mA
2.564V    -47.26mA   -22.22mA   -79.57mA
2.782V    -40.42mA   -20.82mA   -79.47mA
3.055V    -29.85mA   -19.43mA   -48.72mA
3.545V    -24.9mA    -17.8mA    -39.06mA
[GND_clamp]
-1.8V     -3.26A     -1.496A    -3.636A
-1.073V   -295.4mA   -181.3mA   -234.2mA
-1.036V   -202.2mA   -145.8mA   -132.6mA
-1V       -132.7mA   -116.1mA   -74.88mA
-963.6mV  -77.6mA    -89.37mA   -36.9mA
-927.3mV  -36.98mA   -65.53mA   -18.61mA
-890.9mV  -20.91mA   -47.52mA   -14.11mA
-854.5mV  -10.79mA   -32.36mA   -11.2mA
-818.2mV  -6.611mA   -20.04mA   -9.885mA
-709.1mV  -3.838mA   -4.175mA   -6.748mA
-527.3mV  -502uA     -336.2uA   -960.8uA
3.6V      0A         0A         0A
[Ramp]
dV/dt_f  0.7577384/0.535922n   0.4805443/1.099283n   0.899281/0.2842524n
dV/dt_r  0.7391082/0.4022058n  0.4905625/0.6046513n  0.8910455/0.3530171n
R_load = 50
[Rising Waveform]
R_fixture = 50
V_fixture = 1.8
V_fixture_min = 1.62
V_fixture_max = 1.89
0s        539.5mV    822.3mV    389.3mV
135ps     539.2mV    822.6mV    415.1mV
234ps     521.7mV    822.3mV    538.8mV
297ps     532.1mV    822.4mV    735.4mV
504ps     708.6mV    807.7mV    1.689V
621ps     946.4mV    789.2mV    1.862V
891ps     1.607V     878.1mV    1.884V
1.053ns   1.769V     986.1mV    1.886V
1.872ns   1.798V     1.566V     1.889V
3.402ns   1.8V       1.618V     1.89V
[Rising Waveform]
R_fixture = 50
V_fixture = 0
V_fixture_min = 0
V_fixture_max = 0
0s        937.9uV    793uV      2.597mV
360ps     -3.783mV   480.3uV    69.58mV
720ps     38.82mV    -906uV     1.059V
873ps     306.8mV    -3.221mV   1.262V
1.152ns   873.7mV    -4.881mV   1.385V
1.341ns   1.044V     635.9uV    1.42V
1.602ns   1.142V     102.8mV    1.446V
2.115ns   1.203V     570mV      1.467V
2.583ns   1.218V     728mV      1.473V
6.012ns   1.225V     810.8mV    1.477V
[Falling Waveform]
R_fixture = 50
V_fixture = 1.8
V_fixture_min = 1.62
V_fixture_max = 1.89
0s        1.8V       1.62V      1.89V
207ps     1.8V       1.62V      1.862V
441ps     1.779V     1.62V      1.585V
567ps     1.669V     1.62V      1.322V
765ps     1.471V     1.622V     559.6mV
864ps     1.368V     1.623V     450.5mV
1.269ns   715.3mV    1.476V     398.8mV
1.449ns   581.5mV    1.392V     395mV
2.691ns   539.9mV    866.3mV    392.2mV
4.185ns   539.6mV    824.1mV    392.2mV
[Falling Waveform]
R_fixture = 50
V_fixture = 0
V_fixture_min = 0
V_fixture_max = 0
0s        1.225V     812.6mV    1.477V
198ps     1.225V     812.4mV    1.464V
351ps     1.237V     812.9mV    1.254V
450ps     1.21V      812.8mV    995.6mV
621ps     1.009V     812.2mV    265mV
765ps     764.3mV    817.6mV    18.98mV
1.017ns   254.6mV    811.5mV    2.955mV
1.26ns    23.5mV     668.8mV    1.591mV
2.259ns   1.223mV    49.9mV     1.374mV
3.276ns   1.133mV    2.469mV    1.373mV
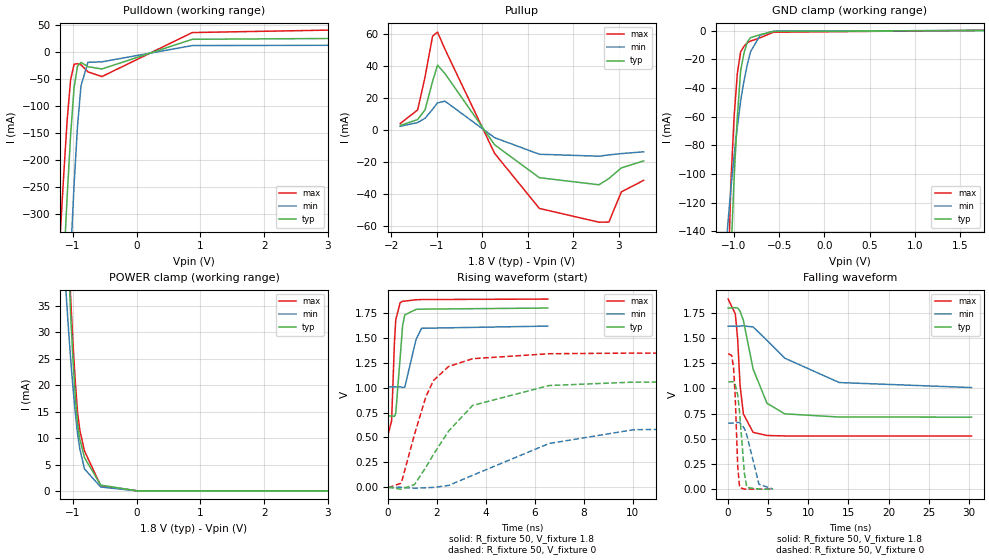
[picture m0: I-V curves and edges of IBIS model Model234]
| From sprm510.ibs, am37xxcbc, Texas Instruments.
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| Model based on original model for BQ18OMAPSMART1HYFBPB_SSBHV
|   Sub model FBPB_VS00L11_PD1_1P8
[model]   Model234
|[Input Load]   PD
|[Output Drive] SC00LB11
|Voltage   1.8V
|Mode   I/O
Model_type   I/O
Polarity   Non-Inverting
Enable   Active-Low
Vinl =  0.63
Vinh =  1.17
Cref =  15pF
Rref =  100.0000M
Vref =  0V
Vmeas =  0.9
C_comp   1.429432p   1.270657p   1.602015p
[Model Spec]
Vinl   0.63   0.567   0.6615
Vinh   1.17   1.053   1.2285
[Temperature Range]   25   125   -40
[Voltage Range]   1.8   1.62   1.89
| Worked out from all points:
|   slope of the pulldown table from 0 to 0.27 V, typ, clamps not added: 24.3 ohm
|   slope of the pullup table from 0 to 0.27 V, typ, clamps not added: 29.7 ohm
|   GND clamp passes 1 mA (typ) near -0.60 V on its own axis
|   POWER clamp passes 1 mA (typ) near -0.55 V on its own axis
|   rising waveform, R_fixture 50, V_fixture 1.8: 20-80 % time 178ps typ, 312ps min, 125ps max; typ from 0.716 V to 1.8 V
|   rising waveform, R_fixture 50, V_fixture 0: 20-80 % time 2.08ns typ, 4.63ns min, 1.07ns max; typ from 0 V to 1.06 V
|   falling waveform, R_fixture 50, V_fixture 1.8: 20-80 % time 2.09ns typ, 5.9ns min, 723ps max; typ from 1.8 V to 0.716 V
|   falling waveform, R_fixture 50, V_fixture 0: 20-80 % time 636ps typ, 1.14ns min, 381ps max; typ from 1.06 V to 0 V
[POWER_clamp]
-1.8V     362.5mA    191.4mA    412.8mA
-1.109V   56.74mA    37.73mA    60.49mA
-1.073V   44.66mA    31.25mA    47.92mA
-1.036V   33.51mA    25.07mA    36.71mA
-1V       25.05mA    19.75mA    28.19mA
-963.6mV  18.1mA     14.99mA    20.91mA
-927.3mV  12.67mA    10.8mA     14.87mA
-890.9mV  9.735mA    7.937mA    11.45mA
-818.2mV  6.3mA      4.158mA    7.553mA
-563.6mV  1.102mA    739.7uA    992.8uA
18.18mV   0A         0A         0A
3.6V      0A         0A         0A
[Pulldown]
-1.8V     -1.718A    -2.61A     -1.406A
-1.2V     -527.4mA   -844.5mA   -339.9mA
-1.145V   -396mA     -683.1mA   -229.1mA
-1.091V   -269mA     -526.7mA   -127.5mA
-1.036V   -153.6mA   -378.9mA   -51.17mA
-981.8mV  -66.33mA   -245.6mA   -22.67mA
-927.3mV  -26mA      -136.2mA   -21.54mA
-872.7mV  -19.34mA   -61.98mA   -23.69mA
-763.6mV  -27.2mA    -19.05mA   -36.72mA
-545.5mV  -31.39mA   -18.17mA   -45.46mA
872.7mV   23.46mA    11.88mA    35.92mA
3.545V    25.34mA    12.51mA    41.58mA
[Pullup]
-1.8V     2.903mA    2.423mA    4.112mA
-1.418V   6.595mA    4.711mA    12.64mA
-1.255V   12.69mA    7.42mA     33.24mA
-1.091V   30.4mA     13mA       58.69mA
-981.8mV  40.63mA    17.02mA    61.3mA
-818.2mV  35.38mA    18.12mA    50.59mA
272.7mV   -9.18mA    -4.728mA   -14.55mA
1.255V    -29.75mA   -15.09mA   -48.97mA
2.564V    -34.17mA   -16.31mA   -57.57mA
2.782V    -30.25mA   -15.5mA    -57.48mA
3.055V    -23.63mA   -14.68mA   -38.61mA
3.545V    -19.25mA   -13.56mA   -31.41mA
[GND_clamp]
-1.8V     -2.82A     -1.192A    -3.165A
-1.073V   -235.8mA   -138.4mA   -192.1mA
-1.036V   -159.6mA   -110.8mA   -107.6mA
-1V       -103.8mA   -87.86mA   -60.71mA
-963.6mV  -60.04mA   -67.29mA   -29.85mA
-927.3mV  -28.26mA   -49.1mA    -14.96mA
-890.9mV  -15.95mA   -35.5mA    -11.07mA
-854.5mV  -8.194mA   -24.09mA   -8.535mA
-818.2mV  -4.986mA   -14.87mA   -7.361mA
-709.1mV  -2.849mA   -3.094mA   -4.979mA
-563.6mV  -632.2uA   -437.1uA   -1.183mA
1.764V    97.78uA    55.01uA    156.3uA
[Ramp]
dV/dt_f   0.652349/2.09174n   0.3692/5.948839n   0.8182934/0.7220425n
dV/dt_r  0.6504898/2.08531n   0.4000181/4.672001n   0.8229218/1.075061n
R_load = 50
[Rising Waveform]
R_fixture = 50
V_fixture = 1.8
V_fixture_min = 1.62
V_fixture_max = 1.89
0s        715.6mV    1.007V     530mV
144ps     716.6mV    1.007V     665.8mV
261ps     711mV      1.007V     1.455V
315ps     742.2mV    1.007V     1.681V
495ps     1.303V     1.009V     1.852V
594ps     1.62V      1.001V     1.865V
684ps     1.729V     1.004V     1.868V
1.143ns   1.785V     1.483V     1.881V
1.368ns   1.787V     1.595V     1.883V
6.525ns   1.798V     1.617V     1.888V
[Rising Waveform]
R_fixture = 50
V_fixture = 0
V_fixture_min = 0
V_fixture_max = 0
0s        -338.4uV   80.51uV    -3.447mV
540ps     -18.26mV   764.1uV    41.93mV
1.08ns    28.22mV    -9.141mV   531.1mV
1.548ns   201.7mV    -3.832mV   910.5mV
1.854ns   329.7mV    -477.6uV   1.071V
2.475ns   564.6mV    19.07mV    1.212V
3.456ns   821.5mV    120.9mV    1.29V
6.579ns   1.021V     439.5mV    1.34V
10.02ns   1.055V     577.4mV    1.346V
30.43ns   1.065V     654.4mV    1.346V
[Falling Waveform]
R_fixture = 50
V_fixture = 1.8
V_fixture_min = 1.62
V_fixture_max = 1.89
0s        1.798V     1.619V     1.888V
891ps     1.803V     1.618V     1.741V
1.188ns   1.798V     1.619V     1.489V
1.485ns   1.768V     1.62V      1.03V
1.899ns   1.676V     1.622V     747.1mV
3.114ns   1.193V     1.611V     564.1mV
4.842ns   853mV      1.478V     533.1mV
7.065ns   747.9mV    1.301V     528.6mV
13.85ns   716.2mV    1.059V     528.2mV
30.36ns   715.5mV    1.009V     528.2mV
[Falling Waveform]
R_fixture = 50
V_fixture = 0
V_fixture_min = 0
V_fixture_max = 0
0s        1.065V     655.9mV    1.346V
441ps     1.068V     656.2mV    1.328V
675ps     1.066V     655.9mV    1.204V
873ps     1.041V     657.1mV    933.2mV
1.197ns   932.1mV    662.8mV    220.2mV
1.431ns   761.9mV    662mV      16.47mV
2.025ns   156.6mV    603.5mV    806uV
2.331ns   16.78mV    534.3mV    344.1uV
3.843ns   412.6uV    48.72mV    41.58uV
5.598ns   129.4uV    1.638mV    8.295uV
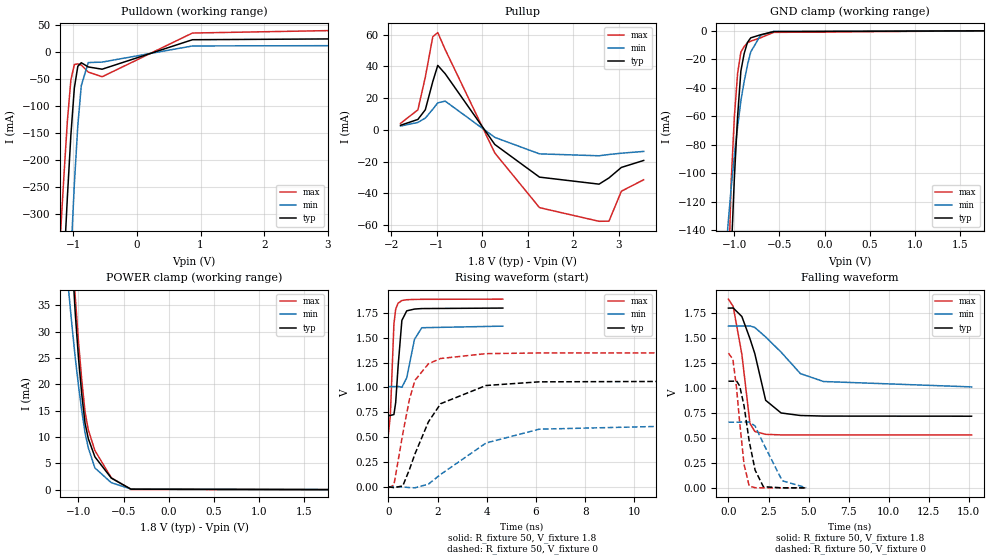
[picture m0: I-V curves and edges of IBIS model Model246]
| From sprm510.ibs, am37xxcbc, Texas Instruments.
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| Model based on original model for BQ18OMAPSMART1HYFBPB_SSBHV
|   Sub model PB_VS01L01_PUPD0_1P8
[model]   Model246
|[Input Load]   PI
|[Output Drive] SC01LB01
|Voltage   1.8V
|Mode   I/O
Model_type   I/O
Polarity   Non-Inverting
Enable   Active-Low
Vinl =  0.63
Vinh =  1.17
Cref =  15pF
Rref =  100.0000M
Vref =  0V
Vmeas =  0.9
C_comp   1.429432p   1.270657p   1.602015p
[Model Spec]
Vinl   0.63   0.567   0.6615
Vinh   1.17   1.053   1.2285
[Temperature Range]   25   125   -40
[Voltage Range]   1.8   1.62   1.89
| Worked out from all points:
|   slope of the pulldown table from 0 to 0.27 V, typ, clamps not added: 24.3 ohm
|   slope of the pullup table from 0 to 0.27 V, typ, clamps not added: 29.7 ohm
|   GND clamp passes 1 mA (typ) near -0.60 V on its own axis
|   POWER clamp passes 1 mA (typ) near -0.56 V on its own axis
|   rising waveform, R_fixture 50, V_fixture 1.8: 20-80 % time 176ps typ, 303ps min, 125ps max; typ from 0.717 V to 1.8 V
|   rising waveform, R_fixture 50, V_fixture 0: 20-80 % time 1.28ns typ, 2.78ns min, 687ps max; typ from 0 V to 1.07 V
|   falling waveform, R_fixture 50, V_fixture 1.8: 20-80 % time 1.07ns typ, 2.21ns min, 672ps max; typ from 1.8 V to 0.718 V
|   falling waveform, R_fixture 50, V_fixture 0: 20-80 % time 664ps typ, 1.08ns min, 492ps max; typ from 1.07 V to 0 V
[POWER_clamp]
-1.8V     362.5mA    191.4mA    412.8mA
-1.109V   56.69mA    37.71mA    60.38mA
-1.073V   44.6mA     31.22mA    47.8mA
-1.036V   33.44mA    25.04mA    36.59mA
-1V       24.98mA    19.72mA    28.06mA
-963.6mV  18.03mA    14.96mA    20.78mA
-927.3mV  12.59mA    10.77mA    14.74mA
-890.9mV  9.653mA    7.899mA    11.31mA
-818.2mV  6.214mA    4.114mA    7.414mA
-636.4mV  2.183mA    1.307mA    2.238mA
-418.2mV  83.85uA    105.2uA    35.14uA
1.764V    -1.228nA   -79.12nA   -1.453nA
[Pulldown]
-1.8V     -1.718A    -2.61A     -1.406A
-1.2V     -527.4mA   -844.5mA   -339.9mA
-1.145V   -396mA     -683.1mA   -229.1mA
-1.091V   -269mA     -526.7mA   -127.5mA
-1.036V   -153.6mA   -378.9mA   -51.17mA
-981.8mV  -66.34mA   -245.6mA   -22.67mA
-927.3mV  -26mA      -136.2mA   -21.54mA
-872.7mV  -19.34mA   -61.98mA   -23.69mA
-763.6mV  -27.2mA    -19.05mA   -36.72mA
-545.5mV  -31.39mA   -18.17mA   -45.46mA
872.7mV   23.46mA    11.88mA    35.92mA
3.545V    25.34mA    12.51mA    41.58mA
[Pullup]
-1.8V     2.903mA    2.423mA    4.112mA
-1.418V   6.595mA    4.711mA    12.64mA
-1.255V   12.69mA    7.42mA     33.23mA
-1.091V   30.4mA     13mA       58.69mA
-981.8mV  40.63mA    17.02mA    61.3mA
-818.2mV  35.38mA    18.12mA    50.59mA
272.7mV   -9.18mA    -4.728mA   -14.55mA
1.255V    -29.75mA   -15.09mA   -48.97mA
2.564V    -34.17mA   -16.31mA   -57.57mA
2.782V    -30.25mA   -15.5mA    -57.48mA
3.055V    -23.63mA   -14.68mA   -38.61mA
3.545V    -19.25mA   -13.56mA   -31.41mA
[GND_clamp]
-1.8V     -2.82A     -1.192A    -3.165A
-1.073V   -235.7mA   -138.4mA   -192.1mA
-1.036V   -159.5mA   -110.8mA   -107.5mA
-1V       -103.8mA   -87.85mA   -60.67mA
-963.6mV  -60mA      -67.28mA   -29.8mA
-927.3mV  -28.21mA   -49.08mA   -14.9mA
-890.9mV  -15.9mA    -35.48mA   -10.99mA
-854.5mV  -8.138mA   -24.07mA   -8.449mA
-818.2mV  -4.924mA   -14.85mA   -7.266mA
-709.1mV  -2.784mA   -3.064mA   -4.883mA
-563.6mV  -570.2uA   -404.5uA   -1.092mA
1.764V    -11.02pA   583.5nA    3.035nA
[Ramp]
dV/dt_f  0.6512379/1.076974n   0.3676462/2.225049n   0.8182469/0.6741499n
dV/dt_r  0.6508709/1.287752n   0.4007679/2.803363n   0.8227371/0.68846n
R_load = 50
[Rising Waveform]
R_fixture = 50
V_fixture = 1.8
V_fixture_min = 1.62
V_fixture_max = 1.89
0s        717.2mV    1.009V     528.2mV
81ps      718.9mV    1.009V     719.1mV
225ps     727.6mV    1.009V     1.637V
297ps     847mV      1.009V     1.789V
396ps     1.215V     1.011V     1.849V
549ps     1.676V     1.002V     1.876V
747ps     1.772V     1.098V     1.884V
1.062ns   1.79V      1.485V     1.887V
1.359ns   1.795V     1.602V     1.888V
4.653ns   1.8V       1.618V     1.89V
[Rising Waveform]
R_fixture = 50
V_fixture = 0
V_fixture_min = 0
V_fixture_max = 0
0s        -236.6uV   109.7uV    -10.79mV
225ps     -8.574mV   -404.7uV   17.14mV
585ps     8.566mV    -1.952mV   533.2mV
855ps     172.6mV    -8.105mV   880mV
1.08ns    330.6mV    -10.48mV   1.072V
1.629ns   654.3mV    27.02mV    1.239V
2.124ns   836.7mV    124.5mV    1.292V
3.969ns   1.02V      441mV      1.341V
6.129ns   1.057V     580.2mV    1.348V
19.25ns   1.067V     655.8mV    1.349V
[Falling Waveform]
R_fixture = 50
V_fixture = 1.8
V_fixture_min = 1.62
V_fixture_max = 1.89
0s        1.8V       1.62V      1.89V
297ps     1.801V     1.62V      1.816V
837ps     1.716V     1.62V      1.338V
1.341ns   1.495V     1.622V     646.6mV
1.647ns   1.343V     1.606V     564.6mV
2.322ns   876.8mV    1.511V     535.9mV
3.285ns   750mV      1.359V     530.4mV
4.491ns   724.6mV    1.144V     529.8mV
5.931ns   718.8mV    1.065V     529.8mV
15.17ns   717.6mV    1.011V     529.8mV
[Falling Waveform]
R_fixture = 50
V_fixture = 0
V_fixture_min = 0
V_fixture_max = 0
0s        1.068V     657.3mV    1.349V
279ps     1.068V     657.7mV    1.287V
504ps     1.071V     657.5mV    1.004V
702ps     1.02V      657.6mV    655.4mV
972ps     823.5mV    660.1mV    237.4mV
1.296ns   466.9mV    660.1mV    18.1mV
1.665ns   177.3mV    618.8mV    1.507mV
2.178ns   11.69mV    444.6mV    162.8uV
3.357ns   332.8uV    71.16mV    3.078uV
4.851ns   46.48uV    1.638mV    405.8nV
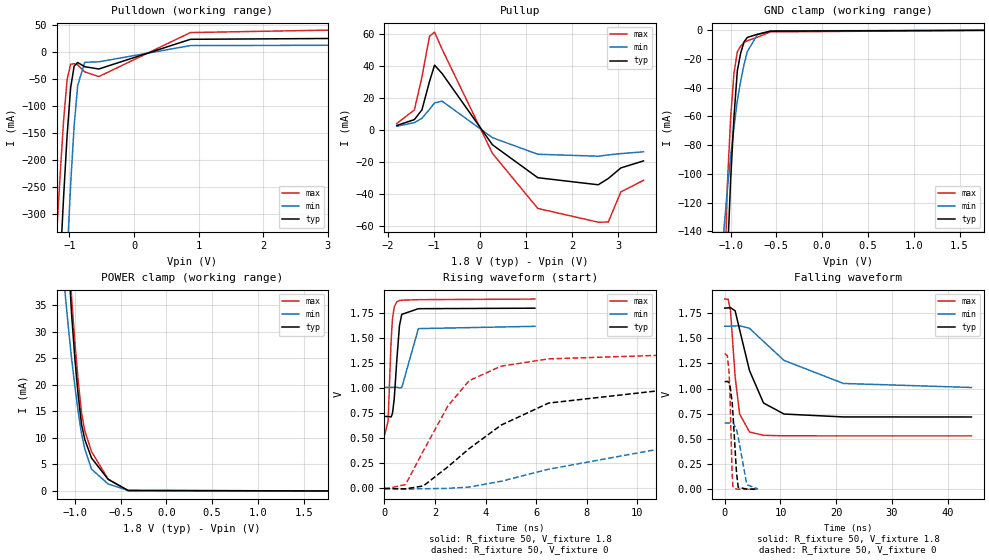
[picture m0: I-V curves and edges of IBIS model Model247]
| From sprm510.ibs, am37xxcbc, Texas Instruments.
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| Model based on original model for BQ18OMAPSMART1HYFBPB_SSBHV
|   Sub model PB_VS00L01_PUPD0_1P8
[model]   Model247
|[Input Load]   PI
|[Output Drive] SC00LB01
|Voltage   1.8V
|Mode   I/O
Model_type   I/O
Polarity   Non-Inverting
Enable   Active-Low
Vinl =  0.63
Vinh =  1.17
Cref =  15pF
Rref =  100.0000M
Vref =  0V
Vmeas =  0.9
C_comp   1.429432p   1.270657p   1.602015p
[Model Spec]
Vinl   0.63   0.567   0.6615
Vinh   1.17   1.053   1.2285
[Temperature Range]   25   125   -40
[Voltage Range]   1.8   1.62   1.89
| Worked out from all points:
|   slope of the pulldown table from 0 to 0.27 V, typ, clamps not added: 24.3 ohm
|   slope of the pullup table from 0 to 0.27 V, typ, clamps not added: 29.7 ohm
|   GND clamp passes 1 mA (typ) near -0.60 V on its own axis
|   POWER clamp passes 1 mA (typ) near -0.56 V on its own axis
|   rising waveform, R_fixture 50, V_fixture 1.8: 20-80 % time 177ps typ, 309ps min, 124ps max; typ from 0.718 V to 1.8 V
|   rising waveform, R_fixture 50, V_fixture 0: 20-80 % time 4.02ns typ, 9.13ns min, 2.03ns max; typ from 0 V to 1.07 V
|   falling waveform, R_fixture 50, V_fixture 1.8: 20-80 % time 3.37ns typ, 8.79ns min, 1.25ns max; typ from 1.8 V to 0.718 V
|   falling waveform, R_fixture 50, V_fixture 0: 20-80 % time 702ps typ, 1.17ns min, 407ps max; typ from 1.07 V to 0 V
[POWER_clamp]
-1.8V     362.5mA    191.4mA    412.8mA
-1.109V   56.69mA    37.71mA    60.38mA
-1.073V   44.6mA     31.22mA    47.8mA
-1.036V   33.44mA    25.04mA    36.59mA
-1V       24.98mA    19.72mA    28.06mA
-963.6mV  18.03mA    14.96mA    20.78mA
-927.3mV  12.59mA    10.77mA    14.74mA
-890.9mV  9.653mA    7.899mA    11.31mA
-818.2mV  6.214mA    4.114mA    7.414mA
-636.4mV  2.183mA    1.307mA    2.238mA
-418.2mV  83.85uA    105.2uA    35.14uA
1.764V    -1.228nA   -79.12nA   -1.453nA
[Pulldown]
-1.8V     -1.718A    -2.61A     -1.406A
-1.2V     -527.4mA   -844.5mA   -339.9mA
-1.145V   -396mA     -683.1mA   -229.1mA
-1.091V   -269mA     -526.7mA   -127.5mA
-1.036V   -153.6mA   -378.9mA   -51.17mA
-981.8mV  -66.34mA   -245.6mA   -22.67mA
-927.3mV  -26mA      -136.2mA   -21.54mA
-872.7mV  -19.34mA   -61.98mA   -23.69mA
-763.6mV  -27.2mA    -19.05mA   -36.72mA
-545.5mV  -31.39mA   -18.17mA   -45.46mA
872.7mV   23.46mA    11.88mA    35.92mA
3.545V    25.34mA    12.51mA    41.58mA
[Pullup]
-1.8V     2.903mA    2.423mA    4.112mA
-1.418V   6.595mA    4.711mA    12.64mA
-1.255V   12.69mA    7.42mA     33.23mA
-1.091V   30.4mA     13mA       58.69mA
-981.8mV  40.63mA    17.02mA    61.3mA
-818.2mV  35.38mA    18.12mA    50.59mA
272.7mV   -9.18mA    -4.728mA   -14.55mA
1.255V    -29.75mA   -15.09mA   -48.97mA
2.564V    -34.17mA   -16.31mA   -57.57mA
2.782V    -30.25mA   -15.5mA    -57.48mA
3.055V    -23.63mA   -14.68mA   -38.61mA
3.545V    -19.25mA   -13.56mA   -31.41mA
[GND_clamp]
-1.8V     -2.82A     -1.192A    -3.165A
-1.073V   -235.7mA   -138.4mA   -192.1mA
-1.036V   -159.5mA   -110.8mA   -107.5mA
-1V       -103.8mA   -87.85mA   -60.67mA
-963.6mV  -60mA      -67.28mA   -29.8mA
-927.3mV  -28.21mA   -49.08mA   -14.9mA
-890.9mV  -15.9mA    -35.48mA   -10.99mA
-854.5mV  -8.138mA   -24.07mA   -8.449mA
-818.2mV  -4.924mA   -14.85mA   -7.266mA
-709.1mV  -2.784mA   -3.064mA   -4.883mA
-563.6mV  -570.2uA   -404.5uA   -1.092mA
1.764V    -11.02pA   583.5nA    3.035nA
[Ramp]
dV/dt_f  0.6525928/3.379632n   0.3689841/8.866149n   0.8189183/1.245126n
dV/dt_r  0.6504723/4.031658n   0.400163/9.20936n   0.8226492/2.040681n
R_load = 50
[Rising Waveform]
R_fixture = 50
V_fixture = 1.8
V_fixture_min = 1.62
V_fixture_max = 1.89
0s        717.7mV    1.009V     531.7mV
144ps     718.8mV    1.009V     670mV
261ps     713.2mV    1.009V     1.459V
315ps     745.6mV    1.009V     1.689V
387ps     893.4mV    1.01V      1.812V
486ps     1.27V      1.011V     1.862V
594ps     1.625V     1.003V     1.876V
684ps     1.737V     1.006V     1.879V
1.341ns   1.794V     1.595V     1.884V
5.949ns   1.799V     1.618V     1.89V
[Rising Waveform]
R_fixture = 50
V_fixture = 0
V_fixture_min = 0
V_fixture_max = 0
0s        -177.1uV   112.2uV    -7.096mV
837ps     -3.925mV   -5.229mV   39.99mV
1.539ns   25.41mV    -3.423mV   375.2mV
2.511ns   216.6mV    990.5uV    823.6mV
3.348ns   397.5mV    13.85mV    1.076V
4.608ns   631.6mV    71.36mV    1.22V
6.489ns   852.1mV    191.9mV    1.293V
12.64ns   1.026V     475.5mV    1.343V
20.2ns    1.06V      595.5mV    1.348V
58.76ns   1.067V     655.8mV    1.349V
[Falling Waveform]
R_fixture = 50
V_fixture = 1.8
V_fixture_min = 1.62
V_fixture_max = 1.89
0s        1.8V       1.62V      1.89V
621ps     1.802V     1.62V      1.888V
1.035ns   1.805V     1.62V      1.779V
1.872ns   1.773V     1.623V     1.117V
2.673ns   1.586V     1.624V     748.2mV
4.446ns   1.179V     1.599V     568.5mV
6.957ns   856.7mV    1.469V     535.6mV
10.64ns   746.9mV    1.28V      530.2mV
21.28ns   718.2mV    1.051V     529.8mV
44.23ns   717.6mV    1.011V     529.8mV
[Falling Waveform]
R_fixture = 50
V_fixture = 0
V_fixture_min = 0
V_fixture_max = 0
0s        1.068V     657.3mV    1.349V
468ps     1.072V     657.4mV    1.327V
783ps     1.059V     657.8mV    1.165V
936ps     1.032V     659.9mV    953.5mV
1.332ns   868.9mV    666.9mV    152.5mV
1.485ns   747.1mV    663.8mV    18.05mV
2.115ns   166.2mV    592.7mV    839.5uV
2.421ns   19.76mV    518.3mV    415.5uV
3.96ns    504.4uV    44.38mV    96.7uV
5.967ns   180.4uV    1.636mV    28.56uV
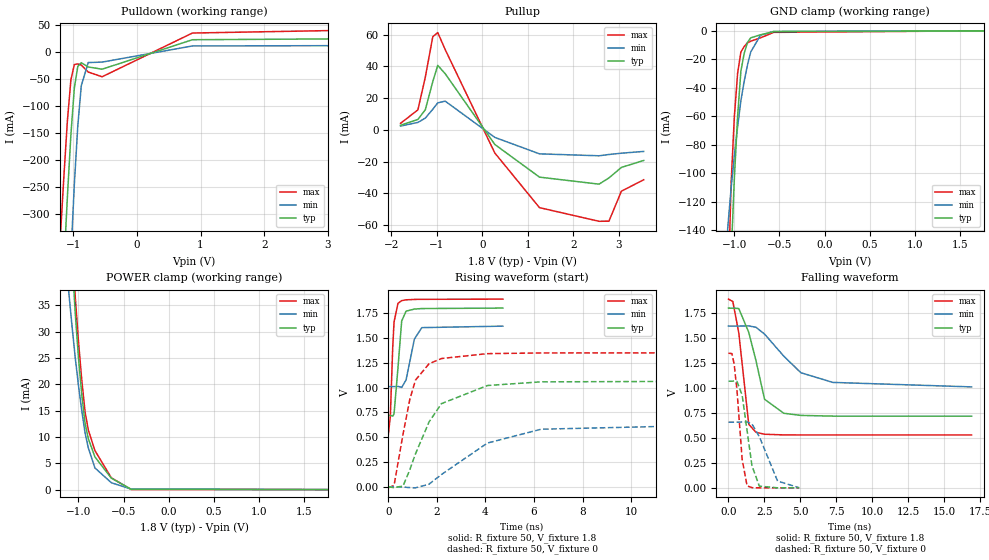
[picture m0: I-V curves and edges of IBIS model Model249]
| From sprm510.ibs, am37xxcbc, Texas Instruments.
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| Model based on original model for BQ18OMAPSMART1HYFBPB_SSBHV
|   Sub model PB_VS10L11_PUPD0_1P8
[model]   Model249
|[Input Load]   PI
|[Output Drive] SC10LB11
|Voltage   1.8V
|Mode   I/O
Model_type   I/O
Polarity   Non-Inverting
Enable   Active-Low
Vinl =  0.63
Vinh =  1.17
Cref =  15pF
Rref =  100.0000M
Vref =  0V
Vmeas =  0.9
C_comp   1.429432p   1.270657p   1.602015p
[Model Spec]
Vinl   0.63   0.567   0.6615
Vinh   1.17   1.053   1.2285
[Temperature Range]   25   125   -40
[Voltage Range]   1.8   1.62   1.89
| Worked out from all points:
|   slope of the pulldown table from 0 to 0.27 V, typ, clamps not added: 24.3 ohm
|   slope of the pullup table from 0 to 0.27 V, typ, clamps not added: 29.7 ohm
|   GND clamp passes 1 mA (typ) near -0.60 V on its own axis
|   POWER clamp passes 1 mA (typ) near -0.56 V on its own axis
|   rising waveform, R_fixture 50, V_fixture 1.8: 20-80 % time 177ps typ, 305ps min, 125ps max; typ from 0.717 V to 1.8 V
|   rising waveform, R_fixture 50, V_fixture 0: 20-80 % time 1.32ns typ, 2.85ns min, 702ps max; typ from 0 V to 1.07 V
|   falling waveform, R_fixture 50, V_fixture 1.8: 20-80 % time 1.03ns typ, 2.54ns min, 607ps max; typ from 1.8 V to 0.718 V
|   falling waveform, R_fixture 50, V_fixture 0: 20-80 % time 603ps typ, 1.01ns min, 438ps max; typ from 1.07 V to 0 V
[POWER_clamp]
-1.8V     362.5mA    191.4mA    412.8mA
-1.109V   56.69mA    37.71mA    60.38mA
-1.073V   44.6mA     31.22mA    47.8mA
-1.036V   33.44mA    25.04mA    36.59mA
-1V       24.98mA    19.72mA    28.06mA
-963.6mV  18.03mA    14.96mA    20.78mA
-927.3mV  12.59mA    10.77mA    14.74mA
-890.9mV  9.653mA    7.899mA    11.31mA
-818.2mV  6.214mA    4.114mA    7.414mA
-636.4mV  2.183mA    1.307mA    2.238mA
-418.2mV  83.85uA    105.2uA    35.14uA
1.764V    -1.228nA   -79.12nA   -1.453nA
[Pulldown]
-1.8V     -1.718A    -2.61A     -1.406A
-1.2V     -527.4mA   -844.5mA   -339.9mA
-1.145V   -396mA     -683.1mA   -229.1mA
-1.091V   -269mA     -526.7mA   -127.5mA
-1.036V   -153.6mA   -378.9mA   -51.17mA
-981.8mV  -66.34mA   -245.6mA   -22.67mA
-927.3mV  -26mA      -136.2mA   -21.54mA
-872.7mV  -19.34mA   -61.98mA   -23.69mA
-763.6mV  -27.2mA    -19.05mA   -36.72mA
-545.5mV  -31.39mA   -18.17mA   -45.46mA
872.7mV   23.46mA    11.88mA    35.92mA
3.545V    25.34mA    12.51mA    41.58mA
[Pullup]
-1.8V     2.903mA    2.423mA    4.112mA
-1.418V   6.595mA    4.711mA    12.64mA
-1.255V   12.69mA    7.42mA     33.23mA
-1.091V   30.4mA     13mA       58.69mA
-981.8mV  40.63mA    17.02mA    61.3mA
-818.2mV  35.38mA    18.12mA    50.59mA
272.7mV   -9.18mA    -4.728mA   -14.55mA
1.255V    -29.75mA   -15.09mA   -48.97mA
2.564V    -34.17mA   -16.31mA   -57.57mA
2.782V    -30.25mA   -15.5mA    -57.48mA
3.055V    -23.63mA   -14.68mA   -38.61mA
3.545V    -19.25mA   -13.56mA   -31.41mA
[GND_clamp]
-1.8V     -2.82A     -1.192A    -3.165A
-1.073V   -235.7mA   -138.4mA   -192.1mA
-1.036V   -159.5mA   -110.8mA   -107.5mA
-1V       -103.8mA   -87.85mA   -60.67mA
-963.6mV  -60mA      -67.28mA   -29.8mA
-927.3mV  -28.21mA   -49.08mA   -14.9mA
-890.9mV  -15.9mA    -35.48mA   -10.99mA
-854.5mV  -8.138mA   -24.07mA   -8.449mA
-818.2mV  -4.924mA   -14.85mA   -7.266mA
-709.1mV  -2.784mA   -3.064mA   -4.883mA
-563.6mV  -570.2uA   -404.5uA   -1.092mA
1.764V    -11.02pA   583.5nA    3.035nA
[Ramp]
dV/dt_f  0.6513567/1.033883n   0.3678301/2.560061n   0.8182554/0.6091534n
dV/dt_r  0.6511008/1.318478n   0.4008374/2.875736n   0.8231613/0.7035991n
R_load = 50
[Rising Waveform]
R_fixture = 50
V_fixture = 1.8
V_fixture_min = 1.62
V_fixture_max = 1.89
0s        717.1mV    1.009V     528.4mV
81ps      719mV      1.009V     709.2mV
180ps     712.1mV    1.009V     1.407V
234ps     733.7mV    1.009V     1.659V
396ps     1.2V       1.011V     1.848V
549ps     1.67V      1.001V     1.875V
729ps     1.769V     1.076V     1.883V
1.071ns   1.79V      1.487V     1.887V
1.377ns   1.795V     1.603V     1.888V
4.716ns   1.8V       1.618V     1.89V
[Rising Waveform]
R_fixture = 50
V_fixture = 0
V_fixture_min = 0
V_fixture_max = 0
0s        -245.4uV   110uV      -10.32mV
234ps     -8.529mV   -416.9uV   14.01mV
603ps     7.862mV    -2.317mV   528mV
882ps     170.8mV    -8.155mV   879.3mV
1.116ns   331mV      -10.65mV   1.074V
1.674ns   652.6mV    26.22mV    1.239V
2.187ns   837.5mV    123.9mV    1.292V
4.077ns   1.02V      440.4mV    1.341V
6.291ns   1.057V     580mV      1.348V
19.75ns   1.067V     655.8mV    1.349V
[Falling Waveform]
R_fixture = 50
V_fixture = 1.8
V_fixture_min = 1.62
V_fixture_max = 1.89
0s        1.8V       1.62V      1.89V
306ps     1.8V       1.62V      1.866V
720ps     1.796V     1.62V      1.552V
1.413ns   1.557V     1.622V     636.8mV
1.917ns   1.274V     1.608V     556.4mV
2.511ns   887.7mV    1.54V      537mV
3.852ns   747mV      1.319V     530.2mV
5.04ns    725.6mV    1.153V     529.8mV
7.263ns   718.4mV    1.056V     529.8mV
16.92ns   717.6mV    1.011V     529.8mV
[Falling Waveform]
R_fixture = 50
V_fixture = 0
V_fixture_min = 0
V_fixture_max = 0
0s        1.068V     657.3mV    1.349V
243ps     1.068V     657.7mV    1.344V
396ps     1.071V     657.6mV    1.241V
594ps     1.066V     657.4mV    978.8mV
954ps     928mV      659.5mV    284.5mV
1.296ns   574.8mV    660.5mV    20.67mV
1.638ns   220.6mV    639.3mV    1.828mV
2.151ns   17.17mV    512.6mV    216uV
3.42ns    344.7uV    67.71mV    5.12uV
4.923ns   55.99uV    1.643mV    559.2nV
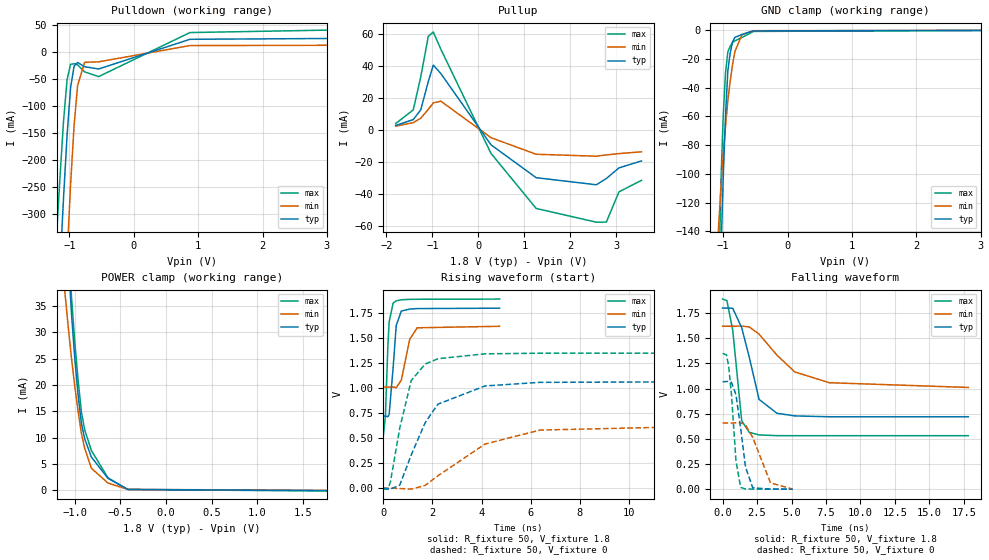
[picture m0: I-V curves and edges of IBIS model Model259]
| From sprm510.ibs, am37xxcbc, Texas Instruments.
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| Model based on original model for BQ18OMAPSMART1HYFBPB_SSBHV
|   Sub model FBPB_VS10L01_PU1_1P8
[model]   Model259
|[Input Load]   PU
|[Output Drive] SC10LB01
|Voltage   1.8V
|Mode   I/O
Model_type   I/O
Polarity   Non-Inverting
Enable   Active-Low
Vinl =  0.63
Vinh =  1.17
Cref =  15pF
Rref =  100.0000M
Vref =  0V
Vmeas =  0.9
C_comp   1.429432p   1.270657p   1.602015p
[Model Spec]
Vinl   0.63   0.567   0.6615
Vinh   1.17   1.053   1.2285
[Temperature Range]   25   125   -40
[Voltage Range]   1.8   1.62   1.89
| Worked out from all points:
|   slope of the pulldown table from 0 to 0.27 V, typ, clamps not added: 24.3 ohm
|   slope of the pullup table from 0 to 0.27 V, typ, clamps not added: 29.7 ohm
|   GND clamp passes 1 mA (typ) near -0.60 V on its own axis
|   POWER clamp passes 1 mA (typ) near -0.56 V on its own axis
|   rising waveform, R_fixture 50, V_fixture 1.8: 20-80 % time 177ps typ, 307ps min, 125ps max; typ from 0.72 V to 1.8 V
|   rising waveform, R_fixture 50, V_fixture 0: 20-80 % time 1.33ns typ, 2.89ns min, 710ps max; typ from 0.001 V to 1.07 V
|   falling waveform, R_fixture 50, V_fixture 1.8: 20-80 % time 1.06ns typ, 2.76ns min, 586ps max; typ from 1.8 V to 0.72 V
|   falling waveform, R_fixture 50, V_fixture 0: 20-80 % time 591ps typ, 1ns min, 421ps max; typ from 1.07 V to 0.001 V
[POWER_clamp]
-1.8V     362.5mA    191.4mA    412.8mA
-1.109V   56.76mA    37.74mA    60.51mA
-1.073V   44.67mA    31.25mA    47.93mA
-1.036V   33.52mA    25.07mA    36.72mA
-1V       25.06mA    19.75mA    28.2mA
-963.6mV  18.11mA    14.99mA    20.91mA
-927.3mV  12.67mA    10.8mA     14.87mA
-890.9mV  9.734mA    7.935mA    11.44mA
-818.2mV  6.293mA    4.153mA    7.536mA
-636.4mV  2.249mA    1.342mA    2.34mA
-418.2mV  128.7uA    129.3uA    104.4uA
1.764V    -96.73uA   -46.48uA   -163.5uA
[Pulldown]
-1.8V     -1.718A    -2.61A     -1.406A
-1.2V     -527.4mA   -844.5mA   -339.9mA
-1.145V   -396mA     -683.1mA   -229.1mA
-1.091V   -269mA     -526.7mA   -127.5mA
-1.036V   -153.6mA   -378.9mA   -51.17mA
-981.8mV  -66.33mA   -245.6mA   -22.67mA
-927.3mV  -26mA      -136.2mA   -21.54mA
-872.7mV  -19.34mA   -61.98mA   -23.69mA
-763.6mV  -27.2mA    -19.05mA   -36.72mA
-545.5mV  -31.39mA   -18.17mA   -45.46mA
872.7mV   23.46mA    11.88mA    35.92mA
3.545V    25.34mA    12.51mA    41.58mA
[Pullup]
-1.8V     2.903mA    2.423mA    4.112mA
-1.418V   6.595mA    4.711mA    12.64mA
-1.255V   12.69mA    7.42mA     33.24mA
-1.091V   30.4mA     13mA       58.69mA
-981.8mV  40.63mA    17.02mA    61.3mA
-818.2mV  35.38mA    18.12mA    50.59mA
272.7mV   -9.179mA   -4.728mA   -14.55mA
1.255V    -29.75mA   -15.09mA   -48.97mA
2.564V    -34.17mA   -16.31mA   -57.57mA
2.782V    -30.25mA   -15.5mA    -57.49mA
3.055V    -23.63mA   -14.68mA   -38.61mA
3.545V    -19.25mA   -13.56mA   -31.41mA
[GND_clamp]
-1.8V     -2.82A     -1.192A    -3.165A
-1.073V   -235.8mA   -138.4mA   -192.1mA
-1.036V   -159.6mA   -110.8mA   -107.6mA
-1V       -103.8mA   -87.86mA   -60.73mA
-963.6mV  -60.04mA   -67.29mA   -29.86mA
-927.3mV  -28.26mA   -49.09mA   -14.98mA
-890.9mV  -15.95mA   -35.49mA   -11.09mA
-854.5mV  -8.198mA   -24.09mA   -8.559mA
-818.2mV  -4.99mA    -14.87mA   -7.387mA
-709.1mV  -2.858mA   -3.093mA   -5.012mA
-527.3mV  -395.6uA   -260.4uA   -751.2uA
3.6V      0A         0A         0A
[Ramp]
dV/dt_f  0.6499524/1.06465n   0.3671274/2.783203n   0.816553/0.5879872n
dV/dt_r  0.6500316/1.333821n   0.4005427/2.914608n   0.8209697/0.7111993n
R_load = 50
[Rising Waveform]
R_fixture = 50
V_fixture = 1.8
V_fixture_min = 1.62
V_fixture_max = 1.89
0s        719.5mV    1.011V     531.6mV
81ps      721.4mV    1.011V     713.2mV
180ps     714.4mV    1.01V      1.409V
234ps     736.9mV    1.01V      1.662V
396ps     1.203V     1.012V     1.85V
522ps     1.625V     1.004V     1.872V
729ps     1.77V      1.079V     1.883V
1.071ns   1.79V      1.487V     1.887V
1.377ns   1.795V     1.603V     1.888V
4.734ns   1.799V     1.618V     1.89V
[Rising Waveform]
R_fixture = 50
V_fixture = 0
V_fixture_min = 0
V_fixture_max = 0
0s        1.138mV    1.075mV    -8.175mV
189ps     -3.791mV   620.4uV    -9.209mV
288ps     -8.865mV   628.1uV    65.91mV
666ps     31.55mV    -3.01mV    600.6mV
1.134ns   332.3mV    -8.62mV    1.076V
1.701ns   655mV      27.7mV     1.241V
2.223ns   840.2mV    124.8mV    1.294V
4.14ns    1.022V     441.5mV    1.343V
6.381ns   1.058V     581.1mV    1.349V
20.01ns   1.069V     657.1mV    1.35V
[Falling Waveform]
R_fixture = 50
V_fixture = 1.8
V_fixture_min = 1.62
V_fixture_max = 1.89
0s        1.8V       1.62V      1.89V
315ps     1.801V     1.62V      1.874V
738ps     1.798V     1.62V      1.58V
1.386ns   1.606V     1.622V     681.9mV
1.935ns   1.313V     1.613V     566.2mV
2.646ns   893.6mV    1.542V     540.2mV
3.942ns   755.5mV    1.333V     533.2mV
5.238ns   729.2mV    1.166V     532.6mV
7.74ns    720.7mV    1.059V     532.6mV
17.82ns   720mV      1.012V     532.6mV
[Falling Waveform]
R_fixture = 50
V_fixture = 0
V_fixture_min = 0
V_fixture_max = 0
0s        1.069V     658.6mV    1.35V
288ps     1.07V      659mV      1.336V
450ps     1.073V     658.8mV    1.214V
648ps     1.062V     658.8mV    937.7mV
972ps     940.5mV    661.2mV    281.1mV
1.314ns   601.3mV    661.7mV    18.73mV
1.665ns   221mV      639mV      3.559mV
2.187ns   15.21mV    515.6mV    2.005mV
3.474ns   1.763mV    63.47mV    1.78mV
5.076ns   1.452mV    2.6mV      1.773mV
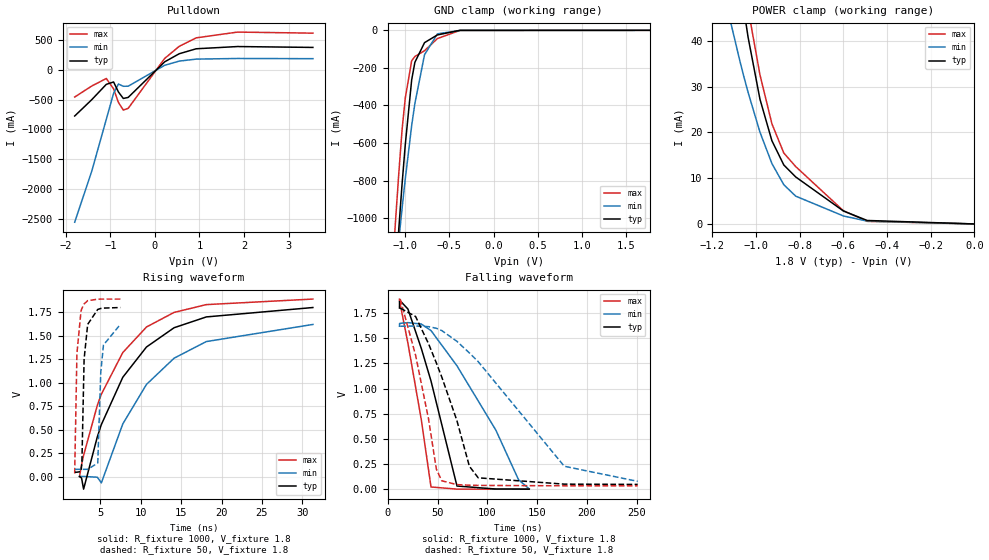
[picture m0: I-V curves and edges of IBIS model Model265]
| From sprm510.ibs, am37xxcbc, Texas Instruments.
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| Model based on original model for BQOMAPI2CHYFBPBRESNOPM_SSBHV
|   Sub model BQOMAPI2CHYRES_SLV_POFF_00_1P8
[model]   Model265
|[Input Load]   PI
|[Output Drive] LB00
|Voltage   1.8V
|Mode   I/O_OPEN_DRAIN
Model_type   I/O_open_drain
Polarity   Non-Inverting
Enable   Active-Low
Vinl =  0.567
Vinh =  1.323
Cref =  400.0000PF
Rref =  1000.0000
Vref =  1.8V
Vmeas =  0.9
C_comp   3.856143p   3.721565p   3.857354p
[Model Spec]
Vinl   0.567   0.567   0.567
Vinh   1.323   1.323   1.323
[Temperature Range]   25   125   -40
[Voltage Range]   1.8   1.62   1.89
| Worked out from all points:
|   slope of the pulldown table from 0 to 0.27 V, typ, clamps not added: 1.71 ohm
|   GND clamp passes 1 mA (typ) near -0.44 V on its own axis
|   POWER clamp passes 1 mA (typ) near -0.51 V on its own axis
|   rising waveform, R_fixture 1000, V_fixture 1.8: 20-80 % time 7.1ns typ, 8.09ns min, 6.29ns max; typ from 0.002 V to 1.8 V
|   rising waveform, R_fixture 50, V_fixture 1.8: 20-80 % time 373ps typ, 410ps min, 341ps max; typ from 0.049 V to 1.8 V
|   falling waveform, R_fixture 1000, V_fixture 1.8: 20-80 % time 29.3ns typ, 56.6ns min, 19.1ns max; typ from 1.8 V to 0.002 V
|   falling waveform, R_fixture 50, V_fixture 1.8: 20-80 % time 36.2ns typ, 77.2ns min, 22ns max; typ from 1.8 V to 0.049 V
[POWER_clamp]
-1.8V     401.1mA    209.4mA    454.2mA
-1.145V   79.39mA    49.82mA    86.39mA
-1.073V   52.49mA    35.39mA    58.76mA
-1.055V   46.58mA    32.04mA    52.82mA
-1.036V   40.67mA    28.68mA    46.87mA
-981.8mV  27.2mA     20.01mA    32.52mA
-927.3mV  18.17mA    13.19mA    21.87mA
-872.7mV  12.87mA    8.554mA    15.48mA
-818.2mV  10.26mA    6.071mA    12.52mA
-600mV    2.834mA    1.747mA    2.888mA
-490.9mV  760.8uA    616.2uA    563.4uA
0V        4.894nA    26.6nA     13.41nA
[Pulldown]
-1.8V     -777mA     -2.558A    -458.4mA
-1.418V   -503.6mA   -1.705A    -274.2mA
-1.091V   -246mA     -833.2mA   -147.3mA
-927.3mV  -205.8mA   -396mA     -321.1mA
-818.2mV  -374mA     -240.2mA   -549.2mA
-709.1mV  -482.4mA   -277.9mA   -676.8mA
-600mV    -465mA     -277.2mA   -649mA
218.2mV   131.5mA    73.81mA    188.3mA
545.5mV   267.7mA    144.1mA    391.9mA
927.3mV   351.1mA    177.8mA    534.6mA
1.855V    388.5mA    188.1mA    631mA
3.545V    373.8mA    185.1mA    613.1mA
[GND_clamp]
-1.8V     -6.905A    -5.48A     -6.849A
-1.145V   -1.563A    -1.472A    -1.273A
-1.109V   -1.305A    -1.292A    -1.009A
-1.073V   -1.058A    -1.118A    -761.8mA
-1.036V   -819.4mA   -948.6mA   -530.3mA
-1V       -610.5mA   -793.2mA   -361.6mA
-927.3mV  -263.9mA   -507.2mA   -161.9mA
-890.9mV  -170.2mA   -389mA     -139.4mA
-781.8mV  -65.52mA   -129.8mA   -108.5mA
-636.4mV  -24.47mA   -18.9mA    -43.94mA
-381.8mV  -239.7uA   -254uA     -441.8uA
1.764V    2.8nA      2.224uA    11.77nA
[Ramp]
dV/dt_f  1.1008092/31.084297n 0.97960712/59.93592n   1.1666008/20.287012n
dV/dt_r 0.13495278/0.10726492n 0.11653477/0.21280077n 0.14012808/64.8552p
R_load = 528.0
[Rising Waveform]
R_fixture = 1000
V_fixture = 1.8
V_fixture_min = 1.62
V_fixture_max = 1.89
2.412ns   2.428mV    3.93mV     1.741mV
2.662ns   -12.79mV   3.929mV    127.8mV
2.913ns   -131.7mV   3.929mV    227.3mV
4.623ns   426.9mV    -4.804mV   761.9mV
5.113ns   554.9mV    -64.78mV   877.8mV
7.767ns   1.058V     561.6mV    1.321V
10.7ns    1.38V      982.1mV    1.593V
14.12ns   1.585V     1.261V     1.748V
18.11ns   1.7V       1.438V     1.831V
31.31ns   1.8V       1.62V      1.89V
[Rising Waveform]
R_fixture = 50
V_fixture = 1.8
V_fixture_min = 1.62
V_fixture_max = 1.89
1.812ns   48.93mV    79.48mV    35.04mV
2.089ns   48.93mV    79.48mV    1.311V
2.591ns   55.44mV    79.48mV    1.759V
2.704ns   145.1mV    79.48mV    1.79V
2.979ns   1.253V     79.48mV    1.838V
3.421ns   1.621V     79.48mV    1.873V
4.67ns    1.78V      146mV      1.889V
5.044ns   1.79V      1.113V     1.89V
5.373ns   1.794V     1.401V     1.89V
7.463ns   1.8V       1.62V      1.89V
[Falling Waveform]
R_fixture = 1000
V_fixture = 1.8
V_fixture_min = 1.62
V_fixture_max = 1.89
11.75ns   1.8V       1.62V      1.89V
11.85ns   1.868V     1.647V     1.866V
12.91ns   1.868V     1.649V     1.817V
20.24ns   1.791V     1.656V     1.451V
33.63ns   1.401V     1.642V     694.4mV
43.42ns   1.076V     1.577V     23.44mV
69.5ns    32.92mV    1.227V     2.218mV
108.5ns   3.225mV    589.2mV    1.825mV
131.3ns   2.796mV    96.25mV    1.777mV
142.1ns   2.428mV    3.93mV     1.741mV
[Falling Waveform]
R_fixture = 50
V_fixture = 1.8
V_fixture_min = 1.62
V_fixture_max = 1.89
12.5ns    1.8V       1.62V      1.89V
27.91ns   1.717V     1.622V     1.333V
40.91ns   1.447V     1.616V     700.5mV
48.77ns   1.256V     1.6V       201.6mV
54.21ns   1.116V     1.577V     84.94mV
69.33ns   686.2mV    1.471V     47.05mV
81.97ns   229.1mV    1.355V     41mV
90.84ns   114.4mV    1.268V     38.98mV
177.3ns   51.59mV    229.2mV    35.2mV
251ns     48.93mV    79.48mV    35.04mV
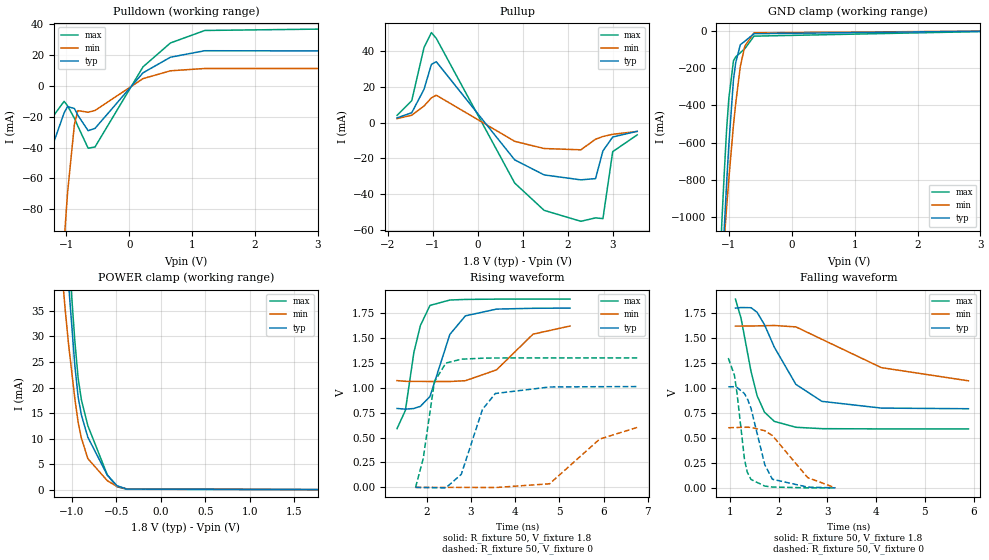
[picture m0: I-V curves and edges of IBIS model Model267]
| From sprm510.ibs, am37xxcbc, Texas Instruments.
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| Model based on original model for BQOMAPI2CHYFBPBRESNOPM_SSBHV
|   Sub model BQOMAPI2CHYRES_NORM_00_1P8
[model]   Model267
|[Input Load]   PU
|[Output Drive] LB00
|Voltage   1.8V
|Mode   I/O
Model_type   I/O
Polarity   Non-Inverting
Enable   Active-Low
Vinl =  0.567
Vinh =  1.323
Cref =  15.0000PF
Rref =  150.0000
Vref =  0V
Vmeas =  0.9
C_comp   3.856143p   3.721565p   3.857354p
[Model Spec]
Vinl   0.567   0.567   0.567
Vinh   1.323   1.323   1.323
[Temperature Range]   25   125   -40
[Voltage Range]   1.8   1.62   1.89
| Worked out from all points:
|   slope of the pulldown table from 0 to 0.27 V, typ, clamps not added: 27.3 ohm
|   slope of the pullup table from 0 to 0.27 V, typ, clamps not added: 33.5 ohm
|   GND clamp passes 1 mA (typ) near -0.44 V on its own axis
|   POWER clamp passes 1 mA (typ) near -0.51 V on its own axis
|   rising waveform, R_fixture 50, V_fixture 1.8: 20-80 % time 439ps typ, 726ps min, 308ps max; typ from 0.792 V to 1.8 V
|   rising waveform, R_fixture 50, V_fixture 0: 20-80 % time 433ps typ, 810ps min, 255ps max; typ from 0 V to 1.01 V
|   falling waveform, R_fixture 50, V_fixture 1.8: 20-80 % time 693ps typ, 1.48ns min, 353ps max; typ from 1.8 V to 0.792 V
|   falling waveform, R_fixture 50, V_fixture 0: 20-80 % time 310ps typ, 591ps min, 186ps max; typ from 1.01 V to 0 V
[POWER_clamp]
-1.8V     401.1mA    209.4mA    454.2mA
-1.145V   79.39mA    49.82mA    86.39mA
-1.073V   52.49mA    35.39mA    58.76mA
-1.036V   40.67mA    28.68mA    46.87mA
-963.6mV  24.19mA    17.73mA    28.97mA
-927.3mV  18.17mA    13.19mA    21.87mA
-890.9mV  14.63mA    10.1mA     17.61mA
-818.2mV  10.26mA    6.071mA    12.52mA
-600mV    2.834mA    1.747mA    2.888mA
-490.9mV  760.8uA    616.2uA    563.4uA
-381.8mV  112.8uA    147.2uA    57.34uA
1.764V    -11.66nA   -1.927uA   -18.08nA
[Pulldown]
-1.8V     -103.1mA   -485.1mA   -53.66mA
-1.636V   -86.71mA   -425.1mA   -43.29mA
-1.036V   -17.55mA   -100.6mA   -10.12mA
-981.8mV  -13.55mA   -69.37mA   -13.05mA
-872.7mV  -14.77mA   -25.04mA   -21.09mA
-818.2mV  -19.14mA   -16.16mA   -26.14mA
-654.5mV  -29.1mA    -17.19mA   -40.44mA
-545.5mV  -27.65mA   -16.06mA   -39.66mA
218.2mV   8.291mA    4.55mA     12.15mA
654.5mV   18.38mA    9.592mA    27.6mA
1.2V      22.57mA    11.08mA    35.66mA
3.545V    22.43mA    11.1mA     36.8mA
[Pullup]
-1.8V     2.712mA    2.321mA    4.148mA
-1.473V   5.636mA    4.228mA    12.4mA
-1.2V     18.73mA    9.362mA    42.15mA
-1.036V   32.69mA    13.94mA    50.53mA
-927.3mV  34.21mA    15.45mA    47.3mA
818.2mV   -20.78mA   -10.39mA   -33.77mA
1.473V    -29.21mA   -14.43mA   -49.06mA
2.291V    -31.98mA   -15.15mA   -55.2mA
2.618V    -31.28mA   -9.229mA   -53.28mA
2.782V    -15.77mA   -7.688mA   -53.7mA
3V        -7.977mA   -6.448mA   -16.18mA
3.545V    -4.777mA   -4.853mA   -6.788mA
[GND_clamp]
-1.8V     -6.905A    -5.48A     -6.849A
-1.145V   -1.563A    -1.472A    -1.273A
-1.109V   -1.305A    -1.292A    -1.009A
-1.073V   -1.058A    -1.118A    -761.8mA
-1.036V   -819.4mA   -948.6mA   -530.3mA
-1V       -610.5mA   -793.2mA   -361.6mA
-927.3mV  -263.9mA   -507.2mA   -161.9mA
-890.9mV  -170.2mA   -389mA     -139.4mA
-818.2mV  -74.8mA    -191.7mA   -117.8mA
-745.5mV  -55.76mA   -81.74mA   -95.49mA
-600mV    -15.41mA   -10.81mA   -28.59mA
3.6V      0A         0A         0A
[Ramp]
dV/dt_f 0.73390615/0.64960797n  0.4494328/1.55011n   0.88415742/0.32823879n
dV/dt_r  0.7104491/0.43566303n 0.45594703/0.83359443n 0.86762689/0.25272322n
R_load = 70.0000
[Rising Waveform]
R_fixture = 50
V_fixture = 1.8
V_fixture_min = 1.62
V_fixture_max = 1.89
1.328ns   792.4mV    1.072V     590.3mV
1.517ns   785.1mV    1.065V     773.7mV
1.708ns   792.1mV    1.064V     1.354V
1.855ns   813.4mV    1.064V     1.624V
2.073ns   912.5mV    1.063V     1.827V
2.522ns   1.536V     1.063V     1.881V
2.873ns   1.722V     1.071V     1.887V
3.578ns   1.79V      1.18V      1.89V
4.402ns   1.798V     1.538V     1.89V
5.239ns   1.8V       1.62V      1.89V
[Rising Waveform]
R_fixture = 50
V_fixture = 0
V_fixture_min = 0
V_fixture_max = 0
1.747ns   198.6nV    3.394uV    310.6nV
1.92ns    -1.4mV     17.81uV    291mV
2.173ns   -3.029mV   6.775uV    1.061V
2.431ns   -4.663mV   -27.46uV   1.248V
2.78ns    131mV      -194.5uV   1.287V
3.26ns    783.3mV    -880.1uV   1.297V
3.552ns   942.8mV    -1.555mV   1.299V
4.778ns   1.008V     36.24mV    1.3V
5.911ns   1.011V     485.4mV    1.3V
6.759ns   1.012V     601.9mV    1.3V
[Falling Waveform]
R_fixture = 50
V_fixture = 1.8
V_fixture_min = 1.62
V_fixture_max = 1.89
1.112ns   1.8V       1.62V      1.89V
1.227ns   1.806V     1.62V      1.699V
1.432ns   1.804V     1.621V     1.166V
1.557ns   1.758V     1.622V     922mV
1.709ns   1.633V     1.624V     757.8mV
1.91ns    1.409V     1.626V     665.7mV
2.353ns   1.036V     1.612V     606.6mV
2.886ns   866.4mV    1.488V     592.8mV
4.107ns   798.8mV    1.204V     590.4mV
5.894ns   792.4mV    1.072V     590.3mV
[Falling Waveform]
R_fixture = 50
V_fixture = 0
V_fixture_min = 0
V_fixture_max = 0
965.3ps   1.012V     601.9mV    1.3V
1.093ns   1.013V     603.7mV    1.125V
1.147ns   1.005V     604.6mV    937.5mV
1.297ns   943.9mV    606.6mV    288mV
1.354ns   895.6mV    606.9mV    158.1mV
1.431ns   797.1mV    606mV      84.18mV
1.714ns   232.2mV    572.4mV    17.73mV
1.87ns    86.23mV    524mV      8.15mV
2.595ns   7.335mV    102.8mV    185.2uV
3.163ns   198.6nV    3.394uV    310.6nV
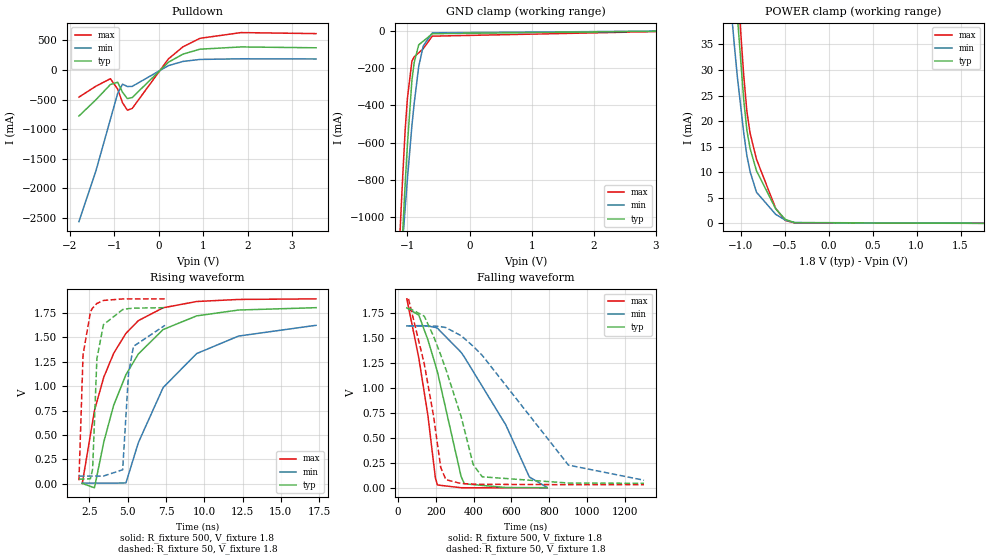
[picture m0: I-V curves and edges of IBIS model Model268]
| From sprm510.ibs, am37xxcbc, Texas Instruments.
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| Model based on original model for BQOMAPI2CHYFBPBRESNOPM_SSBHV
|   Sub model BQOMAPI2CHYRES_STD_PON_01_1P8
[model]   Model268
|[Input Load]   PU
|[Output Drive] LB01
|Voltage   1.8V
|Mode   I/O_OPEN_DRAIN
Model_type   I/O_open_drain
Polarity   Non-Inverting
Enable   Active-Low
Vinl =  0.567
Vinh =  1.323
Cref =  400.0000PF
Rref =  500.0000
Vref =  1.8V
Vmeas =  0.9
C_comp   3.856143p   3.721565p   3.857354p
[Model Spec]
Vinl   0.567   0.567   0.567
Vinh   1.323   1.323   1.323
[Temperature Range]   25   125   -40
[Voltage Range]   1.8   1.62   1.89
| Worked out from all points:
|   slope of the pulldown table from 0 to 0.27 V, typ, clamps not added: 1.71 ohm
|   GND clamp passes 1 mA (typ) near -0.44 V on its own axis
|   POWER clamp passes 1 mA (typ) near -0.51 V on its own axis
|   rising waveform, R_fixture 500, V_fixture 1.8: 20-80 % time 2.94ns typ, 3.67ns min, 2.39ns max; typ from 0.006 V to 1.8 V
|   rising waveform, R_fixture 50, V_fixture 1.8: 20-80 % time 360ps typ, 401ps min, 327ps max; typ from 0.05 V to 1.8 V
|   falling waveform, R_fixture 500, V_fixture 1.8: 20-80 % time 145ns typ, 289ns min, 91.6ns max; typ from 1.8 V to 0.006 V
|   falling waveform, R_fixture 50, V_fixture 1.8: 20-80 % time 173ns typ, 380ns min, 102ns max; typ from 1.8 V to 0.05 V
[POWER_clamp]
-1.8V     401.1mA    209.4mA    454.2mA
-1.145V   79.39mA    49.82mA    86.39mA
-1.073V   52.49mA    35.39mA    58.76mA
-1.036V   40.67mA    28.68mA    46.87mA
-963.6mV  24.19mA    17.73mA    28.97mA
-927.3mV  18.17mA    13.19mA    21.87mA
-890.9mV  14.63mA    10.1mA     17.61mA
-818.2mV  10.26mA    6.071mA    12.52mA
-600mV    2.834mA    1.747mA    2.888mA
-490.9mV  760.8uA    616.2uA    563.4uA
-381.8mV  112.8uA    147.2uA    57.34uA
1.764V    -11.66nA   -1.927uA   -18.08nA
[Pulldown]
-1.8V     -777mA     -2.558A    -458.4mA
-1.418V   -503.7mA   -1.705A    -274.3mA
-1.091V   -246.3mA   -833.3mA   -147.8mA
-927.3mV  -206.6mA   -396.2mA   -322.7mA
-818.2mV  -375.3mA   -240.6mA   -551.2mA
-709.1mV  -483.5mA   -278.4mA   -678.3mA
-600mV    -466mA     -277.7mA   -650.3mA
218.2mV   130.8mA    73.43mA    187.2mA
545.5mV   267.1mA    143.8mA    391mA
927.3mV   350.6mA    177.6mA    533.7mA
1.855V    388.5mA    188.2mA    630.7mA
3.545V    373.9mA    185.2mA    613.2mA
[GND_clamp]
-1.8V     -6.905A    -5.48A     -6.849A
-1.145V   -1.563A    -1.472A    -1.273A
-1.109V   -1.305A    -1.292A    -1.009A
-1.073V   -1.058A    -1.118A    -761.8mA
-1.036V   -819.4mA   -948.6mA   -530.3mA
-1V       -610.5mA   -793.2mA   -361.6mA
-927.3mV  -263.9mA   -507.2mA   -161.9mA
-890.9mV  -170.2mA   -389mA     -139.4mA
-818.2mV  -74.8mA    -191.7mA   -117.8mA
-745.5mV  -55.76mA   -81.74mA   -95.49mA
-600mV    -15.41mA   -10.81mA   -28.59mA
3.6V      0A         0A         0A
[Ramp]
dV/dt_f  1.0803752/0.14525707u 0.96885004/0.28886203u  1.1371511/92.105002n
dV/dt_r  0.3199246/3.7445379n 0.21247871/4.9012948n 0.40340075/2.9678839n
R_load = 528.00
[Rising Waveform]
R_fixture = 500
V_fixture = 1.8
V_fixture_min = 1.62
V_fixture_max = 1.89
2.029ns   6.005mV    8.936mV    4.644mV
2.827ns   -39.76mV   8.935mV    750.8mV
3.431ns   426.5mV    8.934mV    1.089V
4.08ns    803.6mV    8.789mV    1.334V
4.882ns   1.116V     10.28mV    1.538V
5.695ns   1.328V     422.9mV    1.668V
7.311ns   1.577V     984.2mV    1.799V
9.496ns   1.716V     1.331V     1.863V
12.23ns   1.776V     1.51V      1.884V
17.3ns    1.8V       1.62V      1.89V
[Rising Waveform]
R_fixture = 50
V_fixture = 1.8
V_fixture_min = 1.62
V_fixture_max = 1.89
1.811ns   50.09mV    80.58mV    36.22mV
2.081ns   50.09mV    80.58mV    1.319V
2.566ns   53.44mV    80.58mV    1.759V
2.706ns   151.3mV    80.58mV    1.797V
2.983ns   1.278V     80.58mV    1.843V
3.413ns   1.626V     80.58mV    1.874V
4.668ns   1.781V     145.3mV    1.889V
5.047ns   1.79V      1.121V     1.89V
5.372ns   1.795V     1.405V     1.89V
7.431ns   1.8V       1.62V      1.89V
[Falling Waveform]
R_fixture = 500
V_fixture = 1.8
V_fixture_min = 1.62
V_fixture_max = 1.89
46.91ns   1.8V       1.62V      1.89V
110.4ns   1.727V     1.623V     1.297V
158.3ns   1.481V     1.62V      727mV
197.9ns   1.232V     1.605V     103.2mV
208.8ns   1.16V      1.597V     33.13mV
333.7ns   119.1mV    1.357V     5.815mV
351.3ns   45.06mV    1.309V     5.604mV
570.7ns   7.576mV    631.2mV    4.791mV
694.8ns   6.737mV    112.8mV    4.703mV
788.8ns   6.005mV    8.936mV    4.644mV
[Falling Waveform]
R_fixture = 50
V_fixture = 1.8
V_fixture_min = 1.62
V_fixture_max = 1.89
55.66ns   1.8V       1.62V      1.89V
138.7ns   1.718V     1.62V      1.245V
187.9ns   1.518V     1.619V     724.2mV
226.2ns   1.33V      1.613V     206.6mV
253.7ns   1.185V     1.603V     85.66mV
334.5ns   712.8mV    1.522V     47.42mV
397.9ns   237.3mV    1.417V     41.82mV
445.4ns   114.7mV    1.327V     39.83mV
901.7ns   52.71mV    231.3mV    36.34mV
1.301us   50.09mV    80.58mV    36.22mV
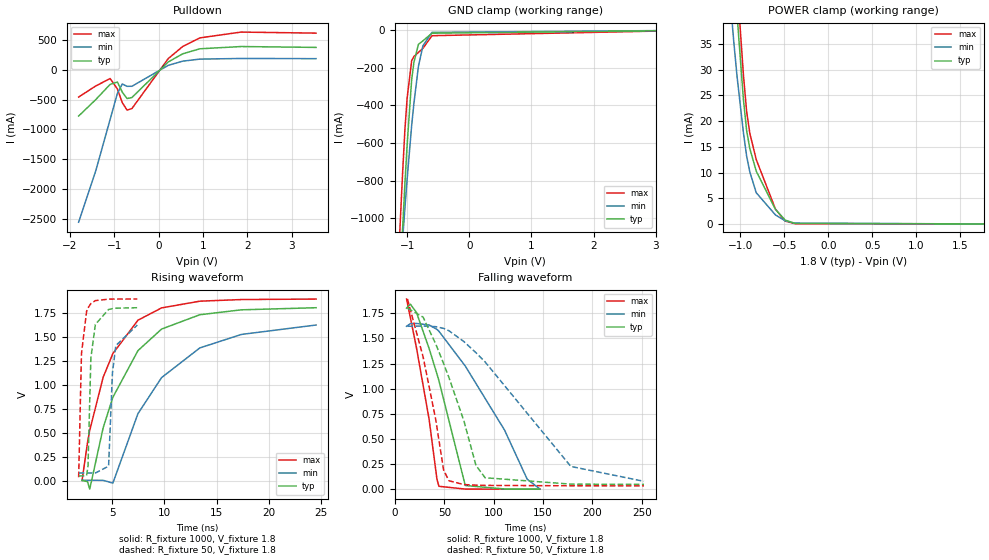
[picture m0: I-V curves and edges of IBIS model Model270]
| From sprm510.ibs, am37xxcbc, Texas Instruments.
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| Model based on original model for BQOMAPI2CHYFBPBRESNOPM_SSBHV
|   Sub model BQOMAPI2CHYRES_SLV_PON_00_1P8
[model]   Model270
|[Input Load]   PU
|[Output Drive] LB00
|Voltage   1.8V
|Mode   I/O_OPEN_DRAIN
Model_type   I/O_open_drain
Polarity   Non-Inverting
Enable   Active-Low
Vinl =  0.567
Vinh =  1.323
Cref =  400.0000PF
Rref =  1000.0000
Vref =  1.8V
Vmeas =  0.9
C_comp   3.856143p   3.721565p   3.857354p
[Model Spec]
Vinl   0.567   0.567   0.567
Vinh   1.323   1.323   1.323
[Temperature Range]   25   125   -40
[Voltage Range]   1.8   1.62   1.89
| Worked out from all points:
|   slope of the pulldown table from 0 to 0.27 V, typ, clamps not added: 1.71 ohm
|   GND clamp passes 1 mA (typ) near -0.44 V on its own axis
|   POWER clamp passes 1 mA (typ) near -0.51 V on its own axis
|   rising waveform, R_fixture 1000, V_fixture 1.8: 20-80 % time 4.46ns typ, 5.95ns min, 3.48ns max; typ from 0.004 V to 1.8 V
|   rising waveform, R_fixture 50, V_fixture 1.8: 20-80 % time 357ps typ, 399ps min, 324ps max; typ from 0.05 V to 1.8 V
|   falling waveform, R_fixture 1000, V_fixture 1.8: 20-80 % time 29.9ns typ, 57.7ns min, 19.5ns max; typ from 1.8 V to 0.004 V
|   falling waveform, R_fixture 50, V_fixture 1.8: 20-80 % time 36.4ns typ, 77.4ns min, 22.1ns max; typ from 1.8 V to 0.05 V
[POWER_clamp]
-1.8V     401.1mA    209.4mA    454.2mA
-1.145V   79.39mA    49.82mA    86.39mA
-1.073V   52.49mA    35.39mA    58.76mA
-1.036V   40.67mA    28.68mA    46.87mA
-963.6mV  24.19mA    17.73mA    28.97mA
-927.3mV  18.17mA    13.19mA    21.87mA
-890.9mV  14.63mA    10.1mA     17.61mA
-818.2mV  10.26mA    6.071mA    12.52mA
-600mV    2.834mA    1.747mA    2.888mA
-490.9mV  760.8uA    616.2uA    563.4uA
-381.8mV  112.8uA    147.2uA    57.34uA
1.764V    -11.66nA   -1.927uA   -18.08nA
[Pulldown]
-1.8V     -777.1mA   -2.558A    -458.5mA
-1.418V   -503.8mA   -1.705A    -274.4mA
-1.091V   -246.4mA   -833.4mA   -147.9mA
-927.3mV  -206.9mA   -396.4mA   -323.2mA
-818.2mV  -375.8mA   -240.8mA   -551.8mA
-709.1mV  -483.8mA   -278.7mA   -678.8mA
-600mV    -466.3mA   -277.9mA   -650.8mA
218.2mV   130.6mA    73.31mA    187mA
545.5mV   267mA      143.7mA    390.8mA
927.3mV   350.5mA    177.6mA    533.7mA
1.855V    388.5mA    188.2mA    630.9mA
3.545V    374.1mA    185.3mA    613.5mA
[GND_clamp]
-1.8V     -6.905A    -5.48A     -6.849A
-1.145V   -1.563A    -1.472A    -1.273A
-1.109V   -1.305A    -1.292A    -1.009A
-1.073V   -1.058A    -1.118A    -761.8mA
-1.036V   -819.4mA   -948.6mA   -530.3mA
-1V       -610.5mA   -793.2mA   -361.6mA
-927.3mV  -263.9mA   -507.2mA   -161.9mA
-890.9mV  -170.2mA   -389mA     -139.4mA
-818.2mV  -74.8mA    -191.7mA   -117.8mA
-745.5mV  -55.76mA   -81.74mA   -95.49mA
-600mV    -15.41mA   -10.81mA   -28.59mA
3.6V      0A         0A         0A
[Ramp]
dV/dt_f  1.0946039/31.313831n 0.97685958/60.512012n  1.1564572/20.34264n
dV/dt_r 0.35693084/3.5439282n 0.23882204/4.7016517n  0.4435731/2.8141337n
R_load = 528.0
[Rising Waveform]
R_fixture = 1000
V_fixture = 1.8
V_fixture_min = 1.62
V_fixture_max = 1.89
2.136ns   3.896mV    5.366mV    3.171mV
2.659ns   -9.584mV   5.365mV    398.1mV
2.869ns   -87.57mV   5.365mV    524mV
4.155ns   551.3mV    4.481mV    1.077V
5.082ns   868.3mV    -24.41mV   1.323V
7.477ns   1.353V     697.2mV    1.67V
9.739ns   1.578V     1.073V     1.798V
13.4ns    1.727V     1.382V     1.868V
17.37ns   1.778V     1.522V     1.885V
24.51ns   1.8V       1.62V      1.89V
[Rising Waveform]
R_fixture = 50
V_fixture = 1.8
V_fixture_min = 1.62
V_fixture_max = 1.89
1.81ns    50.41mV    80.94mV    36.49mV
2.079ns   50.41mV    80.94mV    1.321V
2.572ns   54.56mV    80.94mV    1.763V
2.704ns   151.6mV    80.94mV    1.798V
2.978ns   1.275V     80.94mV    1.843V
3.409ns   1.626V     80.95mV    1.874V
4.674ns   1.782V     151.6mV    1.889V
5.042ns   1.79V      1.122V     1.89V
5.367ns   1.795V     1.406V     1.89V
7.419ns   1.8V       1.62V      1.89V
[Falling Waveform]
R_fixture = 1000
V_fixture = 1.8
V_fixture_min = 1.62
V_fixture_max = 1.89
11.64ns   1.8V       1.62V      1.89V
15.5ns    1.839V     1.646V     1.706V
21.69ns   1.757V     1.648V     1.406V
34.47ns   1.4V       1.633V     697.8mV
42.38ns   1.148V     1.589V     105.9mV
44.38ns   1.082V     1.571V     31.62mV
71.14ns   39.38mV    1.225V     3.963mV
111ns     5.075mV    588.3mV    3.309mV
133.9ns   4.447mV    101.3mV    3.231mV
146.7ns   3.896mV    5.366mV    3.171mV
[Falling Waveform]
R_fixture = 50
V_fixture = 1.8
V_fixture_min = 1.62
V_fixture_max = 1.89
12.54ns   1.8V       1.62V      1.89V
28.43ns   1.71V      1.622V     1.315V
41.11ns   1.446V     1.616V     698.6mV
49.16ns   1.25V      1.599V     193.5mV
54.55ns   1.112V     1.576V     86.41mV
69.78ns   679.8mV    1.468V     48.69mV
81.99ns   237.8mV    1.357V     42.71mV
91.21ns   116.5mV    1.266V     40.54mV
178.1ns   53.12mV    228.7mV    36.65mV
252.2ns   50.41mV    80.94mV    36.49mV
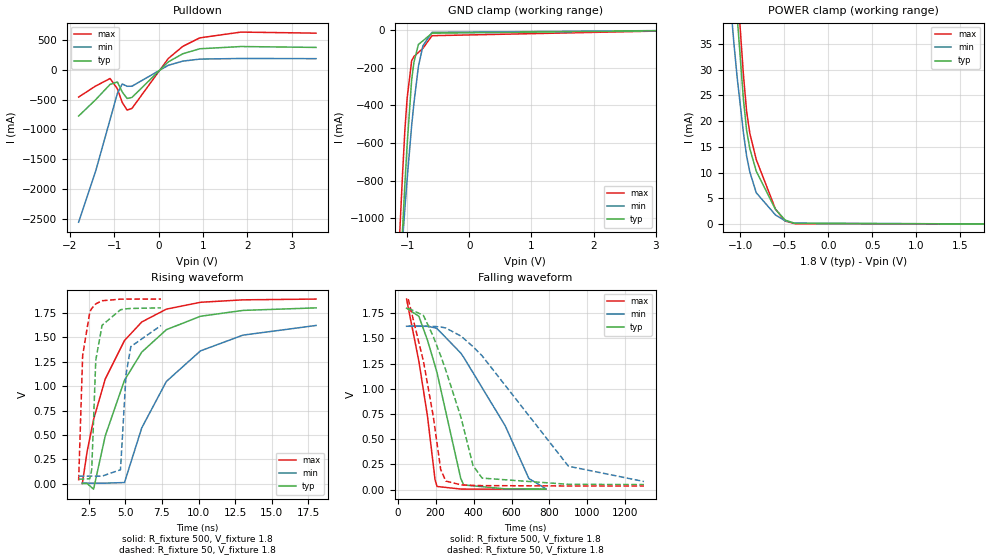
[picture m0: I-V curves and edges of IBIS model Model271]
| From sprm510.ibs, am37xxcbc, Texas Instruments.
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| Model based on original model for BQOMAPI2CHYFBPBRESNOPM_SSBHV
|   Sub model BQOMAPI2CHYRES_STD_PON_00_1P8
[model]   Model271
|[Input Load]   PU
|[Output Drive] LB00
|Voltage   1.8V
|Mode   I/O_OPEN_DRAIN
Model_type   I/O_open_drain
Polarity   Non-Inverting
Enable   Active-Low
Vinl =  0.567
Vinh =  1.323
Cref =  400.0000PF
Rref =  500.0000
Vref =  1.8V
Vmeas =  0.9
C_comp   3.856143p   3.721565p   3.857354p
[Model Spec]
Vinl   0.567   0.567   0.567
Vinh   1.323   1.323   1.323
[Temperature Range]   25   125   -40
[Voltage Range]   1.8   1.62   1.89
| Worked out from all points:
|   slope of the pulldown table from 0 to 0.27 V, typ, clamps not added: 1.71 ohm
|   GND clamp passes 1 mA (typ) near -0.44 V on its own axis
|   POWER clamp passes 1 mA (typ) near -0.51 V on its own axis
|   rising waveform, R_fixture 500, V_fixture 1.8: 20-80 % time 3.25ns typ, 3.91ns min, 2.72ns max; typ from 0.005 V to 1.8 V
|   rising waveform, R_fixture 50, V_fixture 1.8: 20-80 % time 365ps typ, 405ps min, 333ps max; typ from 0.049 V to 1.8 V
|   falling waveform, R_fixture 500, V_fixture 1.8: 20-80 % time 144ns typ, 288ns min, 91.2ns max; typ from 1.8 V to 0.005 V
|   falling waveform, R_fixture 50, V_fixture 1.8: 20-80 % time 173ns typ, 379ns min, 102ns max; typ from 1.8 V to 0.049 V
[POWER_clamp]
-1.8V     401.1mA    209.4mA    454.2mA
-1.145V   79.39mA    49.82mA    86.39mA
-1.073V   52.49mA    35.39mA    58.76mA
-1.036V   40.67mA    28.68mA    46.87mA
-963.6mV  24.19mA    17.73mA    28.97mA
-927.3mV  18.17mA    13.19mA    21.87mA
-890.9mV  14.63mA    10.1mA     17.61mA
-818.2mV  10.26mA    6.071mA    12.52mA
-600mV    2.834mA    1.747mA    2.888mA
-490.9mV  760.8uA    616.2uA    563.4uA
-381.8mV  112.8uA    147.2uA    57.34uA
1.764V    -11.66nA   -1.927uA   -18.08nA
[Pulldown]
-1.8V     -777mA     -2.558A    -458.4mA
-1.418V   -503.6mA   -1.704A    -274.2mA
-1.091V   -246.1mA   -833.2mA   -147.5mA
-927.3mV  -206.1mA   -396.1mA   -321.7mA
-818.2mV  -374.6mA   -240.3mA   -550mA
-709.1mV  -482.9mA   -278.1mA   -677.4mA
-600mV    -465.4mA   -277.4mA   -649.6mA
218.2mV   131.1mA    73.64mA    187.8mA
545.5mV   267.4mA    143.9mA    391.4mA
927.3mV   350.9mA    177.7mA    534.1mA
1.855V    388.5mA    188.1mA    630.8mA
3.545V    373.8mA    185.1mA    613mA
[GND_clamp]
-1.8V     -6.905A    -5.48A     -6.849A
-1.145V   -1.563A    -1.472A    -1.273A
-1.109V   -1.305A    -1.292A    -1.009A
-1.073V   -1.058A    -1.118A    -761.8mA
-1.036V   -819.4mA   -948.6mA   -530.3mA
-1V       -610.5mA   -793.2mA   -361.6mA
-927.3mV  -263.9mA   -507.2mA   -161.9mA
-890.9mV  -170.2mA   -389mA     -139.4mA
-818.2mV  -74.8mA    -191.7mA   -117.8mA
-745.5mV  -55.76mA   -81.74mA   -95.49mA
-600mV    -15.41mA   -10.81mA   -28.59mA
3.6V      0A         0A         0A
[Ramp]
dV/dt_f  1.0811738/0.14453781u 0.96934606/0.28745378u  1.1383487/91.754061n
dV/dt_r 0.23352613/4.1714169n 0.16346714/5.2220012n 0.29160122/3.4118755n
R_load = 528.00
[Rising Waveform]
R_fixture = 500
V_fixture = 1.8
V_fixture_min = 1.62
V_fixture_max = 1.89
2.063ns   5.399mV    8.349mV    4.056mV
2.392ns   4.358mV    8.349mV    332.3mV
2.831ns   -53.33mV   8.348mV    659.9mV
3.627ns   490.9mV    8.35mV     1.072V
4.942ns   1.06V      14.23mV    1.466V
6.124ns   1.348V     573.8mV    1.656V
7.805ns   1.577V     1.048V     1.787V
10.13ns   1.714V     1.36V      1.857V
13.03ns   1.774V     1.521V     1.882V
18.03ns   1.8V       1.62V      1.89V
[Rising Waveform]
R_fixture = 50
V_fixture = 1.8
V_fixture_min = 1.62
V_fixture_max = 1.89
1.811ns   49.48mV    79.98mV    35.63mV
2.085ns   49.48mV    79.98mV    1.315V
2.576ns   53.74mV    79.98mV    1.758V
2.705ns   146.7mV    79.98mV    1.794V
2.981ns   1.265V     79.98mV    1.841V
3.412ns   1.622V     79.98mV    1.873V
4.67ns    1.781V     145mV      1.889V
5.049ns   1.79V      1.12V      1.89V
5.375ns   1.794V     1.404V     1.89V
7.437ns   1.8V       1.62V      1.89V
[Falling Waveform]
R_fixture = 500
V_fixture = 1.8
V_fixture_min = 1.62
V_fixture_max = 1.89
46.59ns   1.8V       1.62V      1.89V
111.5ns   1.719V     1.623V     1.273V
157ns     1.481V     1.62V      726.6mV
196.7ns   1.229V     1.605V     98.3mV
207.3ns   1.158V     1.597V     30.82mV
332ns     112.3mV    1.355V     5.091mV
347.2ns   46.14mV    1.314V     4.926mV
566.9ns   6.837mV    631.4mV    4.187mV
691.4ns   6.066mV    109.6mV    4.109mV
780.8ns   5.399mV    8.349mV    4.056mV
[Falling Waveform]
R_fixture = 50
V_fixture = 1.8
V_fixture_min = 1.62
V_fixture_max = 1.89
55.57ns   1.8V       1.62V      1.89V
135.9ns   1.726V     1.62V      1.27V
187.2ns   1.52V      1.619V     729.3mV
226.4ns   1.327V     1.613V     199.7mV
253.3ns   1.185V     1.603V     84.46mV
334.1ns   712.1mV    1.522V     46.67mV
396.9ns   238.7mV    1.418V     41.16mV
444.7ns   113.7mV    1.327V     39.2mV
899.8ns   52.08mV    231.7mV    35.75mV
1.298us   49.48mV    79.98mV    35.63mV
